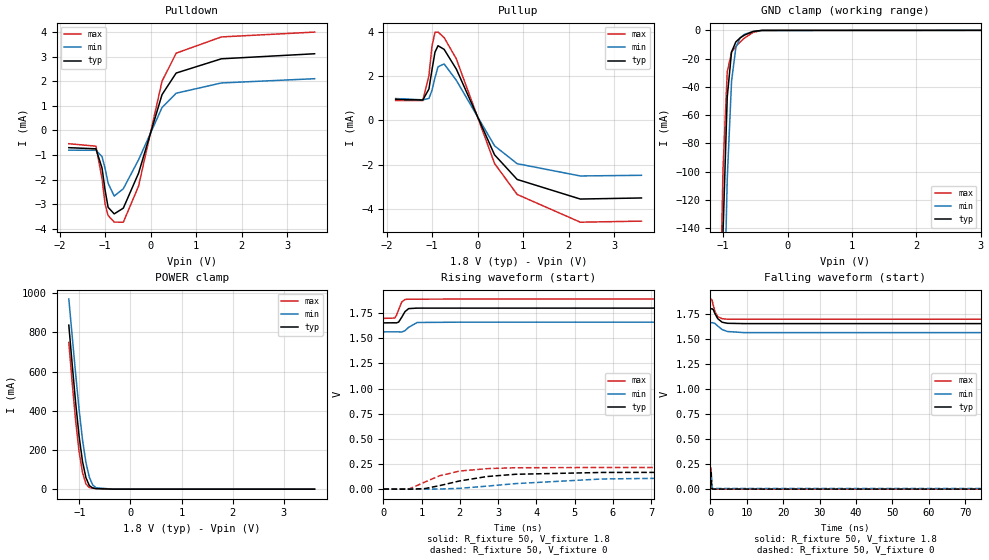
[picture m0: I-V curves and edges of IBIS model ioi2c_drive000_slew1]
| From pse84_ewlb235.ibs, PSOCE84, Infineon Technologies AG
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[Model] ioi2c_drive000_slew1
Model_type I/O
Enable   Active-High
Vinl  =  0.54
Vinh  =  1.26
Vmeas =  0.9
Cref  =  15e-12
| Capacitance   typ   min   max
C_comp   8.55364e-13 8.30808e-13 8.84570e-13
| Variables   typ   min   max
[GND Clamp Reference]   0   0   0
[POWER Clamp Reference]   1.8   1.66   1.89
[Pulldown Reference]   0   0   0
[Pullup Reference]   1.8   1.66   1.89
[Temperature Range]   25   125   -40
[Voltage Range]   1.8   1.66   1.89
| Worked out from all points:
|   slope of the pulldown table from 0 to 0.27 V, typ, clamps not added: 175 ohm
|   slope of the pullup table from 0 to 0.27 V, typ, clamps not added: 228 ohm
|   GND clamp passes 1 mA (typ) near -0.55 V on its own axis
|   POWER clamp passes 1 mA (typ) near -0.55 V on its own axis
|   falling waveform, R_fixture 50, V_fixture 1.8: 20-80 % time 1.44ns typ, 2.16ns min, 1.01ns max; typ from 1.8 V to 1.65 V
|   falling waveform, R_fixture 50, V_fixture 0: 20-80 % time 68.2ps typ, 75.6ps min, 64.3ps max; typ from 0.166 V to 0 V
|   rising waveform, R_fixture 50, V_fixture 1.8: 20-80 % time 135ps typ, 179ps min, 114ps max; typ from 1.65 V to 1.8 V
|   rising waveform, R_fixture 50, V_fixture 0: 20-80 % time 1.45ns typ, 2.62ns min, 924ps max; typ from 0 V to 0.166 V
[GND Clamp]
| Voltage   I(typ)   I(min)   I(max)
-1.204V   -750.5mA   -844.3mA   -692.2mA
-1.07V    -311.8mA   -416.8mA   -250.3mA
-1.003V   -144.6mA   -236.7mA   -99.35mA
-936.6mV  -47.15mA   -105.3mA   -29.57mA
-869.7mV  -15.32mA   -36.11mA   -15.4mA
-802.8mV  -8.178mA   -12.13mA   -11.32mA
-735.9mV  -5.345mA   -5.294mA   -8.218mA
-669mV    -3.361mA   -2.852mA   -5.471mA
-535.2mV  -838.5uA   -772.4uA   -1.486mA
-401.4mV  -47.36uA   -84.85uA   -76.78uA
3.6V      0A         0A         0A
[POWER Clamp]
| Voltage   I(typ)   I(min)   I(max)
-1.204V   837.3mA    970.7mA    749.2mA
-1.137V   634.9mA    778.2mA    540.5mA
-1.07V    440.1mA    587.4mA    346.5mA
-1.003V   270mA      407mA      190.9mA
-936.6mV  141.8mA    252.7mA    85.92mA
-869.7mV  58.74mA    136.5mA    26.66mA
-802.8mV  18.35mA    60.36mA    8.197mA
-735.9mV  5.885mA    21mA       4.755mA
-669mV    2.866mA    6.628mA    3.138mA
-334.5mV  12.31uA    45.7uA     5.857uA
3.6V      0A         0A         0A
[Pulldown]
| Voltage   I(typ)   I(min)   I(max)
-1.8V     -703.5uA   -804.7uA   -543.5uA
-1.204V   -750.4uA   -810.1uA   -642.3uA
-1.07V    -1.533mA   -1.068mA   -1.965mA
-1.003V   -2.436mA   -1.548mA   -2.997mA
-936.6mV  -3.129mA   -2.15mA    -3.46mA
-802.8mV  -3.395mA   -2.671mA   -3.729mA
-602.1mV  -3.161mA   -2.372mA   -3.733mA
-267.6mV  -1.741mA   -1.195mA   -2.266mA
248.3mV   1.454mA    928.2uA    1.997mA
558.6mV   2.33mA     1.51mA     3.138mA
1.552V    2.909mA    1.927mA    3.798mA
3.6V      3.114mA    2.1mA      3.995mA
[Pullup]
| Voltage   I(typ)   I(min)   I(max)
-1.8V     951.6uA    988.4uA    898.4uA
-1.204V   923.4uA    929.7uA    894.6uA
-1.07V    1.418mA    994.1uA    2.027mA
-1.003V   2.286mA    1.356mA    3.351mA
-936.6mV  3.088mA    1.934mA    3.984mA
-869.7mV  3.379mA    2.427mA    3.995mA
-735.9mV  3.214mA    2.555mA    3.747mA
-468.3mV  2.324mA    1.816mA    2.785mA
372.4mV   -1.557mA   -1.149mA   -1.949mA
869mV     -2.67mA    -1.957mA   -3.349mA
2.256V    -3.556mA   -2.512mA   -4.603mA
3.6V      -3.507mA   -2.482mA   -4.555mA
[Ramp]
dV/dt_r   99.4336m/1.45408n  70.1228m/2.6179n  0.128322/0.923527n
dV/dt_f   87.9625m/1.43945n  57.8563m/2.15508n  0.115304/1.01328n
R_load = 50
[Falling Waveform]
R_fixture = 50
V_fixture = 1.8
V_fixture_min = 1.66
V_fixture_max = 1.89
| Time   V(typ)   V(min)   V(max)
0s        1.8V       1.66V      1.89V
260.5ps   1.8V       1.66V      1.898V
490.5ps   1.801V     1.663V     1.887V
814.7ps   1.793V     1.66V      1.838V
1.274ns   1.754V     1.655V     1.774V
2.032ns   1.703V     1.629V     1.723V
3.232ns   1.667V     1.594V     1.702V
4.705ns   1.656V     1.574V     1.697V
9.277ns   1.653V     1.563V     1.697V
800ns     1.653V     1.564V     1.698V
[Falling Waveform]
R_fixture = 50
V_fixture = 0
V_fixture_min = 0
V_fixture_max = 0
| Time   V(typ)   V(min)   V(max)
0s        165.7mV    116.9mV    213.9mV
206.8ps   165.6mV    116.9mV    212.2mV
229ps     165.4mV    116.9mV    185.2mV
271.5ps   164.8mV    116.9mV    82.32mV
313.6ps   114.5mV    116.6mV    31mV
346.5ps   58.21mV    117.3mV    14.56mV
381.3ps   26.77mV    113.7mV    6.74mV
475.2ps   3.513mV    29.3mV     494.8uV
542.3ps   656.7uV    7.037mV    235uV
800ns     16.91nV    963.9nV    7.235nV
[Rising Waveform]
R_fixture = 50
V_fixture = 1.8
V_fixture_min = 1.66
V_fixture_max = 1.89
| Time   V(typ)   V(min)   V(max)
0s        1.653V     1.564V     1.698V
295.6ps   1.654V     1.564V     1.701V
341.2ps   1.653V     1.564V     1.728V
398.2ps   1.661V     1.564V     1.783V
481ps     1.71V      1.562V     1.862V
564.9ps   1.765V     1.576V     1.886V
660.3ps   1.795V     1.609V     1.889V
884.1ps   1.8V       1.657V     1.889V
1.947ns   1.8V       1.66V      1.89V
800ns     1.8V       1.66V      1.89V
[Rising Waveform]
R_fixture = 50
V_fixture = 0
V_fixture_min = 0
V_fixture_max = 0
| Time   V(typ)   V(min)   V(max)
0s        16.91nV    963.7nV    7.235nV
688.1ps   -868.5uV   -900.8uV   3.036mV
1.085ns   4.938mV    -221.7uV   69.95mV
1.469ns   34.26mV    435.7uV    132.4mV
1.994ns   80.83mV    7.366mV    179.3mV
2.711ns   124.9mV    29.17mV    203.3mV
3.455ns   147.2mV    54.25mV    212mV
5.728ns   165.4mV    100.7mV    214.9mV
9.629ns   166.7mV    116.7mV    214.3mV
50ns      165.7mV    116.9mV    213.9mV
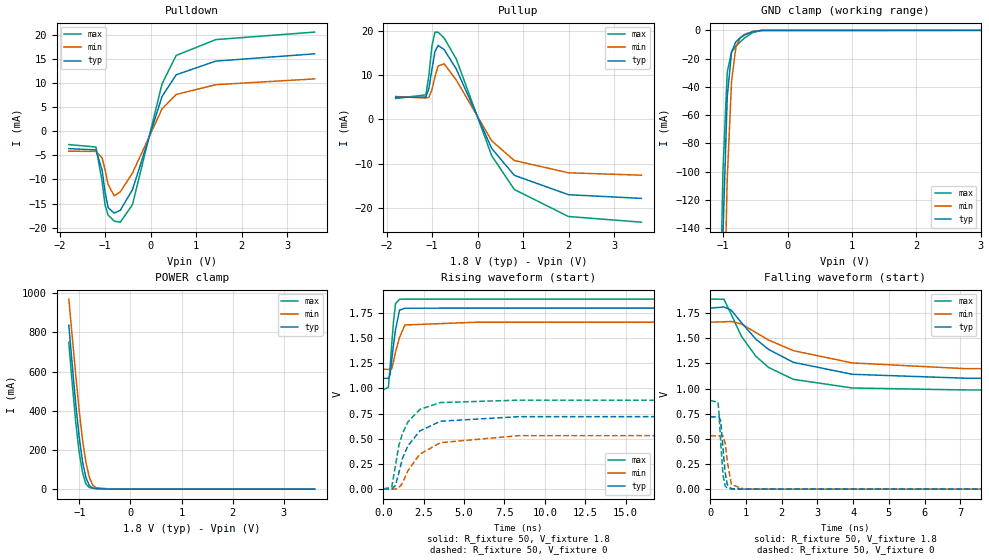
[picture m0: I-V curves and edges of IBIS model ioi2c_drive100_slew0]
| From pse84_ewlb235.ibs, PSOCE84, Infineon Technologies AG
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[Model] ioi2c_drive100_slew0
Model_type I/O
Enable   Active-High
Vinl  =  0.54
Vinh  =  1.26
Vmeas =  0.9
Cref  =  15e-12
| Capacitance   typ   min   max
C_comp   8.55364e-13 8.30808e-13 8.84570e-13
| Variables   typ   min   max
[GND Clamp Reference]   0   0   0
[POWER Clamp Reference]   1.8   1.66   1.89
[Pulldown Reference]   0   0   0
[Pullup Reference]   1.8   1.66   1.89
[Temperature Range]   25   125   -40
[Voltage Range]   1.8   1.66   1.89
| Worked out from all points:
|   slope of the pulldown table from 0 to 0.27 V, typ, clamps not added: 35.3 ohm
|   slope of the pullup table from 0 to 0.27 V, typ, clamps not added: 46.3 ohm
|   GND clamp passes 1 mA (typ) near -0.55 V on its own axis
|   POWER clamp passes 1 mA (typ) near -0.55 V on its own axis
|   falling waveform, R_fixture 50, V_fixture 1.8: 20-80 % time 1.64ns typ, 2.15ns min, 1.21ns max; typ from 1.8 V to 1.1 V
|   falling waveform, R_fixture 50, V_fixture 0: 20-80 % time 103ps typ, 119ps min, 94.2ps max; typ from 0.719 V to 0 V
|   rising waveform, R_fixture 50, V_fixture 1.8: 20-80 % time 331ps typ, 473ps min, 255ps max; typ from 1.1 V to 1.8 V
|   rising waveform, R_fixture 50, V_fixture 0: 20-80 % time 1.31ns typ, 1.65ns min, 975ps max; typ from 0 V to 0.719 V
[GND Clamp]
| Voltage   I(typ)   I(min)   I(max)
-1.204V   -750.5mA   -844.3mA   -692.2mA
-1.07V    -311.8mA   -416.8mA   -250.3mA
-1.003V   -144.6mA   -236.7mA   -99.35mA
-936.6mV  -47.15mA   -105.3mA   -29.57mA
-869.7mV  -15.32mA   -36.11mA   -15.4mA
-802.8mV  -8.178mA   -12.13mA   -11.32mA
-735.9mV  -5.345mA   -5.294mA   -8.218mA
-669mV    -3.361mA   -2.852mA   -5.471mA
-535.2mV  -838.5uA   -772.4uA   -1.486mA
-401.4mV  -47.36uA   -84.85uA   -76.78uA
3.6V      0A         0A         0A
[POWER Clamp]
| Voltage   I(typ)   I(min)   I(max)
-1.204V   837.3mA    970.7mA    749.2mA
-1.137V   634.9mA    778.2mA    540.5mA
-1.07V    440.1mA    587.4mA    346.5mA
-1.003V   270mA      407mA      190.9mA
-936.6mV  141.8mA    252.7mA    85.92mA
-869.7mV  58.74mA    136.5mA    26.66mA
-802.8mV  18.35mA    60.36mA    8.197mA
-735.9mV  5.885mA    21mA       4.755mA
-669mV    2.866mA    6.628mA    3.138mA
-334.5mV  12.31uA    45.7uA     5.857uA
3.6V      0A         0A         0A
[Pulldown]
| Voltage   I(typ)   I(min)   I(max)
-1.8V     -3.608mA   -4.143mA   -2.775mA
-1.204V   -3.867mA   -4.18mA    -3.269mA
-1.07V    -8mA       -5.505mA   -10.32mA
-1.003V   -12.65mA   -8.02mA    -15.35mA
-936.6mV  -15.86mA   -11.04mA   -17.4mA
-802.8mV  -16.98mA   -13.4mA    -18.65mA
-669mV    -16.4mA    -12.58mA   -18.87mA
-401.4mV  -12.13mA   -8.671mA   -15.23mA
248.3mV   7.209mA    4.643mA    9.816mA
558.6mV   11.71mA    7.622mA    15.72mA
1.428V    14.55mA    9.657mA    19.01mA
3.6V      16.06mA    10.86mA    20.57mA
[Pullup]
| Voltage   I(typ)   I(min)   I(max)
-1.8V     5.02mA     5.202mA    4.747mA
-1.137V   5.07mA     4.844mA    5.585mA
-1.07V    7.067mA    5.033mA    10.06mA
-1.003V   11.43mA    6.798mA    16.72mA
-936.6mV  15.41mA    9.704mA    19.82mA
-869.7mV  16.78mA    12.12mA    19.79mA
-735.9mV  15.86mA    12.64mA    18.49mA
-468.3mV  11.44mA    8.947mA    13.7mA
310.3mV   -6.586mA   -4.859mA   -8.233mA
806.9mV   -12.68mA   -9.32mA    -15.89mA
1.996V    -17.07mA   -12.1mA    -22.02mA
3.6V      -17.91mA   -12.65mA   -23.31mA
[Ramp]
dV/dt_r   0.431323/1.30748n  0.318025/1.65257n  0.529265/0.975074n
dV/dt_f   0.41961/1.63536n  0.281431/2.15218n  0.541745/1.20773n
R_load = 50
[Falling Waveform]
R_fixture = 50
V_fixture = 1.8
V_fixture_min = 1.66
V_fixture_max = 1.89
| Time   V(typ)   V(min)   V(max)
0s        1.8V       1.66V      1.89V
382.3ps   1.811V     1.664V     1.888V
583.8ps   1.781V     1.667V     1.74V
871.3ps   1.656V     1.642V     1.521V
1.276ns   1.492V     1.557V     1.321V
1.634ns   1.389V     1.483V     1.21V
2.326ns   1.261V     1.377V     1.092V
3.978ns   1.142V     1.255V     1.006V
7.152ns   1.103V     1.198V     986.2mV
800ns     1.101V     1.191V     987.1mV
[Falling Waveform]
R_fixture = 50
V_fixture = 0
V_fixture_min = 0
V_fixture_max = 0
| Time   V(typ)   V(min)   V(max)
0s        718.9mV    530mV      882.1mV
216.6ps   718.6mV    530mV      862.9mV
244.6ps   719.1mV    530mV      755.5mV
294.5ps   675.9mV    529.9mV    451.7mV
357.4ps   403.5mV    530.7mV    140.7mV
417.6ps   161.8mV    456mV      33.4mV
478ps     44.77mV    273.4mV    7.755mV
592.2ps   4.477mV    45.7mV     1.387mV
946.4ps   865uV      950.9uV    607.2uV
800ns     8.443nV    562.7nV    3.204nV
[Rising Waveform]
R_fixture = 50
V_fixture = 1.8
V_fixture_min = 1.66
V_fixture_max = 1.89
| Time   V(typ)   V(min)   V(max)
0s        1.101V     1.191V     987.1mV
307.7ps   1.101V     1.191V     1.012V
411.2ps   1.137V     1.191V     1.204V
511.2ps   1.273V     1.195V     1.429V
624.6ps   1.433V     1.267V     1.663V
752.6ps   1.586V     1.364V     1.845V
999.3ps   1.78V      1.508V     1.888V
1.33ns    1.799V     1.632V     1.889V
5.857ns   1.8V       1.66V      1.89V
800ns     1.8V       1.66V      1.89V
[Rising Waveform]
R_fixture = 50
V_fixture = 0
V_fixture_min = 0
V_fixture_max = 0
| Time   V(typ)   V(min)   V(max)
0s        8.444nV    562.4nV    3.204nV
516.6ps   -2.074mV   -663.5uV   18.93mV
746.4ps   34.48mV    -1.522mV   230.6mV
955.5ps   159.8mV    10.54mV    432.3mV
1.179ns   304.5mV    59.72mV    550.1mV
1.524ns   430.8mV    182.5mV    669mV
2.261ns   577.7mV    346.9mV    791.9mV
3.534ns   673.9mV    460.7mV    860mV
8.374ns   719.5mV    530.6mV    883.6mV
50ns      718.9mV    530mV      882.1mV
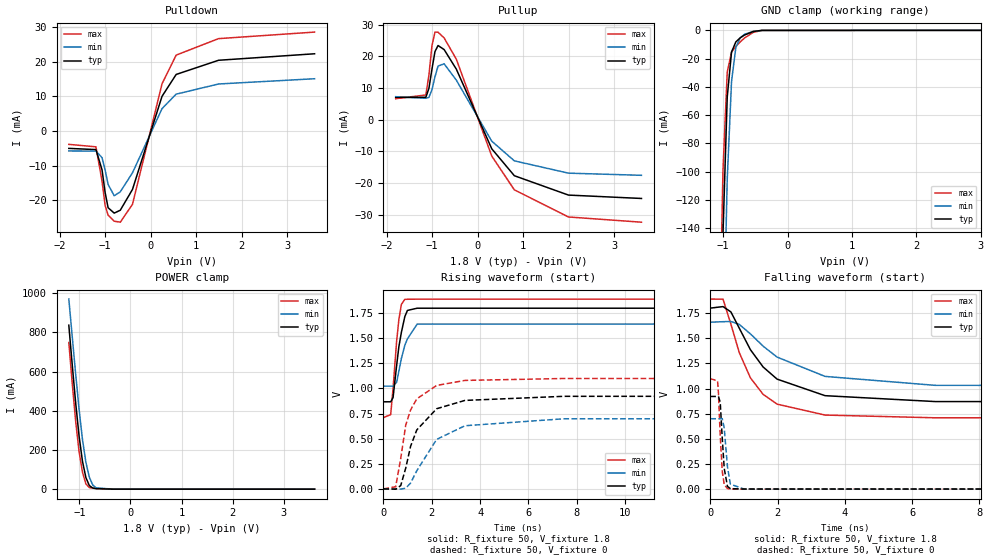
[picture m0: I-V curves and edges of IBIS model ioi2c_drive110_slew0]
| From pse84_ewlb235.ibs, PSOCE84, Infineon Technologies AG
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[Model] ioi2c_drive110_slew0
Model_type I/O
Enable   Active-High
Vinl  =  0.54
Vinh  =  1.26
Vmeas =  0.9
Cref  =  15e-12
| Capacitance   typ   min   max
C_comp   8.55364e-13 8.30808e-13 8.84570e-13
| Variables   typ   min   max
[GND Clamp Reference]   0   0   0
[POWER Clamp Reference]   1.8   1.66   1.89
[Pulldown Reference]   0   0   0
[Pullup Reference]   1.8   1.66   1.89
[Temperature Range]   25   125   -40
[Voltage Range]   1.8   1.66   1.89
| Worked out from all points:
|   slope of the pulldown table from 0 to 0.27 V, typ, clamps not added: 25.3 ohm
|   slope of the pullup table from 0 to 0.27 V, typ, clamps not added: 33.2 ohm
|   GND clamp passes 1 mA (typ) near -0.55 V on its own axis
|   POWER clamp passes 1 mA (typ) near -0.55 V on its own axis
|   falling waveform, R_fixture 50, V_fixture 1.8: 20-80 % time 1.35ns typ, 1.84ns min, 960ps max; typ from 1.8 V to 0.867 V
|   falling waveform, R_fixture 50, V_fixture 0: 20-80 % time 100ps typ, 115ps min, 93ps max; typ from 0.922 V to 0 V
|   rising waveform, R_fixture 50, V_fixture 1.8: 20-80 % time 314ps typ, 442ps min, 241ps max; typ from 0.867 V to 1.8 V
|   rising waveform, R_fixture 50, V_fixture 0: 20-80 % time 944ps typ, 1.3ns min, 660ps max; typ from 0 V to 0.922 V
[GND Clamp]
| Voltage   I(typ)   I(min)   I(max)
-1.204V   -750.5mA   -844.3mA   -692.2mA
-1.07V    -311.8mA   -416.8mA   -250.3mA
-1.003V   -144.6mA   -236.7mA   -99.35mA
-936.6mV  -47.15mA   -105.3mA   -29.57mA
-869.7mV  -15.32mA   -36.11mA   -15.4mA
-802.8mV  -8.178mA   -12.13mA   -11.32mA
-735.9mV  -5.345mA   -5.294mA   -8.218mA
-669mV    -3.361mA   -2.852mA   -5.471mA
-535.2mV  -838.5uA   -772.4uA   -1.486mA
-401.4mV  -47.36uA   -84.85uA   -76.78uA
3.6V      0A         0A         0A
[POWER Clamp]
| Voltage   I(typ)   I(min)   I(max)
-1.204V   837.3mA    970.7mA    749.2mA
-1.137V   634.9mA    778.2mA    540.5mA
-1.07V    440.1mA    587.4mA    346.5mA
-1.003V   270mA      407mA      190.9mA
-936.6mV  141.8mA    252.7mA    85.92mA
-869.7mV  58.74mA    136.5mA    26.66mA
-802.8mV  18.35mA    60.36mA    8.197mA
-735.9mV  5.885mA    21mA       4.755mA
-669mV    2.866mA    6.628mA    3.138mA
-334.5mV  12.31uA    45.7uA     5.857uA
3.6V      0A         0A         0A
[Pulldown]
| Voltage   I(typ)   I(min)   I(max)
-1.8V     -5.031mA   -5.777mA   -3.872mA
-1.204V   -5.388mA   -5.825mA   -4.584mA
-1.07V    -11.24mA   -7.714mA   -14.52mA
-1.003V   -17.74mA   -11.24mA   -21.49mA
-936.6mV  -22.2mA    -15.46mA   -24.36mA
-802.8mV  -23.75mA   -18.74mA   -26.09mA
-669mV    -22.92mA   -17.59mA   -26.38mA
-401.4mV  -16.91mA   -12.1mA    -21.21mA
248.3mV   10.03mA    6.478mA    13.65mA
558.6mV   16.35mA    10.65mA    21.94mA
1.49V     20.45mA    13.59mA    26.71mA
3.6V      22.33mA    15.11mA    28.6mA
[Pullup]
| Voltage   I(typ)   I(min)   I(max)
-1.8V     7.005mA    7.261mA    6.626mA
-1.137V   7.083mA    6.76mA     7.811mA
-1.07V    9.886mA    7.034mA    14.08mA
-1.003V   15.99mA    9.505mA    23.38mA
-936.6mV  21.53mA    13.57mA    27.68mA
-869.7mV  23.43mA    16.94mA    27.64mA
-735.9mV  22.16mA    17.65mA    25.83mA
-468.3mV  15.98mA    12.5mA     19.13mA
310.3mV   -9.196mA   -6.788mA   -11.49mA
806.9mV   -17.72mA   -13.02mA   -22.19mA
1.996V    -23.84mA   -16.91mA   -30.76mA
3.6V      -24.91mA   -17.59mA   -32.41mA
[Ramp]
dV/dt_r   0.553161/0.943874n  0.420209/1.30167n  0.659218/0.659828n
dV/dt_f   0.559864/1.34707n  0.382426/1.83895n  0.708163/0.960081n
R_load = 50
[Falling Waveform]
R_fixture = 50
V_fixture = 1.8
V_fixture_min = 1.66
V_fixture_max = 1.89
| Time   V(typ)   V(min)   V(max)
0s        1.8V       1.66V      1.89V
379.1ps   1.815V     1.665V     1.889V
613.8ps   1.762V     1.667V     1.64V
863.3ps   1.6V       1.638V     1.357V
1.193ns   1.387V     1.544V     1.107V
1.571ns   1.215V     1.422V     942.9mV
1.987ns   1.094V     1.313V     845.3mV
3.413ns   929.5mV    1.121V     736.7mV
6.699ns   870.8mV    1.032V     709.5mV
800ns     866.9mV    1.023V     709.7mV
[Falling Waveform]
R_fixture = 50
V_fixture = 0
V_fixture_min = 0
V_fixture_max = 0
| Time   V(typ)   V(min)   V(max)
0s        921.9mV    700.3mV    1.099V
217.2ps   921.7mV    700.3mV    1.076V
243.4ps   922.3mV    700.3mV    953.5mV
295.8ps   863.4mV    700.2mV    533.5mV
355.4ps   510.1mV    701.5mV    179.9mV
415.1ps   206.1mV    607mV      44.16mV
511.1ps   27.4mV     222.3mV    5.209mV
597.6ps   5.27mV     50.07mV    1.91mV
1.005ns   1.01mV     1.294mV    657.3uV
800ns     6.766nV    466.7nV    2.504nV
[Rising Waveform]
R_fixture = 50
V_fixture = 1.8
V_fixture_min = 1.66
V_fixture_max = 1.89
| Time   V(typ)   V(min)   V(max)
0s        866.9mV    1.023V     709.7mV
301.7ps   867.1mV    1.023V     739.3mV
399.2ps   908.4mV    1.023V     998.1mV
548ps     1.231V     1.063V     1.473V
640.1ps   1.416V     1.172V     1.686V
743.6ps   1.558V     1.299V     1.836V
885.5ps   1.715V     1.429V     1.887V
994.1ps   1.777V     1.494V     1.888V
1.398ns   1.799V     1.641V     1.889V
800ns     1.8V       1.66V      1.89V
[Rising Waveform]
R_fixture = 50
V_fixture = 0
V_fixture_min = 0
V_fixture_max = 0
| Time   V(typ)   V(min)   V(max)
0s        6.767nV    466.5nV    2.506nV
509.1ps   -2.87mV    -992.1uV   21.44mV
716.8ps   32.64mV    -2.311mV   303.4mV
925.9ps   209.1mV    7.165mV    637.7mV
1.125ns   424.3mV    57.92mV    785.9mV
1.382ns   587.4mV    181.5mV    896.5mV
2.203ns   798.1mV    492.8mV    1.03V
3.372ns   880.8mV    628.6mV    1.08V
7.456ns   921.6mV    697.9mV    1.099V
50ns      921.9mV    700.3mV    1.099V
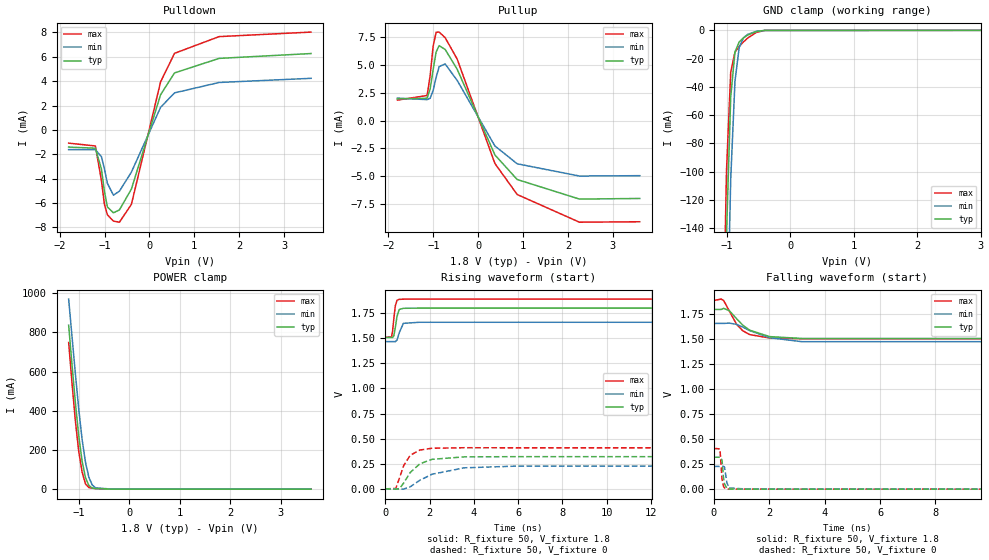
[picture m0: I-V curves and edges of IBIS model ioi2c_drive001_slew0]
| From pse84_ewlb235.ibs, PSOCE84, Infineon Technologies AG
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[Model] ioi2c_drive001_slew0
Model_type I/O
Enable   Active-High
Vinl  =  0.54
Vinh  =  1.26
Vmeas =  0.9
Cref  =  15e-12
| Capacitance   typ   min   max
C_comp   8.55364e-13 8.30808e-13 8.84570e-13
| Variables   typ   min   max
[GND Clamp Reference]   0   0   0
[POWER Clamp Reference]   1.8   1.66   1.89
[Pulldown Reference]   0   0   0
[Pullup Reference]   1.8   1.66   1.89
[Temperature Range]   25   125   -40
[Voltage Range]   1.8   1.66   1.89
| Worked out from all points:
|   slope of the pulldown table from 0 to 0.27 V, typ, clamps not added: 88 ohm
|   slope of the pullup table from 0 to 0.27 V, typ, clamps not added: 115 ohm
|   GND clamp passes 1 mA (typ) near -0.55 V on its own axis
|   POWER clamp passes 1 mA (typ) near -0.55 V on its own axis
|   falling waveform, R_fixture 50, V_fixture 1.8: 20-80 % time 765ps typ, 1.16ns min, 545ps max; typ from 1.8 V to 1.51 V
|   falling waveform, R_fixture 50, V_fixture 0: 20-80 % time 68.2ps typ, 75.4ps min, 64.3ps max; typ from 0.32 V to 0 V
|   rising waveform, R_fixture 50, V_fixture 1.8: 20-80 % time 129ps typ, 168ps min, 111ps max; typ from 1.51 V to 1.8 V
|   rising waveform, R_fixture 50, V_fixture 0: 20-80 % time 768ps typ, 1.4ns min, 488ps max; typ from 0 V to 0.32 V
[GND Clamp]
| Voltage   I(typ)   I(min)   I(max)
-1.204V   -750.5mA   -844.3mA   -692.2mA
-1.07V    -311.8mA   -416.8mA   -250.3mA
-1.003V   -144.6mA   -236.7mA   -99.35mA
-936.6mV  -47.15mA   -105.3mA   -29.57mA
-869.7mV  -15.32mA   -36.11mA   -15.4mA
-802.8mV  -8.178mA   -12.13mA   -11.32mA
-735.9mV  -5.345mA   -5.294mA   -8.218mA
-669mV    -3.361mA   -2.852mA   -5.471mA
-535.2mV  -838.5uA   -772.4uA   -1.486mA
-401.4mV  -47.36uA   -84.85uA   -76.78uA
3.6V      0A         0A         0A
[POWER Clamp]
| Voltage   I(typ)   I(min)   I(max)
-1.204V   837.3mA    970.7mA    749.2mA
-1.137V   634.9mA    778.2mA    540.5mA
-1.07V    440.1mA    587.4mA    346.5mA
-1.003V   270mA      407mA      190.9mA
-936.6mV  141.8mA    252.7mA    85.92mA
-869.7mV  58.74mA    136.5mA    26.66mA
-802.8mV  18.35mA    60.36mA    8.197mA
-735.9mV  5.885mA    21mA       4.755mA
-669mV    2.866mA    6.628mA    3.138mA
-334.5mV  12.31uA    45.7uA     5.857uA
3.6V      0A         0A         0A
[Pulldown]
| Voltage   I(typ)   I(min)   I(max)
-1.8V     -1.409mA   -1.614mA   -1.087mA
-1.204V   -1.504mA   -1.625mA   -1.317mA
-1.07V    -3.21mA    -2.196mA   -4.15mA
-1.003V   -5.04mA    -3.191mA   -6.111mA
-936.6mV  -6.327mA   -4.389mA   -6.969mA
-802.8mV  -6.804mA   -5.354mA   -7.487mA
-669mV    -6.567mA   -5.03mA    -7.575mA
-401.4mV  -4.854mA   -3.463mA   -6.107mA
248.3mV   2.887mA    1.855mA    3.943mA
558.6mV   4.677mA    3.039mA    6.285mA
1.552V    5.87mA     3.893mA    7.658mA
3.6V      6.268mA    4.234mA    8.029mA
[Pullup]
| Voltage   I(typ)   I(min)   I(max)
-1.8V     1.938mA    2.011mA    1.831mA
-1.137V   2mA        1.875mA    2.246mA
-1.07V    2.828mA    1.994mA    4.035mA
-1.003V   4.559mA    2.708mA    6.673mA
-936.6mV  6.148mA    3.862mA    7.917mA
-869.7mV  6.714mA    4.836mA    7.931mA
-735.9mV  6.376mA    5.074mA    7.432mA
-468.3mV  4.604mA    3.601mA    5.514mA
372.4mV   -3.082mA   -2.277mA   -3.851mA
869mV     -5.289mA   -3.879mA   -6.633mA
2.256V    -7.043mA   -4.976mA   -9.115mA
3.6V      -6.988mA   -4.944mA   -9.076mA
[Ramp]
dV/dt_r   0.191949/0.768196n  0.136595/1.40401n  0.245175/0.488465n
dV/dt_f   0.175408/0.764687n  0.115857/1.15646n  0.229172/0.5453n
R_load = 50
[Falling Waveform]
R_fixture = 50
V_fixture = 1.8
V_fixture_min = 1.66
V_fixture_max = 1.89
| Time   V(typ)   V(min)   V(max)
0s        1.8V       1.66V      1.89V
258.7ps   1.8V       1.66V      1.904V
348.1ps   1.811V     1.66V      1.89V
551.1ps   1.788V     1.663V     1.786V
810.9ps   1.709V     1.651V     1.653V
1.037ns   1.643V     1.624V     1.587V
1.291ns   1.592V     1.588V     1.548V
2.011ns   1.528V     1.517V     1.514V
3.179ns   1.509V     1.477V     1.507V
800ns     1.508V     1.467V     1.508V
[Falling Waveform]
R_fixture = 50
V_fixture = 0
V_fixture_min = 0
V_fixture_max = 0
| Time   V(typ)   V(min)   V(max)
0s        319.9mV    227.7mV    408.6mV
207.6ps   319.8mV    227.7mV    403.2mV
225.6ps   319.5mV    227.7mV    362mV
288.8ps   292.2mV    227.6mV    102.3mV
343ps     117.2mV    228.3mV    29.51mV
378.6ps   52.96mV    221.6mV    12.69mV
468ps     7.9mV      63.2mV     2.033mV
543.4ps   1.92mV     12.84mV    1.094mV
1.204ns   370.1uV    485.7uV    257.4uV
800ns     13.55nV    818.7nV    5.533nV
[Rising Waveform]
R_fixture = 50
V_fixture = 1.8
V_fixture_min = 1.66
V_fixture_max = 1.89
| Time   V(typ)   V(min)   V(max)
0s        1.508V     1.467V     1.508V
285.9ps   1.508V     1.467V     1.515V
330.1ps   1.507V     1.467V     1.571V
388.9ps   1.525V     1.467V     1.699V
455.2ps   1.609V     1.466V     1.824V
531.7ps   1.718V     1.482V     1.878V
629.3ps   1.786V     1.553V     1.887V
816.7ps   1.798V     1.648V     1.889V
1.538ns   1.8V       1.659V     1.89V
800ns     1.8V       1.66V      1.89V
[Rising Waveform]
R_fixture = 50
V_fixture = 0
V_fixture_min = 0
V_fixture_max = 0
| Time   V(typ)   V(min)   V(max)
0s        13.55nV    818.5nV    5.533nV
475.7ps   -2.757mV   -15.86uV   4.661mV
645.6ps   3.654mV    -1.886mV   110.4mV
828.7ps   57.71mV    -1.53mV    230.9mV
1.128ns   163.4mV    20.63mV    334.9mV
1.56ns    249.5mV    85.67mV    386.6mV
2.11ns    294.4mV    145.8mV    404.7mV
3.569ns   319mV      209.9mV    409.8mV
6.018ns   320.8mV    227.3mV    408.9mV
50ns      319.9mV    227.7mV    408.6mV
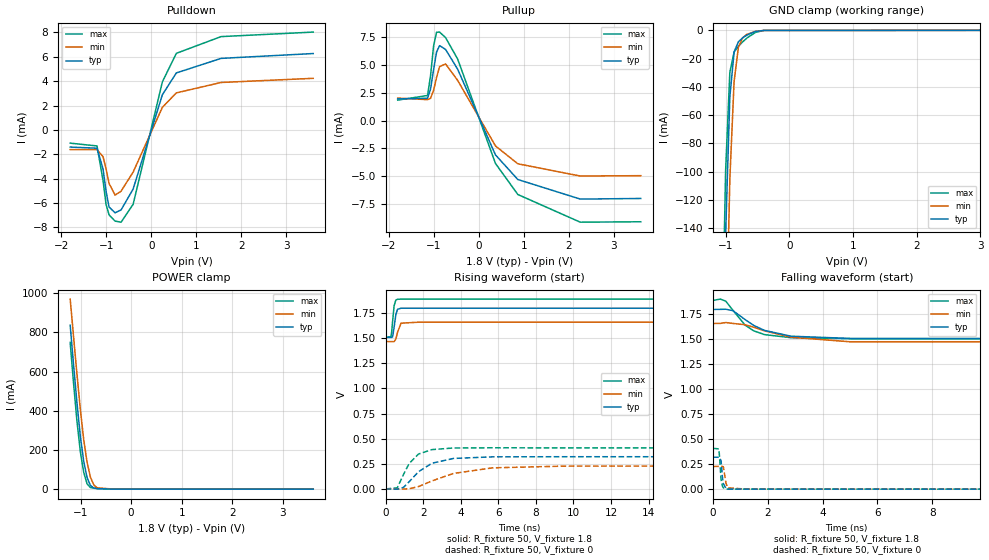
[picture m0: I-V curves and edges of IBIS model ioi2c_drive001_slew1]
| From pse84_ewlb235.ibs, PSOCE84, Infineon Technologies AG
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[Model] ioi2c_drive001_slew1
Model_type I/O
Enable   Active-High
Vinl  =  0.54
Vinh  =  1.26
Vmeas =  0.9
Cref  =  15e-12
| Capacitance   typ   min   max
C_comp   8.55364e-13 8.30808e-13 8.84570e-13
| Variables   typ   min   max
[GND Clamp Reference]   0   0   0
[POWER Clamp Reference]   1.8   1.66   1.89
[Pulldown Reference]   0   0   0
[Pullup Reference]   1.8   1.66   1.89
[Temperature Range]   25   125   -40
[Voltage Range]   1.8   1.66   1.89
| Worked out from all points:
|   slope of the pulldown table from 0 to 0.27 V, typ, clamps not added: 88 ohm
|   slope of the pullup table from 0 to 0.27 V, typ, clamps not added: 115 ohm
|   GND clamp passes 1 mA (typ) near -0.55 V on its own axis
|   POWER clamp passes 1 mA (typ) near -0.55 V on its own axis
|   falling waveform, R_fixture 50, V_fixture 1.8: 20-80 % time 1.18ns typ, 1.78ns min, 827ps max; typ from 1.8 V to 1.51 V
|   falling waveform, R_fixture 50, V_fixture 0: 20-80 % time 68ps typ, 75.3ps min, 64.1ps max; typ from 0.32 V to 0 V
|   rising waveform, R_fixture 50, V_fixture 1.8: 20-80 % time 129ps typ, 168ps min, 112ps max; typ from 1.51 V to 1.8 V
|   rising waveform, R_fixture 50, V_fixture 0: 20-80 % time 1.25ns typ, 2.29ns min, 783ps max; typ from 0 V to 0.32 V
[GND Clamp]
| Voltage   I(typ)   I(min)   I(max)
-1.204V   -750.5mA   -844.3mA   -692.2mA
-1.07V    -311.8mA   -416.8mA   -250.3mA
-1.003V   -144.6mA   -236.7mA   -99.35mA
-936.6mV  -47.15mA   -105.3mA   -29.57mA
-869.7mV  -15.32mA   -36.11mA   -15.4mA
-802.8mV  -8.178mA   -12.13mA   -11.32mA
-735.9mV  -5.345mA   -5.294mA   -8.218mA
-669mV    -3.361mA   -2.852mA   -5.471mA
-535.2mV  -838.5uA   -772.4uA   -1.486mA
-401.4mV  -47.36uA   -84.85uA   -76.78uA
3.6V      0A         0A         0A
[POWER Clamp]
| Voltage   I(typ)   I(min)   I(max)
-1.204V   837.3mA    970.7mA    749.2mA
-1.137V   634.9mA    778.2mA    540.5mA
-1.07V    440.1mA    587.4mA    346.5mA
-1.003V   270mA      407mA      190.9mA
-936.6mV  141.8mA    252.7mA    85.92mA
-869.7mV  58.74mA    136.5mA    26.66mA
-802.8mV  18.35mA    60.36mA    8.197mA
-735.9mV  5.885mA    21mA       4.755mA
-669mV    2.866mA    6.628mA    3.138mA
-334.5mV  12.31uA    45.7uA     5.857uA
3.6V      0A         0A         0A
[Pulldown]
| Voltage   I(typ)   I(min)   I(max)
-1.8V     -1.409mA   -1.614mA   -1.087mA
-1.204V   -1.504mA   -1.625mA   -1.317mA
-1.07V    -3.21mA    -2.196mA   -4.15mA
-1.003V   -5.04mA    -3.191mA   -6.111mA
-936.6mV  -6.327mA   -4.389mA   -6.969mA
-802.8mV  -6.804mA   -5.354mA   -7.487mA
-669mV    -6.567mA   -5.03mA    -7.575mA
-401.4mV  -4.854mA   -3.463mA   -6.107mA
248.3mV   2.887mA    1.855mA    3.943mA
558.6mV   4.677mA    3.039mA    6.285mA
1.552V    5.87mA     3.893mA    7.658mA
3.6V      6.268mA    4.234mA    8.029mA
[Pullup]
| Voltage   I(typ)   I(min)   I(max)
-1.8V     1.938mA    2.011mA    1.831mA
-1.137V   2mA        1.875mA    2.246mA
-1.07V    2.828mA    1.994mA    4.035mA
-1.003V   4.56mA     2.708mA    6.673mA
-936.6mV  6.149mA    3.862mA    7.917mA
-869.7mV  6.715mA    4.836mA    7.931mA
-735.9mV  6.376mA    5.073mA    7.432mA
-468.3mV  4.604mA    3.601mA    5.514mA
372.4mV   -3.082mA   -2.277mA   -3.851mA
869mV     -5.289mA   -3.879mA   -6.633mA
2.256V    -7.043mA   -4.976mA   -9.115mA
3.6V      -6.988mA   -4.944mA   -9.076mA
[Ramp]
dV/dt_r   0.191949/1.24577n  0.13659/2.28761n  0.245175/0.783008n
dV/dt_f   0.175408/1.17803n  0.115856/1.78131n  0.229172/0.827432n
R_load = 50
[Falling Waveform]
R_fixture = 50
V_fixture = 1.8
V_fixture_min = 1.66
V_fixture_max = 1.89
| Time   V(typ)   V(min)   V(max)
0s        1.8V       1.66V      1.89V
260.4ps   1.801V     1.66V      1.904V
464.8ps   1.802V     1.669V     1.883V
722.1ps   1.788V     1.66V      1.792V
1.167ns   1.699V     1.647V     1.644V
1.483ns   1.64V      1.622V     1.586V
1.878ns   1.59V      1.585V     1.548V
2.848ns   1.532V     1.522V     1.517V
5.059ns   1.509V     1.475V     1.507V
800ns     1.508V     1.467V     1.508V
[Falling Waveform]
R_fixture = 50
V_fixture = 0
V_fixture_min = 0
V_fixture_max = 0
| Time   V(typ)   V(min)   V(max)
0s        319.9mV    227.7mV    408.6mV
207.6ps   319.8mV    227.7mV    403.5mV
228ps     319.6mV    227.7mV    354.2mV
291.7ps   286mV      227.5mV    95.77mV
341.5ps   121.5mV    228.3mV    30.38mV
376.1ps   56.02mV    223.5mV    13.66mV
474.7ps   6.562mV    54.94mV    1.687mV
542.7ps   1.515mV    12.92mV    971.7uV
1.22ns    445.4uV    444.5uV    352.3uV
800ns     13.55nV    818.7nV    5.533nV
[Rising Waveform]
R_fixture = 50
V_fixture = 1.8
V_fixture_min = 1.66
V_fixture_max = 1.89
| Time   V(typ)   V(min)   V(max)
0s        1.508V     1.467V     1.508V
288.2ps   1.508V     1.467V     1.516V
325.6ps   1.508V     1.467V     1.563V
374.1ps   1.514V     1.467V     1.664V
454.3ps   1.607V     1.466V     1.822V
547.4ps   1.734V     1.491V     1.88V
637ps     1.788V     1.559V     1.888V
826ps     1.799V     1.65V      1.889V
1.779ns   1.799V     1.66V      1.89V
800ns     1.8V       1.66V      1.89V
[Rising Waveform]
R_fixture = 50
V_fixture = 0
V_fixture_min = 0
V_fixture_max = 0
| Time   V(typ)   V(min)   V(max)
0s        13.55nV    818.5nV    5.533nV
625.2ps   -2.195mV   -1.715mV   11.3mV
963.3ps   16.45mV    -761.5uV   146.7mV
1.257ns   71.44mV    1.689mV    253.7mV
1.753ns   171.3mV    23.29mV    347.1mV
2.471ns   256.2mV    80.04mV    391.7mV
3.614ns   303.6mV    154.3mV    407.6mV
5.696ns   319.6mV    210mV      409.6mV
9.573ns   320.8mV    227.5mV    409mV
50ns      319.9mV    227.7mV    408.6mV
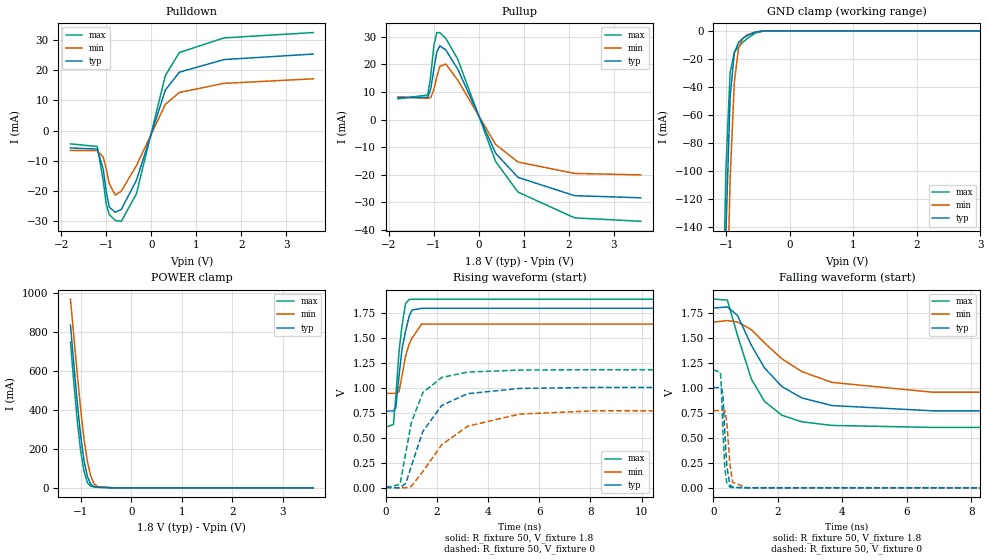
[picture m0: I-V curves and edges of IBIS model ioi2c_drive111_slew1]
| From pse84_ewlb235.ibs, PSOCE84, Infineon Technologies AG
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[Model] ioi2c_drive111_slew1
Model_type I/O
Enable   Active-High
Vinl  =  0.54
Vinh  =  1.26
Vmeas =  0.9
Cref  =  15e-12
| Capacitance   typ   min   max
C_comp   8.55364e-13 8.30808e-13 8.84570e-13
| Variables   typ   min   max
[GND Clamp Reference]   0   0   0
[POWER Clamp Reference]   1.8   1.66   1.89
[Pulldown Reference]   0   0   0
[Pullup Reference]   1.8   1.66   1.89
[Temperature Range]   25   125   -40
[Voltage Range]   1.8   1.66   1.89
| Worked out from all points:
|   slope of the pulldown table from 0 to 0.27 V, typ, clamps not added: 22.3 ohm
|   slope of the pullup table from 0 to 0.27 V, typ, clamps not added: 29.1 ohm
|   GND clamp passes 1 mA (typ) near -0.55 V on its own axis
|   POWER clamp passes 1 mA (typ) near -0.55 V on its own axis
|   falling waveform, R_fixture 50, V_fixture 1.8: 20-80 % time 1.36ns typ, 1.94ns min, 931ps max; typ from 1.8 V to 0.767 V
|   falling waveform, R_fixture 50, V_fixture 0: 20-80 % time 101ps typ, 115ps min, 93.9ps max; typ from 1 V to 0 V
|   rising waveform, R_fixture 50, V_fixture 1.8: 20-80 % time 327ps typ, 445ps min, 259ps max; typ from 0.767 V to 1.8 V
|   rising waveform, R_fixture 50, V_fixture 0: 20-80 % time 1.11ns typ, 1.8ns min, 708ps max; typ from 0 V to 1 V
[GND Clamp]
| Voltage   I(typ)   I(min)   I(max)
-1.204V   -750.5mA   -844.3mA   -692.2mA
-1.07V    -311.8mA   -416.8mA   -250.3mA
-1.003V   -144.6mA   -236.7mA   -99.35mA
-936.6mV  -47.15mA   -105.3mA   -29.57mA
-869.7mV  -15.32mA   -36.11mA   -15.4mA
-802.8mV  -8.178mA   -12.13mA   -11.32mA
-735.9mV  -5.345mA   -5.294mA   -8.218mA
-669mV    -3.361mA   -2.852mA   -5.471mA
-535.2mV  -838.5uA   -772.4uA   -1.486mA
-401.4mV  -47.36uA   -84.85uA   -76.78uA
3.6V      0A         0A         0A
[POWER Clamp]
| Voltage   I(typ)   I(min)   I(max)
-1.204V   837.3mA    970.7mA    749.2mA
-1.137V   634.9mA    778.2mA    540.5mA
-1.07V    440.1mA    587.4mA    346.5mA
-1.003V   270mA      407mA      190.9mA
-936.6mV  141.8mA    252.7mA    85.92mA
-869.7mV  58.74mA    136.5mA    26.66mA
-802.8mV  18.35mA    60.36mA    8.197mA
-735.9mV  5.885mA    21mA       4.755mA
-669mV    2.866mA    6.628mA    3.138mA
-334.5mV  12.31uA    45.7uA     5.857uA
3.6V      0A         0A         0A
[Pulldown]
| Voltage   I(typ)   I(min)   I(max)
-1.8V     -5.733mA   -6.58mA    -4.413mA
-1.204V   -6.136mA   -6.633mA   -5.256mA
-1.07V    -12.91mA   -8.837mA   -16.72mA
-1.003V   -20.35mA   -12.88mA   -24.6mA
-936.6mV  -25.37mA   -17.69mA   -27.84mA
-802.8mV  -27.11mA   -21.39mA   -29.8mA
-669mV    -26.13mA   -20.06mA   -30.09mA
-334.5mV  -16.53mA   -11.66mA   -21.01mA
310.3mV   13.46mA    8.709mA    18.26mA
620.7mV   19.37mA    12.66mA    25.9mA
1.614V    23.57mA    15.67mA    30.76mA
3.6V      25.4mA     17.19mA    32.53mA
[Pullup]
| Voltage   I(typ)   I(min)   I(max)
-1.8V     7.983mA    8.276mA    7.55mA
-1.137V   8.081mA    7.705mA    8.92mA
-1.07V    11.29mA    8.026mA    16.09mA
-1.003V   18.26mA    10.85mA    26.69mA
-936.6mV  24.58mA    15.49mA    31.57mA
-869.7mV  26.74mA    19.33mA    31.53mA
-735.9mV  25.28mA    20.15mA    29.47mA
-468.3mV  18.22mA    14.26mA    21.82mA
372.4mV   -12.19mA   -9.009mA   -15.2mA
869mV     -20.94mA   -15.36mA   -26.26mA
2.126V    -27.56mA   -19.51mA   -35.61mA
3.6V      -28.34mA   -20.03mA   -36.86mA
[Ramp]
dV/dt_r   0.6024/1.11321n  0.464598/1.79993n  0.708544/0.707904n
dV/dt_f   0.619731/1.36384n  0.429003/1.94005n  0.77075/0.931107n
R_load = 50
[Falling Waveform]
R_fixture = 50
V_fixture = 1.8
V_fixture_min = 1.66
V_fixture_max = 1.89
| Time   V(typ)   V(min)   V(max)
0s        1.8V       1.66V      1.89V
433.9ps   1.812V     1.675V     1.88V
749.6ps   1.726V     1.661V     1.525V
1.182ns   1.425V     1.584V     1.087V
1.588ns   1.2V       1.451V     865.3mV
2.126ns   1.014V     1.292V     726.9mV
2.744ns   900.4mV    1.164V     661.5mV
3.678ns   824mV      1.056V     625.2mV
6.808ns   771.3mV    957.5mV    605.3mV
800ns     767.1mV    945mV      605.4mV
[Falling Waveform]
R_fixture = 50
V_fixture = 0
V_fixture_min = 0
V_fixture_max = 0
| Time   V(typ)   V(min)   V(max)
0s        1.004V     774.3mV    1.181V
218.3ps   1.004V     774.3mV    1.157V
242.6ps   1.004V     774.3mV    1.031V
294.9ps   945.1mV    774.2mV    575.2mV
355.3ps   548.4mV    776mV      197.3mV
416.5ps   218.4mV    662.8mV    49.87mV
510.7ps   30.34mV    241.1mV    7.778mV
596.5ps   5.962mV    56.41mV    2.626mV
1.035ns   1.202mV    1.371mV    756uV
800ns     6.177nV    431nV      2.268nV
[Rising Waveform]
R_fixture = 50
V_fixture = 1.8
V_fixture_min = 1.66
V_fixture_max = 1.89
| Time   V(typ)   V(min)   V(max)
0s        767.1mV    945mV      605.4mV
297.9ps   767.3mV    945mV      633mV
388.8ps   800.7mV    945.1mV    906.7mV
515.5ps   1.118V     961.5mV    1.363V
629.7ps   1.385V     1.117V     1.619V
771.5ps   1.569V     1.318V     1.846V
914.2ps   1.719V     1.44V      1.887V
1.024ns   1.78V      1.5V       1.888V
1.402ns   1.798V     1.639V     1.889V
800ns     1.8V       1.66V      1.89V
[Rising Waveform]
R_fixture = 50
V_fixture = 0
V_fixture_min = 0
V_fixture_max = 0
| Time   V(typ)   V(min)   V(max)
0s        6.178nV    430.8nV    2.27nV
555.4ps   -3.541mV   -1.879mV   31.56mV
784.9ps   44.32mV    -2.662mV   354.8mV
994.1ps   211.4mV    11.25mV    649.3mV
1.447ns   563.1mV    159.3mV    951.5mV
2.188ns   823.7mV    429.9mV    1.104V
3.199ns   941.5mV    615.2mV    1.158V
5.223ns   994mV      736.4mV    1.178V
8.199ns   1.004V     769.8mV    1.182V
50ns      1.004V     774.3mV    1.181V
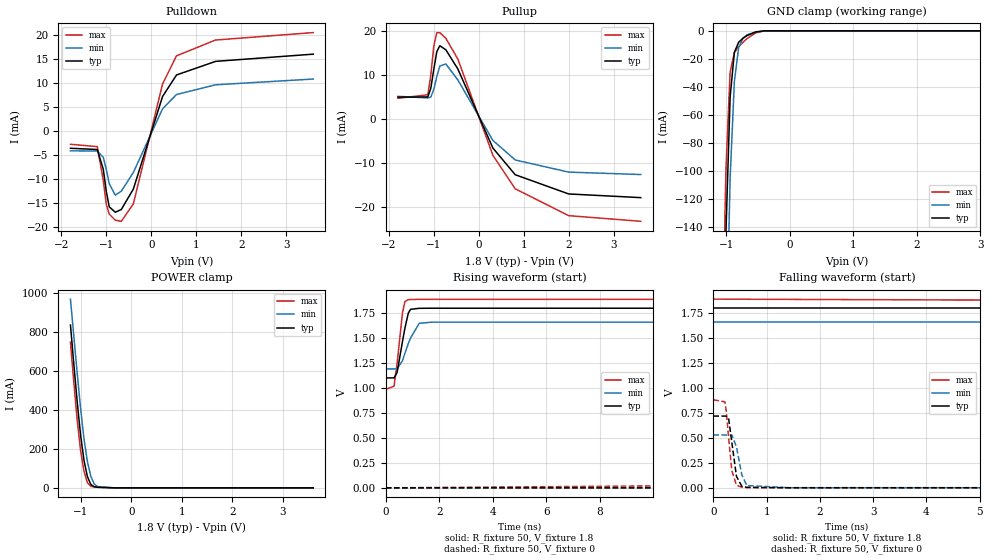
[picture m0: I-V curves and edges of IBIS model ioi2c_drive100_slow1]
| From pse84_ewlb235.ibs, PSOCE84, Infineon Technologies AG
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[Model] ioi2c_drive100_slow1
Model_type I/O
Enable   Active-High
Vinl  =  0.54
Vinh  =  1.26
Vmeas =  0.9
Cref  =  15e-12
| Capacitance   typ   min   max
C_comp   8.55364e-13 8.30808e-13 8.84570e-13
| Variables   typ   min   max
[GND Clamp Reference]   0   0   0
[POWER Clamp Reference]   1.8   1.66   1.89
[Pulldown Reference]   0   0   0
[Pullup Reference]   1.8   1.66   1.89
[Temperature Range]   25   125   -40
[Voltage Range]   1.8   1.66   1.89
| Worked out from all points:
|   slope of the pulldown table from 0 to 0.27 V, typ, clamps not added: 35.3 ohm
|   slope of the pullup table from 0 to 0.27 V, typ, clamps not added: 46.3 ohm
|   GND clamp passes 1 mA (typ) near -0.55 V on its own axis
|   POWER clamp passes 1 mA (typ) near -0.55 V on its own axis
|   falling waveform, R_fixture 50, V_fixture 1.8: 20-80 % time 82.9ns typ, 123ns min, 48.7ns max; typ from 1.8 V to 1.1 V
|   falling waveform, R_fixture 50, V_fixture 0: 20-80 % time 101ps typ, 118ps min, 92.1ps max; typ from 0.719 V to 0 V
|   rising waveform, R_fixture 50, V_fixture 1.8: 20-80 % time 277ps typ, 399ps min, 214ps max; typ from 1.1 V to 1.8 V
|   rising waveform, R_fixture 50, V_fixture 0: 20-80 % time 90.7ns typ, 135ns min, 54.9ns max; typ from 0 V to 0.719 V
[GND Clamp]
| Voltage   I(typ)   I(min)   I(max)
-1.204V   -750.5mA   -844.3mA   -692.2mA
-1.07V    -311.8mA   -416.8mA   -250.3mA
-1.003V   -144.6mA   -236.7mA   -99.35mA
-936.6mV  -47.15mA   -105.3mA   -29.57mA
-869.7mV  -15.32mA   -36.11mA   -15.4mA
-802.8mV  -8.178mA   -12.13mA   -11.32mA
-735.9mV  -5.345mA   -5.294mA   -8.218mA
-669mV    -3.361mA   -2.852mA   -5.471mA
-535.2mV  -838.5uA   -772.4uA   -1.486mA
-401.4mV  -47.36uA   -84.85uA   -76.78uA
3.6V      0A         0A         0A
[POWER Clamp]
| Voltage   I(typ)   I(min)   I(max)
-1.204V   837.3mA    970.7mA    749.2mA
-1.137V   634.9mA    778.2mA    540.5mA
-1.07V    440.1mA    587.4mA    346.5mA
-1.003V   270mA      407mA      190.9mA
-936.6mV  141.8mA    252.7mA    85.92mA
-869.7mV  58.74mA    136.5mA    26.66mA
-802.8mV  18.35mA    60.36mA    8.197mA
-735.9mV  5.885mA    21mA       4.755mA
-669mV    2.866mA    6.628mA    3.138mA
-334.5mV  12.31uA    45.7uA     5.857uA
3.6V      0A         0A         0A
[Pulldown]
| Voltage   I(typ)   I(min)   I(max)
-1.8V     -3.608mA   -4.144mA   -2.775mA
-1.204V   -3.866mA   -4.182mA   -3.264mA
-1.07V    -7.998mA   -5.506mA   -10.31mA
-1.003V   -12.65mA   -8.022mA   -15.33mA
-936.6mV  -15.86mA   -11.04mA   -17.39mA
-802.8mV  -16.98mA   -13.4mA    -18.64mA
-669mV    -16.4mA    -12.58mA   -18.87mA
-401.4mV  -12.13mA   -8.67mA    -15.23mA
248.3mV   7.209mA    4.642mA    9.816mA
558.6mV   11.71mA    7.621mA    15.72mA
1.428V    14.55mA    9.656mA    19.01mA
3.6V      16.06mA    10.86mA    20.57mA
[Pullup]
| Voltage   I(typ)   I(min)   I(max)
-1.8V     5.018mA    5.2mA      4.745mA
-1.137V   5.062mA    4.84mA     5.562mA
-1.07V    7.05mA     5.025mA    10.03mA
-1.003V   11.41mA    6.788mA    16.67mA
-936.6mV  15.38mA    9.689mA    19.75mA
-869.7mV  16.74mA    12.1mA     19.72mA
-735.9mV  15.83mA    12.59mA    18.45mA
-468.3mV  11.44mA    8.94mA     13.7mA
310.3mV   -6.586mA   -4.856mA   -8.236mA
806.9mV   -12.68mA   -9.314mA   -15.89mA
1.996V    -17.07mA   -12.09mA   -22.02mA
3.6V      -17.91mA   -12.64mA   -23.31mA
[Ramp]
dV/dt_r   0.431313/90.7462n  0.317692/0.134724u  0.529263/54.9031n
dV/dt_f   0.419605/82.8798n  0.281353/0.123423u  0.541741/48.696n
R_load = 50
[Falling Waveform]
R_fixture = 50
V_fixture = 1.8
V_fixture_min = 1.66
V_fixture_max = 1.89
| Time   V(typ)   V(min)   V(max)
0s        1.8V       1.66V      1.89V
8.642ns   1.8V       1.66V      1.874V
17.8ns    1.776V     1.659V     1.718V
34.21ns   1.649V     1.628V     1.455V
58.15ns   1.475V     1.546V     1.221V
83.22ns   1.345V     1.463V     1.099V
116.7ns   1.238V     1.377V     1.03V
181.1ns   1.147V     1.279V     994.2mV
295.6ns   1.107V     1.215V     987.4mV
800ns     1.101V     1.191V     987.1mV
[Falling Waveform]
R_fixture = 50
V_fixture = 0
V_fixture_min = 0
V_fixture_max = 0
| Time   V(typ)   V(min)   V(max)
0s        718.9mV    529.7mV    882.1mV
216.3ps   718.7mV    529.7mV    861.6mV
243.1ps   718.9mV    529.7mV    764.3mV
286.8ps   692.6mV    529.6mV    496.7mV
346.9ps   455mV      529.9mV    171.6mV
433.7ps   115.1mV    410.2mV    27.2mV
535.1ps   15.48mV    129.7mV    6.439mV
626.9ps   4.819mV    23.69mV    3.559mV
1.41ns    1.233mV    1.093mV    1.426mV
800ns     8.513nV    563.5nV    3.252nV
[Rising Waveform]
R_fixture = 50
V_fixture = 1.8
V_fixture_min = 1.66
V_fixture_max = 1.89
| Time   V(typ)   V(min)   V(max)
0s        1.101V     1.191V     987.1mV
306.9ps   1.101V     1.191V     1.018V
420.7ps   1.156V     1.191V     1.247V
623.2ps   1.468V     1.275V     1.757V
713.5ps   1.601V     1.349V     1.866V
838.5ps   1.749V     1.445V     1.885V
921.9ps   1.788V     1.5V       1.886V
1.247ns   1.798V     1.648V     1.888V
1.725ns   1.799V     1.659V     1.888V
800ns     1.8V       1.66V      1.89V
[Rising Waveform]
R_fixture = 50
V_fixture = 0
V_fixture_min = 0
V_fixture_max = 0
| Time   V(typ)   V(min)   V(max)
0s        8.5nV      562.5nV    3.248nV
11.19ns   62.31uV    -173.7uV   21.5mV
21.95ns   37.83mV    4.888mV    180.1mV
42.82ns   193.6mV    61.12mV    459.5mV
67.9ns    356.6mV    154.1mV    661.3mV
92.97ns   473.8mV    236.7mV    765.9mV
134.8ns   591.6mV    340mV      840.6mV
200.5ns   672.6mV    435.2mV    873.4mV
315.3ns   710.6mV    501.4mV    881.5mV
800ns     718.9mV    529.5mV    882.1mV
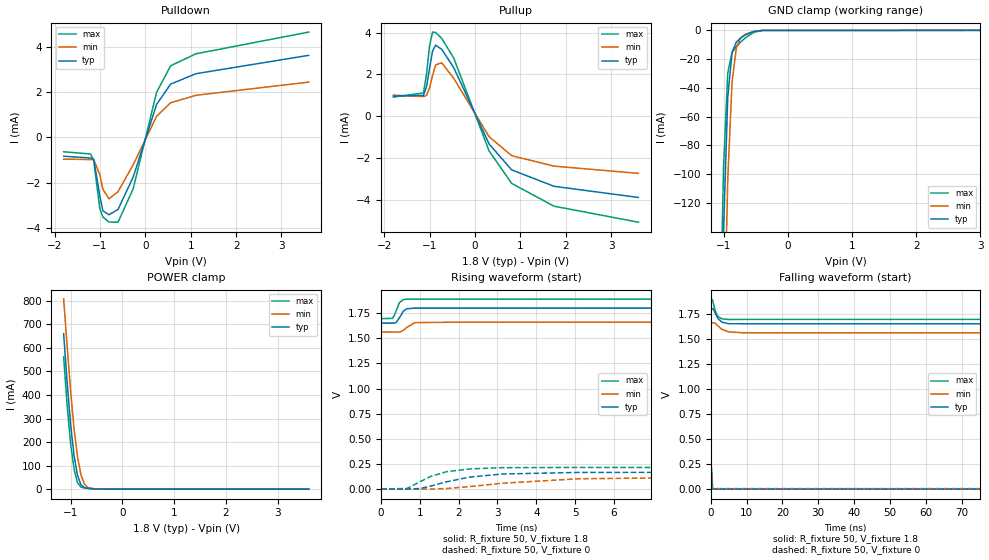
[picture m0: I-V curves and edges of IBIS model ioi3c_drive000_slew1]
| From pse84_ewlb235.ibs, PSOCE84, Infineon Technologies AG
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[Model] ioi3c_drive000_slew1
Model_type I/O
Enable   Active-High
Vinl  =  0.54
Vinh  =  1.26
Vmeas =  0.9
Cref  =  15e-12
| Capacitance   typ   min   max
C_comp   9.12545e-13 8.87504e-13 9.42456e-13
| Variables   typ   min   max
[GND Clamp Reference]   0   0   0
[POWER Clamp Reference]   1.8   1.66   1.89
[Pulldown Reference]   0   0   0
[Pullup Reference]   1.8   1.66   1.89
[Temperature Range]   25   125   -40
[Voltage Range]   1.8   1.66   1.89
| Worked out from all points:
|   slope of the pulldown table from 0 to 0.27 V, typ, clamps not added: 174 ohm
|   slope of the pullup table from 0 to 0.27 V, typ, clamps not added: 228 ohm
|   GND clamp passes 1 mA (typ) near -0.55 V on its own axis
|   POWER clamp passes 1 mA (typ) near -0.54 V on its own axis
|   falling waveform, R_fixture 50, V_fixture 1.8: 20-80 % time 1.45ns typ, 2.17ns min, 1.01ns max; typ from 1.8 V to 1.65 V
|   falling waveform, R_fixture 50, V_fixture 0: 20-80 % time 72.9ps typ, 80.3ps min, 68.8ps max; typ from 0.165 V to 0 V
|   rising waveform, R_fixture 50, V_fixture 1.8: 20-80 % time 140ps typ, 184ps min, 118ps max; typ from 1.65 V to 1.8 V
|   rising waveform, R_fixture 50, V_fixture 0: 20-80 % time 1.25ns typ, 2.23ns min, 797ps max; typ from 0 V to 0.165 V
[GND Clamp]
| Voltage   I(typ)   I(min)   I(max)
-1.204V   -737.9mA   -831.5mA   -678.7mA
-1.07V    -303.2mA   -410.8mA   -239.8mA
-1.003V   -139.9mA   -232.2mA   -95.74mA
-936.6mV  -46.51mA   -103.5mA   -29.5mA
-869.7mV  -15.31mA   -35.88mA   -15.36mA
-802.8mV  -8.166mA   -12.13mA   -11.29mA
-735.9mV  -5.335mA   -5.292mA   -8.195mA
-669mV    -3.356mA   -2.85mA    -5.457mA
-535.2mV  -837.9uA   -772uA     -1.483mA
-401.4mV  -47.36uA   -84.85uA   -76.77uA
3.6V      0A         0A         0A
[POWER Clamp]
| Voltage   I(typ)   I(min)   I(max)
-1.137V   660mA      807.5mA    561.8mA
-1.07V    454.5mA    608.2mA    356.2mA
-1.003V   275.7mA    418.4mA    193.6mA
-936.6mV  143.5mA    257.2mA    86.91mA
-869.7mV  59.43mA    137.9mA    27.31mA
-802.8mV  18.8mA     60.93mA    8.704mA
-735.9mV  6.231mA    21.35mA    5.155mA
-669mV    3.127mA    6.887mA    3.44mA
-535.2mV  940.9uA    1.232mA    1.058mA
-334.5mV  16.1uA     59.03uA    7.686uA
3.6V      0A         0A         0A
[Pulldown]
| Voltage   I(typ)   I(min)   I(max)
-1.8V     -827.2uA   -955.9uA   -630.1uA
-1.204V   -905.7uA   -974.4uA   -731.3uA
-1.137V   -966.5uA   -974.4uA   -1.034mA
-1.003V   -2.575mA   -1.645mA   -3.146mA
-936.6mV  -3.233mA   -2.275mA   -3.507mA
-802.8mV  -3.412mA   -2.706mA   -3.732mA
-602.1mV  -3.177mA   -2.391mA   -3.74mA
-267.6mV  -1.747mA   -1.204mA   -2.264mA
248.3mV   1.461mA    937.9uA    1.999mA
558.6mV   2.359mA    1.534mA    3.169mA
1.117V    2.817mA    1.863mA    3.696mA
3.6V      3.626mA    2.444mA    4.653mA
[Pullup]
| Voltage   I(typ)   I(min)   I(max)
-1.8V     968.9uA    1.007mA    914.8uA
-1.137V   998.9uA    941.3uA    1.117mA
-1.07V    1.412mA    996.9uA    2.02mA
-1.003V   2.299mA    1.357mA    3.386mA
-936.6mV  3.123mA    1.948mA    4.03mA
-869.7mV  3.405mA    2.453mA    4.01mA
-735.9mV  3.208mA    2.56mA     3.737mA
-468.3mV  2.317mA    1.812mA    2.775mA
310.3mV   -1.337mA   -986.1uA   -1.671mA
806.9mV   -2.573mA   -1.892mA   -3.221mA
1.738V    -3.359mA   -2.393mA   -4.312mA
3.6V      -3.894mA   -2.739mA   -5.079mA
[Ramp]
dV/dt_r   99.2904m/1.24502n  70.0389m/2.22622n  0.128112/0.796836n
dV/dt_f   89.3259m/1.44611n  58.925m/2.1673n  0.116841/1.01209n
R_load = 50
[Falling Waveform]
R_fixture = 50
V_fixture = 1.8
V_fixture_min = 1.66
V_fixture_max = 1.89
| Time   V(typ)   V(min)   V(max)
0s        1.8V       1.66V      1.89V
258.2ps   1.8V       1.66V      1.898V
500.9ps   1.801V     1.663V     1.886V
769.2ps   1.795V     1.66V      1.845V
1.234ns   1.757V     1.655V     1.777V
1.937ns   1.706V     1.631V     1.725V
3.034ns   1.668V     1.597V     1.701V
5.002ns   1.652V     1.57V      1.694V
9.411ns   1.651V     1.561V     1.695V
800ns     1.651V     1.562V     1.695V
[Falling Waveform]
R_fixture = 50
V_fixture = 0
V_fixture_min = 0
V_fixture_max = 0
| Time   V(typ)   V(min)   V(max)
0s        165.5mV    116.7mV    213.5mV
202.9ps   165.4mV    116.7mV    211.7mV
225.5ps   165.1mV    116.7mV    184.7mV
266.4ps   164.4mV    116.7mV    88.63mV
310.6ps   113mV      116.5mV    34.75mV
342.6ps   60.78mV    117mV      17.97mV
381.6ps   27.43mV    111.3mV    7.856mV
470.1ps   4.885mV    31.92mV    1.025mV
556.2ps   912.2uV    6.164mV    419.3uV
800ns     22.46nV    1.283uV    9.56nV
[Rising Waveform]
R_fixture = 50
V_fixture = 1.8
V_fixture_min = 1.66
V_fixture_max = 1.89
| Time   V(typ)   V(min)   V(max)
0s        1.651V     1.562V     1.695V
291ps     1.651V     1.562V     1.698V
330.6ps   1.651V     1.562V     1.72V
381.8ps   1.655V     1.562V     1.767V
469ps     1.702V     1.561V     1.854V
572.7ps   1.769V     1.578V     1.885V
655.3ps   1.793V     1.606V     1.889V
868.9ps   1.8V       1.656V     1.889V
1.949ns   1.8V       1.66V      1.89V
800ns     1.8V       1.66V      1.89V
[Rising Waveform]
R_fixture = 50
V_fixture = 0
V_fixture_min = 0
V_fixture_max = 0
| Time   V(typ)   V(min)   V(max)
0s        22.46nV    1.283uV    9.56nV
671ps     -1.176mV   -1.026mV   5.899mV
1.019ns   6.373mV    -428.1uV   75.96mV
1.279ns   29.22mV    103.1uV    125.6mV
1.69ns    72.47mV    5.088mV    173mV
2.3ns     119.8mV    25.12mV    200.6mV
3.136ns   149.7mV    58.06mV    212.8mV
5.094ns   165.3mV    102.2mV    214.9mV
8.805ns   166.4mV    117.1mV    214mV
50ns      165.5mV    116.7mV    213.5mV
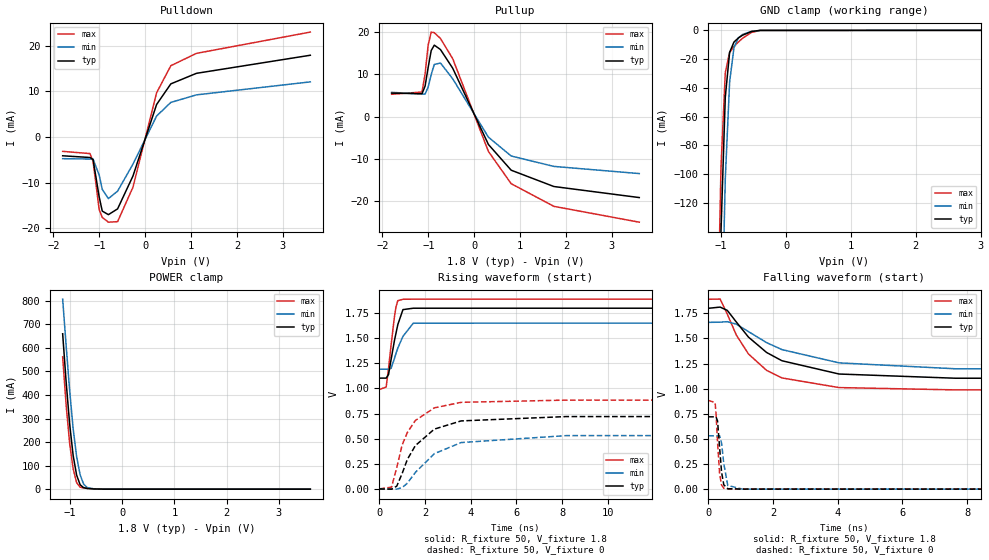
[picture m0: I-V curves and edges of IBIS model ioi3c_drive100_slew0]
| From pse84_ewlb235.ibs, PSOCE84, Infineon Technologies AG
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[Model] ioi3c_drive100_slew0
Model_type I/O
Enable   Active-High
Vinl  =  0.54
Vinh  =  1.26
Vmeas =  0.9
Cref  =  15e-12
| Capacitance   typ   min   max
C_comp   9.12545e-13 8.87504e-13 9.42456e-13
| Variables   typ   min   max
[GND Clamp Reference]   0   0   0
[POWER Clamp Reference]   1.8   1.66   1.89
[Pulldown Reference]   0   0   0
[Pullup Reference]   1.8   1.66   1.89
[Temperature Range]   25   125   -40
[Voltage Range]   1.8   1.66   1.89
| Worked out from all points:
|   slope of the pulldown table from 0 to 0.27 V, typ, clamps not added: 35.5 ohm
|   slope of the pullup table from 0 to 0.27 V, typ, clamps not added: 46.2 ohm
|   GND clamp passes 1 mA (typ) near -0.55 V on its own axis
|   POWER clamp passes 1 mA (typ) near -0.54 V on its own axis
|   falling waveform, R_fixture 50, V_fixture 1.8: 20-80 % time 1.69ns typ, 2.21ns min, 1.24ns max; typ from 1.8 V to 1.1 V
|   falling waveform, R_fixture 50, V_fixture 0: 20-80 % time 105ps typ, 120ps min, 95.9ps max; typ from 0.72 V to 0 V
|   rising waveform, R_fixture 50, V_fixture 1.8: 20-80 % time 350ps typ, 498ps min, 270ps max; typ from 1.1 V to 1.8 V
|   rising waveform, R_fixture 50, V_fixture 0: 20-80 % time 1.27ns typ, 1.65ns min, 955ps max; typ from 0 V to 0.72 V
[GND Clamp]
| Voltage   I(typ)   I(min)   I(max)
-1.204V   -737.9mA   -831.5mA   -678.7mA
-1.07V    -303.2mA   -410.8mA   -239.8mA
-1.003V   -139.9mA   -232.2mA   -95.74mA
-936.6mV  -46.51mA   -103.5mA   -29.5mA
-869.7mV  -15.31mA   -35.88mA   -15.36mA
-802.8mV  -8.166mA   -12.13mA   -11.29mA
-735.9mV  -5.335mA   -5.292mA   -8.195mA
-669mV    -3.356mA   -2.85mA    -5.457mA
-535.2mV  -837.9uA   -772uA     -1.483mA
-401.4mV  -47.36uA   -84.85uA   -76.77uA
3.6V      0A         0A         0A
[POWER Clamp]
| Voltage   I(typ)   I(min)   I(max)
-1.137V   660mA      807.5mA    561.8mA
-1.07V    454.5mA    608.2mA    356.2mA
-1.003V   275.7mA    418.4mA    193.6mA
-936.6mV  143.5mA    257.2mA    86.91mA
-869.7mV  59.43mA    137.9mA    27.31mA
-802.8mV  18.8mA     60.93mA    8.704mA
-735.9mV  6.231mA    21.35mA    5.155mA
-669mV    3.127mA    6.887mA    3.44mA
-535.2mV  940.9uA    1.232mA    1.058mA
-334.5mV  16.1uA     59.03uA    7.686uA
3.6V      0A         0A         0A
[Pulldown]
| Voltage   I(typ)   I(min)   I(max)
-1.8V     -4.088mA   -4.718mA   -3.119mA
-1.204V   -4.464mA   -4.802mA   -3.607mA
-1.137V   -4.913mA   -4.802mA   -5.314mA
-1.003V   -13.12mA   -8.335mA   -15.9mA
-936.6mV  -16.2mA    -11.45mA   -17.57mA
-802.8mV  -16.98mA   -13.46mA   -18.63mA
-602.1mV  -15.71mA   -11.83mA   -18.51mA
-267.6mV  -8.526mA   -5.918mA   -10.98mA
248.3mV   7.148mA    4.621mA    9.711mA
558.6mV   11.66mA    7.599mA    15.64mA
1.117V    13.97mA    9.251mA    18.34mA
3.6V      17.93mA    12.1mA     23mA
[Pullup]
| Voltage   I(typ)   I(min)   I(max)
-1.8V     5.569mA    5.76mA     5.303mA
-1.137V   5.436mA    5.344mA    5.841mA
-1.07V    7.254mA    5.357mA    10.16mA
-1.003V   11.68mA    7.018mA    16.97mA
-936.6mV  15.68mA    9.975mA    20.05mA
-869.7mV  16.95mA    12.37mA    19.91mA
-735.9mV  15.92mA    12.72mA    18.54mA
-468.3mV  11.48mA    8.979mA    13.75mA
310.3mV   -6.605mA   -4.875mA   -8.255mA
806.9mV   -12.71mA   -9.344mA   -15.91mA
1.738V    -16.58mA   -11.81mA   -21.28mA
3.6V      -19.2mA    -13.51mA   -25.04mA
[Ramp]
dV/dt_r   0.432004/1.27375n  0.318682/1.65287n  0.529895/0.954541n
dV/dt_f   0.418265/1.68549n  0.280753/2.21458n  0.540023/1.24071n
R_load = 50
[Falling Waveform]
R_fixture = 50
V_fixture = 1.8
V_fixture_min = 1.66
V_fixture_max = 1.89
| Time   V(typ)   V(min)   V(max)
0s        1.8V       1.66V      1.89V
368.7ps   1.812V     1.662V     1.892V
591.5ps   1.779V     1.667V     1.741V
870.7ps   1.663V     1.642V     1.533V
1.245ns   1.513V     1.568V     1.345V
1.806ns   1.36V      1.458V     1.182V
2.279ns   1.278V     1.389V     1.107V
4.043ns   1.146V     1.257V     1.011V
7.647ns   1.104V     1.198V     988mV
800ns     1.103V     1.192V     990mV
[Falling Waveform]
R_fixture = 50
V_fixture = 0
V_fixture_min = 0
V_fixture_max = 0
| Time   V(typ)   V(min)   V(max)
0s        720mV      531.1mV    883.2mV
213.6ps   719.8mV    531.1mV    863mV
240.4ps   720.2mV    531.1mV    760.6mV
290ps     678.3mV    531mV      462.8mV
351.9ps   414.4mV    531.8mV    156mV
413.1ps   169.4mV    458.3mV    41.59mV
482.4ps   43.28mV    252.5mV    8.966mV
604.5ps   4.68mV     36.78mV    1.432mV
1.052ns   751.2uV    888.6uV    526.1uV
800ns     11.32nV    752.5nV    4.294nV
[Rising Waveform]
R_fixture = 50
V_fixture = 1.8
V_fixture_min = 1.66
V_fixture_max = 1.89
| Time   V(typ)   V(min)   V(max)
0s        1.103V     1.192V     990mV
302.7ps   1.103V     1.192V     1.014V
405.8ps   1.138V     1.192V     1.198V
519.1ps   1.289V     1.201V     1.434V
662.9ps   1.474V     1.297V     1.71V
735.4ps   1.553V     1.351V     1.815V
812.5ps   1.636V     1.402V     1.874V
1.037ns   1.785V     1.519V     1.888V
1.489ns   1.799V     1.65V      1.889V
800ns     1.8V       1.66V      1.89V
[Rising Waveform]
R_fixture = 50
V_fixture = 0
V_fixture_min = 0
V_fixture_max = 0
| Time   V(typ)   V(min)   V(max)
0s        11.32nV    752.3nV    4.294nV
539.3ps   -2.171mV   -966.8uV   18.38mV
765.8ps   27.85mV    -1.447mV   213.6mV
1.001ns   153.2mV    13.33mV    436.9mV
1.231ns   294.7mV    57.46mV    562.4mV
1.579ns   431.3mV    164.5mV    681.2mV
2.41ns    595.7mV    351.3mV    807.3mV
3.581ns   677.2mV    461.7mV    862.2mV
8.179ns   720.4mV    530.9mV    884.3mV
50ns      720mV      531.1mV    883.2mV
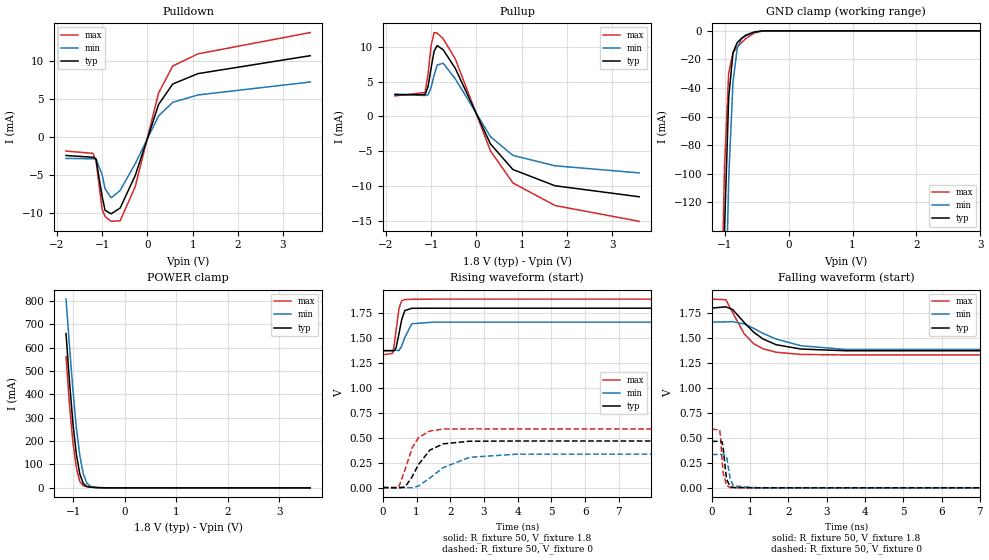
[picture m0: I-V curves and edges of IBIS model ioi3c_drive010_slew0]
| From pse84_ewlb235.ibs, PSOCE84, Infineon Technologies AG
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[Model] ioi3c_drive010_slew0
Model_type I/O
Enable   Active-High
Vinl  =  0.54
Vinh  =  1.26
Vmeas =  0.9
Cref  =  15e-12
| Capacitance   typ   min   max
C_comp   9.12545e-13 8.87504e-13 9.42456e-13
| Variables   typ   min   max
[GND Clamp Reference]   0   0   0
[POWER Clamp Reference]   1.8   1.66   1.89
[Pulldown Reference]   0   0   0
[Pullup Reference]   1.8   1.66   1.89
[Temperature Range]   25   125   -40
[Voltage Range]   1.8   1.66   1.89
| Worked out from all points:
|   slope of the pulldown table from 0 to 0.27 V, typ, clamps not added: 59.8 ohm
|   slope of the pullup table from 0 to 0.27 V, typ, clamps not added: 76.6 ohm
|   GND clamp passes 1 mA (typ) near -0.55 V on its own axis
|   POWER clamp passes 1 mA (typ) near -0.54 V on its own axis
|   falling waveform, R_fixture 50, V_fixture 1.8: 20-80 % time 790ps typ, 1.14ns min, 579ps max; typ from 1.8 V to 1.37 V
|   falling waveform, R_fixture 50, V_fixture 0: 20-80 % time 77ps typ, 85.8ps min, 72.3ps max; typ from 0.466 V to 0 V
|   rising waveform, R_fixture 50, V_fixture 1.8: 20-80 % time 151ps typ, 197ps min, 127ps max; typ from 1.37 V to 1.8 V
|   rising waveform, R_fixture 50, V_fixture 0: 20-80 % time 540ps typ, 890ps min, 377ps max; typ from 0 V to 0.466 V
[GND Clamp]
| Voltage   I(typ)   I(min)   I(max)
-1.204V   -737.9mA   -831.5mA   -678.7mA
-1.07V    -303.2mA   -410.8mA   -239.8mA
-1.003V   -139.9mA   -232.2mA   -95.74mA
-936.6mV  -46.51mA   -103.5mA   -29.5mA
-869.7mV  -15.31mA   -35.88mA   -15.36mA
-802.8mV  -8.166mA   -12.13mA   -11.29mA
-735.9mV  -5.335mA   -5.292mA   -8.195mA
-669mV    -3.356mA   -2.85mA    -5.457mA
-535.2mV  -837.9uA   -772uA     -1.483mA
-401.4mV  -47.36uA   -84.85uA   -76.77uA
3.6V      0A         0A         0A
[POWER Clamp]
| Voltage   I(typ)   I(min)   I(max)
-1.137V   660mA      807.5mA    561.8mA
-1.07V    454.5mA    608.2mA    356.2mA
-1.003V   275.7mA    418.4mA    193.6mA
-936.6mV  143.5mA    257.2mA    86.91mA
-869.7mV  59.43mA    137.9mA    27.31mA
-802.8mV  18.8mA     60.93mA    8.704mA
-735.9mV  6.231mA    21.35mA    5.155mA
-669mV    3.127mA    6.887mA    3.44mA
-535.2mV  940.9uA    1.232mA    1.058mA
-334.5mV  16.1uA     59.03uA    7.686uA
3.6V      0A         0A         0A
[Pulldown]
| Voltage   I(typ)   I(min)   I(max)
-1.8V     -2.473mA   -2.853mA   -1.888mA
-1.204V   -2.703mA   -2.903mA   -2.188mA
-1.137V   -2.924mA   -2.903mA   -3.154mA
-1.003V   -7.821mA   -4.973mA   -9.504mA
-936.6mV  -9.679mA   -6.838mA   -10.5mA
-802.8mV  -10.14mA   -8.037mA   -11.12mA
-602.1mV  -9.37mA    -7.061mA   -11.04mA
-267.6mV  -5.074mA   -3.525mA   -6.53mA
248.3mV   4.247mA    2.747mA    5.767mA
558.6mV   6.922mA    4.513mA    9.29mA
1.117V    8.293mA    5.488mA    10.89mA
3.6V      10.65mA    7.188mA    13.69mA
[Pullup]
| Voltage   I(typ)   I(min)   I(max)
-1.8V     3.098mA    3.211mA    2.938mA
-1.137V   3.112mA    2.991mA    3.417mA
-1.07V    4.282mA    3.087mA    6.068mA
-1.003V   6.934mA    4.127mA    10.16mA
-936.6mV  9.371mA    5.897mA    12.05mA
-869.7mV  10.18mA    7.374mA    11.98mA
-735.9mV  9.575mA    7.644mA    11.16mA
-468.3mV  6.907mA    5.402mA    8.274mA
310.3mV   -3.979mA   -2.936mA   -4.975mA
806.9mV   -7.66mA    -5.63mA    -9.59mA
1.738V    -9.995mA   -7.12mA    -12.84mA
3.6V      -11.58mA   -8.146mA   -15.11mA
[Ramp]
dV/dt_r   0.279481/0.539518n  0.200954/0.889779n  0.352677/0.377002n
dV/dt_f   0.256719/0.79016n  0.170442/1.14432n  0.334744/0.578863n
R_load = 50
[Falling Waveform]
R_fixture = 50
V_fixture = 1.8
V_fixture_min = 1.66
V_fixture_max = 1.89
| Time   V(typ)   V(min)   V(max)
0s        1.8V       1.66V      1.89V
365.6ps   1.813V     1.662V     1.884V
544.5ps   1.785V     1.665V     1.754V
847.9ps   1.655V     1.641V     1.541V
1.088ns   1.56V      1.598V     1.445V
1.335ns   1.491V     1.547V     1.393V
1.684ns   1.433V     1.489V     1.358V
2.331ns   1.39V      1.423V     1.336V
3.507ns   1.373V     1.386V     1.331V
800ns     1.372V     1.376V     1.332V
[Falling Waveform]
R_fixture = 50
V_fixture = 0
V_fixture_min = 0
V_fixture_max = 0
| Time   V(typ)   V(min)   V(max)
0s        465.8mV    334.9mV    587.8mV
204ps     465.7mV    334.9mV    579.9mV
228.4ps   465.5mV    334.9mV    503.5mV
267ps     460.9mV    334.9mV    274mV
296.8ps   392.4mV    334.7mV    145.9mV
382.2ps   87.05mV    317.7mV    23.49mV
477.6ps   13.15mV    91.72mV    3.275mV
558.7ps   3.105mV    19.64mV    1.468mV
1.195ns   492.8uV    681.7uV    336.2uV
800ns     15.17nV    953nV      6nV
[Rising Waveform]
R_fixture = 50
V_fixture = 1.8
V_fixture_min = 1.66
V_fixture_max = 1.89
| Time   V(typ)   V(min)   V(max)
0s        1.372V     1.376V     1.332V
285.3ps   1.372V     1.376V     1.345V
332.2ps   1.371V     1.376V     1.421V
391.5ps   1.402V     1.376V     1.573V
479.4ps   1.544V     1.375V     1.798V
558.3ps   1.683V     1.418V     1.873V
651.4ps   1.775V     1.505V     1.886V
859.2ps   1.798V     1.643V     1.888V
1.505ns   1.799V     1.659V     1.89V
800ns     1.8V       1.66V      1.89V
[Rising Waveform]
R_fixture = 50
V_fixture = 0
V_fixture_min = 0
V_fixture_max = 0
| Time   V(typ)   V(min)   V(max)
0s        15.17nV    952.7nV    6nV
465.6ps   -2.985mV   49.26uV    -130.5uV
662.8ps   6.344mV    -2.233mV   183.1mV
869ps     109.2mV    -1.456mV   398.1mV
1.062ns   233mV      16.6mV     503.4mV
1.393ns   375.7mV    95.21mV    566.7mV
1.791ns   438.6mV    200mV      587.1mV
2.567ns   464.7mV    303.2mV    588.9mV
3.984ns   466.9mV    335mV      587.7mV
50ns      465.8mV    334.9mV    587.8mV
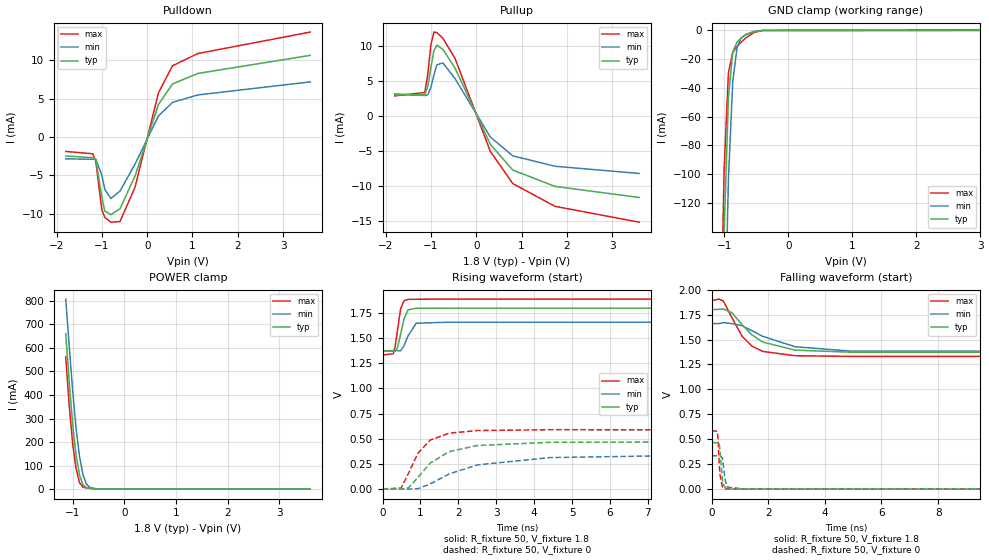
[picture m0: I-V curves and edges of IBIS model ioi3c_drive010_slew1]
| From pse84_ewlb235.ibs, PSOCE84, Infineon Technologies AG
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[Model] ioi3c_drive010_slew1
Model_type I/O
Enable   Active-High
Vinl  =  0.54
Vinh  =  1.26
Vmeas =  0.9
Cref  =  15e-12
| Capacitance   typ   min   max
C_comp   9.12545e-13 8.87504e-13 9.42456e-13
| Variables   typ   min   max
[GND Clamp Reference]   0   0   0
[POWER Clamp Reference]   1.8   1.66   1.89
[Pulldown Reference]   0   0   0
[Pullup Reference]   1.8   1.66   1.89
[Temperature Range]   25   125   -40
[Voltage Range]   1.8   1.66   1.89
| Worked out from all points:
|   slope of the pulldown table from 0 to 0.27 V, typ, clamps not added: 59.8 ohm
|   slope of the pullup table from 0 to 0.27 V, typ, clamps not added: 76.6 ohm
|   GND clamp passes 1 mA (typ) near -0.55 V on its own axis
|   POWER clamp passes 1 mA (typ) near -0.54 V on its own axis
|   falling waveform, R_fixture 50, V_fixture 1.8: 20-80 % time 1.04ns typ, 1.54ns min, 755ps max; typ from 1.8 V to 1.37 V
|   falling waveform, R_fixture 50, V_fixture 0: 20-80 % time 76.8ps typ, 85.7ps min, 72.1ps max; typ from 0.466 V to 0 V
|   rising waveform, R_fixture 50, V_fixture 1.8: 20-80 % time 151ps typ, 197ps min, 127ps max; typ from 1.37 V to 1.8 V
|   rising waveform, R_fixture 50, V_fixture 0: 20-80 % time 885ps typ, 1.63ns min, 561ps max; typ from 0 V to 0.466 V
[GND Clamp]
| Voltage   I(typ)   I(min)   I(max)
-1.204V   -737.9mA   -831.5mA   -678.7mA
-1.07V    -303.2mA   -410.8mA   -239.8mA
-1.003V   -139.9mA   -232.2mA   -95.74mA
-936.6mV  -46.51mA   -103.5mA   -29.5mA
-869.7mV  -15.31mA   -35.88mA   -15.36mA
-802.8mV  -8.166mA   -12.13mA   -11.29mA
-735.9mV  -5.335mA   -5.292mA   -8.195mA
-669mV    -3.356mA   -2.85mA    -5.457mA
-535.2mV  -837.9uA   -772uA     -1.483mA
-401.4mV  -47.36uA   -84.85uA   -76.77uA
3.6V      0A         0A         0A
[POWER Clamp]
| Voltage   I(typ)   I(min)   I(max)
-1.137V   660mA      807.5mA    561.8mA
-1.07V    454.5mA    608.2mA    356.2mA
-1.003V   275.7mA    418.4mA    193.6mA
-936.6mV  143.5mA    257.2mA    86.91mA
-869.7mV  59.43mA    137.9mA    27.31mA
-802.8mV  18.8mA     60.93mA    8.704mA
-735.9mV  6.231mA    21.35mA    5.155mA
-669mV    3.127mA    6.887mA    3.44mA
-535.2mV  940.9uA    1.232mA    1.058mA
-334.5mV  16.1uA     59.03uA    7.686uA
3.6V      0A         0A         0A
[Pulldown]
| Voltage   I(typ)   I(min)   I(max)
-1.8V     -2.473mA   -2.853mA   -1.888mA
-1.204V   -2.703mA   -2.903mA   -2.188mA
-1.137V   -2.924mA   -2.903mA   -3.154mA
-1.003V   -7.821mA   -4.973mA   -9.504mA
-936.6mV  -9.679mA   -6.838mA   -10.5mA
-802.8mV  -10.14mA   -8.037mA   -11.12mA
-602.1mV  -9.37mA    -7.061mA   -11.04mA
-267.6mV  -5.074mA   -3.525mA   -6.53mA
248.3mV   4.247mA    2.747mA    5.767mA
558.6mV   6.922mA    4.513mA    9.29mA
1.117V    8.293mA    5.488mA    10.89mA
3.6V      10.65mA    7.188mA    13.69mA
[Pullup]
| Voltage   I(typ)   I(min)   I(max)
-1.8V     3.098mA    3.211mA    2.938mA
-1.137V   3.112mA    2.991mA    3.417mA
-1.07V    4.282mA    3.087mA    6.068mA
-1.003V   6.934mA    4.127mA    10.16mA
-936.6mV  9.371mA    5.897mA    12.05mA
-869.7mV  10.18mA    7.374mA    11.98mA
-735.9mV  9.575mA    7.644mA    11.16mA
-468.3mV  6.907mA    5.402mA    8.274mA
310.3mV   -3.979mA   -2.936mA   -4.975mA
806.9mV   -7.66mA    -5.63mA    -9.59mA
1.738V    -9.995mA   -7.12mA    -12.84mA
3.6V      -11.58mA   -8.146mA   -15.11mA
[Ramp]
dV/dt_r   0.279481/0.885482n  0.200951/1.62762n  0.352677/0.561391n
dV/dt_f   0.256719/1.04222n  0.170441/1.54264n  0.334744/0.755145n
R_load = 50
[Falling Waveform]
R_fixture = 50
V_fixture = 1.8
V_fixture_min = 1.66
V_fixture_max = 1.89
| Time   V(typ)   V(min)   V(max)
0s        1.8V       1.66V      1.89V
264ps     1.803V     1.66V      1.906V
419ps     1.806V     1.67V      1.885V
718.2ps   1.77V      1.66V      1.72V
1.076ns   1.649V     1.639V     1.534V
1.42ns    1.548V     1.59V      1.435V
1.807ns   1.475V     1.532V     1.381V
2.95ns    1.394V     1.428V     1.338V
4.934ns   1.373V     1.384V     1.331V
800ns     1.372V     1.376V     1.332V
[Falling Waveform]
R_fixture = 50
V_fixture = 0
V_fixture_min = 0
V_fixture_max = 0
| Time   V(typ)   V(min)   V(max)
0s        465.8mV    334.9mV    587.8mV
204.5ps   465.7mV    334.9mV    579.3mV
228.7ps   465.5mV    334.9mV    502.1mV
264.6ps   462.7mV    334.9mV    287mV
296.4ps   393.7mV    334.7mV    146.6mV
387.3ps   78.2mV     310.6mV    21.14mV
475.3ps   13.8mV     95.8mV     3.527mV
553.6ps   2.213mV    21.36mV    1.525mV
1.187ns   596.7uV    671.5uV    454.3uV
800ns     15.17nV    953nV      6nV
[Rising Waveform]
R_fixture = 50
V_fixture = 1.8
V_fixture_min = 1.66
V_fixture_max = 1.89
| Time   V(typ)   V(min)   V(max)
0s        1.372V     1.376V     1.332V
287.7ps   1.372V     1.376V     1.347V
334.4ps   1.371V     1.376V     1.424V
390.4ps   1.401V     1.376V     1.568V
476.8ps   1.539V     1.375V     1.793V
565.1ps   1.693V     1.424V     1.874V
672.3ps   1.783V     1.524V     1.887V
886.5ps   1.798V     1.649V     1.888V
1.664ns   1.799V     1.659V     1.89V
800ns     1.8V       1.66V      1.89V
[Rising Waveform]
R_fixture = 50
V_fixture = 0
V_fixture_min = 0
V_fixture_max = 0
| Time   V(typ)   V(min)   V(max)
0s        15.17nV    952.7nV    6nV
489.7ps   -3.099mV   -576.4uV   7.201mV
678.8ps   9.681mV    -2.224mV   149.9mV
931.2ps   113.6mV    1.677mV    354.3mV
1.26ns    257.8mV    48.89mV    486mV
1.751ns   369.8mV    147.5mV    553.7mV
2.496ns   431.5mV    238.5mV    580.8mV
4.414ns   463.3mV    311.3mV    588.8mV
8.409ns   466.5mV    335.2mV    588mV
50ns      465.8mV    334.9mV    587.8mV
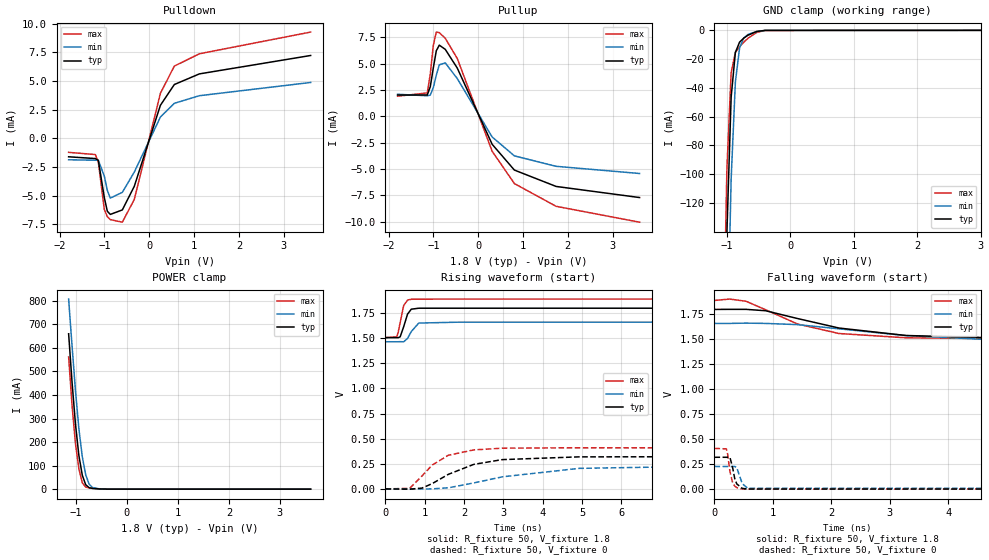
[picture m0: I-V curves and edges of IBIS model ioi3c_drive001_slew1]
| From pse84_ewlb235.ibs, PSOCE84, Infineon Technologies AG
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[Model] ioi3c_drive001_slew1
Model_type I/O
Enable   Active-High
Vinl  =  0.54
Vinh  =  1.26
Vmeas =  0.9
Cref  =  15e-12
| Capacitance   typ   min   max
C_comp   9.12545e-13 8.87504e-13 9.42456e-13
| Variables   typ   min   max
[GND Clamp Reference]   0   0   0
[POWER Clamp Reference]   1.8   1.66   1.89
[Pulldown Reference]   0   0   0
[Pullup Reference]   1.8   1.66   1.89
[Temperature Range]   25   125   -40
[Voltage Range]   1.8   1.66   1.89
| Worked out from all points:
|   slope of the pulldown table from 0 to 0.27 V, typ, clamps not added: 87.9 ohm
|   slope of the pullup table from 0 to 0.27 V, typ, clamps not added: 115 ohm
|   GND clamp passes 1 mA (typ) near -0.55 V on its own axis
|   POWER clamp passes 1 mA (typ) near -0.54 V on its own axis
|   falling waveform, R_fixture 50, V_fixture 1.8: 20-80 % time 1.51ns typ, 2.27ns min, 1.06ns max; typ from 1.8 V to 1.51 V
|   falling waveform, R_fixture 50, V_fixture 0: 20-80 % time 72.8ps typ, 80.2ps min, 68.7ps max; typ from 0.319 V to 0 V
|   rising waveform, R_fixture 50, V_fixture 1.8: 20-80 % time 136ps typ, 178ps min, 116ps max; typ from 1.51 V to 1.8 V
|   rising waveform, R_fixture 50, V_fixture 0: 20-80 % time 1.13ns typ, 2.01ns min, 723ps max; typ from 0 V to 0.319 V
[GND Clamp]
| Voltage   I(typ)   I(min)   I(max)
-1.204V   -737.9mA   -831.5mA   -678.7mA
-1.07V    -303.2mA   -410.8mA   -239.8mA
-1.003V   -139.9mA   -232.2mA   -95.74mA
-936.6mV  -46.51mA   -103.5mA   -29.5mA
-869.7mV  -15.31mA   -35.88mA   -15.36mA
-802.8mV  -8.166mA   -12.13mA   -11.29mA
-735.9mV  -5.335mA   -5.292mA   -8.195mA
-669mV    -3.356mA   -2.85mA    -5.457mA
-535.2mV  -837.9uA   -772uA     -1.483mA
-401.4mV  -47.36uA   -84.85uA   -76.77uA
3.6V      0A         0A         0A
[POWER Clamp]
| Voltage   I(typ)   I(min)   I(max)
-1.137V   660mA      807.5mA    561.8mA
-1.07V    454.5mA    608.2mA    356.2mA
-1.003V   275.7mA    418.4mA    193.6mA
-936.6mV  143.5mA    257.2mA    86.91mA
-869.7mV  59.43mA    137.9mA    27.31mA
-802.8mV  18.8mA     60.93mA    8.704mA
-735.9mV  6.231mA    21.35mA    5.155mA
-669mV    3.127mA    6.887mA    3.44mA
-535.2mV  940.9uA    1.232mA    1.058mA
-334.5mV  16.1uA     59.03uA    7.686uA
3.6V      0A         0A         0A
[Pulldown]
| Voltage   I(typ)   I(min)   I(max)
-1.8V     -1.61mA    -1.871mA   -1.222mA
-1.204V   -1.765mA   -1.911mA   -1.417mA
-1.137V   -1.93mA    -1.912mA   -2.077mA
-1.003V   -5.181mA   -3.312mA   -6.214mA
-936.6mV  -6.363mA   -4.544mA   -6.839mA
-869.7mV  -6.641mA   -5.216mA   -7.096mA
-602.1mV  -6.249mA   -4.717mA   -7.32mA
-334.5mV  -4.187mA   -2.945mA   -5.335mA
248.3mV   2.889mA    1.862mA    3.936mA
558.6mV   4.697mA    3.058mA    6.305mA
1.117V    5.626mA    3.722mA    7.382mA
3.6V      7.233mA    4.878mA    9.276mA
[Pullup]
| Voltage   I(typ)   I(min)   I(max)
-1.8V     2.028mA    2.104mA    1.92mA
-1.137V   2.037mA    1.961mA    2.234mA
-1.07V    2.828mA    2.023mA    4.027mA
-1.003V   4.601mA    2.729mA    6.745mA
-936.6mV  6.228mA    3.912mA    8.012mA
-869.7mV  6.772mA    4.901mA    7.966mA
-735.9mV  6.371mA    5.088mA    7.421mA
-468.3mV  4.596mA    3.596mA    5.503mA
310.3mV   -2.648mA   -1.955mA   -3.309mA
806.9mV   -5.099mA   -3.749mA   -6.382mA
1.738V    -6.654mA   -4.742mA   -8.542mA
3.6V      -7.709mA   -5.424mA   -10.05mA
[Ramp]
dV/dt_r   0.19169/1.13142n  0.136432/2.00984n  0.244811/0.722693n
dV/dt_f   0.176398/1.51389n  0.116707/2.26874n  0.230254/1.06143n
R_load = 50
[Falling Waveform]
R_fixture = 50
V_fixture = 1.8
V_fixture_min = 1.66
V_fixture_max = 1.89
| Time   V(typ)   V(min)   V(max)
0s        1.8V       1.66V      1.89V
259.8ps   1.801V     1.66V      1.904V
540.5ps   1.801V     1.663V     1.882V
876.3ps   1.787V     1.66V      1.797V
1.422ns   1.709V     1.648V     1.654V
2.131ns   1.614V     1.606V     1.559V
3.28ns    1.539V     1.538V     1.516V
5.236ns   1.509V     1.483V     1.505V
10.79ns   1.505V     1.464V     1.506V
800ns     1.506V     1.465V     1.506V
[Falling Waveform]
R_fixture = 50
V_fixture = 0
V_fixture_min = 0
V_fixture_max = 0
| Time   V(typ)   V(min)   V(max)
0s        319.5mV    227.4mV    408mV
203.5ps   319.4mV    227.4mV    403.7mV
225.8ps   319.1mV    227.4mV    352.7mV
265.8ps   317.5mV    227.4mV    172.8mV
311.2ps   216.5mV    227.1mV    65.7mV
346.2ps   109.2mV    228.2mV    31.89mV
381.3ps   53.2mV     216.7mV    15.32mV
476.5ps   7.995mV    54.68mV    1.409mV
569.6ps   1.223mV    9.239mV    669.6uV
800ns     18.03nV    1.09uV     7.328nV
[Rising Waveform]
R_fixture = 50
V_fixture = 1.8
V_fixture_min = 1.66
V_fixture_max = 1.89
| Time   V(typ)   V(min)   V(max)
0s        1.506V     1.465V     1.506V
285.6ps   1.506V     1.465V     1.514V
322.6ps   1.506V     1.465V     1.558V
373ps     1.514V     1.466V     1.655V
461.2ps   1.613V     1.464V     1.824V
560.9ps   1.74V      1.498V     1.88V
655.3ps   1.789V     1.566V     1.888V
846.2ps   1.799V     1.651V     1.889V
1.86ns    1.799V     1.66V      1.89V
800ns     1.8V       1.66V      1.89V
[Rising Waveform]
R_fixture = 50
V_fixture = 0
V_fixture_min = 0
V_fixture_max = 0
| Time   V(typ)   V(min)   V(max)
0s        18.03nV    1.09uV     7.328nV
615.8ps   -2.672mV   -1.745mV   5.526mV
925.3ps   7.847mV    -1.194mV   127.8mV
1.19ns    53.1mV     148.2uV    237.9mV
1.599ns   145mV      10.92mV    334.9mV
2.245ns   244.2mV    59.17mV    388.2mV
2.97ns    291.5mV    120mV      405.5mV
4.917ns   318.9mV    204.3mV    409.5mV
8.611ns   320.5mV    228.2mV    408.3mV
50ns      319.5mV    227.4mV    408mV
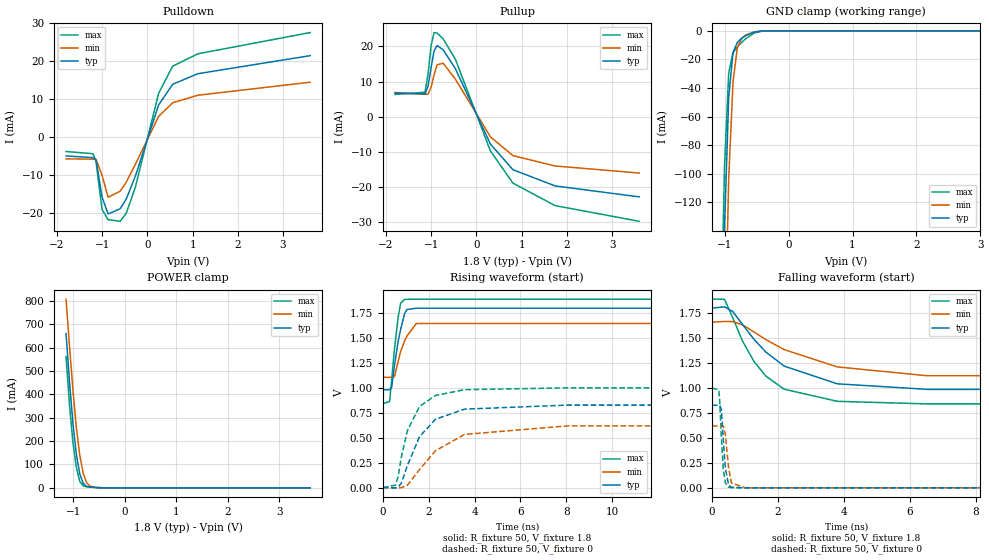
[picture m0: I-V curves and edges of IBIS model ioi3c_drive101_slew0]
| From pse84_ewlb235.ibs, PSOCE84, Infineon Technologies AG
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[Model] ioi3c_drive101_slew0
Model_type I/O
Enable   Active-High
Vinl  =  0.54
Vinh  =  1.26
Vmeas =  0.9
Cref  =  15e-12
| Capacitance   typ   min   max
C_comp   9.12545e-13 8.87504e-13 9.42456e-13
| Variables   typ   min   max
[GND Clamp Reference]   0   0   0
[POWER Clamp Reference]   1.8   1.66   1.89
[Pulldown Reference]   0   0   0
[Pullup Reference]   1.8   1.66   1.89
[Temperature Range]   25   125   -40
[Voltage Range]   1.8   1.66   1.89
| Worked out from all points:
|   slope of the pulldown table from 0 to 0.27 V, typ, clamps not added: 29.6 ohm
|   slope of the pullup table from 0 to 0.27 V, typ, clamps not added: 38.6 ohm
|   GND clamp passes 1 mA (typ) near -0.55 V on its own axis
|   POWER clamp passes 1 mA (typ) near -0.54 V on its own axis
|   falling waveform, R_fixture 50, V_fixture 1.8: 20-80 % time 1.71ns typ, 2.39ns min, 1.23ns max; typ from 1.8 V to 0.981 V
|   falling waveform, R_fixture 50, V_fixture 0: 20-80 % time 104ps typ, 118ps min, 96ps max; typ from 0.827 V to 0 V
|   rising waveform, R_fixture 50, V_fixture 1.8: 20-80 % time 354ps typ, 493ps min, 277ps max; typ from 0.981 V to 1.8 V
|   rising waveform, R_fixture 50, V_fixture 0: 20-80 % time 1.16ns typ, 1.68ns min, 815ps max; typ from 0 V to 0.827 V
[GND Clamp]
| Voltage   I(typ)   I(min)   I(max)
-1.204V   -737.9mA   -831.5mA   -678.7mA
-1.07V    -303.2mA   -410.8mA   -239.8mA
-1.003V   -139.9mA   -232.2mA   -95.74mA
-936.6mV  -46.51mA   -103.5mA   -29.5mA
-869.7mV  -15.31mA   -35.88mA   -15.36mA
-802.8mV  -8.166mA   -12.13mA   -11.29mA
-735.9mV  -5.335mA   -5.292mA   -8.195mA
-669mV    -3.356mA   -2.85mA    -5.457mA
-535.2mV  -837.9uA   -772uA     -1.483mA
-401.4mV  -47.36uA   -84.85uA   -76.77uA
3.6V      0A         0A         0A
[POWER Clamp]
| Voltage   I(typ)   I(min)   I(max)
-1.137V   660mA      807.5mA    561.8mA
-1.07V    454.5mA    608.2mA    356.2mA
-1.003V   275.7mA    418.4mA    193.6mA
-936.6mV  143.5mA    257.2mA    86.91mA
-869.7mV  59.43mA    137.9mA    27.31mA
-802.8mV  18.8mA     60.93mA    8.704mA
-735.9mV  6.231mA    21.35mA    5.155mA
-669mV    3.127mA    6.887mA    3.44mA
-535.2mV  940.9uA    1.232mA    1.058mA
-334.5mV  16.1uA     59.03uA    7.686uA
3.6V      0A         0A         0A
[Pulldown]
| Voltage   I(typ)   I(min)   I(max)
-1.8V     -4.871mA   -5.633mA   -3.71mA
-1.204V   -5.323mA   -5.738mA   -4.292mA
-1.137V   -5.876mA   -5.739mA   -6.357mA
-1.003V   -15.72mA   -10mA      -18.97mA
-869.7mV  -20.17mA   -15.75mA   -21.66mA
-602.1mV  -18.78mA   -14.16mA   -22.09mA
-468.3mV  -16.23mA   -11.81mA   -19.97mA
-267.6mV  -10.22mA   -7.094mA   -13.16mA
248.3mV   8.571mA    5.543mA    11.64mA
558.6mV   13.99mA    9.121mA    18.76mA
1.117V    16.78mA    11.11mA    22.02mA
3.6V      21.53mA    14.53mA    27.61mA
[Pullup]
| Voltage   I(typ)   I(min)   I(max)
-1.8V     6.618mA    6.849mA    6.297mA
-1.137V   6.463mA    6.354mA    6.946mA
-1.07V    8.656mA    6.373mA    12.14mA
-1.003V   13.95mA    8.378mA    20.29mA
-936.6mV  18.75mA    11.92mA    23.98mA
-869.7mV  20.28mA    14.79mA    23.82mA
-735.9mV  19.04mA    15.22mA    22.18mA
-468.3mV  13.73mA    10.74mA    16.43mA
310.3mV   -7.896mA   -5.832mA   -9.863mA
806.9mV   -15.2mA    -11.18mA   -19.03mA
1.738V    -19.83mA   -14.13mA   -25.45mA
3.6V      -22.96mA   -16.16mA   -29.94mA
[Ramp]
dV/dt_r   0.496158/1.15963n  0.371423/1.68443n  0.59959/0.815453n
dV/dt_f   0.491626/1.71265n  0.332564/2.38907n  0.629541/1.22532n
R_load = 50
[Falling Waveform]
R_fixture = 50
V_fixture = 1.8
V_fixture_min = 1.66
V_fixture_max = 1.89
| Time   V(typ)   V(min)   V(max)
0s        1.8V       1.66V      1.89V
382.2ps   1.813V     1.666V     1.888V
632.3ps   1.766V     1.665V     1.705V
925.2ps   1.638V     1.634V     1.473V
1.277ns   1.487V     1.561V     1.266V
1.638ns   1.36V      1.484V     1.119V
2.189ns   1.22V      1.385V     988.3mV
3.803ns   1.042V     1.211V     866.6mV
6.531ns   986.4mV    1.123V     840.9mV
800ns     980.6mV    1.106V     840.8mV
[Falling Waveform]
R_fixture = 50
V_fixture = 0
V_fixture_min = 0
V_fixture_max = 0
| Time   V(typ)   V(min)   V(max)
0s        826.9mV    619mV      999.3mV
211.7ps   826.7mV    619mV      981.7mV
236.8ps   827mV      619mV      874.4mV
287.5ps   785mV      618.9mV    515.8mV
346.7ps   479.7mV    620.1mV    188.2mV
409.7ps   193.9mV    537.4mV    49.04mV
508.1ps   28.49mV    198.3mV    6.264mV
593.4ps   6.018mV    48.27mV    1.831mV
1.018ns   961.3uV    1.067mV    674.3uV
800ns     10.07nV    682.1nV    3.767nV
[Rising Waveform]
R_fixture = 50
V_fixture = 1.8
V_fixture_min = 1.66
V_fixture_max = 1.89
| Time   V(typ)   V(min)   V(max)
0s        980.6mV    1.106V     840.8mV
293.7ps   980.8mV    1.106V     863.3mV
384.6ps   1.005V     1.106V     1.075V
510ps     1.229V     1.115V     1.397V
669.5ps   1.469V     1.267V     1.71V
774.6ps   1.585V     1.365V     1.848V
948.7ps   1.744V     1.47V      1.888V
1.051ns   1.786V     1.52V      1.888V
1.465ns   1.799V     1.646V     1.889V
800ns     1.8V       1.66V      1.89V
[Rising Waveform]
R_fixture = 50
V_fixture = 0
V_fixture_min = 0
V_fixture_max = 0
| Time   V(typ)   V(min)   V(max)
0s        10.07nV    681.9nV    3.769nV
552.3ps   -2.874mV   -1.51mV    24.41mV
667.1ps   4.483mV    -2.142mV   108.3mV
807.9ps   44.09mV    -1.33mV    306.9mV
1.071ns   221.6mV    24.02mV    571.3mV
1.602ns   510.9mV    181.6mV    813.9mV
2.298ns   685.2mV    369.7mV    923.9mV
3.567ns   786.8mV    533.3mV    981.7mV
8.056ns   827mV      618.5mV    1V
50ns      826.9mV    619mV      999.3mV
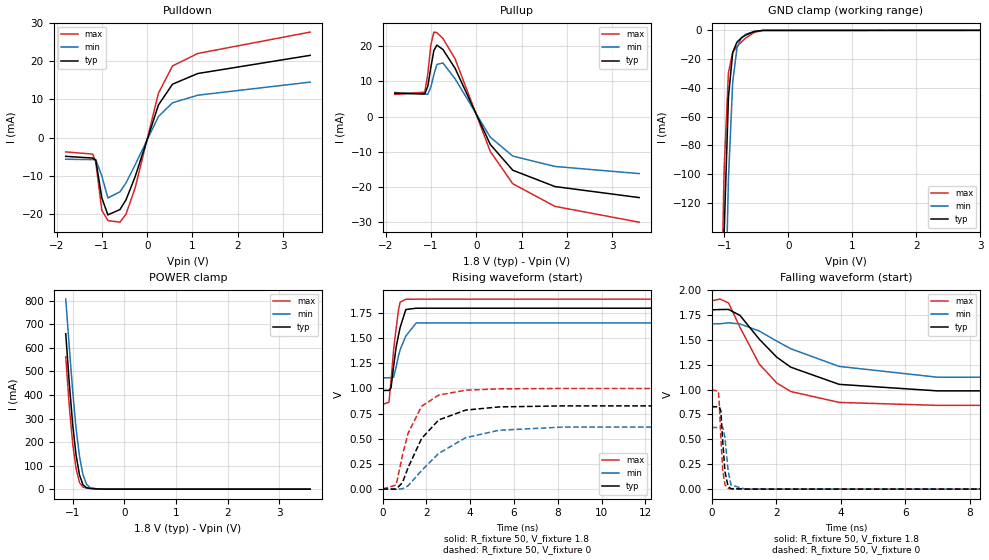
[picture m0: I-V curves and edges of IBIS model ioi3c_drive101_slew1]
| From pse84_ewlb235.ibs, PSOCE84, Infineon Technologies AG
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[Model] ioi3c_drive101_slew1
Model_type I/O
Enable   Active-High
Vinl  =  0.54
Vinh  =  1.26
Vmeas =  0.9
Cref  =  15e-12
| Capacitance   typ   min   max
C_comp   9.12545e-13 8.87504e-13 9.42456e-13
| Variables   typ   min   max
[GND Clamp Reference]   0   0   0
[POWER Clamp Reference]   1.8   1.66   1.89
[Pulldown Reference]   0   0   0
[Pullup Reference]   1.8   1.66   1.89
[Temperature Range]   25   125   -40
[Voltage Range]   1.8   1.66   1.89
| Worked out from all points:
|   slope of the pulldown table from 0 to 0.27 V, typ, clamps not added: 29.6 ohm
|   slope of the pullup table from 0 to 0.27 V, typ, clamps not added: 38.6 ohm
|   GND clamp passes 1 mA (typ) near -0.55 V on its own axis
|   POWER clamp passes 1 mA (typ) near -0.54 V on its own axis
|   falling waveform, R_fixture 50, V_fixture 1.8: 20-80 % time 1.77ns typ, 2.48ns min, 1.28ns max; typ from 1.8 V to 0.981 V
|   falling waveform, R_fixture 50, V_fixture 0: 20-80 % time 104ps typ, 118ps min, 95.9ps max; typ from 0.827 V to 0 V
|   rising waveform, R_fixture 50, V_fixture 1.8: 20-80 % time 362ps typ, 500ps min, 289ps max; typ from 0.981 V to 1.8 V
|   rising waveform, R_fixture 50, V_fixture 0: 20-80 % time 1.33ns typ, 2.06ns min, 908ps max; typ from 0 V to 0.827 V
[GND Clamp]
| Voltage   I(typ)   I(min)   I(max)
-1.204V   -737.9mA   -831.5mA   -678.7mA
-1.07V    -303.2mA   -410.8mA   -239.8mA
-1.003V   -139.9mA   -232.2mA   -95.74mA
-936.6mV  -46.51mA   -103.5mA   -29.5mA
-869.7mV  -15.31mA   -35.88mA   -15.36mA
-802.8mV  -8.166mA   -12.13mA   -11.29mA
-735.9mV  -5.335mA   -5.292mA   -8.195mA
-669mV    -3.356mA   -2.85mA    -5.457mA
-535.2mV  -837.9uA   -772uA     -1.483mA
-401.4mV  -47.36uA   -84.85uA   -76.77uA
3.6V      0A         0A         0A
[POWER Clamp]
| Voltage   I(typ)   I(min)   I(max)
-1.137V   660mA      807.5mA    561.8mA
-1.07V    454.5mA    608.2mA    356.2mA
-1.003V   275.7mA    418.4mA    193.6mA
-936.6mV  143.5mA    257.2mA    86.91mA
-869.7mV  59.43mA    137.9mA    27.31mA
-802.8mV  18.8mA     60.93mA    8.704mA
-735.9mV  6.231mA    21.35mA    5.155mA
-669mV    3.127mA    6.887mA    3.44mA
-535.2mV  940.9uA    1.232mA    1.058mA
-334.5mV  16.1uA     59.03uA    7.686uA
3.6V      0A         0A         0A
[Pulldown]
| Voltage   I(typ)   I(min)   I(max)
-1.8V     -4.871mA   -5.633mA   -3.71mA
-1.204V   -5.323mA   -5.738mA   -4.292mA
-1.137V   -5.876mA   -5.739mA   -6.357mA
-1.003V   -15.72mA   -10mA      -18.97mA
-869.7mV  -20.17mA   -15.75mA   -21.66mA
-602.1mV  -18.78mA   -14.16mA   -22.09mA
-468.3mV  -16.23mA   -11.81mA   -19.97mA
-267.6mV  -10.22mA   -7.094mA   -13.16mA
248.3mV   8.571mA    5.543mA    11.64mA
558.6mV   13.99mA    9.121mA    18.76mA
1.117V    16.78mA    11.11mA    22.02mA
3.6V      21.53mA    14.53mA    27.61mA
[Pullup]
| Voltage   I(typ)   I(min)   I(max)
-1.8V     6.618mA    6.849mA    6.297mA
-1.137V   6.463mA    6.354mA    6.946mA
-1.07V    8.656mA    6.373mA    12.14mA
-1.003V   13.95mA    8.378mA    20.29mA
-936.6mV  18.75mA    11.92mA    23.98mA
-869.7mV  20.28mA    14.79mA    23.82mA
-735.9mV  19.04mA    15.22mA    22.18mA
-468.3mV  13.73mA    10.74mA    16.43mA
310.3mV   -7.896mA   -5.832mA   -9.863mA
806.9mV   -15.2mA    -11.18mA   -19.03mA
1.738V    -19.83mA   -14.13mA   -25.45mA
3.6V      -22.96mA   -16.16mA   -29.94mA
[Ramp]
dV/dt_r   0.496158/1.32814n  0.371421/2.05761n  0.59959/0.907764n
dV/dt_f   0.491626/1.77151n  0.332563/2.48026n  0.629541/1.27902n
R_load = 50
[Falling Waveform]
R_fixture = 50
V_fixture = 1.8
V_fixture_min = 1.66
V_fixture_max = 1.89
| Time   V(typ)   V(min)   V(max)
0s        1.8V       1.66V      1.89V
262.4ps   1.803V     1.66V      1.908V
526.5ps   1.804V     1.67V      1.869V
881.5ps   1.744V     1.658V     1.625V
1.48ns    1.505V     1.587V     1.255V
2.02ns    1.325V     1.486V     1.066V
2.457ns   1.224V     1.409V     980mV
3.955ns   1.052V     1.232V     870.7mV
6.996ns   986.6mV    1.124V     841.1mV
800ns     980.6mV    1.106V     840.8mV
[Falling Waveform]
R_fixture = 50
V_fixture = 0
V_fixture_min = 0
V_fixture_max = 0
| Time   V(typ)   V(min)   V(max)
0s        826.9mV    619mV      999.3mV
212ps     826.7mV    619mV      981.2mV
237.1ps   827mV      619mV      872.8mV
287.6ps   784.7mV    618.9mV    515.5mV
348.7ps   468.7mV    620.1mV    180.2mV
415.8ps   173.5mV    517.1mV    44.89mV
514.4ps   25.08mV    182.1mV    7.14mV
601.2ps   5.478mV    41.65mV    2.274mV
1.042ns   1.095mV    883.2uV    773.2uV
800ns     10.07nV    682.1nV    3.767nV
[Rising Waveform]
R_fixture = 50
V_fixture = 1.8
V_fixture_min = 1.66
V_fixture_max = 1.89
| Time   V(typ)   V(min)   V(max)
0s        980.6mV    1.106V     840.8mV
294.1ps   980.8mV    1.106V     863.5mV
386.5ps   1.006V     1.106V     1.079V
509.8ps   1.228V     1.114V     1.395V
614.3ps   1.404V     1.208V     1.586V
727.3ps   1.529V     1.324V     1.781V
801.9ps   1.607V     1.385V     1.86V
1.062ns   1.786V     1.522V     1.888V
1.534ns   1.799V     1.652V     1.889V
800ns     1.8V       1.66V      1.89V
[Rising Waveform]
R_fixture = 50
V_fixture = 0
V_fixture_min = 0
V_fixture_max = 0
| Time   V(typ)   V(min)   V(max)
0s        10.07nV    681.9nV    3.769nV
621.5ps   -1.659mV   -1.853mV   39.55mV
908.9ps   63.31mV    1.554mV    334.8mV
1.164ns   211.8mV    31.42mV    553mV
1.782ns   502.2mV    184mV      823.3mV
2.56ns    686.7mV    353.3mV    933.9mV
3.788ns   784.7mV    509.8mV    982.9mV
5.315ns   816.7mV    584.4mV    996.7mV
8.238ns   826.9mV    616.2mV    1V
50ns      826.9mV    619mV      999.3mV
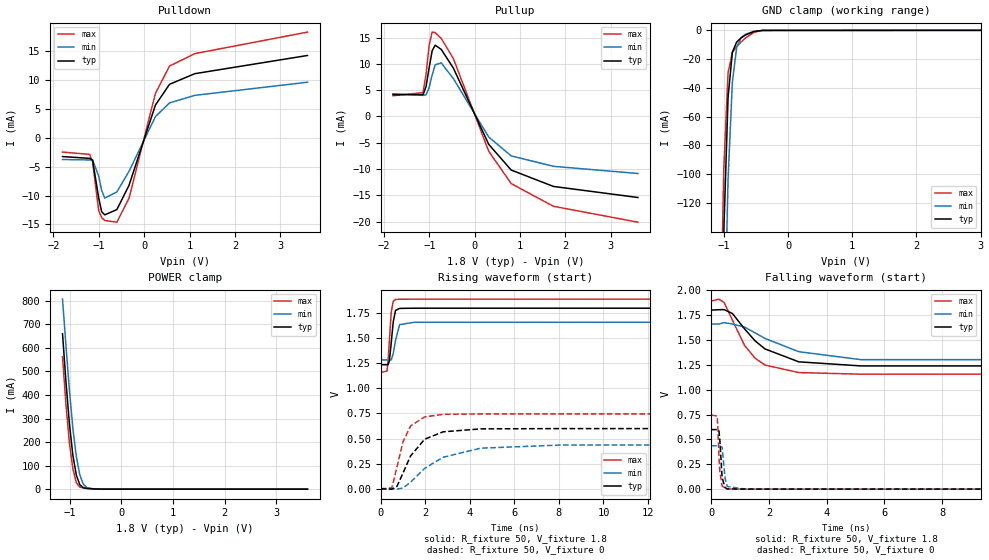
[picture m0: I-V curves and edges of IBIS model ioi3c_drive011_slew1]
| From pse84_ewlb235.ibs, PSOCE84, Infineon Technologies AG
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[Model] ioi3c_drive011_slew1
Model_type I/O
Enable   Active-High
Vinl  =  0.54
Vinh  =  1.26
Vmeas =  0.9
Cref  =  15e-12
| Capacitance   typ   min   max
C_comp   9.12545e-13 8.87504e-13 9.42456e-13
| Variables   typ   min   max
[GND Clamp Reference]   0   0   0
[POWER Clamp Reference]   1.8   1.66   1.89
[Pulldown Reference]   0   0   0
[Pullup Reference]   1.8   1.66   1.89
[Temperature Range]   25   125   -40
[Voltage Range]   1.8   1.66   1.89
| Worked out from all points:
|   slope of the pulldown table from 0 to 0.27 V, typ, clamps not added: 44.8 ohm
|   slope of the pullup table from 0 to 0.27 V, typ, clamps not added: 57.7 ohm
|   GND clamp passes 1 mA (typ) near -0.55 V on its own axis
|   POWER clamp passes 1 mA (typ) near -0.54 V on its own axis
|   falling waveform, R_fixture 50, V_fixture 1.8: 20-80 % time 1.28ns typ, 1.94ns min, 900ps max; typ from 1.8 V to 1.24 V
|   falling waveform, R_fixture 50, V_fixture 0: 20-80 % time 76.2ps typ, 84.8ps min, 71.7ps max; typ from 0.599 V to 0 V
|   rising waveform, R_fixture 50, V_fixture 1.8: 20-80 % time 148ps typ, 193ps min, 126ps max; typ from 1.24 V to 1.8 V
|   rising waveform, R_fixture 50, V_fixture 0: 20-80 % time 950ps typ, 1.8ns min, 582ps max; typ from 0 V to 0.599 V
[GND Clamp]
| Voltage   I(typ)   I(min)   I(max)
-1.204V   -737.9mA   -831.5mA   -678.7mA
-1.07V    -303.2mA   -410.8mA   -239.8mA
-1.003V   -139.9mA   -232.2mA   -95.74mA
-936.6mV  -46.51mA   -103.5mA   -29.5mA
-869.7mV  -15.31mA   -35.88mA   -15.36mA
-802.8mV  -8.166mA   -12.13mA   -11.29mA
-735.9mV  -5.335mA   -5.292mA   -8.195mA
-669mV    -3.356mA   -2.85mA    -5.457mA
-535.2mV  -837.9uA   -772uA     -1.483mA
-401.4mV  -47.36uA   -84.85uA   -76.77uA
3.6V      0A         0A         0A
[POWER Clamp]
| Voltage   I(typ)   I(min)   I(max)
-1.137V   660mA      807.5mA    561.8mA
-1.07V    454.5mA    608.2mA    356.2mA
-1.003V   275.7mA    418.4mA    193.6mA
-936.6mV  143.5mA    257.2mA    86.91mA
-869.7mV  59.43mA    137.9mA    27.31mA
-802.8mV  18.8mA     60.93mA    8.704mA
-735.9mV  6.231mA    21.35mA    5.155mA
-669mV    3.127mA    6.887mA    3.44mA
-535.2mV  940.9uA    1.232mA    1.058mA
-334.5mV  16.1uA     59.03uA    7.686uA
3.6V      0A         0A         0A
[Pulldown]
| Voltage   I(typ)   I(min)   I(max)
-1.8V     -3.256mA   -3.767mA   -2.48mA
-1.204V   -3.562mA   -3.839mA   -2.873mA
-1.137V   -3.887mA   -3.84mA    -4.196mA
-1.003V   -10.42mA   -6.637mA   -12.57mA
-936.6mV  -12.81mA   -9.105mA   -13.83mA
-869.7mV  -13.35mA   -10.45mA   -14.33mA
-602.1mV  -12.44mA   -9.384mA   -14.62mA
-334.5mV  -8.239mA   -5.816mA   -10.47mA
248.3mV   5.671mA    3.669mA    7.698mA
558.6mV   9.256mA    6.034mA    12.42mA
1.117V    11.1mA     7.344mA    14.57mA
3.6V      14.25mA    9.618mA    18.3mA
[Pullup]
| Voltage   I(typ)   I(min)   I(max)
-1.8V     4.157mA    4.308mA    3.943mA
-1.137V   4.15mA     4.01mA     4.534mA
-1.07V    5.698mA    4.112mA    8.074mA
-1.003V   9.236mA    5.498mA    13.51mA
-936.6mV  12.47mA    7.86mA     16.03mA
-869.7mV  13.54mA    9.82mA     15.93mA
-735.9mV  12.74mA    10.17mA    14.84mA
-468.3mV  9.185mA    7.186mA    11mA
310.3mV   -5.289mA   -3.904mA   -6.611mA
806.9mV   -10.18mA   -7.487mA   -12.75mA
1.738V    -13.29mA   -9.467mA   -17.06mA
3.6V      -15.39mA   -10.83mA   -20.08mA
[Ramp]
dV/dt_r   0.359394/0.949873n  0.261566/1.80047n  0.447321/0.582224n
dV/dt_f   0.338346/1.2829n  0.225656/1.93816n  0.439449/0.900277n
R_load = 50
[Falling Waveform]
R_fixture = 50
V_fixture = 1.8
V_fixture_min = 1.66
V_fixture_max = 1.89
| Time   V(typ)   V(min)   V(max)
0s        1.8V       1.66V      1.89V
264.3ps   1.804V     1.66V      1.911V
449.1ps   1.805V     1.674V     1.876V
735.1ps   1.766V     1.66V      1.7V
1.156ns   1.611V     1.629V     1.445V
1.523ns   1.49V      1.571V     1.316V
1.862ns   1.41V      1.515V     1.248V
3.032ns   1.28V      1.382V     1.172V
5.18ns    1.239V     1.302V     1.156V
800ns     1.236V     1.284V     1.158V
[Falling Waveform]
R_fixture = 50
V_fixture = 0
V_fixture_min = 0
V_fixture_max = 0
| Time   V(typ)   V(min)   V(max)
0s        599mV      435.9mV    745.5mV
205.4ps   598.9mV    435.9mV    735mV
229.1ps   598.7mV    435.9mV    639.3mV
266.3ps   594.4mV    435.9mV    353.4mV
296.5ps   508.5mV    435.8mV    186.6mV
379.1ps   118.3mV    419.4mV    32.25mV
480.3ps   15.18mV    111.9mV    3.712mV
554.8ps   2.984mV    26.71mV    1.757mV
1.166ns   782.9uV    825.8uV    582.5uV
800ns     13.01nV    842.7nV    5.03nV
[Rising Waveform]
R_fixture = 50
V_fixture = 1.8
V_fixture_min = 1.66
V_fixture_max = 1.89
| Time   V(typ)   V(min)   V(max)
0s        1.236V     1.284V     1.158V
283.3ps   1.236V     1.284V     1.173V
326.3ps   1.235V     1.284V     1.263V
387.6ps   1.272V     1.284V     1.474V
472.1ps   1.455V     1.283V     1.76V
561.6ps   1.663V     1.347V     1.869V
666.1ps   1.777V     1.48V      1.886V
847.1ps   1.797V     1.635V     1.888V
1.512ns   1.799V     1.659V     1.889V
800ns     1.8V       1.66V      1.89V
[Rising Waveform]
R_fixture = 50
V_fixture = 0
V_fixture_min = 0
V_fixture_max = 0
| Time   V(typ)   V(min)   V(max)
0s        13.01nV    842.5nV    5.03nV
498.4ps   -4.024mV   -1.167mV   8.855mV
727.3ps   23.02mV    -3.106mV   213.4mV
999.5ps   156.1mV    6.953mV    467.8mV
1.338ns   326.5mV    65.1mV     625mV
1.971ns   493.7mV    203.1mV    716.1mV
2.802ns   567.4mV    314mV      741.6mV
4.492ns   596.7mV    404.5mV    745.9mV
8.101ns   599.5mV    435.8mV    745.6mV
50ns      599mV      435.9mV    745.5mV
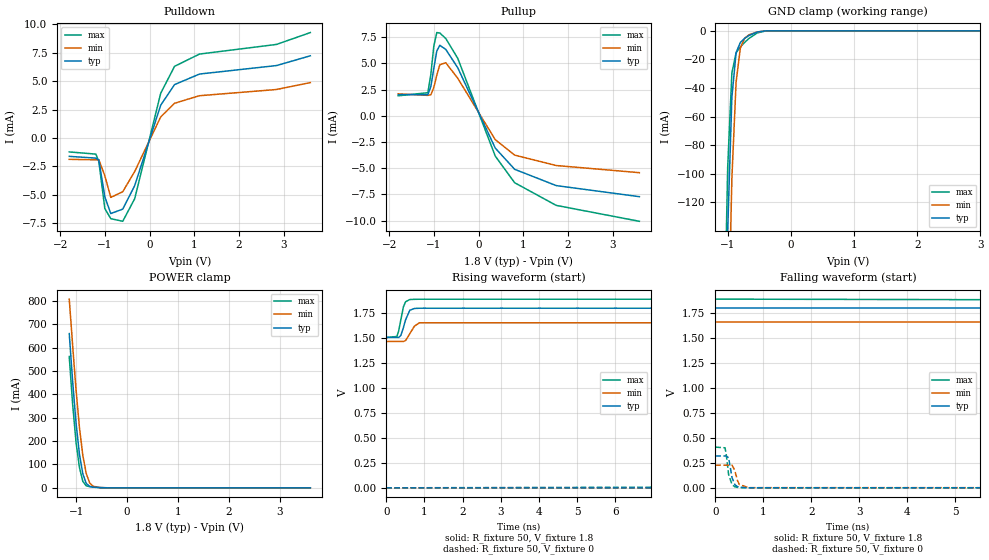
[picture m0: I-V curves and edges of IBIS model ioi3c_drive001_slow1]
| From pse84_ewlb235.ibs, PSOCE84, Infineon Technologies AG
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[Model] ioi3c_drive001_slow1
Model_type I/O
Enable   Active-High
Vinl  =  0.54
Vinh  =  1.26
Vmeas =  0.9
Cref  =  15e-12
| Capacitance   typ   min   max
C_comp   9.12545e-13 8.87504e-13 9.42456e-13
| Variables   typ   min   max
[GND Clamp Reference]   0   0   0
[POWER Clamp Reference]   1.8   1.66   1.89
[Pulldown Reference]   0   0   0
[Pullup Reference]   1.8   1.66   1.89
[Temperature Range]   25   125   -40
[Voltage Range]   1.8   1.66   1.89
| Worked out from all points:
|   slope of the pulldown table from 0 to 0.27 V, typ, clamps not added: 87.9 ohm
|   slope of the pullup table from 0 to 0.27 V, typ, clamps not added: 115 ohm
|   GND clamp passes 1 mA (typ) near -0.55 V on its own axis
|   POWER clamp passes 1 mA (typ) near -0.54 V on its own axis
|   falling waveform, R_fixture 50, V_fixture 1.8: 20-80 % time 64.9ns typ, 99.2ns min, 37.6ns max; typ from 1.8 V to 1.51 V
|   falling waveform, R_fixture 50, V_fixture 0: 20-80 % time 74.8ps typ, 82.7ps min, 70.6ps max; typ from 0.319 V to 0 V
|   rising waveform, R_fixture 50, V_fixture 1.8: 20-80 % time 139ps typ, 182ps min, 118ps max; typ from 1.51 V to 1.8 V
|   rising waveform, R_fixture 50, V_fixture 0: 20-80 % time 70.6ns typ, 105ns min, 43.3ns max; typ from 0 V to 0.319 V
[GND Clamp]
| Voltage   I(typ)   I(min)   I(max)
-1.204V   -737.9mA   -831.5mA   -678.7mA
-1.07V    -303.2mA   -410.8mA   -239.8mA
-1.003V   -139.9mA   -232.2mA   -95.74mA
-936.6mV  -46.51mA   -103.5mA   -29.5mA
-869.7mV  -15.31mA   -35.88mA   -15.36mA
-802.8mV  -8.166mA   -12.13mA   -11.29mA
-735.9mV  -5.335mA   -5.292mA   -8.195mA
-669mV    -3.356mA   -2.85mA    -5.457mA
-535.2mV  -837.9uA   -772uA     -1.483mA
-401.4mV  -47.36uA   -84.85uA   -76.77uA
3.6V      0A         0A         0A
[POWER Clamp]
| Voltage   I(typ)   I(min)   I(max)
-1.137V   660mA      807.5mA    561.8mA
-1.07V    454.5mA    608.2mA    356.2mA
-1.003V   275.7mA    418.4mA    193.6mA
-936.6mV  143.5mA    257.2mA    86.91mA
-869.7mV  59.43mA    137.9mA    27.31mA
-802.8mV  18.8mA     60.93mA    8.704mA
-735.9mV  6.231mA    21.35mA    5.155mA
-669mV    3.127mA    6.887mA    3.44mA
-535.2mV  940.9uA    1.232mA    1.058mA
-334.5mV  16.1uA     59.03uA    7.686uA
3.6V      0A         0A         0A
[Pulldown]
| Voltage   I(typ)   I(min)   I(max)
-1.8V     -1.61mA    -1.872mA   -1.221mA
-1.204V   -1.764mA   -1.912mA   -1.412mA
-1.137V   -1.929mA   -1.913mA   -2.069mA
-1.003V   -5.177mA   -3.313mA   -6.201mA
-869.7mV  -6.636mA   -5.217mA   -7.086mA
-602.1mV  -6.248mA   -4.717mA   -7.318mA
-334.5mV  -4.187mA   -2.945mA   -5.335mA
248.3mV   2.889mA    1.862mA    3.936mA
558.6mV   4.697mA    3.058mA    6.305mA
1.117V    5.626mA    3.721mA    7.382mA
2.843V    6.372mA    4.268mA    8.23mA
3.6V      7.231mA    4.876mA    9.272mA
[Pullup]
| Voltage   I(typ)   I(min)   I(max)
-1.8V     2.025mA    2.102mA    1.915mA
-1.137V   2.025mA    1.955mA    2.21mA
-1.07V    2.811mA    2.015mA    3.989mA
-1.003V   4.576mA    2.719mA    6.691mA
-936.6mV  6.194mA    3.897mA    7.948mA
-869.7mV  6.732mA    4.882mA    7.907mA
-735.9mV  6.34mA     5.065mA    7.379mA
-468.3mV  4.591mA    3.59mA     5.496mA
372.4mV   -3.077mA   -2.272mA   -3.838mA
806.9mV   -5.099mA   -3.747mA   -6.382mA
1.738V    -6.654mA   -4.738mA   -8.542mA
3.6V      -7.71mA    -5.421mA   -10.06mA
[Ramp]
dV/dt_r   0.191686/70.5594n  0.136324/0.104993u  0.244809/43.3038n
dV/dt_f   0.176397/64.9066n  0.116691/99.1914n  0.230253/37.5776n
R_load = 50
[Falling Waveform]
R_fixture = 50
V_fixture = 1.8
V_fixture_min = 1.66
V_fixture_max = 1.89
| Time   V(typ)   V(min)   V(max)
0s        1.8V       1.66V      1.89V
8.158ns   1.8V       1.66V      1.882V
16.81ns   1.789V     1.66V      1.801V
31.43ns   1.73V      1.647V     1.68V
49.66ns   1.66V      1.617V     1.593V
70.86ns   1.603V     1.58V      1.546V
104.3ns   1.553V     1.537V     1.518V
167.3ns   1.518V     1.494V     1.507V
259.2ns   1.508V     1.473V     1.506V
800ns     1.506V     1.466V     1.506V
[Falling Waveform]
R_fixture = 50
V_fixture = 0
V_fixture_min = 0
V_fixture_max = 0
| Time   V(typ)   V(min)   V(max)
0s        319.5mV    227.2mV    408mV
203.2ps   319.4mV    227.2mV    401.1mV
225.8ps   319.2mV    227.2mV    349.1mV
278.8ps   301.3mV    227.2mV    132.6mV
350.9ps   100.9mV    227mV      31.04mV
408.7ps   32.29mV    174.6mV    11.09mV
459.7ps   12.93mV    77.35mV    4.823mV
502.5ps   6.343mV    34.23mV    2.754mV
691.4ps   1.071mV    1.973mV    825.3uV
800ns     18.14nV    1.091uV    7.409nV
[Rising Waveform]
R_fixture = 50
V_fixture = 1.8
V_fixture_min = 1.66
V_fixture_max = 1.89
| Time   V(typ)   V(min)   V(max)
0s        1.506V     1.466V     1.506V
280.7ps   1.506V     1.466V     1.516V
324.4ps   1.506V     1.466V     1.569V
380.4ps   1.525V     1.466V     1.678V
451.3ps   1.606V     1.466V     1.814V
507.5ps   1.683V     1.475V     1.864V
618.7ps   1.779V     1.544V     1.886V
739.1ps   1.796V     1.619V     1.888V
868.6ps   1.799V     1.653V     1.889V
800ns     1.8V       1.66V      1.89V
[Rising Waveform]
R_fixture = 50
V_fixture = 0
V_fixture_min = 0
V_fixture_max = 0
| Time   V(typ)   V(min)   V(max)
0s        18.12nV    1.09uV     7.403nV
9.318ns   -142uV     -261.3uV   8.053mV
18.18ns   13.88mV    1.254mV    82.78mV
31.7ns    68.86mV    16.71mV    193.8mV
54.78ns   156.6mV    61.37mV    307.4mV
78.23ns   217.8mV    103.7mV    361.3mV
111.7ns   267.8mV    148.3mV    392.1mV
177.5ns   305.7mV    195.4mV    406.1mV
277.8ns   317.6mV    219.3mV    407.9mV
800ns     319.5mV    227.2mV    408mV
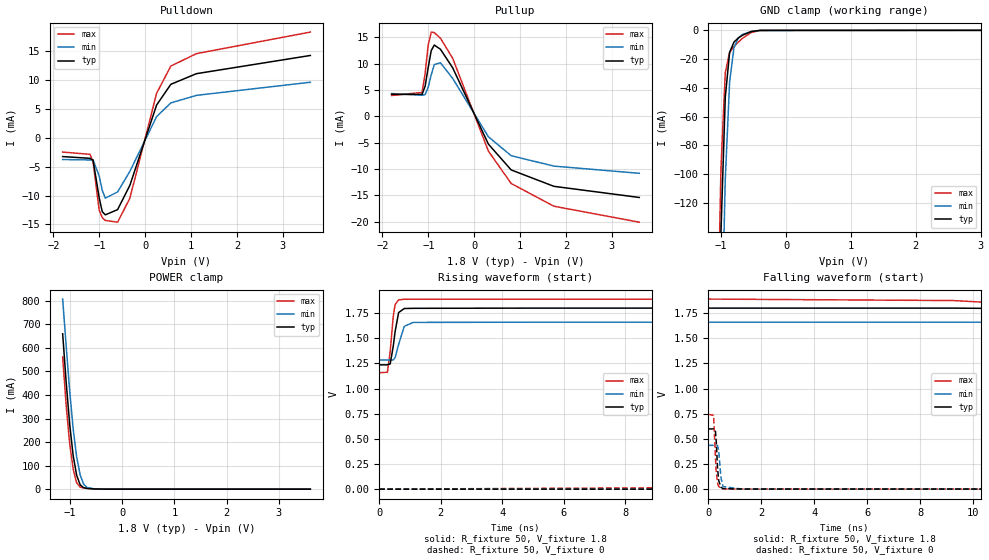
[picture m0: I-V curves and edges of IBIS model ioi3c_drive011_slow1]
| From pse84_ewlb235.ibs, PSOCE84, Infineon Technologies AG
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[Model] ioi3c_drive011_slow1
Model_type I/O
Enable   Active-High
Vinl  =  0.54
Vinh  =  1.26
Vmeas =  0.9
Cref  =  15e-12
| Capacitance   typ   min   max
C_comp   9.12545e-13 8.87504e-13 9.42456e-13
| Variables   typ   min   max
[GND Clamp Reference]   0   0   0
[POWER Clamp Reference]   1.8   1.66   1.89
[Pulldown Reference]   0   0   0
[Pullup Reference]   1.8   1.66   1.89
[Temperature Range]   25   125   -40
[Voltage Range]   1.8   1.66   1.89
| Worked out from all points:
|   slope of the pulldown table from 0 to 0.27 V, typ, clamps not added: 44.8 ohm
|   slope of the pullup table from 0 to 0.27 V, typ, clamps not added: 57.7 ohm
|   GND clamp passes 1 mA (typ) near -0.55 V on its own axis
|   POWER clamp passes 1 mA (typ) near -0.54 V on its own axis
|   falling waveform, R_fixture 50, V_fixture 1.8: 20-80 % time 80.6ns typ, 120ns min, 47.9ns max; typ from 1.8 V to 1.24 V
|   falling waveform, R_fixture 50, V_fixture 0: 20-80 % time 78ps typ, 87ps min, 73.2ps max; typ from 0.599 V to 0 V
|   rising waveform, R_fixture 50, V_fixture 1.8: 20-80 % time 151ps typ, 197ps min, 128ps max; typ from 1.24 V to 1.8 V
|   rising waveform, R_fixture 50, V_fixture 0: 20-80 % time 87.3ns typ, 129ns min, 53.6ns max; typ from 0 V to 0.599 V
[GND Clamp]
| Voltage   I(typ)   I(min)   I(max)
-1.204V   -737.9mA   -831.5mA   -678.7mA
-1.07V    -303.2mA   -410.8mA   -239.8mA
-1.003V   -139.9mA   -232.2mA   -95.74mA
-936.6mV  -46.51mA   -103.5mA   -29.5mA
-869.7mV  -15.31mA   -35.88mA   -15.36mA
-802.8mV  -8.166mA   -12.13mA   -11.29mA
-735.9mV  -5.335mA   -5.292mA   -8.195mA
-669mV    -3.356mA   -2.85mA    -5.457mA
-535.2mV  -837.9uA   -772uA     -1.483mA
-401.4mV  -47.36uA   -84.85uA   -76.77uA
3.6V      0A         0A         0A
[POWER Clamp]
| Voltage   I(typ)   I(min)   I(max)
-1.137V   660mA      807.5mA    561.8mA
-1.07V    454.5mA    608.2mA    356.2mA
-1.003V   275.7mA    418.4mA    193.6mA
-936.6mV  143.5mA    257.2mA    86.91mA
-869.7mV  59.43mA    137.9mA    27.31mA
-802.8mV  18.8mA     60.93mA    8.704mA
-735.9mV  6.231mA    21.35mA    5.155mA
-669mV    3.127mA    6.887mA    3.44mA
-535.2mV  940.9uA    1.232mA    1.058mA
-334.5mV  16.1uA     59.03uA    7.686uA
3.6V      0A         0A         0A
[Pulldown]
| Voltage   I(typ)   I(min)   I(max)
-1.8V     -3.256mA   -3.768mA   -2.479mA
-1.204V   -3.561mA   -3.841mA   -2.868mA
-1.137V   -3.885mA   -3.841mA   -4.188mA
-1.003V   -10.42mA   -6.639mA   -12.56mA
-936.6mV  -12.8mA    -9.106mA   -13.82mA
-869.7mV  -13.35mA   -10.45mA   -14.32mA
-602.1mV  -12.44mA   -9.384mA   -14.62mA
-334.5mV  -8.238mA   -5.816mA   -10.47mA
248.3mV   5.671mA    3.669mA    7.698mA
558.6mV   9.256mA    6.034mA    12.42mA
1.117V    11.1mA     7.344mA    14.57mA
3.6V      14.25mA    9.615mA    18.3mA
[Pullup]
| Voltage   I(typ)   I(min)   I(max)
-1.8V     4.154mA    4.305mA    3.938mA
-1.137V   4.137mA    4.003mA    4.509mA
-1.07V    5.68mA     4.103mA    8.035mA
-1.003V   9.21mA     5.486mA    13.46mA
-936.6mV  12.44mA    7.843mA    15.96mA
-869.7mV  13.5mA     9.799mA    15.87mA
-735.9mV  12.71mA    10.14mA    14.8mA
-468.3mV  9.181mA    7.178mA    10.99mA
310.3mV   -5.289mA   -3.901mA   -6.611mA
806.9mV   -10.18mA   -7.48mA    -12.75mA
1.738V    -13.29mA   -9.457mA   -17.06mA
3.6V      -15.4mA    -10.82mA   -20.09mA
[Ramp]
dV/dt_r   0.359384/87.3236n  0.261244/0.128801u  0.447318/53.622n
dV/dt_f   0.338342/80.6004n  0.225608/0.119761u  0.439446/47.9083n
R_load = 50
[Falling Waveform]
R_fixture = 50
V_fixture = 1.8
V_fixture_min = 1.66
V_fixture_max = 1.89
| Time   V(typ)   V(min)   V(max)
0s        1.8V       1.66V      1.89V
9.251ns   1.8V       1.66V      1.875V
18.3ns    1.781V     1.659V     1.746V
35.48ns   1.671V     1.633V     1.522V
55.25ns   1.551V     1.578V     1.36V
80.32ns   1.439V     1.508V     1.254V
122.1ns   1.333V     1.422V     1.186V
185.5ns   1.268V     1.348V     1.162V
294.1ns   1.241V     1.302V     1.158V
800ns     1.236V     1.284V     1.158V
[Falling Waveform]
R_fixture = 50
V_fixture = 0
V_fixture_min = 0
V_fixture_max = 0
| Time   V(typ)   V(min)   V(max)
0s        599mV      435.5mV    745.5mV
204.5ps   598.9mV    435.5mV    733.4mV
268.3ps   589.5mV    435.5mV    345.2mV
302.1ps   480.1mV    435.3mV    170.6mV
354ps     203.2mV    434.8mV    60.26mV
398.7ps   83.18mV    375.8mV    25.45mV
480.8ps   18.82mV    114.4mV    6.838mV
561.6ps   5.482mV    25.64mV    2.926mV
1.284ns   1.084mV    1.021mV    1.139mV
800ns     13.1nV     843.8nV    5.091nV
[Rising Waveform]
R_fixture = 50
V_fixture = 1.8
V_fixture_min = 1.66
V_fixture_max = 1.89
| Time   V(typ)   V(min)   V(max)
0s        1.236V     1.284V     1.158V
265.5ps   1.236V     1.284V     1.162V
356.2ps   1.245V     1.284V     1.368V
454.6ps   1.419V     1.284V     1.715V
516ps     1.567V     1.308V     1.835V
630.3ps   1.756V     1.439V     1.882V
813.9ps   1.796V     1.619V     1.888V
1.107ns   1.798V     1.658V     1.888V
5.031ns   1.8V       1.66V      1.889V
800ns     1.8V       1.66V      1.89V
[Rising Waveform]
R_fixture = 50
V_fixture = 0
V_fixture_min = 0
V_fixture_max = 0
| Time   V(typ)   V(min)   V(max)
0s        13.07nV    842.6nV    5.082nV
10.93ns   -64.15uV   -184.5uV   16.34mV
20.38ns   24.61mV    2.685mV    135mV
37.2ns    130.5mV    36mV       341.8mV
65.1ns    292.3mV    123.2mV    552.4mV
90.18ns   394.7mV    194.4mV    645.5mV
132ns     495.5mV    282.7mV    711mV
204.3ns   566.6mV    367.2mV    739.7mV
310.5ns   592.9mV    414.4mV    745.1mV
800ns     599mV      435.4mV    745.5mV
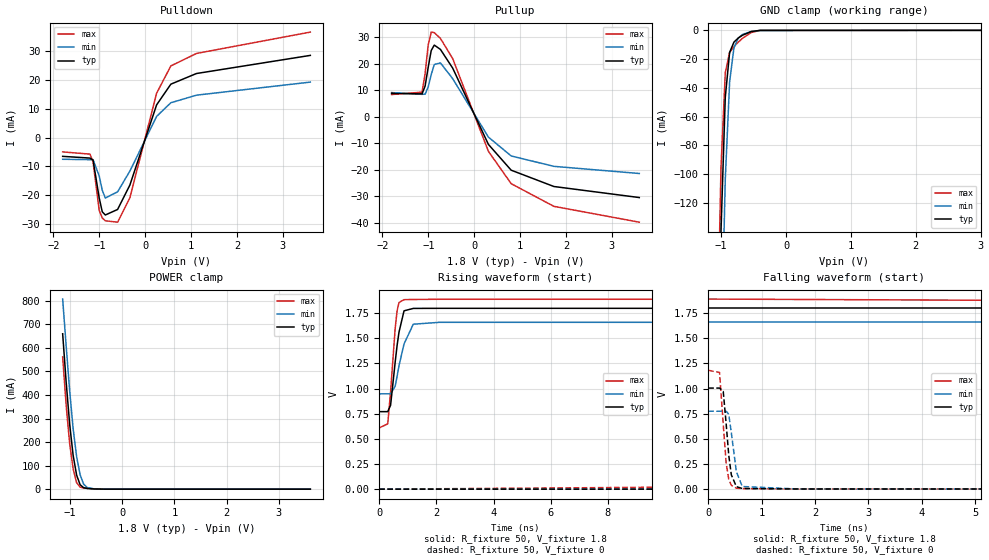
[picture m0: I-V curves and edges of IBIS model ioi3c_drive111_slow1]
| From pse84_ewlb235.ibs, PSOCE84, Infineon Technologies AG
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[Model] ioi3c_drive111_slow1
Model_type I/O
Enable   Active-High
Vinl  =  0.54
Vinh  =  1.26
Vmeas =  0.9
Cref  =  15e-12
| Capacitance   typ   min   max
C_comp   9.12545e-13 8.87504e-13 9.42456e-13
| Variables   typ   min   max
[GND Clamp Reference]   0   0   0
[POWER Clamp Reference]   1.8   1.66   1.89
[Pulldown Reference]   0   0   0
[Pullup Reference]   1.8   1.66   1.89
[Temperature Range]   25   125   -40
[Voltage Range]   1.8   1.66   1.89
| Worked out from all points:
|   slope of the pulldown table from 0 to 0.27 V, typ, clamps not added: 22.4 ohm
|   slope of the pullup table from 0 to 0.27 V, typ, clamps not added: 29 ohm
|   GND clamp passes 1 mA (typ) near -0.55 V on its own axis
|   POWER clamp passes 1 mA (typ) near -0.54 V on its own axis
|   falling waveform, R_fixture 50, V_fixture 1.8: 20-80 % time 100ns typ, 151ns min, 56.9ns max; typ from 1.8 V to 0.771 V
|   falling waveform, R_fixture 50, V_fixture 0: 20-80 % time 100ps typ, 114ps min, 92ps max; typ from 1 V to 0 V
|   rising waveform, R_fixture 50, V_fixture 1.8: 20-80 % time 253ps typ, 354ps min, 198ps max; typ from 0.771 V to 1.8 V
|   rising waveform, R_fixture 50, V_fixture 0: 20-80 % time 104ns typ, 159ns min, 61.3ns max; typ from 0 V to 1 V
[GND Clamp]
| Voltage   I(typ)   I(min)   I(max)
-1.204V   -737.9mA   -831.5mA   -678.7mA
-1.07V    -303.2mA   -410.8mA   -239.8mA
-1.003V   -139.9mA   -232.2mA   -95.74mA
-936.6mV  -46.51mA   -103.5mA   -29.5mA
-869.7mV  -15.31mA   -35.88mA   -15.36mA
-802.8mV  -8.166mA   -12.13mA   -11.29mA
-735.9mV  -5.335mA   -5.292mA   -8.195mA
-669mV    -3.356mA   -2.85mA    -5.457mA
-535.2mV  -837.9uA   -772uA     -1.483mA
-401.4mV  -47.36uA   -84.85uA   -76.77uA
3.6V      0A         0A         0A
[POWER Clamp]
| Voltage   I(typ)   I(min)   I(max)
-1.137V   660mA      807.5mA    561.8mA
-1.07V    454.5mA    608.2mA    356.2mA
-1.003V   275.7mA    418.4mA    193.6mA
-936.6mV  143.5mA    257.2mA    86.91mA
-869.7mV  59.43mA    137.9mA    27.31mA
-802.8mV  18.8mA     60.93mA    8.704mA
-735.9mV  6.231mA    21.35mA    5.155mA
-669mV    3.127mA    6.887mA    3.44mA
-535.2mV  940.9uA    1.232mA    1.058mA
-334.5mV  16.1uA     59.03uA    7.686uA
3.6V      0A         0A         0A
[Pulldown]
| Voltage   I(typ)   I(min)   I(max)
-1.8V     -6.515mA   -7.529mA   -4.967mA
-1.204V   -7.118mA   -7.666mA   -5.742mA
-1.137V   -7.829mA   -7.667mA   -8.467mA
-1.003V   -20.96mA   -13.32mA   -25.3mA
-936.6mV  -25.76mA   -18.28mA   -27.87mA
-869.7mV  -26.87mA   -20.98mA   -28.88mA
-602.1mV  -24.95mA   -18.82mA   -29.37mA
-334.5mV  -16.48mA   -11.64mA   -20.92mA
248.3mV   11.35mA    7.346mA    15.39mA
558.6mV   18.54mA    12.09mA    24.87mA
1.117V    22.24mA    14.72mA    29.2mA
3.6V      28.53mA    19.26mA    36.62mA
[Pullup]
| Voltage   I(typ)   I(min)   I(max)
-1.8V     8.734mA    9.037mA    8.303mA
-1.137V   8.551mA    8.383mA    9.206mA
-1.07V    11.49mA    8.441mA    16.12mA
-1.003V   18.53mA    11.12mA    26.96mA
-936.6mV  24.92mA    15.83mA    31.88mA
-869.7mV  26.97mA    19.66mA    31.67mA
-735.9mV  25.34mA    20.24mA    29.5mA
-468.3mV  18.27mA    14.3mA     21.87mA
310.3mV   -10.52mA   -7.762mA   -13.13mA
806.9mV   -20.25mA   -14.88mA   -25.34mA
1.738V    -26.41mA   -18.8mA    -33.9mA
3.6V      -30.58mA   -21.5mA    -39.88mA
[Ramp]
dV/dt_r   0.603084/0.103649u  0.464289/0.158569u  0.709184/61.277n
dV/dt_f   0.617509/0.100197u  0.426948/0.151051u  0.768574/56.9416n
R_load = 50
[Falling Waveform]
R_fixture = 50
V_fixture = 1.8
V_fixture_min = 1.66
V_fixture_max = 1.89
| Time   V(typ)   V(min)   V(max)
0s        1.8V       1.66V      1.89V
10.43ns   1.8V       1.66V      1.866V
21.4ns    1.76V      1.658V     1.648V
38.38ns   1.6V       1.615V     1.322V
71.81ns   1.308V     1.471V     918mV
103ns     1.117V     1.346V     744mV
136.4ns   985mV      1.24V      665.6mV
209.5ns   845.1mV    1.095V     618.5mV
330.2ns   784.3mV    994.9mV    609.6mV
800ns     770.8mV    948.4mV    609mV
[Falling Waveform]
R_fixture = 50
V_fixture = 0
V_fixture_min = 0
V_fixture_max = 0
| Time   V(typ)   V(min)   V(max)
0s        1.005V     774.9mV    1.182V
212.6ps   1.005V     774.9mV    1.16V
281.5ps   973.2mV    774.8mV    648.9mV
336ps     653.4mV    775.3mV    261mV
384.8ps   338.4mV    744.6mV    98.47mV
433.3ps   142.6mV    560.9mV    38.46mV
527.7ps   25.25mV    174.4mV    9.742mV
637.8ps   6.6mV      26.3mV     5.87mV
1.682ns   1.822mV    1.558mV    1.665mV
800ns     8.386nV    579.6nV    3.079nV
[Rising Waveform]
R_fixture = 50
V_fixture = 1.8
V_fixture_min = 1.66
V_fixture_max = 1.89
| Time   V(typ)   V(min)   V(max)
0s        770.8mV    947.8mV    609mV
297.4ps   770.9mV    947.8mV    649.9mV
397.6ps   835.1mV    947.9mV    970.6mV
558ps     1.264V     1.024V     1.601V
624.1ps   1.428V     1.122V     1.773V
692.1ps   1.562V     1.228V     1.856V
867.3ps   1.773V     1.444V     1.884V
1.191ns   1.797V     1.64V      1.886V
2.108ns   1.798V     1.659V     1.888V
800ns     1.8V       1.66V      1.89V
[Rising Waveform]
R_fixture = 50
V_fixture = 0
V_fixture_min = 0
V_fixture_max = 0
| Time   V(typ)   V(min)   V(max)
0s        8.316nV    576.2nV    3.071nV
13.03ns   223.2uV    -44.1uV    25.61mV
24.15ns   42.86mV    5.755mV    208mV
46.6ns    238.1mV    76.69mV    571.5mV
77.46ns   484.6mV    216.2mV    885.7mV
102.5ns   635mV      320.1mV    1.018V
144.3ns   798.8mV    459.2mV    1.117V
222.7ns   934.4mV    619.5mV    1.168V
338.7ns   989.1mV    719.8mV    1.18V
800ns     1.005V     773.8mV    1.182V
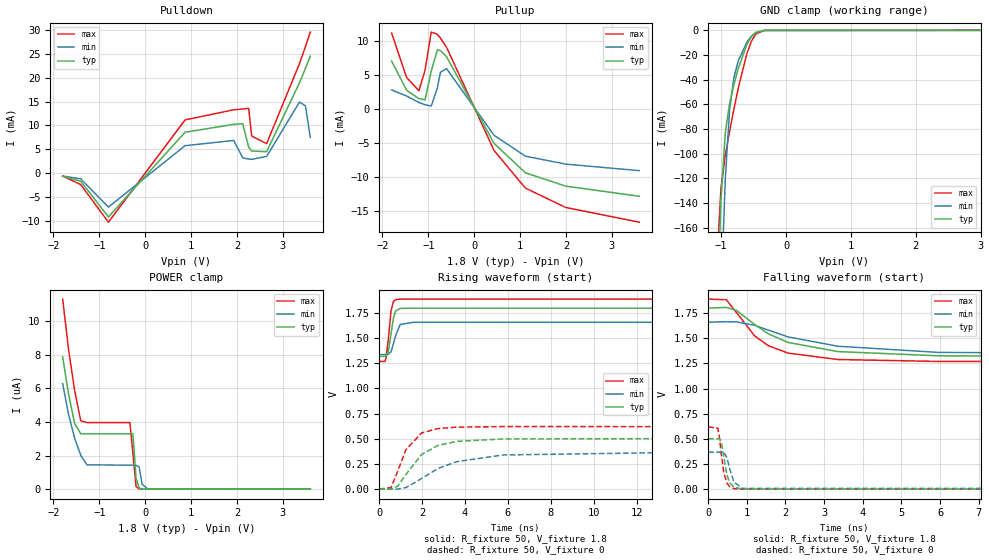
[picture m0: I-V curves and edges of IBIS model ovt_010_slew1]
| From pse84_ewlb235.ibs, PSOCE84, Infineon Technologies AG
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[Model] ovt_010_slew1
Model_type I/O
Enable   Active-High
Vinl  =  0.54
Vinh  =  1.26
Vmeas =  0.9
Cref  =  15e-12
| Capacitance   typ   min   max
C_comp   1.39974e-12   1.35992e-12   1.44753e-12
| Variables   typ   min   max
[GND Clamp Reference]   0   0   0
[POWER Clamp Reference]   1.8   1.66   1.89
[Pulldown Reference]   0   0   0
[Pullup Reference]   1.8   1.66   1.89
[Temperature Range]   25   125   -40
[Voltage Range]   1.8   1.66   1.89
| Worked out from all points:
|   slope of the pulldown table from 0 to 0.27 V, typ, clamps not added: 70.3 ohm
|   slope of the pullup table from 0 to 0.27 V, typ, clamps not added: 80.5 ohm
|   GND clamp passes 1 mA (typ) near -0.43 V on its own axis
|   falling waveform, R_fixture 50, V_fixture 1.8: 20-80 % time 1.52ns typ, 2.39ns min, 1.03ns max; typ from 1.8 V to 1.32 V
|   falling waveform, R_fixture 50, V_fixture 0: 20-80 % time 142ps typ, 164ps min, 131ps max; typ from 0.501 V to 0 V
|   rising waveform, R_fixture 50, V_fixture 1.8: 20-80 % time 202ps typ, 265ps min, 169ps max; typ from 1.32 V to 1.8 V
|   rising waveform, R_fixture 50, V_fixture 0: 20-80 % time 1.28ns typ, 2.31ns min, 812ps max; typ from 0 V to 0.501 V
[GND Clamp]
| Voltage   I(typ)   I(min)   I(max)
-1.271V   -717.5mA   -832.8mA   -643.6mA
-1.07V    -241.9mA   -348.3mA   -192.2mA
-1.003V   -137.2mA   -218.1mA   -128.1mA
-936.6mV  -83.06mA   -120.7mA   -101.3mA
-869.7mV  -59.26mA   -64.32mA   -81.77mA
-802.8mV  -43.7mA    -38.08mA   -63.69mA
-735.9mV  -30.76mA   -24.63mA   -46.83mA
-602.1mV  -11.27mA   -9.362mA   -18.72mA
-535.2mV  -5.241mA   -4.803mA   -9.042mA
-468.3mV  -1.746mA   -1.965mA   -3.086mA
-334.5mV  -35.9uA    -120.8uA   -33.39uA
3.6V      0A         0A         0A
[POWER Clamp]
| Voltage   I(typ)   I(min)   I(max)
-1.8V     7.872uA    6.273uA    11.31uA
-1.672V   5.671uA    4.461uA    8.32uA
-1.539V   3.91uA     3.037uA    5.87uA
-1.405V   3.295uA    2.008uA    4.063uA
-1.271V   3.295uA    1.447uA    3.964uA
-334.5mV  3.295uA    1.429uA    3.964uA
-267.6mV  3.295uA    1.429uA    2.099uA
-200.7mV  664.1nA    1.429uA    166.6nA
-133.8mV  69.92nA    1.319uA    14.86nA
-66.9mV   7.33nA     291.5nA    4.066nA
62.07mV   0A         0A         0A
3.6V      0A         0A         0A
[Pulldown]
| Voltage   I(typ)   I(min)   I(max)
-1.8V     -616.6uA   -578.4uA   -564.6uA
-1.405V   -1.672mA   -1.165mA   -2.377mA
-802.8mV  -9.141mA   -7.072mA   -10.23mA
869mV     8.589mA    5.772mA    11.16mA
1.93V     10.23mA    6.865mA    13.28mA
2.126V    10.39mA    3.227mA    13.45mA
2.256V    5.458mA    2.987mA    13.6mA
2.321V    4.646mA    2.909mA    7.795mA
2.647V    4.519mA    3.522mA    6.185mA
3.364V    18.92mA    14.9mA     22.94mA
3.494V    21.97mA    14.1mA     26.53mA
3.6V      24.46mA    7.474mA    29.53mA
[Pullup]
| Voltage   I(typ)   I(min)   I(max)
-1.8V     7.024mA    2.773mA    11.12mA
-1.472V   2.714mA    1.872mA    4.595mA
-1.204V   1.482mA    921.3uA    2.643mA
-1.07V    1.316mA    590.6uA    5.718mA
-936.6mV  5.531mA    392.1uA    11.29mA
-802.8mV  8.669mA    3.054mA    10.96mA
-735.9mV  8.561mA    5.377mA    10.41mA
-602.1mV  7.662mA    5.909mA    9.047mA
434.5mV   -5.11mA    -3.918mA   -6.166mA
1.117V    -9.434mA   -6.982mA   -11.69mA
1.996V    -11.4mA    -8.156mA   -14.54mA
3.6V      -12.89mA   -9.118mA   -16.71mA
[Ramp]
dV/dt_r   0.300724/1.27523n  0.22014/2.309n  0.37204/0.811874n
dV/dt_f   0.288397/1.5152n  0.193195/2.3911n  0.37244/1.02799n
R_load = 50
[Falling Waveform]
R_fixture = 50
V_fixture = 1.8
V_fixture_min = 1.66
V_fixture_max = 1.89
| Time   V(typ)   V(min)   V(max)
0s        1.8V       1.66V      1.89V
468.8ps   1.807V     1.665V     1.883V
730.2ps   1.778V     1.663V     1.757V
1.206ns   1.636V     1.629V     1.522V
1.563ns   1.543V     1.58V      1.425V
2.066ns   1.459V     1.514V     1.353V
3.354ns   1.368V     1.421V     1.289V
5.945ns   1.326V     1.36V      1.27V
15.36ns   1.319V     1.337V     1.269V
800ns     1.319V     1.338V     1.269V
[Falling Waveform]
R_fixture = 50
V_fixture = 0
V_fixture_min = 0
V_fixture_max = 0
| Time   V(typ)   V(min)   V(max)
0s        501.2mV    366.9mV    620.1mV
247.7ps   501mV      366.9mV    606.1mV
283.7ps   501.7mV    366.9mV    534.2mV
338ps     469.1mV    366.8mV    350.1mV
405.5ps   318.5mV    366.8mV    160.1mV
483.3ps   144.3mV    314.3mV    63.15mV
555ps     64.38mV    204.3mV    24.96mV
664.4ps   20.01mV    71.65mV    5.361mV
881.4ps   1.367mV    8.375mV    371uV
800ns     29.26nV    1.443uV    13.92nV
[Rising Waveform]
R_fixture = 50
V_fixture = 1.8
V_fixture_min = 1.66
V_fixture_max = 1.89
| Time   V(typ)   V(min)   V(max)
0s        1.319V     1.338V     1.269V
258ps     1.32V      1.338V     1.269V
306.2ps   1.319V     1.338V     1.292V
410.6ps   1.354V     1.338V     1.462V
551.9ps   1.546V     1.366V     1.776V
662.8ps   1.701V     1.446V     1.866V
762.3ps   1.77V      1.525V     1.884V
975ps     1.797V     1.637V     1.889V
1.588ns   1.799V     1.659V     1.889V
800ns     1.8V       1.66V      1.89V
[Rising Waveform]
R_fixture = 50
V_fixture = 0
V_fixture_min = 0
V_fixture_max = 0
| Time   V(typ)   V(min)   V(max)
0s        29.27nV    1.443uV    13.92nV
547.4ps   -1.841mV   -1.033mV   12.63mV
858.1ps   27.51mV    -1.227mV   175.5mV
1.253ns   147.3mV    13.98mV    393.6mV
1.977ns   343.2mV    104.4mV    557.9mV
2.728ns   432.1mV    202.9mV    601.1mV
3.614ns   473.6mV    272mV      615.3mV
5.77ns    498mV      338.4mV    621.1mV
15.25ns   501.6mV    367.9mV    620.1mV
800ns     501.2mV    366.9mV    620.1mV
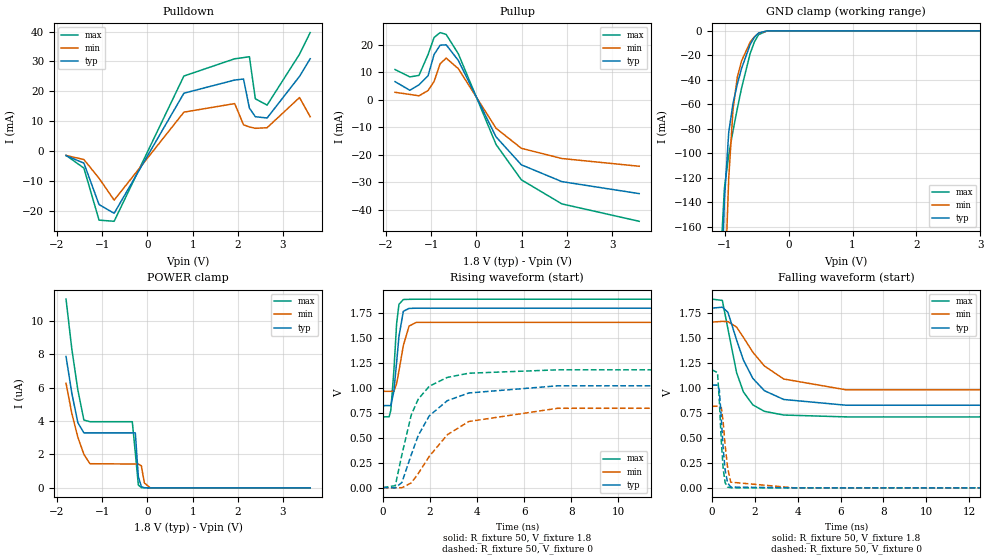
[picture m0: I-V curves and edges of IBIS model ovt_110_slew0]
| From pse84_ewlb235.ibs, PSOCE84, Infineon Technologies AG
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[Model] ovt_110_slew0
Model_type I/O
Enable   Active-High
Vinl  =  0.54
Vinh  =  1.26
Vmeas =  0.9
Cref  =  15e-12
| Capacitance   typ   min   max
C_comp   1.39974e-12   1.35992e-12   1.44753e-12
| Variables   typ   min   max
[GND Clamp Reference]   0   0   0
[POWER Clamp Reference]   1.8   1.66   1.89
[Pulldown Reference]   0   0   0
[Pullup Reference]   1.8   1.66   1.89
[Temperature Range]   25   125   -40
[Voltage Range]   1.8   1.66   1.89
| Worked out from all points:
|   slope of the pulldown table from 0 to 0.27 V, typ, clamps not added: 30.3 ohm
|   slope of the pullup table from 0 to 0.27 V, typ, clamps not added: 30.5 ohm
|   GND clamp passes 1 mA (typ) near -0.43 V on its own axis
|   falling waveform, R_fixture 50, V_fixture 1.8: 20-80 % time 1.22ns typ, 1.79ns min, 808ps max; typ from 1.8 V to 0.822 V
|   falling waveform, R_fixture 50, V_fixture 0: 20-80 % time 200ps typ, 233ps min, 180ps max; typ from 1.03 V to 0 V
|   rising waveform, R_fixture 50, V_fixture 1.8: 20-80 % time 233ps typ, 323ps min, 181ps max; typ from 0.822 V to 1.8 V
|   rising waveform, R_fixture 50, V_fixture 0: 20-80 % time 1.37ns typ, 2ns min, 942ps max; typ from 0 V to 1.03 V
[GND Clamp]
| Voltage   I(typ)   I(min)   I(max)
-1.271V   -717.5mA   -832.8mA   -643.6mA
-1.07V    -241.9mA   -348.3mA   -192.2mA
-1.003V   -137.2mA   -218.1mA   -128.1mA
-936.6mV  -83.06mA   -120.7mA   -101.3mA
-869.7mV  -59.26mA   -64.32mA   -81.77mA
-802.8mV  -43.7mA    -38.08mA   -63.69mA
-735.9mV  -30.76mA   -24.63mA   -46.83mA
-602.1mV  -11.27mA   -9.362mA   -18.72mA
-535.2mV  -5.241mA   -4.803mA   -9.042mA
-468.3mV  -1.746mA   -1.965mA   -3.086mA
-334.5mV  -35.9uA    -120.8uA   -33.39uA
3.6V      0A         0A         0A
[POWER Clamp]
| Voltage   I(typ)   I(min)   I(max)
-1.8V     7.872uA    6.273uA    11.31uA
-1.672V   5.671uA    4.461uA    8.32uA
-1.539V   3.91uA     3.037uA    5.87uA
-1.405V   3.295uA    2.008uA    4.063uA
-1.271V   3.295uA    1.447uA    3.964uA
-334.5mV  3.295uA    1.429uA    3.964uA
-267.6mV  3.295uA    1.429uA    2.099uA
-200.7mV  664.1nA    1.429uA    166.6nA
-133.8mV  69.92nA    1.319uA    14.86nA
-66.9mV   7.33nA     291.5nA    4.066nA
62.07mV   0A         0A         0A
3.6V      0A         0A         0A
[Pulldown]
| Voltage   I(typ)   I(min)   I(max)
-1.8V     -1.439mA   -1.35mA    -1.318mA
-1.405V   -3.905mA   -2.719mA   -5.569mA
-1.07V    -17.75mA   -8.962mA   -22.94mA
-735.9mV  -20.66mA   -16.27mA   -23.33mA
806.9mV   19.41mA    13.09mA    25.15mA
1.93V     23.81mA    15.95mA    30.9mA
2.126V    24.14mA    8.867mA    31.3mA
2.256V    14.43mA    8.154mA    31.58mA
2.387V    11.57mA    7.703mA    17.55mA
2.647V    11.14mA    7.899mA    15.44mA
3.364V    25.03mA    17.97mA    32.42mA
3.6V      30.91mA    11.57mA    39.65mA
[Pullup]
| Voltage   I(typ)   I(min)   I(max)
-1.8V     6.592mA    2.712mA    10.99mA
-1.472V   3.441mA    1.94mA     8.313mA
-1.271V   5.441mA    1.432mA    8.858mA
-1.07V    8.731mA    3.358mA    16.44mA
-936.6mV  16.48mA    6.665mA    22.64mA
-802.8mV  19.84mA    13.11mA    24.44mA
-669mV    19.99mA    15.14mA    23.75mA
-401.4mV  14.32mA    11.33mA    16.74mA
434.5mV   -13.51mA   -10.38mA   -16.28mA
993.1mV   -23.65mA   -17.65mA   -29.11mA
1.89V     -29.77mA   -21.37mA   -37.87mA
3.6V      -34.13mA   -24.18mA   -44.2mA
[Ramp]
dV/dt_r   0.617231/1.37175n  0.490171/1.99882n  0.709901/0.942408n
dV/dt_f   0.586718/1.2239n  0.416736/1.78825n  0.708163/0.808075n
R_load = 50
[Falling Waveform]
R_fixture = 50
V_fixture = 1.8
V_fixture_min = 1.66
V_fixture_max = 1.89
| Time   V(typ)   V(min)   V(max)
0s        1.8V       1.66V      1.89V
489.3ps   1.809V     1.667V     1.877V
748.9ps   1.758V     1.665V     1.592V
1.153ns   1.481V     1.61V      1.154V
1.472ns   1.279V     1.507V     960.4mV
1.909ns   1.097V     1.359V     831.4mV
2.447ns   973.3mV    1.221V     766.5mV
3.351ns   885mV      1.09V      729.3mV
6.262ns   827.5mV    981.8mV    710.6mV
800ns     822.1mV    965.4mV    709.7mV
[Falling Waveform]
R_fixture = 50
V_fixture = 0
V_fixture_min = 0
V_fixture_max = 0
| Time   V(typ)   V(min)   V(max)
0s        1.029V     817mV      1.183V
264.3ps   1.029V     817mV      1.154V
349.5ps   979.1mV    816.8mV    863.5mV
443.8ps   682mV      801.5mV    453.2mV
528.3ps   393.4mV    656mV      190.5mV
620.6ps   176.2mV    422.8mV    51.21mV
732.3ps   50.61mV    205.3mV    7.339mV
879.4ps   8.055mV    56.96mV    655.5uV
3.83ns    95.08uV    134uV      68.27uV
800ns     18.65nV    979.8nV    8.521nV
[Rising Waveform]
R_fixture = 50
V_fixture = 1.8
V_fixture_min = 1.66
V_fixture_max = 1.89
| Time   V(typ)   V(min)   V(max)
0s        822.1mV    965.4mV    709.7mV
266.8ps   822.4mV    965.4mV    709.7mV
338.7ps   821mV      965.6mV    775.8mV
466.7ps   963.6mV    964.3mV    1.167V
584.7ps   1.256V     1.042V     1.644V
684ps     1.517V     1.17V      1.838V
870.4ps   1.768V     1.426V     1.886V
1.114ns   1.797V     1.62V      1.888V
1.425ns   1.799V     1.657V     1.889V
800ns     1.8V       1.66V      1.89V
[Rising Waveform]
R_fixture = 50
V_fixture = 0
V_fixture_min = 0
V_fixture_max = 0
| Time   V(typ)   V(min)   V(max)
0s        18.66nV    979.6nV    8.526nV
528.8ps   -2.607mV   -1.621mV   19.75mV
809.3ps   51.46mV    -1.456mV   330.4mV
1.206ns   329.6mV    47.2mV     729.3mV
1.502ns   522.6mV    140.7mV    887mV
1.972ns   720.4mV    313.5mV    1.017V
2.735ns   871.5mV    529.8mV    1.105V
3.646ns   949mV      662.9mV    1.147V
7.424ns   1.021V     795.6mV    1.181V
800ns     1.029V     817mV      1.183V
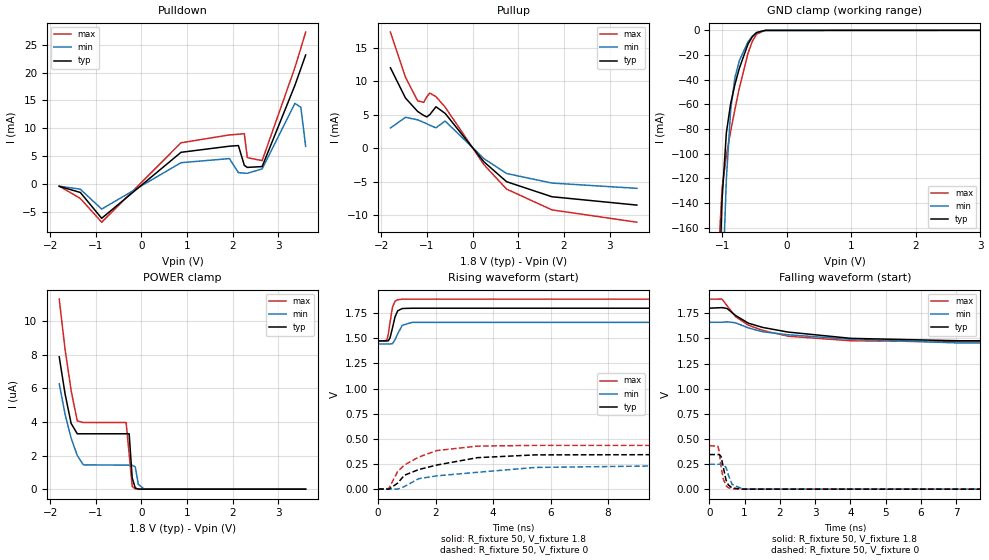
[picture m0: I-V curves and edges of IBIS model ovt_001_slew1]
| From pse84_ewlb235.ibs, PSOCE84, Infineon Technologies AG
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[Model] ovt_001_slew1
Model_type I/O
Enable   Active-High
Vinl  =  0.54
Vinh  =  1.26
Vmeas =  0.9
Cref  =  15e-12
| Capacitance   typ   min   max
C_comp   1.39974e-12   1.35992e-12   1.44753e-12
| Variables   typ   min   max
[GND Clamp Reference]   0   0   0
[POWER Clamp Reference]   1.8   1.66   1.89
[Pulldown Reference]   0   0   0
[Pullup Reference]   1.8   1.66   1.89
[Temperature Range]   25   125   -40
[Voltage Range]   1.8   1.66   1.89
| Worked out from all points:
|   slope of the pulldown table from 0 to 0.27 V, typ, clamps not added: 107 ohm
|   slope of the pullup table from 0 to 0.27 V, typ, clamps not added: 122 ohm
|   GND clamp passes 1 mA (typ) near -0.43 V on its own axis
|   falling waveform, R_fixture 50, V_fixture 1.8: 20-80 % time 1.98ns typ, 3.25ns min, 1.27ns max; typ from 1.8 V to 1.47 V
|   falling waveform, R_fixture 50, V_fixture 0: 20-80 % time 131ps typ, 150ps min, 118ps max; typ from 0.344 V to 0 V
|   rising waveform, R_fixture 50, V_fixture 1.8: 20-80 % time 163ps typ, 217ps min, 136ps max; typ from 1.47 V to 1.8 V
|   rising waveform, R_fixture 50, V_fixture 0: 20-80 % time 1.9ns typ, 3.59ns min, 1.12ns max; typ from 0 V to 0.344 V
[GND Clamp]
| Voltage   I(typ)   I(min)   I(max)
-1.271V   -717.5mA   -832.8mA   -643.6mA
-1.07V    -241.9mA   -348.3mA   -192.2mA
-1.003V   -137.2mA   -218.1mA   -128.1mA
-936.6mV  -83.06mA   -120.7mA   -101.3mA
-869.7mV  -59.26mA   -64.32mA   -81.77mA
-802.8mV  -43.7mA    -38.08mA   -63.69mA
-735.9mV  -30.76mA   -24.63mA   -46.83mA
-602.1mV  -11.27mA   -9.362mA   -18.72mA
-535.2mV  -5.241mA   -4.803mA   -9.042mA
-468.3mV  -1.746mA   -1.965mA   -3.086mA
-334.5mV  -35.9uA    -120.8uA   -33.39uA
3.6V      0A         0A         0A
[POWER Clamp]
| Voltage   I(typ)   I(min)   I(max)
-1.8V     7.872uA    6.273uA    11.31uA
-1.672V   5.671uA    4.461uA    8.32uA
-1.539V   3.91uA     3.037uA    5.87uA
-1.405V   3.295uA    2.008uA    4.063uA
-1.271V   3.295uA    1.447uA    3.964uA
-334.5mV  3.295uA    1.429uA    3.964uA
-267.6mV  3.295uA    1.429uA    2.099uA
-200.7mV  664.1nA    1.429uA    166.6nA
-133.8mV  69.92nA    1.319uA    14.86nA
-66.9mV   7.33nA     291.5nA    4.066nA
62.07mV   0A         0A         0A
3.6V      0A         0A         0A
[Pulldown]
| Voltage   I(typ)   I(min)   I(max)
-1.8V     -410.9uA   -384.6uA   -377uA
-1.338V   -1.517mA   -927.1uA   -2.585mA
-869.7mV  -6.156mA   -4.504mA   -6.855mA
869mV     5.693mA    3.828mA    7.398mA
1.93V     6.791mA    4.567mA    8.819mA
2.126V    6.905mA    2.044mA    8.932mA
2.256V    3.355mA    1.95mA     9.046mA
2.321V    2.981mA    1.926mA    4.745mA
2.647V    3.132mA    2.707mA    4.197mA
3.364V    17.71mA    14.49mA    20.89mA
3.494V    20.71mA    13.78mA    24.37mA
3.6V      23.17mA    6.768mA    27.28mA
[Pullup]
| Voltage   I(typ)   I(min)   I(max)
-1.8V     12mA       3.009mA    17.34mA
-1.472V   7.498mA    4.605mA    10.61mA
-1.204V   5.475mA    4.224mA    7.061mA
-1.07V    4.879mA    3.842mA    6.834mA
-1.003V   4.667mA    3.634mA    7.675mA
-936.6mV  5.016mA    3.415mA    8.226mA
-802.8mV  6.177mA    3.039mA    7.688mA
-602.1mV  5.195mA    4.053mA    6.138mA
248.3mV   -2.049mA   -1.578mA   -2.472mA
744.8mV   -5.02mA    -3.793mA   -6.123mA
1.738V    -7.266mA   -5.224mA   -9.231mA
3.6V      -8.515mA   -6.01mA    -11.07mA
[Ramp]
dV/dt_r   0.206668/1.89849n  0.148886/3.59225n  0.260239/1.12159n
dV/dt_f   0.195417/1.97959n  0.130017/3.25202n  0.253909/1.27488n
R_load = 50
[Falling Waveform]
R_fixture = 50
V_fixture = 1.8
V_fixture_min = 1.66
V_fixture_max = 1.89
| Time   V(typ)   V(min)   V(max)
0s        1.8V       1.66V      1.89V
358.7ps   1.806V     1.66V      1.891V
503.6ps   1.797V     1.665V     1.824V
737.3ps   1.729V     1.655V     1.718V
1.108ns   1.651V     1.604V     1.631V
1.51ns    1.609V     1.566V     1.58V
2.226ns   1.563V     1.536V     1.522V
4.023ns   1.5V       1.491V     1.476V
7.098ns   1.476V     1.454V     1.466V
800ns     1.474V     1.443V     1.467V
[Falling Waveform]
R_fixture = 50
V_fixture = 0
V_fixture_min = 0
V_fixture_max = 0
| Time   V(typ)   V(min)   V(max)
0s        344.4mV    248.1mV    433.7mV
243.9ps   344.3mV    248.1mV    425.6mV
277.3ps   344.8mV    248.1mV    374.9mV
332.3ps   324.8mV    248mV      227.3mV
392.8ps   222.5mV    248.6mV    104.1mV
475.2ps   88.88mV    214.3mV    33.39mV
538.2ps   42.11mV    141.6mV    14.06mV
650ps     10.76mV    44.98mV    2.849mV
961.5ps   368.7uV    1.364mV    363.9uV
800ns     34.28nV    1.642uV    16.63nV
[Rising Waveform]
R_fixture = 50
V_fixture = 1.8
V_fixture_min = 1.66
V_fixture_max = 1.89
| Time   V(typ)   V(min)   V(max)
0s        1.474V     1.443V     1.467V
299.8ps   1.474V     1.443V     1.479V
352.3ps   1.474V     1.444V     1.538V
412.4ps   1.503V     1.443V     1.654V
499.1ps   1.602V     1.446V     1.809V
587.1ps   1.712V     1.484V     1.868V
680.5ps   1.773V     1.545V     1.883V
840.9ps   1.796V     1.629V     1.889V
1.179ns   1.799V     1.658V     1.889V
800ns     1.8V       1.66V      1.89V
[Rising Waveform]
R_fixture = 50
V_fixture = 0
V_fixture_min = 0
V_fixture_max = 0
| Time   V(typ)   V(min)   V(max)
0s        34.28nV    1.642uV    16.63nV
374.4ps   -1.24mV    174.8uV    5.201mV
679.1ps   58.87mV    -145.1uV   174.6mV
912.5ps   136.8mV    24.65mV    238.4mV
1.409ns   193.7mV    103mV      317.8mV
2.042ns   239mV      131.3mV    383mV
3.459ns   312.3mV    166.8mV    427mV
5.452ns   339.7mV    214.6mV    434.5mV
14.98ns   345mV      249.3mV    433.7mV
800ns     344.4mV    248.1mV    433.7mV
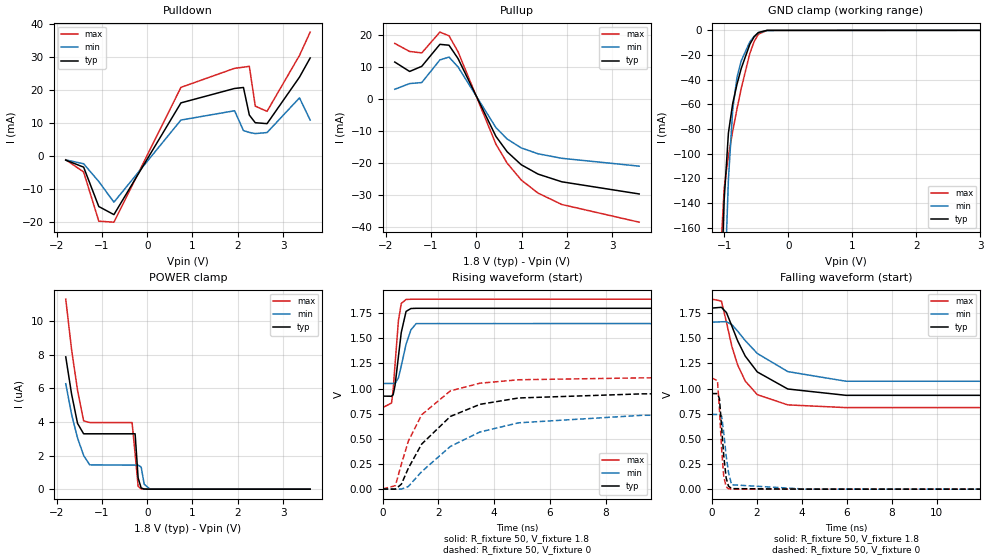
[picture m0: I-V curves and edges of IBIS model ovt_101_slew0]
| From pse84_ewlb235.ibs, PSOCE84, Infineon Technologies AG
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[Model] ovt_101_slew0
Model_type I/O
Enable   Active-High
Vinl  =  0.54
Vinh  =  1.26
Vmeas =  0.9
Cref  =  15e-12
| Capacitance   typ   min   max
C_comp   1.39974e-12   1.35992e-12   1.44753e-12
| Variables   typ   min   max
[GND Clamp Reference]   0   0   0
[POWER Clamp Reference]   1.8   1.66   1.89
[Pulldown Reference]   0   0   0
[Pullup Reference]   1.8   1.66   1.89
[Temperature Range]   25   125   -40
[Voltage Range]   1.8   1.66   1.89
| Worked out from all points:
|   slope of the pulldown table from 0 to 0.27 V, typ, clamps not added: 35.4 ohm
|   slope of the pullup table from 0 to 0.27 V, typ, clamps not added: 34.9 ohm
|   GND clamp passes 1 mA (typ) near -0.43 V on its own axis
|   falling waveform, R_fixture 50, V_fixture 1.8: 20-80 % time 1.47ns typ, 2.07ns min, 999ps max; typ from 1.8 V to 0.924 V
|   falling waveform, R_fixture 50, V_fixture 0: 20-80 % time 200ps typ, 239ps min, 173ps max; typ from 0.95 V to 0 V
|   rising waveform, R_fixture 50, V_fixture 1.8: 20-80 % time 227ps typ, 320ps min, 177ps max; typ from 0.924 V to 1.8 V
|   rising waveform, R_fixture 50, V_fixture 0: 20-80 % time 1.79ns typ, 2.48ns min, 1.24ns max; typ from 0 V to 0.95 V
[GND Clamp]
| Voltage   I(typ)   I(min)   I(max)
-1.271V   -717.5mA   -832.8mA   -643.6mA
-1.07V    -241.9mA   -348.3mA   -192.2mA
-1.003V   -137.2mA   -218.1mA   -128.1mA
-936.6mV  -83.06mA   -120.7mA   -101.3mA
-869.7mV  -59.26mA   -64.32mA   -81.77mA
-802.8mV  -43.7mA    -38.08mA   -63.69mA
-735.9mV  -30.76mA   -24.63mA   -46.83mA
-602.1mV  -11.27mA   -9.362mA   -18.72mA
-535.2mV  -5.241mA   -4.803mA   -9.042mA
-468.3mV  -1.746mA   -1.965mA   -3.086mA
-334.5mV  -35.9uA    -120.8uA   -33.39uA
3.6V      0A         0A         0A
[POWER Clamp]
| Voltage   I(typ)   I(min)   I(max)
-1.8V     7.872uA    6.273uA    11.31uA
-1.672V   5.671uA    4.461uA    8.32uA
-1.539V   3.91uA     3.037uA    5.87uA
-1.405V   3.295uA    2.008uA    4.063uA
-1.271V   3.295uA    1.447uA    3.964uA
-334.5mV  3.295uA    1.429uA    3.964uA
-267.6mV  3.295uA    1.429uA    2.099uA
-200.7mV  664.1nA    1.429uA    166.6nA
-133.8mV  69.92nA    1.319uA    14.86nA
-66.9mV   7.33nA     291.5nA    4.066nA
62.07mV   0A         0A         0A
3.6V      0A         0A         0A
[Pulldown]
| Voltage   I(typ)   I(min)   I(max)
-1.8V     -1.235mA   -1.158mA   -1.132mA
-1.405V   -3.361mA   -2.335mA   -4.813mA
-1.07V    -15.27mA   -7.711mA   -19.69mA
-735.9mV  -17.71mA   -13.95mA   -20mA
744.8mV   16.07mA    10.88mA    20.76mA
1.93V     20.43mA    13.69mA    26.52mA
2.126V    20.72mA    7.705mA    26.86mA
2.256V    12.38mA    7.136mA    27.11mA
2.387V    10.07mA    6.786mA    15.08mA
2.647V    9.79mA     7.098mA    13.51mA
3.364V    23.85mA    17.59mA    30.42mA
3.6V      29.65mA    10.87mA    37.47mA
[Pullup]
| Voltage   I(typ)   I(min)   I(max)
-1.8V     11.43mA    2.93mA     17.25mA
-1.472V   8.49mA     4.704mA    14.74mA
-1.204V   10.09mA    5.026mA    14.29mA
-802.8mV  16.96mA    12.1mA     20.79mA
-602.1mV  16.69mA    12.98mA    19.64mA
-401.4mV  12.5mA     9.892mA    14.62mA
434.5mV   -11.79mA   -9.048mA   -14.21mA
682.8mV   -16.6mA    -12.61mA   -20.15mA
993.1mV   -20.64mA   -15.39mA   -25.41mA
1.366V    -23.58mA   -17.23mA   -29.52mA
1.89V     -25.98mA   -18.64mA   -33.07mA
3.6V      -29.78mA   -21.09mA   -38.6mA
[Ramp]
dV/dt_r   0.57014/1.78798n  0.445676/2.47924n  0.663532/1.23963n
dV/dt_f   0.525431/1.47479n  0.365852/2.07304n  0.648314/0.99885n
R_load = 50
[Falling Waveform]
R_fixture = 50
V_fixture = 1.8
V_fixture_min = 1.66
V_fixture_max = 1.89
| Time   V(typ)   V(min)   V(max)
0s        1.8V       1.66V      1.89V
436.3ps   1.808V     1.664V     1.87V
659.6ps   1.756V     1.665V     1.661V
899ps     1.622V     1.636V     1.42V
1.157ns   1.475V     1.571V     1.235V
1.494ns   1.323V     1.477V     1.075V
2.031ns   1.165V     1.349V     939.3mV
3.381ns   995.9mV    1.169V     837.9mV
5.965ns   933mV      1.073V     810.9mV
800ns     924.3mV    1.05V      809.5mV
[Falling Waveform]
R_fixture = 50
V_fixture = 0
V_fixture_min = 0
V_fixture_max = 0
| Time   V(typ)   V(min)   V(max)
0s        950.2mV    742.8mV    1.106V
262.6ps   950.2mV    742.8mV    1.079V
349.9ps   900.3mV    742.7mV    792.3mV
445.2ps   617.1mV    727.2mV    404.8mV
541.7ps   328.8mV    560.1mV    124mV
647.1ps   111.9mV    331.3mV    23.48mV
751.1ps   30.21mV    165.9mV    4.076mV
890.4ps   5.211mV    43.64mV    598.4uV
4.201ns   81.73uV    109.2uV    58.27uV
800ns     20.52nV    1.066uV    9.444nV
[Rising Waveform]
R_fixture = 50
V_fixture = 1.8
V_fixture_min = 1.66
V_fixture_max = 1.89
| Time   V(typ)   V(min)   V(max)
0s        924.3mV    1.05V      809.5mV
322.2ps   923.1mV    1.05V      855.1mV
380.6ps   938.7mV    1.051V     990mV
447.5ps   1.029V     1.049V     1.236V
570ps     1.32V      1.106V     1.676V
671.1ps   1.558V     1.225V     1.846V
843.2ps   1.767V     1.441V     1.886V
1.017ns   1.796V     1.583V     1.888V
1.205ns   1.798V     1.646V     1.889V
800ns     1.8V       1.66V      1.89V
[Rising Waveform]
R_fixture = 50
V_fixture = 0
V_fixture_min = 0
V_fixture_max = 0
| Time   V(typ)   V(min)   V(max)
0s        20.53nV    1.065uV    9.448nV
461.3ps   -1.599mV   -706.2uV   33.59mV
676.2ps   48.85mV    -1.031mV   248.7mV
926.2ps   207.8mV    25.19mV    476.7mV
1.402ns   447.1mV    172.7mV    738.3mV
2.432ns   722.1mV    423.9mV    976.6mV
3.497ns   842.7mV    567.9mV    1.053V
4.88ns    905.8mV    658.7mV    1.087V
9.338ns   947mV      733.8mV    1.106V
800ns     950.2mV    742.8mV    1.106V
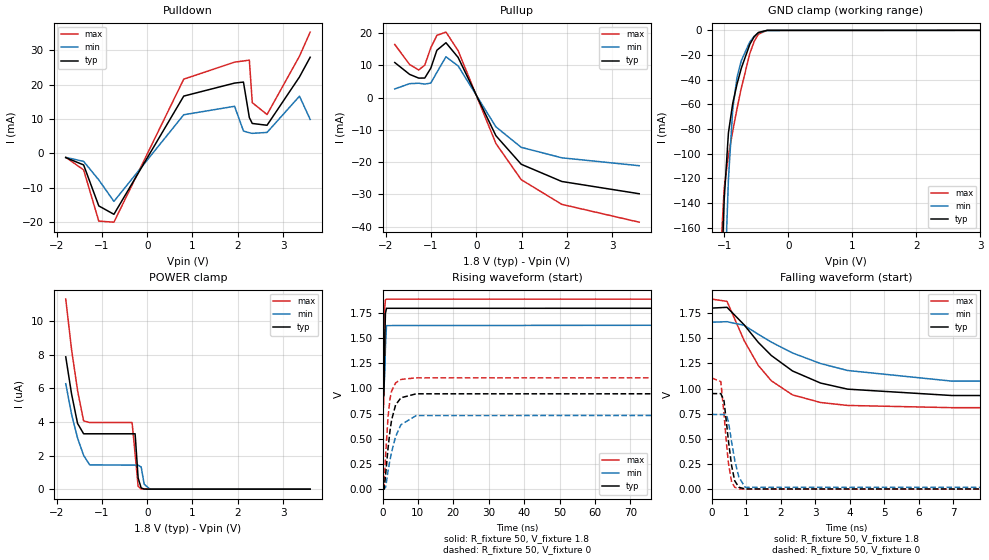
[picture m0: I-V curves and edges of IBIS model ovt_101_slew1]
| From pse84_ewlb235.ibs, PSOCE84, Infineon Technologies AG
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[Model] ovt_101_slew1
Model_type I/O
Enable   Active-High
Vinl  =  0.54
Vinh  =  1.26
Vmeas =  0.9
Cref  =  15e-12
| Capacitance   typ   min   max
C_comp   1.39974e-12   1.35992e-12   1.44753e-12
| Variables   typ   min   max
[GND Clamp Reference]   0   0   0
[POWER Clamp Reference]   1.8   1.66   1.89
[Pulldown Reference]   0   0   0
[Pullup Reference]   1.8   1.66   1.89
[Temperature Range]   25   125   -40
[Voltage Range]   1.8   1.66   1.89
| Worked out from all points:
|   slope of the pulldown table from 0 to 0.27 V, typ, clamps not added: 35.4 ohm
|   slope of the pullup table from 0 to 0.27 V, typ, clamps not added: 34.9 ohm
|   GND clamp passes 1 mA (typ) near -0.43 V on its own axis
|   falling waveform, R_fixture 50, V_fixture 1.8: 20-80 % time 1.83ns typ, 2.7ns min, 1.22ns max; typ from 1.8 V to 0.924 V
|   falling waveform, R_fixture 50, V_fixture 0: 20-80 % time 200ps typ, 239ps min, 174ps max; typ from 0.95 V to 0 V
|   rising waveform, R_fixture 50, V_fixture 1.8: 20-80 % time 228ps typ, 321ps min, 181ps max; typ from 0.924 V to 1.8 V
|   rising waveform, R_fixture 50, V_fixture 0: 20-80 % time 2.01ns typ, 3.07ns min, 1.35ns max; typ from 0 V to 0.95 V
[GND Clamp]
| Voltage   I(typ)   I(min)   I(max)
-1.271V   -717.5mA   -832.8mA   -643.6mA
-1.07V    -241.9mA   -348.3mA   -192.2mA
-1.003V   -137.2mA   -218.1mA   -128.1mA
-936.6mV  -83.06mA   -120.7mA   -101.3mA
-869.7mV  -59.26mA   -64.32mA   -81.77mA
-802.8mV  -43.7mA    -38.08mA   -63.69mA
-735.9mV  -30.76mA   -24.63mA   -46.83mA
-602.1mV  -11.27mA   -9.362mA   -18.72mA
-535.2mV  -5.241mA   -4.803mA   -9.042mA
-468.3mV  -1.746mA   -1.965mA   -3.086mA
-334.5mV  -35.9uA    -120.8uA   -33.39uA
3.6V      0A         0A         0A
[POWER Clamp]
| Voltage   I(typ)   I(min)   I(max)
-1.8V     7.872uA    6.273uA    11.31uA
-1.672V   5.671uA    4.461uA    8.32uA
-1.539V   3.91uA     3.037uA    5.87uA
-1.405V   3.295uA    2.008uA    4.063uA
-1.271V   3.295uA    1.447uA    3.964uA
-334.5mV  3.295uA    1.429uA    3.964uA
-267.6mV  3.295uA    1.429uA    2.099uA
-200.7mV  664.1nA    1.429uA    166.6nA
-133.8mV  69.92nA    1.319uA    14.86nA
-66.9mV   7.33nA     291.5nA    4.066nA
62.07mV   0A         0A         0A
3.6V      0A         0A         0A
[Pulldown]
| Voltage   I(typ)   I(min)   I(max)
-1.8V     -1.235mA   -1.158mA   -1.132mA
-1.405V   -3.361mA   -2.335mA   -4.813mA
-1.07V    -15.27mA   -7.711mA   -19.69mA
-735.9mV  -17.71mA   -13.95mA   -20mA
806.9mV   16.65mA    11.23mA    21.57mA
1.93V     20.43mA    13.69mA    26.52mA
2.126V    20.72mA    6.496mA    26.86mA
2.256V    10.4mA     5.989mA    27.11mA
2.321V    8.694mA    5.82mA     14.74mA
2.647V    8.17mA     6.088mA    11.29mA
3.364V    22.22mA    16.62mA    28.25mA
3.6V      27.94mA    9.853mA    35.25mA
[Pullup]
| Voltage   I(typ)   I(min)   I(max)
-1.8V     10.89mA    2.706mA    16.49mA
-1.472V   7.223mA    4.346mA    10.28mA
-1.271V   6.065mA    4.477mA    8.576mA
-1.137V   6.088mA    4.215mA    10.1mA
-1.003V   9.178mA    4.539mA    15.52mA
-869.7mV  14.7mA     7.847mA    19.31mA
-669mV    17.03mA    12.68mA    20.33mA
-401.4mV  12.49mA    9.866mA    14.6mA
434.5mV   -11.79mA   -9.048mA   -14.21mA
993.1mV   -20.64mA   -15.39mA   -25.41mA
1.89V     -25.98mA   -18.64mA   -33.07mA
3.6V      -29.78mA   -21.09mA   -38.6mA
[Ramp]
dV/dt_r   0.57014/2.00917n  0.445674/3.07049n  0.663532/1.35196n
dV/dt_f   0.52543/1.83345n  0.365851/2.69917n  0.648313/1.21525n
R_load = 50
[Falling Waveform]
R_fixture = 50
V_fixture = 1.8
V_fixture_min = 1.66
V_fixture_max = 1.89
| Time   V(typ)   V(min)   V(max)
0s        1.8V       1.66V      1.89V
448.1ps   1.808V     1.665V     1.867V
943.7ps   1.634V     1.629V     1.478V
1.353ns   1.46V      1.54V      1.231V
1.732ns   1.329V     1.462V     1.078V
2.347ns   1.175V     1.354V     937.5mV
3.16ns    1.055V     1.249V     861.7mV
3.944ns   994.4mV    1.18V      832.4mV
6.972ns   931mV      1.074V     810.2mV
800ns     924.3mV    1.05V      809.5mV
[Falling Waveform]
R_fixture = 50
V_fixture = 0
V_fixture_min = 0
V_fixture_max = 0
| Time   V(typ)   V(min)   V(max)
0s        950.2mV    742.8mV    1.106V
267.8ps   950.3mV    742.8mV    1.07V
360.4ps   878.5mV    742.7mV    747.9mV
436.4ps   647.4mV    733.6mV    439.7mV
489.1ps   478.3mV    670.1mV    257.2mV
581.9ps   232.2mV    467.6mV    71.46mV
671ps     83.45mV    288.2mV    19.63mV
790.3ps   19.13mV    119.9mV    2.888mV
974.4ps   1.834mV    18.18mV    510.8uV
800ns     20.52nV    1.066uV    9.444nV
[Rising Waveform]
R_fixture = 50
V_fixture = 1.8
V_fixture_min = 1.66
V_fixture_max = 1.89
| Time   V(typ)   V(min)   V(max)
0s        924.3mV    1.05V      809.5mV
264.8ps   924.6mV    1.05V      808.9mV
324.6ps   923.1mV    1.05V      858.9mV
379.3ps   937.9mV    1.051V     985.5mV
447.8ps   1.03V      1.049V     1.235V
560.7ps   1.295V     1.097V     1.641V
649.9ps   1.513V     1.198V     1.818V
817.2ps   1.748V     1.411V     1.883V
1.12ns    1.798V     1.626V     1.889V
800ns     1.8V       1.66V      1.89V
[Rising Waveform]
R_fixture = 50
V_fixture = 0
V_fixture_min = 0
V_fixture_max = 0
| Time   V(typ)   V(min)   V(max)
0s        20.53nV    1.065uV    9.448nV
445.3ps   -2.041mV   -355.9uV   23.55mV
898.5ps   154.5mV    18.22mV    352.9mV
1.548ns   403.6mV    178.7mV    718.6mV
2.124ns   584mV      290.8mV    900.1mV
2.569ns   688.3mV    367.8mV    974.9mV
3.693ns   836.9mV    522.1mV    1.056V
5.202ns   907.7mV    639.6mV    1.09V
9.495ns   946.9mV    730.3mV    1.106V
800ns     950.2mV    742.8mV    1.106V
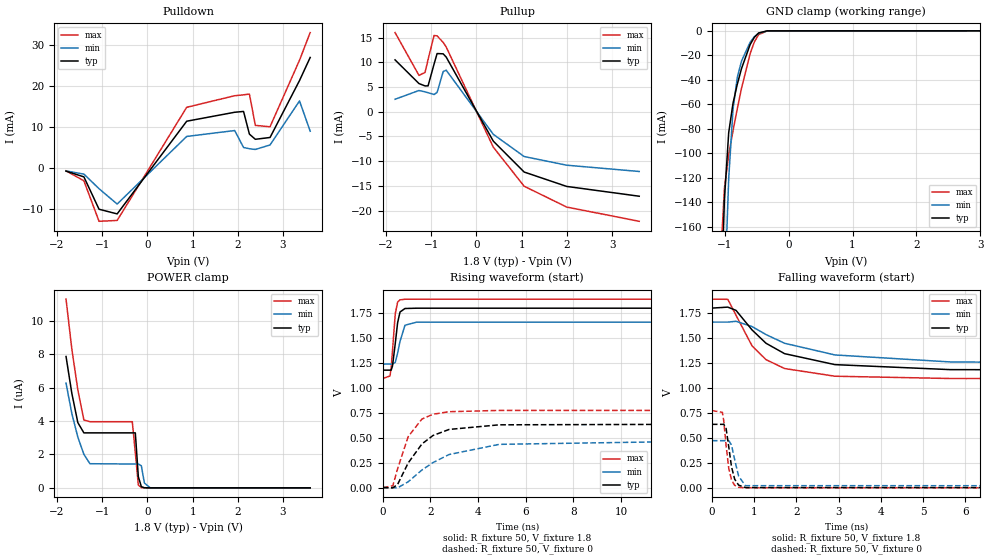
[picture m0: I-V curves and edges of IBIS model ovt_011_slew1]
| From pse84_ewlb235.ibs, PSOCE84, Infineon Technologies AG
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[Model] ovt_011_slew1
Model_type I/O
Enable   Active-High
Vinl  =  0.54
Vinh  =  1.26
Vmeas =  0.9
Cref  =  15e-12
| Capacitance   typ   min   max
C_comp   1.39974e-12   1.35992e-12   1.44753e-12
| Variables   typ   min   max
[GND Clamp Reference]   0   0   0
[POWER Clamp Reference]   1.8   1.66   1.89
[Pulldown Reference]   0   0   0
[Pullup Reference]   1.8   1.66   1.89
[Temperature Range]   25   125   -40
[Voltage Range]   1.8   1.66   1.89
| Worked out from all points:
|   slope of the pulldown table from 0 to 0.27 V, typ, clamps not added: 53.3 ohm
|   slope of the pullup table from 0 to 0.27 V, typ, clamps not added: 60.8 ohm
|   GND clamp passes 1 mA (typ) near -0.43 V on its own axis
|   falling waveform, R_fixture 50, V_fixture 1.8: 20-80 % time 1.24ns typ, 1.95ns min, 830ps max; typ from 1.8 V to 1.18 V
|   falling waveform, R_fixture 50, V_fixture 0: 20-80 % time 138ps typ, 160ps min, 123ps max; typ from 0.636 V to 0 V
|   rising waveform, R_fixture 50, V_fixture 1.8: 20-80 % time 178ps typ, 236ps min, 148ps max; typ from 1.18 V to 1.8 V
|   rising waveform, R_fixture 50, V_fixture 0: 20-80 % time 1.21ns typ, 2.18ns min, 754ps max; typ from 0 V to 0.636 V
[GND Clamp]
| Voltage   I(typ)   I(min)   I(max)
-1.271V   -717.5mA   -832.8mA   -643.6mA
-1.07V    -241.9mA   -348.3mA   -192.2mA
-1.003V   -137.2mA   -218.1mA   -128.1mA
-936.6mV  -83.06mA   -120.7mA   -101.3mA
-869.7mV  -59.26mA   -64.32mA   -81.77mA
-802.8mV  -43.7mA    -38.08mA   -63.69mA
-735.9mV  -30.76mA   -24.63mA   -46.83mA
-602.1mV  -11.27mA   -9.362mA   -18.72mA
-535.2mV  -5.241mA   -4.803mA   -9.042mA
-468.3mV  -1.746mA   -1.965mA   -3.086mA
-334.5mV  -35.9uA    -120.8uA   -33.39uA
3.6V      0A         0A         0A
[POWER Clamp]
| Voltage   I(typ)   I(min)   I(max)
-1.8V     7.872uA    6.273uA    11.31uA
-1.672V   5.671uA    4.461uA    8.32uA
-1.539V   3.91uA     3.037uA    5.87uA
-1.405V   3.295uA    2.008uA    4.063uA
-1.271V   3.295uA    1.447uA    3.964uA
-334.5mV  3.295uA    1.429uA    3.964uA
-267.6mV  3.295uA    1.429uA    2.099uA
-200.7mV  664.1nA    1.429uA    166.6nA
-133.8mV  69.92nA    1.319uA    14.86nA
-66.9mV   7.33nA     291.5nA    4.066nA
62.07mV   0A         0A         0A
3.6V      0A         0A         0A
[Pulldown]
| Voltage   I(typ)   I(min)   I(max)
-1.8V     -821.3uA   -770uA     -752.7uA
-1.405V   -2.23mA    -1.552mA   -3.186mA
-1.07V    -10.15mA   -5.122mA   -13.1mA
-669mV    -11.29mA   -8.877mA   -12.89mA
869mV     11.39mA    7.663mA    14.79mA
1.93V     13.58mA    9.107mA    17.63mA
2.126V    13.78mA    4.964mA    17.85mA
2.256V    8.226mA    4.658mA    18.03mA
2.387V    6.966mA    4.478mA    10.37mA
2.712V    7.408mA    5.577mA    10.03mA
3.364V    21.34mA    16.35mA    26.32mA
3.6V      26.99mA    8.945mA    33.08mA
[Pullup]
| Voltage   I(typ)   I(min)   I(max)
-1.8V     10.48mA    2.52mA     16mA
-1.271V   5.692mA    4.29mA     7.339mA
-1.137V   5.216mA    4.019mA    7.937mA
-1.07V    5.224mA    3.847mA    10.52mA
-936.6mV  9.646mA    3.477mA    15.42mA
-869.7mV  11.76mA    3.903mA    15.33mA
-735.9mV  11.7mA     8.107mA    14.01mA
-669mV    11.05mA    8.398mA    13.08mA
372.4mV   -5.939mA   -4.563mA   -7.158mA
1.055V    -12.19mA   -9.054mA   -15.06mA
1.996V    -15.1mA    -10.81mA   -19.27mA
3.6V      -17.08mA   -12.08mA   -22.15mA
[Ramp]
dV/dt_r   0.381715/1.20603n  0.283779/2.17967n  0.464622/0.754479n
dV/dt_f   0.373486/1.23801n  0.252676/1.9505n  0.47771/0.830319n
R_load = 50
[Falling Waveform]
R_fixture = 50
V_fixture = 1.8
V_fixture_min = 1.66
V_fixture_max = 1.89
| Time   V(typ)   V(min)   V(max)
0s        1.8V       1.66V      1.89V
377.3ps   1.81V      1.66V      1.888V
572.4ps   1.777V     1.668V     1.728V
952.3ps   1.581V     1.615V     1.421V
1.282ns   1.448V     1.535V     1.284V
1.721ns   1.344V     1.448V     1.195V
2.914ns   1.234V     1.331V     1.118V
5.643ns   1.184V     1.261V     1.095V
15ns      1.177V     1.238V     1.094V
800ns     1.178V     1.239V     1.094V
[Falling Waveform]
R_fixture = 50
V_fixture = 0
V_fixture_min = 0
V_fixture_max = 0
| Time   V(typ)   V(min)   V(max)
0s        636.2mV    473mV      774.4mV
248.2ps   636mV      473mV      756.2mV
281.7ps   637mV      473mV      669.3mV
337.1ps   594.6mV    472.8mV    424.4mV
398ps     416mV      473.5mV    201.1mV
464.8ps   211.5mV    429mV      79.11mV
539.9ps   86.89mV    281.6mV    25.27mV
633.8ps   27.25mV    117.1mV    5.343mV
794.7ps   2.925mV    21.72mV    595.6uV
800ns     25.74nV    1.294uV    12.09nV
[Rising Waveform]
R_fixture = 50
V_fixture = 1.8
V_fixture_min = 1.66
V_fixture_max = 1.89
| Time   V(typ)   V(min)   V(max)
0s        1.178V     1.239V     1.094V
302.7ps   1.178V     1.239V     1.12V
349.4ps   1.178V     1.239V     1.205V
403.8ps   1.218V     1.239V     1.368V
521.9ps   1.446V     1.256V     1.745V
619.6ps   1.653V     1.348V     1.86V
721.1ps   1.761V     1.467V     1.883V
929.8ps   1.796V     1.628V     1.889V
1.409ns   1.799V     1.659V     1.889V
800ns     1.8V       1.66V      1.89V
[Rising Waveform]
R_fixture = 50
V_fixture = 0
V_fixture_min = 0
V_fixture_max = 0
| Time   V(typ)   V(min)   V(max)
0s        25.74nV    1.294uV    12.09nV
419.7ps   -2.277mV   -22.07uV   18.8mV
620.5ps   32.76mV    -1.699mV   189.9mV
1.063ns   247.2mV    58.7mV     511.2mV
1.641ns   438mV      176.9mV    687.7mV
2.104ns   522.7mV    251.2mV    735.9mV
2.781ns   583.5mV    332.1mV    761.3mV
4.886ns   629.8mV    433.9mV    774.3mV
15.57ns   636.4mV    473.8mV    774.4mV
800ns     636.2mV    473mV      774.4mV
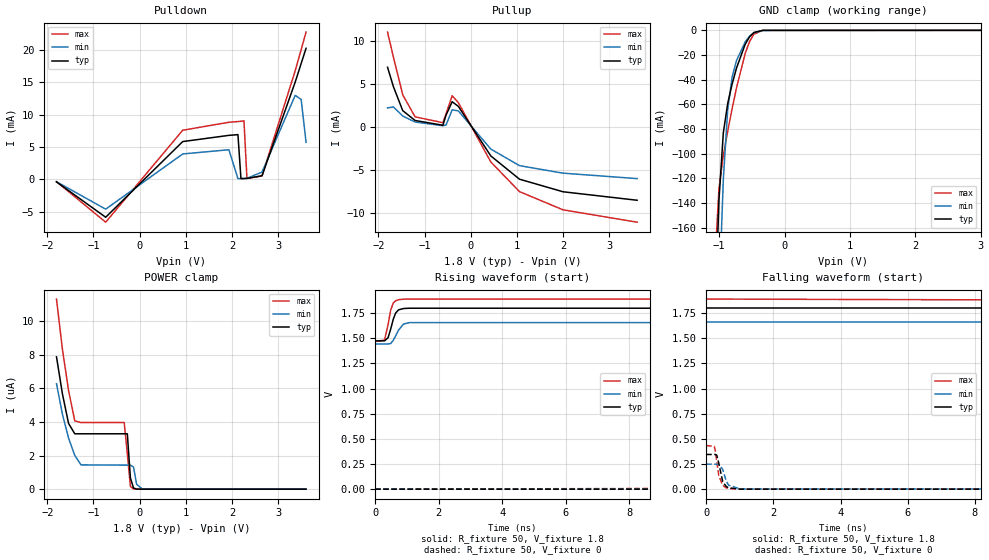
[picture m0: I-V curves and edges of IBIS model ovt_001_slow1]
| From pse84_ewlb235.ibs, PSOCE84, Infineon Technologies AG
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[Model] ovt_001_slow1
Model_type I/O
Enable   Active-High
Vinl  =  0.54
Vinh  =  1.26
Vmeas =  0.9
Cref  =  15e-12
| Capacitance   typ   min   max
C_comp   1.39974e-12   1.35992e-12   1.44753e-12
| Variables   typ   min   max
[GND Clamp Reference]   0   0   0
[POWER Clamp Reference]   1.8   1.66   1.89
[Pulldown Reference]   0   0   0
[Pullup Reference]   1.8   1.66   1.89
[Temperature Range]   25   125   -40
[Voltage Range]   1.8   1.66   1.89
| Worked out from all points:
|   slope of the pulldown table from 0 to 0.27 V, typ, clamps not added: 107 ohm
|   slope of the pullup table from 0 to 0.27 V, typ, clamps not added: 122 ohm
|   GND clamp passes 1 mA (typ) near -0.43 V on its own axis
|   falling waveform, R_fixture 50, V_fixture 1.8: 20-80 % time 67ns typ, 102ns min, 38.8ns max; typ from 1.8 V to 1.47 V
|   falling waveform, R_fixture 50, V_fixture 0: 20-80 % time 136ps typ, 154ps min, 127ps max; typ from 0.344 V to 0 V
|   rising waveform, R_fixture 50, V_fixture 1.8: 20-80 % time 176ps typ, 227ps min, 152ps max; typ from 1.47 V to 1.8 V
|   rising waveform, R_fixture 50, V_fixture 0: 20-80 % time 80.2ns typ, 119ns min, 50ns max; typ from 0 V to 0.344 V
[GND Clamp]
| Voltage   I(typ)   I(min)   I(max)
-1.271V   -717.5mA   -832.8mA   -643.6mA
-1.07V    -241.9mA   -348.3mA   -192.2mA
-1.003V   -137.2mA   -218.1mA   -128.1mA
-936.6mV  -83.06mA   -120.7mA   -101.3mA
-869.7mV  -59.26mA   -64.32mA   -81.77mA
-802.8mV  -43.7mA    -38.08mA   -63.69mA
-735.9mV  -30.76mA   -24.63mA   -46.83mA
-602.1mV  -11.27mA   -9.362mA   -18.72mA
-535.2mV  -5.241mA   -4.803mA   -9.042mA
-468.3mV  -1.746mA   -1.965mA   -3.086mA
-334.5mV  -35.9uA    -120.8uA   -33.39uA
3.6V      0A         0A         0A
[POWER Clamp]
| Voltage   I(typ)   I(min)   I(max)
-1.8V     7.872uA    6.273uA    11.31uA
-1.672V   5.671uA    4.461uA    8.32uA
-1.539V   3.91uA     3.037uA    5.87uA
-1.405V   3.295uA    2.008uA    4.063uA
-1.271V   3.295uA    1.447uA    3.964uA
-334.5mV  3.295uA    1.429uA    3.964uA
-267.6mV  3.295uA    1.429uA    2.099uA
-200.7mV  664.1nA    1.429uA    166.6nA
-133.8mV  69.92nA    1.319uA    14.86nA
-66.9mV   7.33nA     291.5nA    4.066nA
62.07mV   0A         0A         0A
3.6V      0A         0A         0A
[Pulldown]
| Voltage   I(typ)   I(min)   I(max)
-1.8V     -410.4uA   -384.8uA   -375.8uA
-735.9mV  -5.884mA   -4.631mA   -6.649mA
931mV     5.832mA    3.913mA    7.589mA
1.93V     6.791mA    4.567mA    8.819mA
2.126V    6.905mA    87.8uA     8.932mA
2.191V    90.18uA    111.8uA    8.968mA
2.256V    101.7uA    127.7uA    9.046mA
2.321V    127.9uA    151.8uA    138.4uA
2.647V    542.8uA    1.103mA    503.4uA
3.364V    15.02mA    12.98mA    16.77mA
3.494V    17.92mA    12.35mA    20.07mA
3.6V      20.27mA    5.714mA    22.78mA
[Pullup]
| Voltage   I(typ)   I(min)   I(max)
-1.8V     6.915mA    2.21mA     11mA
-1.672V   4.657mA    2.305mA    8.067mA
-1.472V   1.891mA    1.266mA    3.727mA
-1.204V   740.5uA    564.1uA    1.164mA
-602.1mV  188.2uA    135.6uA    484.5uA
-535.2mV  1.35mA     214.2uA    1.515mA
-401.4mV  2.919mA    1.981mA    3.611mA
-267.6mV  2.376mA    1.851mA    2.813mA
434.5mV   -3.371mA   -2.579mA   -4.072mA
1.055V    -6.07mA    -4.497mA   -7.512mA
1.996V    -7.528mA   -5.37mA    -9.625mA
3.6V      -8.515mA   -6.003mA   -11.06mA
[Ramp]
dV/dt_r   0.206662/80.2231n  0.148706/0.118681u  0.260237/50.0371n
dV/dt_f   0.195415/66.9633n  0.129995/0.10228u  0.253907/38.7814n
R_load = 50
[Falling Waveform]
R_fixture = 50
V_fixture = 1.8
V_fixture_min = 1.66
V_fixture_max = 1.89
| Time   V(typ)   V(min)   V(max)
0s        1.8V       1.66V      1.89V
8.638ns   1.8V       1.66V      1.882V
18.09ns   1.786V     1.66V      1.788V
29.83ns   1.736V     1.65V      1.681V
49.11ns   1.654V     1.616V     1.573V
71.98ns   1.585V     1.574V     1.513V
105.4ns   1.529V     1.526V     1.481V
168.6ns   1.489V     1.477V     1.469V
268.9ns   1.476V     1.452V     1.467V
800ns     1.474V     1.443V     1.467V
[Falling Waveform]
R_fixture = 50
V_fixture = 0
V_fixture_min = 0
V_fixture_max = 0
| Time   V(typ)   V(min)   V(max)
0s        344.4mV    247.9mV    433.7mV
244.2ps   344.3mV    247.9mV    424.4mV
275.7ps   344.5mV    247.9mV    379.1mV
318.4ps   335.9mV    247.8mV    270.4mV
377.1ps   256.3mV    247.9mV    136.1mV
492.9ps   76.65mV    196.5mV    36.78mV
596.5ps   26.42mV    82.74mV    12.64mV
668.9ps   12.83mV    38.91mV    4.752mV
1.021ns   -327.6uV   1.474mV    -636.1uV
800ns     34.17nV    1.629uV    16.72nV
[Rising Waveform]
R_fixture = 50
V_fixture = 1.8
V_fixture_min = 1.66
V_fixture_max = 1.89
| Time   V(typ)   V(min)   V(max)
0s        1.474V     1.443V     1.467V
298.2ps   1.475V     1.443V     1.482V
408.5ps   1.505V     1.444V     1.635V
490ps     1.59V      1.447V     1.779V
572.4ps   1.689V     1.479V     1.85V
646.7ps   1.751V     1.524V     1.873V
739.5ps   1.783V     1.582V     1.884V
897ps     1.796V     1.641V     1.889V
1.08ns    1.799V     1.656V     1.89V
800ns     1.8V       1.66V      1.89V
[Rising Waveform]
R_fixture = 50
V_fixture = 0
V_fixture_min = 0
V_fixture_max = 0
| Time   V(typ)   V(min)   V(max)
0s        34.16nV    1.628uV    16.72nV
11.63ns   -114.7uV   -212.8uV   8.425mV
21.9ns    14.84mV    1.472mV    85.79mV
37.66ns   74.42mV    18.71mV    204.3mV
59.39ns   154.6mV    58.73mV    310.2mV
84.47ns   222.4mV    103.7mV    373.1mV
126.3ns   286.5mV    160mV      414.6mV
200.6ns   328.7mV    212.4mV    431.1mV
300.9ns   341.6mV    237.4mV    433.5mV
800ns     344.4mV    247.8mV    433.7mV
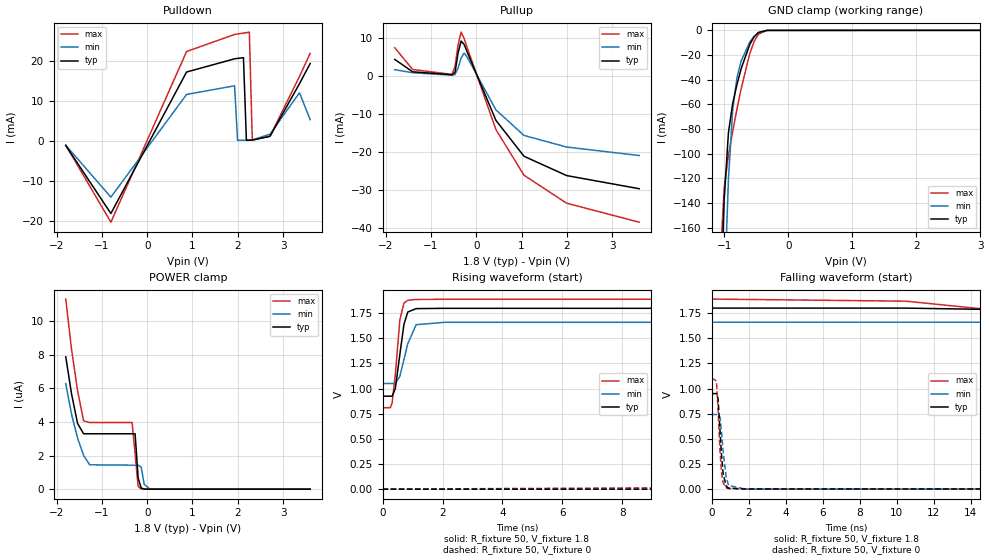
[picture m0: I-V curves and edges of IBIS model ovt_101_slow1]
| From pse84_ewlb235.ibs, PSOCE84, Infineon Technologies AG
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[Model] ovt_101_slow1
Model_type I/O
Enable   Active-High
Vinl  =  0.54
Vinh  =  1.26
Vmeas =  0.9
Cref  =  15e-12
| Capacitance   typ   min   max
C_comp   1.39974e-12   1.35992e-12   1.44753e-12
| Variables   typ   min   max
[GND Clamp Reference]   0   0   0
[POWER Clamp Reference]   1.8   1.66   1.89
[Pulldown Reference]   0   0   0
[Pullup Reference]   1.8   1.66   1.89
[Temperature Range]   25   125   -40
[Voltage Range]   1.8   1.66   1.89
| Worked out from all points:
|   slope of the pulldown table from 0 to 0.27 V, typ, clamps not added: 35.4 ohm
|   slope of the pullup table from 0 to 0.27 V, typ, clamps not added: 34.9 ohm
|   GND clamp passes 1 mA (typ) near -0.43 V on its own axis
|   falling waveform, R_fixture 50, V_fixture 1.8: 20-80 % time 90.5ns typ, 140ns min, 50.5ns max; typ from 1.8 V to 0.924 V
|   falling waveform, R_fixture 50, V_fixture 0: 20-80 % time 203ps typ, 239ps min, 183ps max; typ from 0.95 V to 0 V
|   rising waveform, R_fixture 50, V_fixture 1.8: 20-80 % time 228ps typ, 316ps min, 182ps max; typ from 0.924 V to 1.8 V
|   rising waveform, R_fixture 50, V_fixture 0: 20-80 % time 108ns typ, 166ns min, 64.1ns max; typ from 0 V to 0.95 V
[GND Clamp]
| Voltage   I(typ)   I(min)   I(max)
-1.271V   -717.5mA   -832.8mA   -643.6mA
-1.07V    -241.9mA   -348.3mA   -192.2mA
-1.003V   -137.2mA   -218.1mA   -128.1mA
-936.6mV  -83.06mA   -120.7mA   -101.3mA
-869.7mV  -59.26mA   -64.32mA   -81.77mA
-802.8mV  -43.7mA    -38.08mA   -63.69mA
-735.9mV  -30.76mA   -24.63mA   -46.83mA
-602.1mV  -11.27mA   -9.362mA   -18.72mA
-535.2mV  -5.241mA   -4.803mA   -9.042mA
-468.3mV  -1.746mA   -1.965mA   -3.086mA
-334.5mV  -35.9uA    -120.8uA   -33.39uA
3.6V      0A         0A         0A
[POWER Clamp]
| Voltage   I(typ)   I(min)   I(max)
-1.8V     7.872uA    6.273uA    11.31uA
-1.672V   5.671uA    4.461uA    8.32uA
-1.539V   3.91uA     3.037uA    5.87uA
-1.405V   3.295uA    2.008uA    4.063uA
-1.271V   3.295uA    1.447uA    3.964uA
-334.5mV  3.295uA    1.429uA    3.964uA
-267.6mV  3.295uA    1.429uA    2.099uA
-200.7mV  664.1nA    1.429uA    166.6nA
-133.8mV  69.92nA    1.319uA    14.86nA
-66.9mV   7.33nA     291.5nA    4.066nA
62.07mV   0A         0A         0A
3.6V      0A         0A         0A
[Pulldown]
| Voltage   I(typ)   I(min)   I(max)
-1.8V     -1.234mA   -1.158mA   -1.131mA
-802.8mV  -18.22mA   -14.13mA   -20.39mA
869mV     17.13mA    11.53mA    22.25mA
1.93V     20.43mA    13.69mA    26.52mA
1.996V    20.53mA    60.74uA    26.64mA
2.126V    20.72mA    87.79uA    26.86mA
2.191V    90.18uA    111.8uA    26.96mA
2.256V    101.7uA    127.6uA    27.11mA
2.321V    127.9uA    151.7uA    138.4uA
2.712V    1.068mA    1.607mA    1.088mA
3.364V    14.22mA    11.94mA    16.02mA
3.6V      19.26mA    5.244mA    21.8mA
[Pullup]
| Voltage   I(typ)   I(min)   I(max)
-1.8V     4.243mA    1.55mA     7.312mA
-1.405V   983.7uA    736.5uA    1.593mA
-535.2mV  202.6uA    119.8uA    309.9uA
-468.3mV  890.9uA    260.9uA    2.361mA
-401.4mV  5.937mA    1.989mA    8.109mA
-334.5mV  9.075mA    4.625mA    11.44mA
-267.6mV  8.194mA    5.937mA    9.765mA
-200.7mV  6.226mA    4.852mA    7.377mA
434.5mV   -11.79mA   -9.038mA   -14.21mA
1.055V    -21.24mA   -15.76mA   -26.23mA
1.996V    -26.32mA   -18.81mA   -33.59mA
3.6V      -29.78mA   -21.04mA   -38.59mA
[Ramp]
dV/dt_r   0.570065/0.108027u  0.444216/0.166195u  0.663527/64.0722n
dV/dt_f   0.525422/90.5218n  0.365635/0.139876u  0.64831/50.4886n
R_load = 50
[Falling Waveform]
R_fixture = 50
V_fixture = 1.8
V_fixture_min = 1.66
V_fixture_max = 1.89
| Time   V(typ)   V(min)   V(max)
0s        1.8V       1.66V      1.89V
10.49ns   1.8V       1.66V      1.869V
20.61ns   1.77V      1.659V     1.682V
41.8ns    1.586V     1.608V     1.318V
66.88ns   1.386V     1.509V     1.056V
91.96ns   1.237V     1.413V     924.9mV
125.4ns   1.107V     1.311V     852.9mV
196.8ns   982.7mV    1.176V     816mV
310.4ns   934.5mV    1.09V      809.8mV
800ns     924.3mV    1.051V     809.5mV
[Falling Waveform]
R_fixture = 50
V_fixture = 0
V_fixture_min = 0
V_fixture_max = 0
| Time   V(typ)   V(min)   V(max)
0s        950.2mV    741.9mV    1.106V
263.6ps   950.2mV    741.9mV    1.076V
350.6ps   898.6mV    741.8mV    788.2mV
454.8ps   584.3mV    716.4mV    382.3mV
536.3ps   342.9mV    570.8mV    164.5mV
624.2ps   157.5mV    373.4mV    63.55mV
787.5ps   30.62mV    122.4mV    13.95mV
914.2ps   10.18mV    37.64mV    6.173mV
1.815ns   1.798mV    1.526mV    1.693mV
800ns     20.53nV    1.06uV     9.509nV
[Rising Waveform]
R_fixture = 50
V_fixture = 1.8
V_fixture_min = 1.66
V_fixture_max = 1.89
| Time   V(typ)   V(min)   V(max)
0s        924.3mV    1.05V      809.5mV
260.8ps   924.5mV    1.05V      810.5mV
319.2ps   924.3mV    1.05V      856.5mV
426.3ps   1.001V     1.05V      1.141V
578ps     1.341V     1.121V     1.685V
713.5ps   1.638V     1.29V      1.85V
840.8ps   1.761V     1.445V     1.878V
1.121ns   1.795V     1.635V     1.886V
2.073ns   1.798V     1.659V     1.888V
800ns     1.8V       1.66V      1.89V
[Rising Waveform]
R_fixture = 50
V_fixture = 0
V_fixture_min = 0
V_fixture_max = 0
| Time   V(typ)   V(min)   V(max)
0s        20.45nV    1.056uV    9.496nV
15.8ns    274uV      -4.915uV   23.34mV
28.2ns    38.37mV    5.012mV    196.9mV
54.97ns   241.5mV    78.11mV    571.3mV
83.77ns   447.5mV    193.8mV    827.7mV
108.8ns   587.7mV    289mV      948.8mV
150.6ns   744.5mV    420.9mV    1.04V
227.8ns   875.6mV    577.4mV    1.09V
346.5ns   932.4mV    682.5mV    1.104V
800ns     950.1mV    740.4mV    1.106V
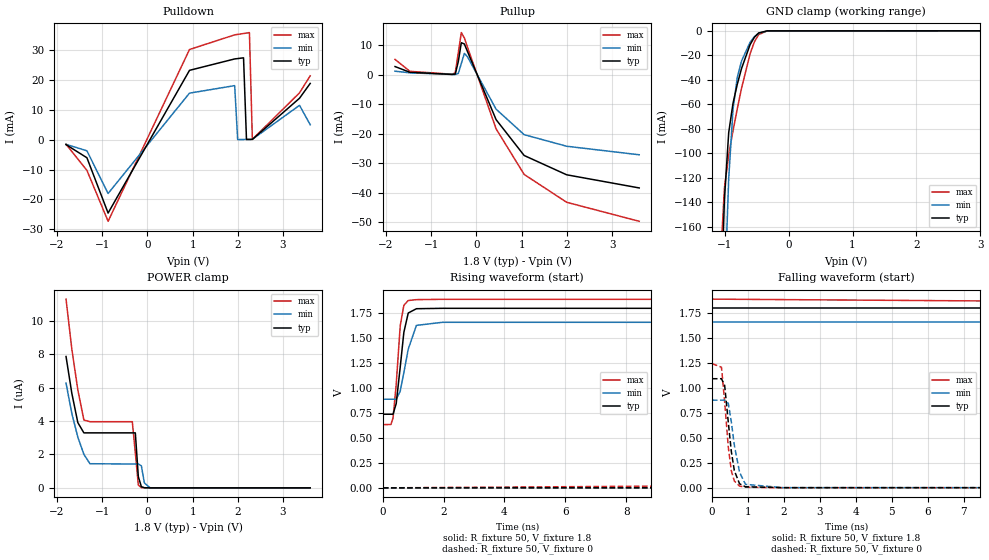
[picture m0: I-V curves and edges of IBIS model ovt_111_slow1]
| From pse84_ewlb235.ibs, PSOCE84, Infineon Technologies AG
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[Model] ovt_111_slow1
Model_type I/O
Enable   Active-High
Vinl  =  0.54
Vinh  =  1.26
Vmeas =  0.9
Cref  =  15e-12
| Capacitance   typ   min   max
C_comp   1.39974e-12   1.35992e-12   1.44753e-12
| Variables   typ   min   max
[GND Clamp Reference]   0   0   0
[POWER Clamp Reference]   1.8   1.66   1.89
[Pulldown Reference]   0   0   0
[Pullup Reference]   1.8   1.66   1.89
[Temperature Range]   25   125   -40
[Voltage Range]   1.8   1.66   1.89
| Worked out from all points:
|   slope of the pulldown table from 0 to 0.27 V, typ, clamps not added: 26.7 ohm
|   slope of the pullup table from 0 to 0.27 V, typ, clamps not added: 27.1 ohm
|   GND clamp passes 1 mA (typ) near -0.43 V on its own axis
|   falling waveform, R_fixture 50, V_fixture 1.8: 20-80 % time 93.7ns typ, 153ns min, 49.3ns max; typ from 1.8 V to 0.737 V
|   falling waveform, R_fixture 50, V_fixture 0: 20-80 % time 197ps typ, 230ps min, 179ps max; typ from 1.09 V to 0 V
|   rising waveform, R_fixture 50, V_fixture 1.8: 20-80 % time 219ps typ, 304ps min, 174ps max; typ from 0.737 V to 1.8 V
|   rising waveform, R_fixture 50, V_fixture 0: 20-80 % time 111ns typ, 175ns min, 65.3ns max; typ from 0 V to 1.09 V
[GND Clamp]
| Voltage   I(typ)   I(min)   I(max)
-1.271V   -717.5mA   -832.8mA   -643.6mA
-1.07V    -241.9mA   -348.3mA   -192.2mA
-1.003V   -137.2mA   -218.1mA   -128.1mA
-936.6mV  -83.06mA   -120.7mA   -101.3mA
-869.7mV  -59.26mA   -64.32mA   -81.77mA
-802.8mV  -43.7mA    -38.08mA   -63.69mA
-735.9mV  -30.76mA   -24.63mA   -46.83mA
-602.1mV  -11.27mA   -9.362mA   -18.72mA
-535.2mV  -5.241mA   -4.803mA   -9.042mA
-468.3mV  -1.746mA   -1.965mA   -3.086mA
-334.5mV  -35.9uA    -120.8uA   -33.39uA
3.6V      0A         0A         0A
[POWER Clamp]
| Voltage   I(typ)   I(min)   I(max)
-1.8V     7.872uA    6.273uA    11.31uA
-1.672V   5.671uA    4.461uA    8.32uA
-1.539V   3.91uA     3.037uA    5.87uA
-1.405V   3.295uA    2.008uA    4.063uA
-1.271V   3.295uA    1.447uA    3.964uA
-334.5mV  3.295uA    1.429uA    3.964uA
-267.6mV  3.295uA    1.429uA    2.099uA
-200.7mV  664.1nA    1.429uA    166.6nA
-133.8mV  69.92nA    1.319uA    14.86nA
-66.9mV   7.33nA     291.5nA    4.066nA
62.07mV   0A         0A         0A
3.6V      0A         0A         0A
[Pulldown]
| Voltage   I(typ)   I(min)   I(max)
-1.8V     -1.642mA   -1.541mA   -1.505mA
-1.338V   -6.046mA   -3.71mA    -10.27mA
-869.7mV  -24.63mA   -18.05mA   -27.4mA
931mV     23.33mA    15.67mA    30.33mA
1.93V     27.16mA    18.19mA    35.25mA
1.996V    27.28mA    60.69uA    35.41mA
2.126V    27.53mA    87.76uA    35.7mA
2.191V    90.18uA    111.8uA    35.84mA
2.256V    101.7uA    127.6uA    36.02mA
2.321V    127.9uA    151.6uA    138.4uA
3.364V    13.95mA    11.57mA    15.77mA
3.6V      18.92mA    5.062mA    21.48mA
[Pullup]
| Voltage   I(typ)   I(min)   I(max)
-1.8V     2.805mA    1.23mA     5.227mA
-1.472V   868uA      690.1uA    1.192mA
-535.2mV  146.1uA    119.7uA    198.4uA
-468.3mV  264.7uA    106.1uA    724.2uA
-401.4mV  4.482mA    470.6uA    7.523mA
-334.5mV  10.88mA    3.83mA     14.32mA
-267.6mV  10.46mA    7.257mA    12.52mA
-200.7mV  7.999mA    6.176mA    9.48mA
434.5mV   -15.16mA   -11.63mA   -18.27mA
1.055V    -27.31mA   -20.26mA   -33.72mA
1.996V    -33.85mA   -24.18mA   -43.16mA
3.6V      -38.3mA    -27.07mA   -49.6mA
[Ramp]
dV/dt_r   0.655479/0.111359u  0.525297/0.174869u  0.747048/65.3441n
dV/dt_f   0.637729/93.7209n  0.462829/0.152833u  0.754099/49.3204n
R_load = 50
[Falling Waveform]
R_fixture = 50
V_fixture = 1.8
V_fixture_min = 1.66
V_fixture_max = 1.89
| Time   V(typ)   V(min)   V(max)
0s        1.8V       1.66V      1.89V
11.58ns   1.8V       1.66V      1.862V
21.2ns    1.77V      1.659V     1.67V
38.12ns   1.612V     1.621V     1.323V
63.19ns   1.368V     1.512V     967mV
88.27ns   1.175V     1.398V     777.6mV
121.7ns   996.9mV    1.268V     682.8mV
196.3ns   814.7mV    1.077V     640mV
316.1ns   749.8mV    949mV      633.6mV
800ns     737.1mV    888.6mV    633.2mV
[Falling Waveform]
R_fixture = 50
V_fixture = 0
V_fixture_min = 0
V_fixture_max = 0
| Time   V(typ)   V(min)   V(max)
0s        1.093V     878.3mV    1.245V
267.2ps   1.093V     878.3mV    1.208V
355.3ps   1.026V     878.3mV    861.3mV
456.7ps   655.8mV    846.2mV    407.1mV
540.5ps   364.9mV    660.7mV    170.6mV
624.2ps   172.9mV    428.1mV    69.42mV
769ps     40.8mV     157.1mV    17.56mV
932.8ps   10.9mV     35.25mV    6.225mV
1.975ns   2.044mV    1.864mV    1.673mV
800ns     17.29nV    907.6nV    7.854nV
[Rising Waveform]
R_fixture = 50
V_fixture = 1.8
V_fixture_min = 1.66
V_fixture_max = 1.89
| Time   V(typ)   V(min)   V(max)
0s        737.1mV    887.9mV    633.2mV
264.3ps   737.3mV    887.9mV    634.5mV
335.5ps   737.5mV    888mV      699.4mV
439.4ps   843.9mV    887.9mV    1.036V
571.5ps   1.21V      968.1mV    1.623V
690.7ps   1.557V     1.154V     1.828V
835ps     1.751V     1.389V     1.876V
1.104ns   1.794V     1.627V     1.885V
1.959ns   1.798V     1.658V     1.888V
800ns     1.8V       1.66V      1.89V
[Rising Waveform]
R_fixture = 50
V_fixture = 0
V_fixture_min = 0
V_fixture_max = 0
| Time   V(typ)   V(min)   V(max)
0s        17.09nV    900.8nV    7.838nV
18.34ns   900.6uV    74.05uV    35.02mV
31.41ns   47.74mV    6.865mV    231mV
55.64ns   243.8mV    76.28mV    600.6mV
80.82ns   447.8mV    184.4mV    875.2mV
105.9ns   617.9mV    292.8mV    1.038V
147.7ns   819.9mV    450.7mV    1.159V
220.4ns   987.8mV    643.2mV    1.221V
345.4ns   1.068V     794.6mV    1.242V
800ns     1.092V     875.5mV    1.245V
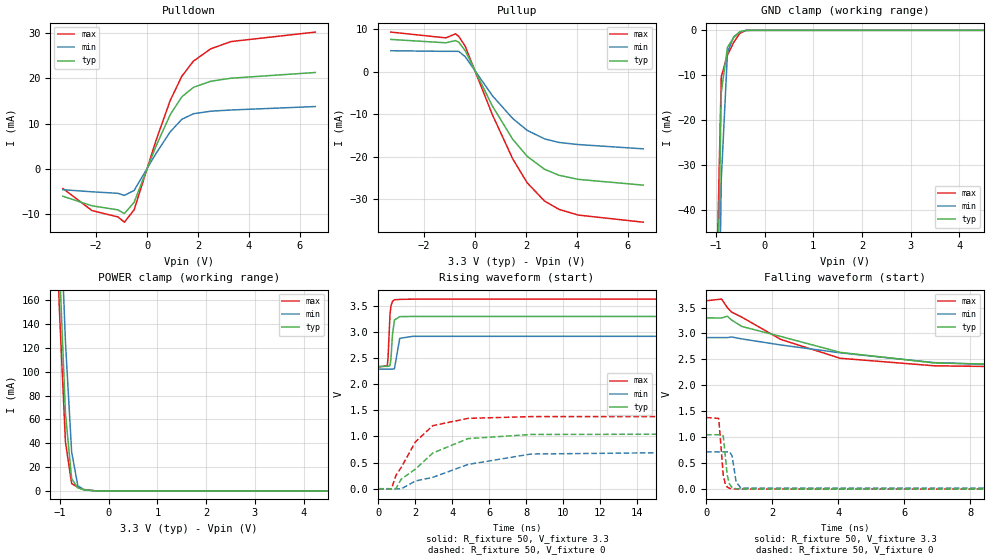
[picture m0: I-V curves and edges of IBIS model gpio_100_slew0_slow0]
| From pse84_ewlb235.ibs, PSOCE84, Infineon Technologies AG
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[Model] gpio_100_slew0_slow0
Model_type I/O
Enable   Active-High
Vinl  =  0.99
Vinh  =  2.31
Vmeas =  1.65
Cref  =  15e-12
| Capacitance   typ   min   max
C_comp   1.09946e-12   1.086232e-12   1.114407e-12
| Variables   typ   min   max
[GND Clamp Reference]   0   0   0
[POWER Clamp Reference]   3.3   2.92   3.63
[Pulldown Reference]   0   0   0
[Pullup Reference]   3.3   2.92   3.63
[Temperature Range]   25   125   -40
[Voltage Range]   3.3   2.92   3.63
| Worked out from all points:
|   slope of the pulldown table from 0 to 0.495 V, typ, clamps not added: 71.6 ohm
|   slope of the pullup table from 0 to 0.495 V, typ, clamps not added: 83.3 ohm
|   GND clamp passes 1 mA (typ) near -0.57 V on its own axis
|   POWER clamp passes 1 mA (typ) near -0.52 V on its own axis
|   falling waveform, R_fixture 50, V_fixture 3.3: 20-80 % time 3.84ns typ, 5.62ns min, 2.67ns max; typ from 3.3 V to 2.34 V
|   falling waveform, R_fixture 50, V_fixture 0: 20-80 % time 97.2ps typ, 105ps min, 92.9ps max; typ from 1.05 V to 0 V
|   rising waveform, R_fixture 50, V_fixture 3.3: 20-80 % time 111ps typ, 131ps min, 101ps max; typ from 2.34 V to 3.3 V
|   rising waveform, R_fixture 50, V_fixture 0: 20-80 % time 2.32ns typ, 4.09ns min, 1.51ns max; typ from 0 V to 1.05 V
[GND Clamp]
| Voltage   I(typ)   I(min)   I(max)
-1.65V    -892.5mA   -911.9mA   -883.9mA
-1.015V   -92.32mA   -129.7mA   -71.28mA
-888.3mV  -13.83mA   -33.21mA   -10.31mA
-761.4mV  -3.792mA   -4.944mA   -5.509mA
-634.5mV  -1.622mA   -1.436mA   -2.707mA
-507.6mV  -326.2uA   -352.3uA   -651.6uA
-380.7mV  -13.48uA   -32.14uA   -19.55uA
-253.8mV  -189.4nA   -1.276uA   -466.7nA
6.6V      0A         0A         0A
[POWER Clamp]
| Voltage   I(typ)   I(min)   I(max)
-1.523V   838.1mA    872.9mA    823.9mA
-1.142V   346.5mA    405.1mA    310.5mA
-1.015V   193mA      257.4mA    153.9mA
-888.3mV  64.97mA    124.9mA    40.96mA
-761.4mV  10.28mA    32.7mA     6.184mA
-634.5mV  2.553mA    4.346mA    3.067mA
-507.6mV  805.9uA    960.7uA    1.159mA
-253.8mV  1.454uA    10.02uA    1.678uA
6.6V      0A         0A         0A
[Pulldown]
| Voltage   I(typ)   I(min)   I(max)
-3.3V     -6.15mA    -4.7mA     -4.423mA
-2.157V   -8.274mA   -5.164mA   -9.338mA
-1.142V   -9.173mA   -5.496mA   -10.74mA
-888.3mV  -9.988mA   -5.955mA   -11.91mA
-507.6mV  -7.51mA    -4.874mA   -9.177mA
341.4mV   4.84mA     3.25mA     6.058mA
910.3mV   11.98mA    8.162mA    15.13mA
1.366V    15.94mA    10.94mA    20.51mA
1.821V    18.03mA    12.17mA    23.86mA
2.503V    19.39mA    12.74mA    26.6mA
3.3V      20.06mA    13mA       28.2mA
6.6V      21.33mA    13.77mA    30.3mA
[Pullup]
| Voltage   I(typ)   I(min)   I(max)
-3.3V     7.527mA    4.876mA    9.247mA
-1.142V   6.736mA    4.731mA    7.893mA
-761.4mV  7.259mA    4.734mA    8.836mA
-634.5mV  6.868mA    4.727mA    8.248mA
-380.7mV  4.868mA    3.474mA    5.906mA
682.8mV   -8.07mA    -5.651mA   -10.11mA
1.479V    -15.86mA   -11mA      -20.44mA
2.048V    -19.88mA   -13.79mA   -26.08mA
2.731V    -22.92mA   -15.79mA   -30.37mA
3.3V      -24.32mA   -16.63mA   -32.32mA
4.051V    -25.28mA   -17.12mA   -33.65mA
6.6V      -26.63mA   -18.12mA   -35.32mA
[Ramp]
dV/dt_r   0.629211/2.32303n  0.431118/4.09054n  0.828496/1.51258n
dV/dt_f   0.575118/3.8394n  0.378853/5.61748n  0.781718/2.66684n
R_load = 50
[Falling Waveform]
R_fixture = 50
V_fixture = 3.3
V_fixture_min = 2.92
V_fixture_max = 3.63
| Time   V(typ)   V(min)   V(max)
0s        3.3V       2.92V      3.63V
469.4ps   3.299V     2.92V      3.663V
640.8ps   3.333V     2.92V      3.501V
768.1ps   3.261V     2.933V     3.414V
1.087ns   3.134V     2.895V     3.313V
2.267ns   2.942V     2.778V     2.884V
4.067ns   2.636V     2.627V     2.522V
6.921ns   2.432V     2.438V     2.377V
12.77ns   2.352V     2.315V     2.33V
800ns     2.341V     2.289V     2.327V
[Falling Waveform]
R_fixture = 50
V_fixture = 0
V_fixture_min = 0
V_fixture_max = 0
| Time   V(typ)   V(min)   V(max)
0s        1.049V     718.5mV    1.381V
382.9ps   1.049V     718.4mV    1.363V
520.9ps   1.024V     718.5mV    260mV
587ps     605.3mV    718.6mV    90.66mV
638.6ps   272.5mV    718.6mV    41.44mV
706.5ps   99.75mV    720.9mV    16.64mV
785.4ps   33.49mV    645.2mV    6.935mV
909.9ps   7.42mV     141.7mV    2.863mV
1.052ns   2.323mV    21.09mV    2.291mV
800ns     17.18nV    537.9nV    9.913nV
[Rising Waveform]
R_fixture = 50
V_fixture = 3.3
V_fixture_min = 2.92
V_fixture_max = 3.63
| Time   V(typ)   V(min)   V(max)
0s        2.341V     2.289V     2.327V
491.5ps   2.341V     2.289V     2.355V
534.1ps   2.342V     2.289V     2.522V
638.6ps   2.357V     2.289V     3.344V
695ps     2.511V     2.289V     3.508V
766.9ps   2.933V     2.289V     3.584V
878.3ps   3.229V     2.298V     3.616V
1.163ns   3.294V     2.878V     3.624V
1.874ns   3.297V     2.917V     3.628V
800ns     3.3V       2.92V      3.63V
[Rising Waveform]
R_fixture = 50
V_fixture = 0
V_fixture_min = 0
V_fixture_max = 0
| Time   V(typ)   V(min)   V(max)
0s        17.41nV    537.4nV    10.27nV
709.9ps   -8.243mV   37.7uV     -9.009mV
964.6ps   4.04mV     -4.754mV   259.5mV
1.238ns   180.7mV    -4.836mV   403.4mV
2.01ns    374.6mV    147.6mV    897.4mV
2.951ns   683.5mV    217.6mV    1.207V
4.848ns   958.3mV    463.7mV    1.346V
8.247ns   1.038V     663.4mV    1.38V
24.06ns   1.049V     719.8mV    1.381V
800ns     1.049V     718.5mV    1.381V
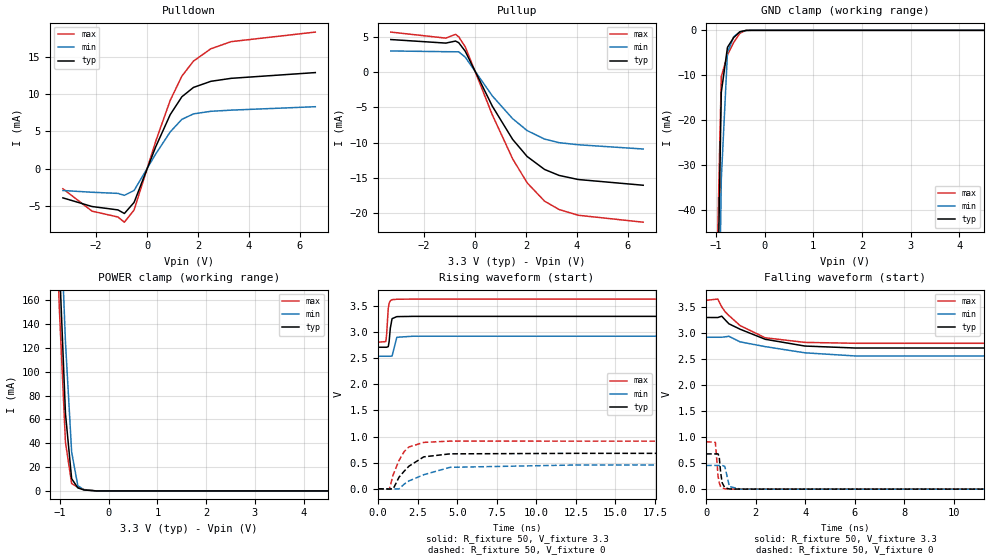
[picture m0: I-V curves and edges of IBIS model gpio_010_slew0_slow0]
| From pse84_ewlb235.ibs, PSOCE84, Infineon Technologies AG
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[Model] gpio_010_slew0_slow0
Model_type I/O
Enable   Active-High
Vinl  =  0.99
Vinh  =  2.31
Vmeas =  1.65
Cref  =  15e-12
| Capacitance   typ   min   max
C_comp   1.09946e-12   1.086232e-12   1.114407e-12
| Variables   typ   min   max
[GND Clamp Reference]   0   0   0
[POWER Clamp Reference]   3.3   2.92   3.63
[Pulldown Reference]   0   0   0
[Pullup Reference]   3.3   2.92   3.63
[Temperature Range]   25   125   -40
[Voltage Range]   3.3   2.92   3.63
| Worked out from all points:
|   slope of the pulldown table from 0 to 0.495 V, typ, clamps not added: 118 ohm
|   slope of the pullup table from 0 to 0.495 V, typ, clamps not added: 139 ohm
|   GND clamp passes 1 mA (typ) near -0.57 V on its own axis
|   POWER clamp passes 1 mA (typ) near -0.52 V on its own axis
|   falling waveform, R_fixture 50, V_fixture 3.3: 20-80 % time 1.91ns typ, 2.86ns min, 1.34ns max; typ from 3.3 V to 2.71 V
|   falling waveform, R_fixture 50, V_fixture 0: 20-80 % time 95.6ps typ, 104ps min, 91.1ps max; typ from 0.678 V to 0 V
|   rising waveform, R_fixture 50, V_fixture 3.3: 20-80 % time 114ps typ, 136ps min, 104ps max; typ from 2.71 V to 3.3 V
|   rising waveform, R_fixture 50, V_fixture 0: 20-80 % time 1.24ns typ, 2.13ns min, 822ps max; typ from 0 V to 0.678 V
[GND Clamp]
| Voltage   I(typ)   I(min)   I(max)
-1.65V    -892.5mA   -911.9mA   -883.9mA
-1.015V   -92.32mA   -129.7mA   -71.28mA
-888.3mV  -13.83mA   -33.21mA   -10.31mA
-761.4mV  -3.792mA   -4.944mA   -5.509mA
-634.5mV  -1.622mA   -1.436mA   -2.707mA
-507.6mV  -326.2uA   -352.3uA   -651.6uA
-380.7mV  -13.48uA   -32.14uA   -19.55uA
-253.8mV  -189.4nA   -1.276uA   -466.7nA
6.6V      0A         0A         0A
[POWER Clamp]
| Voltage   I(typ)   I(min)   I(max)
-1.523V   838.1mA    872.9mA    823.9mA
-1.142V   346.5mA    405.1mA    310.5mA
-1.015V   193mA      257.4mA    153.9mA
-888.3mV  64.97mA    124.9mA    40.96mA
-761.4mV  10.28mA    32.7mA     6.184mA
-634.5mV  2.553mA    4.346mA    3.067mA
-507.6mV  805.9uA    960.7uA    1.159mA
-253.8mV  1.454uA    10.02uA    1.678uA
6.6V      0A         0A         0A
[Pulldown]
| Voltage   I(typ)   I(min)   I(max)
-3.3V     -3.927mA   -2.937mA   -2.706mA
-2.157V   -5.088mA   -3.175mA   -5.708mA
-1.142V   -5.539mA   -3.327mA   -6.49mA
-888.3mV  -6.021mA   -3.588mA   -7.188mA
-507.6mV  -4.537mA   -2.937mA   -5.552mA
341.4mV   2.926mA    1.96mA     3.67mA
910.3mV   7.24mA     4.922mA    9.156mA
1.366V    9.625mA    6.597mA    12.39mA
1.821V    10.88mA    7.332mA    14.41mA
2.503V    11.7mA     7.679mA    16.06mA
3.3V      12.1mA     7.835mA    17.02mA
6.6V      12.87mA    8.295mA    18.3mA
[Pullup]
| Voltage   I(typ)   I(min)   I(max)
-3.3V     4.576mA    2.964mA    5.629mA
-1.142V   4.073mA    2.859mA    4.776mA
-761.4mV  4.362mA    2.848mA    5.31mA
-634.5mV  4.125mA    2.839mA    4.956mA
-380.7mV  2.925mA    2.086mA    3.549mA
682.8mV   -4.848mA   -3.394mA   -6.074mA
1.479V    -9.533mA   -6.609mA   -12.28mA
2.048V    -11.95mA   -8.287mA   -15.67mA
2.731V    -13.78mA   -9.491mA   -18.26mA
3.3V      -14.62mA   -9.995mA   -19.44mA
4.051V    -15.2mA    -10.29mA   -20.25mA
6.6V      -16.01mA   -10.89mA   -21.23mA
[Ramp]
dV/dt_r   0.406703/1.24081n  0.273608/2.12545n  0.546889/0.82169n
dV/dt_f   0.355012/1.91414n  0.230671/2.85675n  0.495125/1.33764n
R_load = 50
[Falling Waveform]
R_fixture = 50
V_fixture = 3.3
V_fixture_min = 2.92
V_fixture_max = 3.63
| Time   V(typ)   V(min)   V(max)
0s        3.3V       2.92V      3.63V
471.6ps   3.299V     2.92V      3.654V
631.7ps   3.325V     2.92V      3.503V
760ps     3.259V     2.928V     3.415V
919.5ps   3.179V     2.938V     3.338V
1.374ns   3.074V     2.831V     3.144V
2.387ns   2.881V     2.74V      2.91V
3.989ns   2.751V     2.621V     2.821V
6.037ns   2.713V     2.56V      2.804V
800ns     2.708V     2.536V     2.805V
[Falling Waveform]
R_fixture = 50
V_fixture = 0
V_fixture_min = 0
V_fixture_max = 0
| Time   V(typ)   V(min)   V(max)
0s        677.8mV    456mV      911.5mV
374.8ps   677.8mV    455.9mV    900.6mV
482.6ps   678.6mV    455.9mV    253.2mV
529.2ps   619.9mV    456mV      121.6mV
586ps     325.4mV    456.1mV    51mV
649.8ps   121.6mV    456.1mV    20.84mV
754.8ps   28.3mV     439.7mV    6.227mV
941ps     3.805mV    48.71mV    2.019mV
1.402ns   1.208mV    814uV      1.083mV
800ns     20.73nV    618.4nV    12.32nV
[Rising Waveform]
R_fixture = 50
V_fixture = 3.3
V_fixture_min = 2.92
V_fixture_max = 3.63
| Time   V(typ)   V(min)   V(max)
0s        2.708V     2.536V     2.805V
480.4ps   2.708V     2.536V     2.816V
529.5ps   2.708V     2.536V     2.936V
636.3ps   2.72V      2.536V     3.453V
691.6ps   2.816V     2.536V     3.55V
765.4ps   3.071V     2.536V     3.598V
877.2ps   3.255V     2.541V     3.618V
1.179ns   3.294V     2.899V     3.627V
2.194ns   3.299V     2.919V     3.629V
800ns     3.3V       2.92V      3.63V
[Rising Waveform]
R_fixture = 50
V_fixture = 0
V_fixture_min = 0
V_fixture_max = 0
| Time   V(typ)   V(min)   V(max)
0s        20.92nV    617.8nV    12.65nV
707ps     -4.872mV   34.64uV    -7.334mV
951.3ps   -41.24uV   -2.459mV   271.9mV
1.316ns   221.2mV    -2.061mV   542.3mV
1.647ns   338.1mV    90.21mV    713.9mV
1.943ns   432.2mV    150.5mV    800.5mV
2.878ns   610.8mV    268.9mV    887.2mV
4.539ns   668.3mV    410.6mV    912.2mV
12.65ns   678.2mV    456mV      911.4mV
800ns     677.8mV    456mV      911.5mV
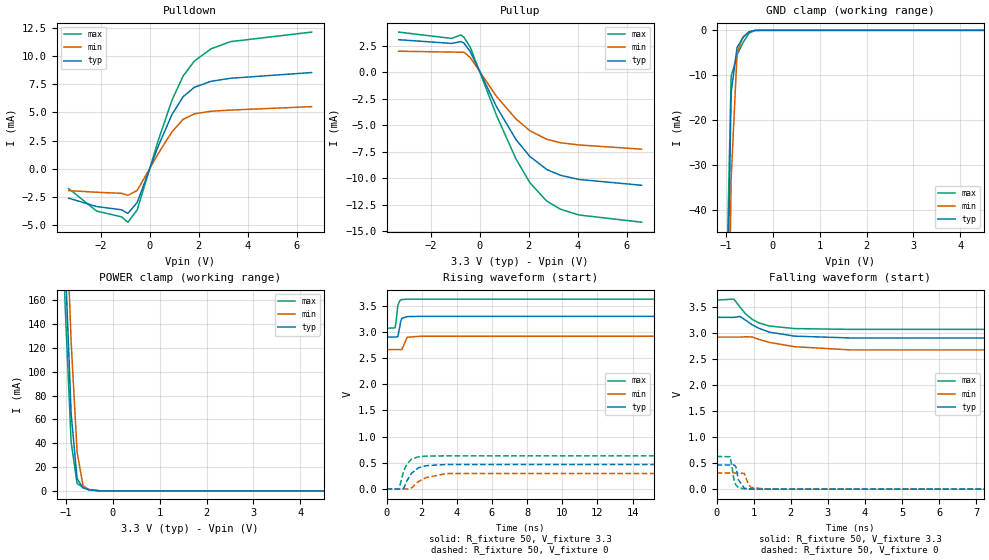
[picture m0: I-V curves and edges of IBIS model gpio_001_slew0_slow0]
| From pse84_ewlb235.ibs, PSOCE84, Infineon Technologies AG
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[Model] gpio_001_slew0_slow0
Model_type I/O
Enable   Active-High
Vinl  =  0.99
Vinh  =  2.31
Vmeas =  1.65
Cref  =  15e-12
| Capacitance   typ   min   max
C_comp   1.09946e-12   1.086232e-12   1.114407e-12
| Variables   typ   min   max
[GND Clamp Reference]   0   0   0
[POWER Clamp Reference]   3.3   2.92   3.63
[Pulldown Reference]   0   0   0
[Pullup Reference]   3.3   2.92   3.63
[Temperature Range]   25   125   -40
[Voltage Range]   3.3   2.92   3.63
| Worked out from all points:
|   slope of the pulldown table from 0 to 0.495 V, typ, clamps not added: 178 ohm
|   slope of the pullup table from 0 to 0.495 V, typ, clamps not added: 208 ohm
|   GND clamp passes 1 mA (typ) near -0.57 V on its own axis
|   POWER clamp passes 1 mA (typ) near -0.52 V on its own axis
|   falling waveform, R_fixture 50, V_fixture 3.3: 20-80 % time 810ps typ, 1.22ns min, 574ps max; typ from 3.3 V to 2.9 V
|   falling waveform, R_fixture 50, V_fixture 0: 20-80 % time 92.7ps typ, 99.9ps min, 88.6ps max; typ from 0.465 V to 0 V
|   rising waveform, R_fixture 50, V_fixture 3.3: 20-80 % time 118ps typ, 141ps min, 107ps max; typ from 2.9 V to 3.3 V
|   rising waveform, R_fixture 50, V_fixture 0: 20-80 % time 582ps typ, 1.02ns min, 399ps max; typ from 0 V to 0.465 V
[GND Clamp]
| Voltage   I(typ)   I(min)   I(max)
-1.65V    -892.5mA   -911.9mA   -883.9mA
-1.015V   -92.32mA   -129.7mA   -71.28mA
-888.3mV  -13.83mA   -33.21mA   -10.31mA
-761.4mV  -3.792mA   -4.944mA   -5.509mA
-634.5mV  -1.622mA   -1.436mA   -2.707mA
-507.6mV  -326.2uA   -352.3uA   -651.6uA
-380.7mV  -13.48uA   -32.14uA   -19.55uA
-253.8mV  -189.4nA   -1.276uA   -466.7nA
6.6V      0A         0A         0A
[POWER Clamp]
| Voltage   I(typ)   I(min)   I(max)
-1.523V   838.1mA    872.9mA    823.9mA
-1.142V   346.5mA    405.1mA    310.5mA
-1.015V   193mA      257.4mA    153.9mA
-888.3mV  64.97mA    124.9mA    40.96mA
-761.4mV  10.28mA    32.7mA     6.184mA
-634.5mV  2.553mA    4.346mA    3.067mA
-507.6mV  805.9uA    960.7uA    1.159mA
-253.8mV  1.454uA    10.02uA    1.678uA
6.6V      0A         0A         0A
[Pulldown]
| Voltage   I(typ)   I(min)   I(max)
-3.3V     -2.643mA   -1.966mA   -1.791mA
-2.157V   -3.39mA    -2.115mA   -3.795mA
-1.142V   -3.679mA   -2.212mA   -4.311mA
-888.3mV  -4.009mA   -2.389mA   -4.785mA
-507.6mV  -3.025mA   -1.958mA   -3.699mA
341.4mV   1.951mA    1.307mA    2.447mA
910.3mV   4.825mA    3.28mA     6.103mA
1.366V    6.41mA     4.394mA    8.255mA
1.821V    7.242mA    4.88mA     9.591mA
2.503V    7.783mA    5.111mA    10.68mA
3.3V      8.051mA    5.214mA    11.32mA
6.6V      8.562mA    5.52mA     12.17mA
[Pullup]
| Voltage   I(typ)   I(min)   I(max)
-3.3V     3.087mA    1.997mA    3.806mA
-1.142V   2.734mA    1.918mA    3.207mA
-761.4mV  2.909mA    1.902mA    3.539mA
-634.5mV  2.75mA     1.893mA    3.303mA
-380.7mV  1.949mA    1.391mA    2.365mA
682.8mV   -3.231mA   -2.262mA   -4.048mA
1.479V    -6.353mA   -4.405mA   -8.186mA
2.048V    -7.961mA   -5.522mA   -10.44mA
2.731V    -9.182mA   -6.325mA   -12.17mA
3.3V      -9.741mA   -6.66mA    -12.95mA
4.051V    -10.13mA   -6.866mA   -13.49mA
6.6V      -10.68mA   -7.265mA   -14.17mA
[Ramp]
dV/dt_r   0.279256/0.582011n  0.186638/1.0197n  0.377848/0.399053n
dV/dt_f   0.238266/0.809562n  0.154161/1.22353n  0.33546/0.573621n
R_load = 50
[Falling Waveform]
R_fixture = 50
V_fixture = 3.3
V_fixture_min = 2.92
V_fixture_max = 3.63
| Time   V(typ)   V(min)   V(max)
0s        3.3V       2.92V      3.63V
467ps     3.299V     2.92V      3.651V
637.4ps   3.317V     2.92V      3.492V
768ps     3.252V     2.927V     3.378V
959.5ps   3.158V     2.923V     3.261V
1.138ns   3.091V     2.877V     3.194V
1.423ns   3.016V     2.819V     3.134V
2.102ns   2.939V     2.736V     3.084V
3.6ns     2.904V     2.675V     3.069V
800ns     2.903V     2.663V     3.071V
[Falling Waveform]
R_fixture = 50
V_fixture = 0
V_fixture_min = 0
V_fixture_max = 0
| Time   V(typ)   V(min)   V(max)
0s        465.4mV    311.1mV    629.7mV
370.2ps   465.3mV    310.9mV    623.2mV
470.2ps   465.7mV    310.9mV    179.6mV
521.6ps   429.4mV    311.1mV    81.49mV
589.1ps   179.8mV    311.1mV    30.23mV
750.1ps   19.19mV    300.1mV    4.229mV
858.3ps   5.822mV    91.45mV    1.691mV
930.7ps   3.076mV    33.19mV    1.273mV
1.321ns   763.8uV    1.018mV    658.1uV
800ns     23.16nV    669.1nV    14.09nV
[Rising Waveform]
R_fixture = 50
V_fixture = 3.3
V_fixture_min = 2.92
V_fixture_max = 3.63
| Time   V(typ)   V(min)   V(max)
0s        2.903V     2.663V     3.071V
482ps     2.903V     2.663V     3.079V
539.6ps   2.903V     2.663V     3.176V
642.9ps   2.912V     2.663V     3.508V
762ps     3.113V     2.663V     3.602V
810.4ps   3.209V     2.662V     3.613V
873.9ps   3.262V     2.665V     3.62V
1.175ns   3.295V     2.901V     3.628V
1.901ns   3.299V     2.918V     3.629V
800ns     3.3V       2.92V      3.63V
[Rising Waveform]
R_fixture = 50
V_fixture = 0
V_fixture_min = 0
V_fixture_max = 0
| Time   V(typ)   V(min)   V(max)
0s        23.31nV    668.5nV    14.36nV
708.8ps   -2.887mV   35.19uV    -5.627mV
920.8ps   -6.313mV   -923.4uV   270.7mV
1.013ns   33.73mV    -2.161mV   369.7mV
1.172ns   161.6mV    -4.254mV   482.3mV
1.434ns   300.8mV    20.75mV    572.2mV
1.822ns   402.6mV    141.9mV    612.4mV
2.254ns   443.3mV    214.7mV    625.9mV
3.408ns   465.4mV    293.5mV    630.6mV
800ns     465.4mV    311.1mV    629.7mV
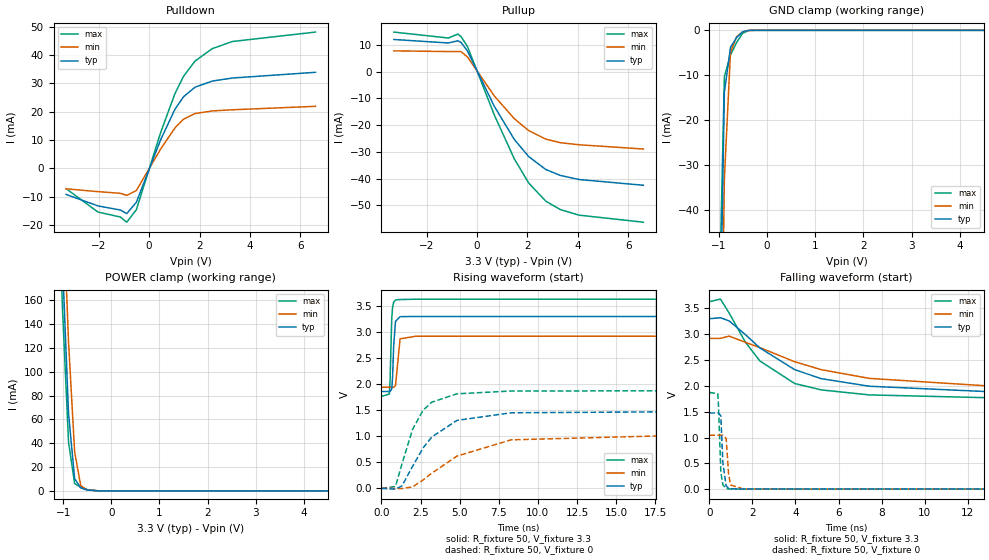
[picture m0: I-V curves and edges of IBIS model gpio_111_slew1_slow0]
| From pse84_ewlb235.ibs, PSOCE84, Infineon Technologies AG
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[Model] gpio_111_slew1_slow0
Model_type I/O
Enable   Active-High
Vinl  =  0.99
Vinh  =  2.31
Vmeas =  1.65
Cref  =  15e-12
| Capacitance   typ   min   max
C_comp   1.09946e-12   1.086232e-12   1.114407e-12
| Variables   typ   min   max
[GND Clamp Reference]   0   0   0
[POWER Clamp Reference]   3.3   2.92   3.63
[Pulldown Reference]   0   0   0
[Pullup Reference]   3.3   2.92   3.63
[Temperature Range]   25   125   -40
[Voltage Range]   3.3   2.92   3.63
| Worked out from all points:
|   slope of the pulldown table from 0 to 0.495 V, typ, clamps not added: 45.2 ohm
|   slope of the pullup table from 0 to 0.495 V, typ, clamps not added: 52.1 ohm
|   GND clamp passes 1 mA (typ) near -0.57 V on its own axis
|   POWER clamp passes 1 mA (typ) near -0.52 V on its own axis
|   falling waveform, R_fixture 50, V_fixture 3.3: 20-80 % time 3.51ns typ, 5.18ns min, 2.35ns max; typ from 3.3 V to 1.86 V
|   falling waveform, R_fixture 50, V_fixture 0: 20-80 % time 96.2ps typ, 105ps min, 91.5ps max; typ from 1.48 V to 0 V
|   rising waveform, R_fixture 50, V_fixture 3.3: 20-80 % time 113ps typ, 133ps min, 100ps max; typ from 1.86 V to 3.3 V
|   rising waveform, R_fixture 50, V_fixture 0: 20-80 % time 2.2ns typ, 3.79ns min, 1.42ns max; typ from 0 V to 1.48 V
[GND Clamp]
| Voltage   I(typ)   I(min)   I(max)
-1.65V    -892.5mA   -911.9mA   -883.9mA
-1.015V   -92.32mA   -129.7mA   -71.28mA
-888.3mV  -13.83mA   -33.21mA   -10.31mA
-761.4mV  -3.792mA   -4.944mA   -5.509mA
-634.5mV  -1.622mA   -1.436mA   -2.707mA
-507.6mV  -326.2uA   -352.3uA   -651.6uA
-380.7mV  -13.48uA   -32.14uA   -19.55uA
-253.8mV  -189.4nA   -1.276uA   -466.7nA
6.6V      0A         0A         0A
[POWER Clamp]
| Voltage   I(typ)   I(min)   I(max)
-1.523V   838.1mA    872.9mA    823.9mA
-1.142V   346.5mA    405.1mA    310.5mA
-1.015V   193mA      257.4mA    153.9mA
-888.3mV  64.97mA    124.9mA    40.96mA
-761.4mV  10.28mA    32.7mA     6.184mA
-634.5mV  2.553mA    4.346mA    3.067mA
-507.6mV  805.9uA    960.7uA    1.159mA
-253.8mV  1.454uA    10.02uA    1.678uA
6.6V      0A         0A         0A
[Pulldown]
| Voltage   I(typ)   I(min)   I(max)
-3.3V     -9.135mA   -7.165mA   -7.087mA
-2.03V    -13.19mA   -8.156mA   -15.36mA
-1.142V   -14.64mA   -8.741mA   -17.11mA
-888.3mV  -15.9mA    -9.492mA   -18.93mA
-507.6mV  -11.91mA   -7.752mA   -14.53mA
455.2mV   10.12mA    6.826mA    12.65mA
1.024V    20.87mA    14.31mA    26.39mA
1.366V    25.31mA    17.41mA    32.51mA
1.821V    28.66mA    19.37mA    37.87mA
2.503V    30.82mA    20.29mA    42.24mA
3.3V      31.89mA    20.7mA     44.77mA
6.6V      33.91mA    21.92mA    48.09mA
[Pullup]
| Voltage   I(typ)   I(min)   I(max)
-3.3V     12.1mA     7.839mA    14.87mA
-1.142V   10.79mA    7.584mA    12.65mA
-761.4mV  11.61mA    7.576mA    14.12mA
-634.5mV  10.98mA    7.558mA    13.18mA
-380.7mV  7.78mA     5.554mA    9.437mA
682.8mV   -12.9mA    -9.034mA   -16.15mA
1.479V    -25.35mA   -17.59mA   -32.65mA
2.048V    -31.76mA   -22.04mA   -41.65mA
2.731V    -36.61mA   -25.23mA   -48.5mA
3.3V      -38.82mA   -26.56mA   -51.59mA
4.051V    -40.36mA   -27.34mA   -53.71mA
6.6V      -42.5mA    -28.93mA   -56.34mA
[Ramp]
dV/dt_r   0.885184/2.20375n  0.626209/3.78727n  1.12293/1.42492n
dV/dt_f   0.865169/3.51065n  0.588646/5.18048n  1.12009/2.34643n
R_load = 50
[Falling Waveform]
R_fixture = 50
V_fixture = 3.3
V_fixture_min = 2.92
V_fixture_max = 3.63
| Time   V(typ)   V(min)   V(max)
0s        3.3V       2.92V      3.63V
516.2ps   3.32V      2.92V      3.681V
920.7ps   3.257V     2.963V     3.409V
1.671ns   2.994V     2.844V     2.848V
2.345ns   2.735V     2.741V     2.483V
3.962ns   2.314V     2.468V     2.046V
5.195ns   2.14V      2.314V     1.922V
7.433ns   1.993V     2.145V     1.825V
13.21ns   1.883V     1.992V     1.768V
800ns     1.858V     1.939V     1.763V
[Falling Waveform]
R_fixture = 50
V_fixture = 0
V_fixture_min = 0
V_fixture_max = 0
| Time   V(typ)   V(min)   V(max)
0s        1.475V     1.044V     1.872V
388.5ps   1.475V     1.044V     1.85V
419.1ps   1.475V     1.044V     1.664V
533.4ps   1.417V     1.044V     324.7mV
626.8ps   517.3mV    1.044V     85.27mV
779.3ps   59.81mV    986.3mV    11.67mV
894ps     15.32mV    291.1mV    5.5mV
983.2ps   5.559mV    81.52mV    4.486mV
1.593ns   2.713mV    1.519mV    2.658mV
800ns     13.72nV    450.7nV    7.717nV
[Rising Waveform]
R_fixture = 50
V_fixture = 3.3
V_fixture_min = 2.92
V_fixture_max = 3.63
| Time   V(typ)   V(min)   V(max)
0s        1.858V     1.939V     1.763V
500.8ps   1.858V     1.939V     1.808V
550.5ps   1.858V     1.939V     2.061V
657.7ps   1.907V     1.939V     3.253V
712.1ps   2.133V     1.939V     3.467V
781.1ps   2.732V     1.939V     3.569V
898ps     3.201V     1.969V     3.612V
1.191ns   3.293V     2.867V     3.621V
2.192ns   3.296V     2.917V     3.627V
800ns     3.3V       2.92V      3.63V
[Rising Waveform]
R_fixture = 50
V_fixture = 0
V_fixture_min = 0
V_fixture_max = 0
| Time   V(typ)   V(min)   V(max)
0s        13.96nV    450.4nV    8.038nV
898.2ps   -15.51mV   -2.925mV   35.64mV
1.306ns   45.3mV     -4.131mV   462.4mV
1.987ns   420.7mV    28.77mV    1.13V
2.657ns   773.2mV    158.1mV    1.497V
3.213ns   983.7mV    291.5mV    1.652V
4.83ns    1.304V     619.1mV    1.813V
8.283ns   1.449V     930.2mV    1.867V
22.71ns   1.476V     1.045V     1.872V
800ns     1.475V     1.044V     1.872V
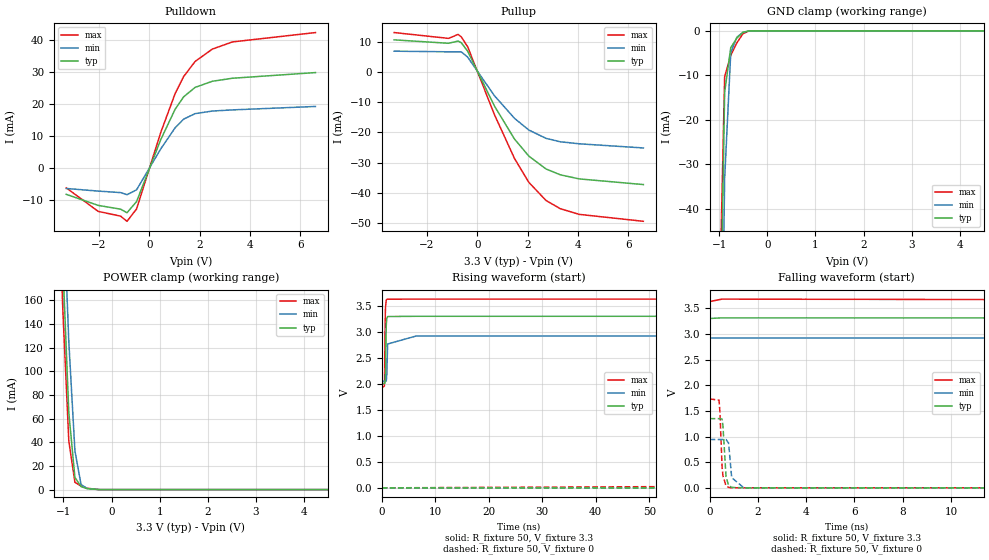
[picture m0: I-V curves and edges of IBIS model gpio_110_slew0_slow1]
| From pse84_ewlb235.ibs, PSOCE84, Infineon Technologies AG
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[Model] gpio_110_slew0_slow1
Model_type I/O
Enable   Active-High
Vinl  =  0.99
Vinh  =  2.31
Vmeas =  1.65
Cref  =  15e-12
| Capacitance   typ   min   max
C_comp   1.09946e-12   1.08623e-12   1.11440e-12
| Variables   typ   min   max
[GND Clamp Reference]   0   0   0
[POWER Clamp Reference]   3.3   2.92   3.63
[Pulldown Reference]   0   0   0
[Pullup Reference]   3.3   2.92   3.63
[Temperature Range]   25   125   -40
[Voltage Range]   3.3   2.92   3.63
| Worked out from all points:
|   slope of the pulldown table from 0 to 0.495 V, typ, clamps not added: 51.4 ohm
|   slope of the pullup table from 0 to 0.495 V, typ, clamps not added: 59.6 ohm
|   GND clamp passes 1 mA (typ) near -0.57 V on its own axis
|   POWER clamp passes 1 mA (typ) near -0.52 V on its own axis
|   falling waveform, R_fixture 50, V_fixture 3.3: 20-80 % time 654ns typ, 981ns min, 355ns max; typ from 3.3 V to 2.01 V
|   falling waveform, R_fixture 50, V_fixture 0: 20-80 % time 97ps typ, 106ps min, 92.2ps max; typ from 1.35 V to 0 V
|   rising waveform, R_fixture 50, V_fixture 3.3: 20-80 % time 114ps typ, 134ps min, 102ps max; typ from 2.01 V to 3.3 V
|   rising waveform, R_fixture 50, V_fixture 0: 20-80 % time 659ns typ, 959ns min, 407ns max; typ from 0 V to 1.34 V
[GND Clamp]
| Voltage   I(typ)   I(min)   I(max)
-1.65V    -892.5mA   -911.9mA   -883.9mA
-1.015V   -92.32mA   -129.7mA   -71.28mA
-888.3mV  -13.83mA   -33.21mA   -10.31mA
-761.4mV  -3.792mA   -4.944mA   -5.509mA
-634.5mV  -1.622mA   -1.436mA   -2.707mA
-507.6mV  -326.2uA   -352.3uA   -651.6uA
-380.7mV  -13.48uA   -32.14uA   -19.55uA
-253.8mV  -189.4nA   -1.276uA   -466.7nA
6.6V      0A         0A         0A
[POWER Clamp]
| Voltage   I(typ)   I(min)   I(max)
-1.523V   838.1mA    872.9mA    823.9mA
-1.142V   346.5mA    405.1mA    310.5mA
-1.015V   193mA      257.4mA    153.9mA
-888.3mV  64.97mA    124.9mA    40.96mA
-761.4mV  10.28mA    32.7mA     6.184mA
-634.5mV  2.553mA    4.346mA    3.067mA
-507.6mV  805.9uA    960.7uA    1.159mA
-253.8mV  1.454uA    10.02uA    1.678uA
6.6V      0A         0A         0A
[Pulldown]
| Voltage   I(typ)   I(min)   I(max)
-3.3V     -8.212mA   -6.385mA   -6.208mA
-2.03V    -11.66mA   -7.198mA   -13.53mA
-1.142V   -12.83mA   -7.669mA   -15.01mA
-888.3mV  -13.95mA   -8.319mA   -16.62mA
-507.6mV  -10.46mA   -6.799mA   -12.77mA
455.2mV   8.891mA    5.988mA    11.13mA
1.024V    18.33mA    12.54mA    23.2mA
1.366V    22.23mA    15.26mA    28.56mA
1.821V    25.16mA    16.97mA    33.26mA
2.503V    27.06mA    17.77mA    37.09mA
3.3V      28mA       18.13mA    39.33mA
6.6V      29.77mA    19.2mA     42.25mA
[Pullup]
| Voltage   I(typ)   I(min)   I(max)
-3.3V     10.56mA    6.824mA    12.97mA
-1.142V   9.434mA    6.617mA    11.05mA
-761.4mV  10.16mA    6.619mA    12.36mA
-634.5mV  9.61mA     6.607mA    11.54mA
-380.7mV  6.811mA    4.857mA    8.263mA
682.8mV   -11.29mA   -7.892mA   -14.14mA
1.479V    -22.19mA   -15.35mA   -28.59mA
2.048V    -27.81mA   -19.21mA   -36.47mA
2.731V    -32.06mA   -21.96mA   -42.48mA
3.3V      -34mA      -23.09mA   -45.19mA
4.051V    -35.35mA   -23.76mA   -47.06mA
6.6V      -37.22mA   -25.13mA   -49.35mA
[Ramp]
dV/dt_r   0.806896/0.659215u  0.556925/0.958752u  1.03904/0.407092u
dV/dt_f   0.774754/0.653611u  0.51486/0.981205u  1.02149/0.354686u
R_load = 50
[Falling Waveform]
R_fixture = 50
V_fixture = 3.3
V_fixture_min = 2.92
V_fixture_max = 3.63
| Time   V(typ)   V(min)   V(max)
0s        3.3V       2.92V      3.63V
507.9ps   3.312V     2.92V      3.677V
123.6ns   3.3V       2.92V      3.587V
288.7ns   3.183V     2.917V     2.872V
451.6ns   2.867V     2.85V      2.416V
614.5ns   2.609V     2.716V     2.199V
818.1ns   2.395V     2.556V     2.073V
1.223us   2.183V     2.337V     1.975V
1.836us   2.069V     2.179V     1.937V
4us       2.009V     2.062V     1.928V
[Falling Waveform]
R_fixture = 50
V_fixture = 0
V_fixture_min = 0
V_fixture_max = 0
| Time   V(typ)   V(min)   V(max)
0s        1.349V     941.3mV    1.732V
388.4ps   1.349V     941.1mV    1.709V
425ps     1.349V     941.1mV    1.481V
514.8ps   1.339V     941.3mV    410mV
552ps     1.201V     941.3mV    232.2mV
678.6ps   215.9mV    941.9mV    39.71mV
784.6ps   50.15mV    873mV      8.886mV
913.5ps   9.121mV    198.6mV    476.7uV
1.42ns    666.8uV    -156.4uV   1.41mV
4us       17.3nV     488.5nV    8.401nV
[Rising Waveform]
R_fixture = 50
V_fixture = 3.3
V_fixture_min = 2.92
V_fixture_max = 3.63
| Time   V(typ)   V(min)   V(max)
0s        2.007V     2.052V     1.927V
487.2ps   2.007V     2.052V     1.955V
534.8ps   2.007V     2.052V     2.138V
625.7ps   2.018V     2.052V     3.104V
695.2ps   2.202V     2.052V     3.456V
845.4ps   3.124V     2.054V     3.612V
940.6ps   3.258V     2.171V     3.626V
1.102ns   3.295V     2.767V     3.629V
6.403ns   3.3V       2.92V      3.63V
4us       3.3V       2.92V      3.63V
[Rising Waveform]
R_fixture = 50
V_fixture = 0
V_fixture_min = 0
V_fixture_max = 0
| Time   V(typ)   V(min)   V(max)
0s        14.93nV    475.9nV    8.654nV
132.2ns   588.3uV    71.15uV    59.55mV
240ns     55.32mV    2.727mV    429.3mV
357.9ns   235.2mV    33.74mV    848.7mV
520.8ns   522.6mV    138mV      1.241V
683.7ns   765.1mV    269.4mV    1.443V
887.3ns   976.5mV    426.8mV    1.567V
1.277us   1.174V     650.2mV    1.667V
1.871us   1.28V      813.9mV    1.713V
4us       1.345V     928.2mV    1.732V
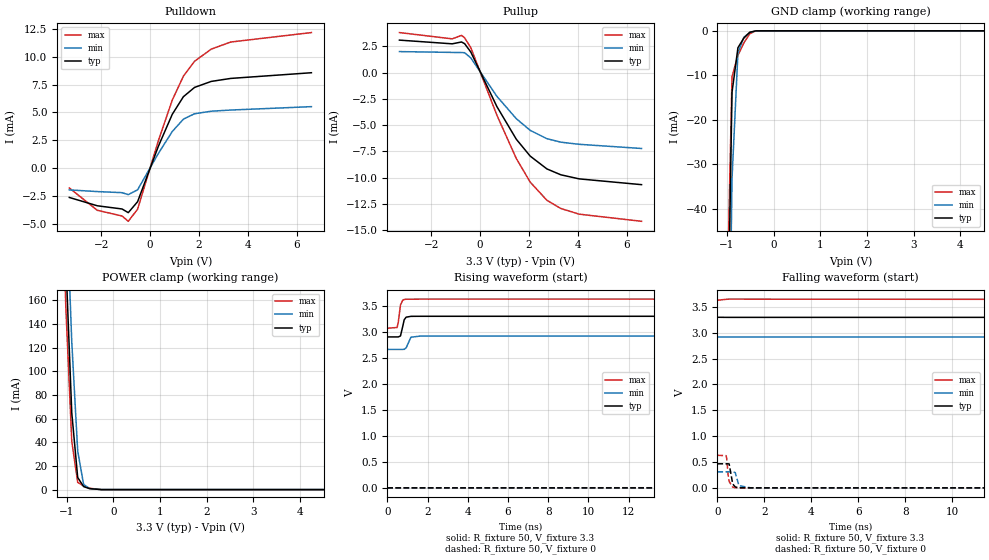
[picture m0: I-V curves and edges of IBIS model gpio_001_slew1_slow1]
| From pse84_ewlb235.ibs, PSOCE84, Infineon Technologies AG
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[Model] gpio_001_slew1_slow1
Model_type I/O
Enable   Active-High
Vinl  =  0.99
Vinh  =  2.31
Vmeas =  1.65
Cref  =  15e-12
| Capacitance   typ   min   max
C_comp   1.09946e-12   1.08623e-12   1.11440e-12
| Variables   typ   min   max
[GND Clamp Reference]   0   0   0
[POWER Clamp Reference]   3.3   2.92   3.63
[Pulldown Reference]   0   0   0
[Pullup Reference]   3.3   2.92   3.63
[Temperature Range]   25   125   -40
[Voltage Range]   3.3   2.92   3.63
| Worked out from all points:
|   slope of the pulldown table from 0 to 0.495 V, typ, clamps not added: 178 ohm
|   slope of the pullup table from 0 to 0.495 V, typ, clamps not added: 208 ohm
|   GND clamp passes 1 mA (typ) near -0.57 V on its own axis
|   POWER clamp passes 1 mA (typ) near -0.52 V on its own axis
|   falling waveform, R_fixture 50, V_fixture 3.3: 20-80 % time 552ns typ, 850ns min, 308ns max; typ from 3.3 V to 2.9 V
|   falling waveform, R_fixture 50, V_fixture 0: 20-80 % time 93.1ps typ, 101ps min, 89.3ps max; typ from 0.465 V to 0 V
|   rising waveform, R_fixture 50, V_fixture 3.3: 20-80 % time 124ps typ, 150ps min, 111ps max; typ from 2.9 V to 3.3 V
|   rising waveform, R_fixture 50, V_fixture 0: 20-80 % time 551ns typ, 839ns min, 329ns max; typ from 0 V to 0.465 V
[GND Clamp]
| Voltage   I(typ)   I(min)   I(max)
-1.65V    -892.5mA   -911.9mA   -883.9mA
-1.015V   -92.32mA   -129.7mA   -71.28mA
-888.3mV  -13.83mA   -33.21mA   -10.31mA
-761.4mV  -3.792mA   -4.944mA   -5.509mA
-634.5mV  -1.622mA   -1.436mA   -2.707mA
-507.6mV  -326.2uA   -352.3uA   -651.6uA
-380.7mV  -13.48uA   -32.14uA   -19.55uA
-253.8mV  -189.4nA   -1.276uA   -466.7nA
6.6V      0A         0A         0A
[POWER Clamp]
| Voltage   I(typ)   I(min)   I(max)
-1.523V   838.1mA    872.9mA    823.9mA
-1.142V   346.5mA    405.1mA    310.5mA
-1.015V   193mA      257.4mA    153.9mA
-888.3mV  64.97mA    124.9mA    40.96mA
-761.4mV  10.28mA    32.7mA     6.184mA
-634.5mV  2.553mA    4.346mA    3.067mA
-507.6mV  805.9uA    960.7uA    1.159mA
-253.8mV  1.454uA    10.02uA    1.678uA
6.6V      0A         0A         0A
[Pulldown]
| Voltage   I(typ)   I(min)   I(max)
-3.3V     -2.643mA   -1.964mA   -1.791mA
-2.157V   -3.39mA    -2.114mA   -3.795mA
-1.142V   -3.679mA   -2.212mA   -4.31mA
-888.3mV  -4.009mA   -2.389mA   -4.785mA
-507.6mV  -3.025mA   -1.958mA   -3.699mA
341.4mV   1.951mA    1.306mA    2.447mA
910.3mV   4.825mA    3.279mA    6.103mA
1.366V    6.409mA    4.391mA    8.255mA
1.821V    7.242mA    4.876mA    9.591mA
2.503V    7.782mA    5.106mA    10.68mA
3.3V      8.05mA     5.209mA    11.32mA
6.6V      8.562mA    5.515mA    12.17mA
[Pullup]
| Voltage   I(typ)   I(min)   I(max)
-3.3V     3.087mA    1.995mA    3.806mA
-1.142V   2.733mA    1.916mA    3.207mA
-761.4mV  2.909mA    1.901mA    3.539mA
-634.5mV  2.75mA     1.891mA    3.303mA
-380.7mV  1.949mA    1.39mA     2.365mA
682.8mV   -3.231mA   -2.26mA    -4.048mA
1.479V    -6.353mA   -4.397mA   -8.186mA
2.048V    -7.961mA   -5.509mA   -10.44mA
2.731V    -9.181mA   -6.303mA   -12.17mA
3.3V      -9.741mA   -6.634mA   -12.95mA
4.051V    -10.13mA   -6.837mA   -13.49mA
6.6V      -10.68mA   -7.234mA   -14.17mA
[Ramp]
dV/dt_r   0.279195/0.551053u  0.185497/0.838933u  0.377845/0.328949u
dV/dt_f   0.238231/0.551599u  0.153561/0.850339u  0.33545/0.308461u
R_load = 50
[Falling Waveform]
R_fixture = 50
V_fixture = 3.3
V_fixture_min = 2.92
V_fixture_max = 3.63
| Time   V(typ)   V(min)   V(max)
0s        3.3V       2.92V      3.63V
468.7ps   3.298V     2.92V      3.651V
112.2ns   3.3V       2.92V      3.613V
274ns     3.251V     2.919V     3.348V
396.2ns   3.165V     2.902V     3.23V
559.1ns   3.076V     2.856V     3.149V
762.7ns   3.006V     2.803V     3.104V
1.172us   2.94V      2.735V     3.077V
1.788us   2.911V     2.689V     3.071V
4us       2.903V     2.664V     3.071V
[Falling Waveform]
R_fixture = 50
V_fixture = 0
V_fixture_min = 0
V_fixture_max = 0
| Time   V(typ)   V(min)   V(max)
0s        465.4mV    310.1mV    629.7mV
372.2ps   465.3mV    310mV      622.6mV
397.4ps   465.4mV    309.9mV    555.3mV
457ps     465.4mV    309.9mV    237.4mV
498.4ps   462.7mV    310mV      123.2mV
650.3ps   75.4mV     310.2mV    15.42mV
757.5ps   18.03mV    294.9mV    2.89mV
914.9ps   2.175mV    43.27mV    143.7uV
1.417ns   216.6uV    2.841uV    490.6uV
4us       23.33nV    671.1nV    14.09nV
[Rising Waveform]
R_fixture = 50
V_fixture = 3.3
V_fixture_min = 2.92
V_fixture_max = 3.63
| Time   V(typ)   V(min)   V(max)
0s        2.903V     2.663V     3.071V
486.4ps   2.903V     2.663V     3.084V
543.7ps   2.903V     2.663V     3.182V
654.6ps   2.922V     2.663V     3.517V
762.5ps   3.098V     2.663V     3.607V
839.1ps   3.233V     2.664V     3.622V
936.5ps   3.283V     2.693V     3.628V
1.174ns   3.299V     2.898V     3.629V
1.656ns   3.3V       2.92V      3.63V
4us       3.3V       2.92V      3.63V
[Rising Waveform]
R_fixture = 50
V_fixture = 0
V_fixture_min = 0
V_fixture_max = 0
| Time   V(typ)   V(min)   V(max)
0s        23.31nV    668.5nV    14.36nV
112.1ns   105.3uV    59.39uV    22.41mV
202.8ns   18.19mV    587.4uV    169.1mV
310.7ns   89.56mV    11.5mV     334.9mV
432.1ns   178.7mV    41.93mV    456.2mV
595ns     275.7mV    93.12mV    542.4mV
798.6ns   354.3mV    152.2mV    589.8mV
1.172us   422.1mV    226.7mV    619.1mV
1.792us   455.1mV    281.1mV    628.5mV
4us       465.3mV    309.2mV    629.7mV
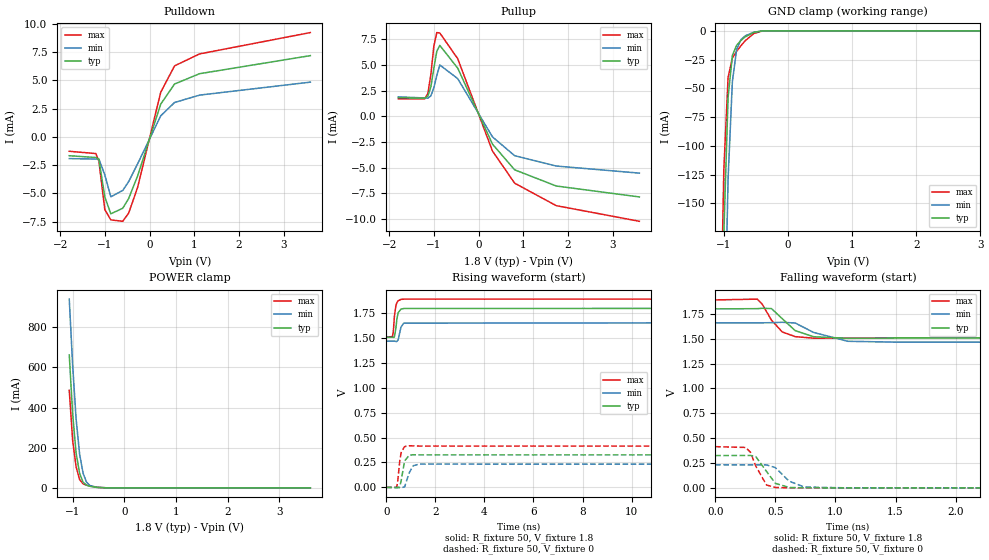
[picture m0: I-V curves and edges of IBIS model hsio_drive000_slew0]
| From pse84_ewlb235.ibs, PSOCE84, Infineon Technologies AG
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[Model] hsio_drive000_slew0
Model_type I/O
Enable   Active-High
Vinl  =  0.54
Vinh  =  1.26
Vmeas =  0.9
Cref  =  15pF
| Capacitance   typ   min   max
C_comp   1.183861e-12   1.145095e-12   1.230403e-12
| Variables   typ   min   max
[GND Clamp Reference]   0   0   0
[POWER Clamp Reference]   1.8   1.66   1.89
[Pulldown Reference]   0   0   0
[Pullup Reference]   1.8   1.66   1.89
[Temperature Range]   25   125   -40
[Voltage Range]   1.8   1.66   1.89
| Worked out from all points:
|   slope of the pulldown table from 0 to 0.27 V, typ, clamps not added: 88.2 ohm
|   slope of the pullup table from 0 to 0.27 V, typ, clamps not added: 113 ohm
|   GND clamp passes 1 mA (typ) near -0.51 V on its own axis
|   POWER clamp passes 1 mA (typ) near -0.47 V on its own axis
|   falling waveform, R_fixture 50, V_fixture 1.8: 20-80 % time 159ps typ, 203ps min, 132ps max; typ from 1.8 V to 1.51 V
|   falling waveform, R_fixture 50, V_fixture 0: 20-80 % time 96.1ps typ, 117ps min, 81.7ps max; typ from 0.325 V to 0 V
|   rising waveform, R_fixture 50, V_fixture 1.8: 20-80 % time 92.7ps typ, 104ps min, 86.8ps max; typ from 1.51 V to 1.8 V
|   rising waveform, R_fixture 50, V_fixture 0: 20-80 % time 134ps typ, 173ps min, 114ps max; typ from 0 V to 0.325 V
[GND Clamp]
| Voltage   I(typ)   I(min)   I(max)
-1.137V   -688mA     -831.1mA   -596.4mA
-1.07V    -398.5mA   -545.5mA   -312.5mA
-1.003V   -176.8mA   -300mA     -120.9mA
-936.6mV  -57.93mA   -128.6mA   -40.51mA
-869.7mV  -21.44mA   -44.12mA   -23.78mA
-802.8mV  -12.54mA   -16.03mA   -17.79mA
-735.9mV  -8.37mA    -7.69mA    -12.93mA
-669mV    -5.28mA    -4.356mA   -8.606mA
-535.2mV  -1.316mA   -1.208mA   -2.332mA
-401.4mV  -73.56uA   -132.2uA   -119.3uA
3.6V      0A         0A         0A
[POWER Clamp]
| Voltage   I(typ)   I(min)   I(max)
-1.07V    662.2mA    940mA      485.7mA
-1.003V   363.7mA    605.6mA    233mA
-936.6mV  172.7mA    341mA      103.9mA
-869.7mV  72.74mA    168.6mA    41.65mA
-802.8mV  28.31mA    73.56mA    19.99mA
-735.9mV  13.11mA    28.55mA    13.36mA
-669mV    7.76mA     11.5mA     8.963mA
-535.2mV  2.357mA    2.863mA    2.668mA
-334.5mV  34.33uA    127.4uA    15.59uA
3.6V      0A         0A         0A
[Pulldown]
| Voltage   I(typ)   I(min)   I(max)
-1.8V     -1.67mA    -1.924mA   -1.276mA
-1.204V   -1.828mA   -1.961mA   -1.481mA
-1.137V   -1.98mA    -1.96mA    -2.141mA
-1.003V   -5.309mA   -3.368mA   -6.428mA
-869.7mV  -6.803mA   -5.296mA   -7.336mA
-602.1mV  -6.311mA   -4.741mA   -7.463mA
-468.3mV  -5.446mA   -3.95mA    -6.73mA
-267.6mV  -3.441mA   -2.376mA   -4.455mA
248.3mV   2.883mA    1.853mA    3.936mA
558.6mV   4.664mA    3.032mA    6.268mA
1.117V    5.575mA    3.683mA    7.322mA
3.6V      7.173mA    4.831mA    9.21mA
[Pullup]
| Voltage   I(typ)   I(min)   I(max)
-1.8V     1.818mA    1.898mA    1.707mA
-1.204V   1.767mA    1.795mA    1.718mA
-1.137V   1.967mA    1.78mA     2.253mA
-1.07V    2.876mA    2.003mA    4.076mA
-1.003V   4.681mA    2.786mA    6.843mA
-936.6mV  6.347mA    3.994mA    8.16mA
-869.7mV  6.91mA     5.005mA    8.12mA
-468.3mV  4.694mA    3.675mA    5.616mA
310.3mV   -2.703mA   -1.996mA   -3.375mA
806.9mV   -5.199mA   -3.825mA   -6.5mA
1.738V    -6.774mA   -4.831mA   -8.686mA
3.6V      -7.839mA   -5.522mA   -10.21mA
[Ramp]
dV/dt_r   0.194997/0.133563n  0.138952/0.17308n  0.24866/0.113965n
dV/dt_f   0.17476/0.159207n  0.115472/0.203025n  0.228357/0.132179n
R_load = 50
[Falling Waveform]
R_fixture = 50
V_fixture = 1.8
V_fixture_min = 1.66
V_fixture_max = 1.89
| Time   V(typ)   V(min)   V(max)
0s        1.8V       1.66V      1.89V
349.9ps   1.802V     1.66V      1.898V
390.1ps   1.806V     1.66V      1.849V
467.5ps   1.803V     1.661V     1.687V
557.5ps   1.701V     1.665V     1.568V
665.1ps   1.581V     1.658V     1.521V
818.1ps   1.52V      1.563V     1.505V
1.103ns   1.504V     1.474V     1.507V
1.521ns   1.507V     1.465V     1.509V
50ns      1.509V     1.468V     1.509V
[Falling Waveform]
R_fixture = 50
V_fixture = 0
V_fixture_min = 0
V_fixture_max = 0
| Time   V(typ)   V(min)   V(max)
0s        325mV      231.6mV    414.4mV
252.7ps   325.6mV    231.6mV    406.5mV
293.4ps   325.9mV    231.5mV    357.4mV
336.9ps   314.4mV    232mV      219.7mV
426.9ps   164.9mV    230.8mV    27.86mV
500.3ps   45.09mV    203.7mV    4.21mV
614.6ps   4.108mV    67.15mV    87.96uV
741.1ps   298.7uV    8.547mV    -5.464uV
1.096ns   25.15uV    67.64uV    106.7uV
50ns      37.83nV    2.292uV    15.22nV
[Rising Waveform]
R_fixture = 50
V_fixture = 1.8
V_fixture_min = 1.66
V_fixture_max = 1.89
| Time   V(typ)   V(min)   V(max)
0s        1.509V     1.468V     1.509V
256.6ps   1.508V     1.468V     1.514V
290.3ps   1.506V     1.468V     1.566V
332.9ps   1.51V      1.468V     1.715V
394.8ps   1.599V     1.465V     1.826V
436.6ps   1.695V     1.465V     1.856V
488.9ps   1.754V     1.482V     1.874V
600.7ps   1.789V     1.609V     1.887V
713.3ps   1.796V     1.649V     1.89V
50ns      1.8V       1.66V      1.89V
[Rising Waveform]
R_fixture = 50
V_fixture = 0
V_fixture_min = 0
V_fixture_max = 0
| Time   V(typ)   V(min)   V(max)
0s        37.87nV    2.272uV    15.19nV
422.8ps   -4.964mV   62.76uV    653.1uV
463.9ps   -3.169mV   -605.1uV   48mV
551.6ps   5.039mV    -3.515mV   265.1mV
611.7ps   70.13mV    -2.786mV   352.5mV
747.6ps   265mV      3.6mV      409.6mV
939.4ps   323.1mV    147.8mV    417.8mV
1.1ns     327.4mV    217.1mV    416.2mV
1.351ns   326.4mV    233.8mV    414.8mV
50ns      325mV      231.6mV    414.4mV
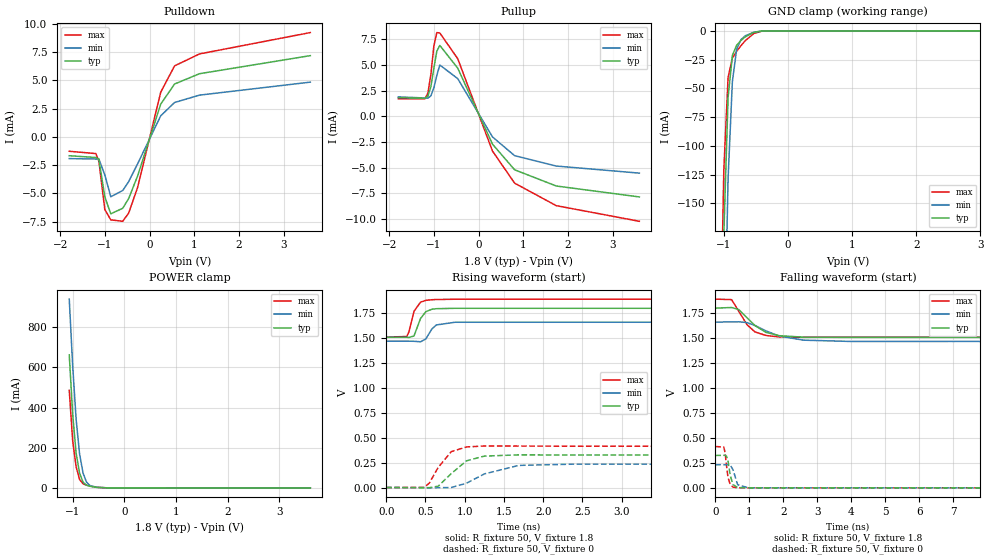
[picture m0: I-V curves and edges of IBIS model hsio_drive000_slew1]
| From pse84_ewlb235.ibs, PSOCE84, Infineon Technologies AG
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[Model] hsio_drive000_slew1
Model_type I/O
Enable   Active-High
Vinl  =  0.54
Vinh  =  1.26
Vmeas =  0.9
Cref  =  15pF
| Capacitance   typ   min   max
C_comp   1.183861e-12   1.145095e-12   1.230403e-12
| Variables   typ   min   max
[GND Clamp Reference]   0   0   0
[POWER Clamp Reference]   1.8   1.66   1.89
[Pulldown Reference]   0   0   0
[Pullup Reference]   1.8   1.66   1.89
[Temperature Range]   25   125   -40
[Voltage Range]   1.8   1.66   1.89
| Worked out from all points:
|   slope of the pulldown table from 0 to 0.27 V, typ, clamps not added: 88.2 ohm
|   slope of the pullup table from 0 to 0.27 V, typ, clamps not added: 113 ohm
|   GND clamp passes 1 mA (typ) near -0.51 V on its own axis
|   POWER clamp passes 1 mA (typ) near -0.47 V on its own axis
|   falling waveform, R_fixture 50, V_fixture 1.8: 20-80 % time 594ps typ, 837ps min, 449ps max; typ from 1.8 V to 1.51 V
|   falling waveform, R_fixture 50, V_fixture 0: 20-80 % time 97.9ps typ, 115ps min, 89.7ps max; typ from 0.325 V to 0 V
|   rising waveform, R_fixture 50, V_fixture 1.8: 20-80 % time 91.5ps typ, 102ps min, 85.8ps max; typ from 1.51 V to 1.8 V
|   rising waveform, R_fixture 50, V_fixture 0: 20-80 % time 262ps typ, 384ps min, 204ps max; typ from 0 V to 0.325 V
[GND Clamp]
| Voltage   I(typ)   I(min)   I(max)
-1.137V   -688mA     -831.1mA   -596.4mA
-1.07V    -398.5mA   -545.5mA   -312.5mA
-1.003V   -176.8mA   -300mA     -120.9mA
-936.6mV  -57.93mA   -128.6mA   -40.51mA
-869.7mV  -21.44mA   -44.12mA   -23.78mA
-802.8mV  -12.54mA   -16.03mA   -17.79mA
-735.9mV  -8.37mA    -7.69mA    -12.93mA
-669mV    -5.28mA    -4.356mA   -8.606mA
-535.2mV  -1.316mA   -1.208mA   -2.332mA
-401.4mV  -73.56uA   -132.2uA   -119.3uA
3.6V      0A         0A         0A
[POWER Clamp]
| Voltage   I(typ)   I(min)   I(max)
-1.07V    662.2mA    940mA      485.7mA
-1.003V   363.7mA    605.6mA    233mA
-936.6mV  172.7mA    341mA      103.9mA
-869.7mV  72.74mA    168.6mA    41.65mA
-802.8mV  28.31mA    73.56mA    19.99mA
-735.9mV  13.11mA    28.55mA    13.36mA
-669mV    7.76mA     11.5mA     8.963mA
-535.2mV  2.357mA    2.863mA    2.668mA
-334.5mV  34.33uA    127.4uA    15.59uA
3.6V      0A         0A         0A
[Pulldown]
| Voltage   I(typ)   I(min)   I(max)
-1.8V     -1.67mA    -1.924mA   -1.276mA
-1.204V   -1.828mA   -1.961mA   -1.481mA
-1.137V   -1.98mA    -1.96mA    -2.141mA
-1.003V   -5.309mA   -3.368mA   -6.428mA
-869.7mV  -6.803mA   -5.296mA   -7.336mA
-602.1mV  -6.311mA   -4.741mA   -7.463mA
-468.3mV  -5.446mA   -3.95mA    -6.73mA
-267.6mV  -3.441mA   -2.376mA   -4.455mA
248.3mV   2.883mA    1.853mA    3.936mA
558.6mV   4.664mA    3.032mA    6.268mA
1.117V    5.575mA    3.683mA    7.322mA
3.6V      7.173mA    4.831mA    9.21mA
[Pullup]
| Voltage   I(typ)   I(min)   I(max)
-1.8V     1.818mA    1.898mA    1.707mA
-1.204V   1.767mA    1.795mA    1.718mA
-1.137V   1.967mA    1.78mA     2.253mA
-1.07V    2.876mA    2.003mA    4.076mA
-1.003V   4.681mA    2.786mA    6.843mA
-936.6mV  6.347mA    3.994mA    8.16mA
-869.7mV  6.91mA     5.005mA    8.12mA
-468.3mV  4.694mA    3.675mA    5.616mA
310.3mV   -2.703mA   -1.996mA   -3.375mA
806.9mV   -5.199mA   -3.825mA   -6.5mA
1.738V    -6.774mA   -4.831mA   -8.686mA
3.6V      -7.839mA   -5.522mA   -10.21mA
[Ramp]
dV/dt_r   0.194996/0.262395n  0.13895/0.383656n  0.24866/0.204187n
dV/dt_f   0.174759/0.594007n  0.115472/0.837466n  0.228357/0.448895n
R_load = 50
[Falling Waveform]
R_fixture = 50
V_fixture = 1.8
V_fixture_min = 1.66
V_fixture_max = 1.89
| Time   V(typ)   V(min)   V(max)
0s        1.8V       1.66V      1.89V
481.6ps   1.806V     1.662V     1.885V
694.4ps   1.785V     1.663V     1.767V
934.9ps   1.704V     1.655V     1.634V
1.167ns   1.626V     1.626V     1.562V
1.493ns   1.557V     1.572V     1.526V
1.881ns   1.524V     1.52V      1.511V
2.598ns   1.509V     1.479V     1.508V
4.009ns   1.507V     1.466V     1.509V
50ns      1.509V     1.468V     1.509V
[Falling Waveform]
R_fixture = 50
V_fixture = 0
V_fixture_min = 0
V_fixture_max = 0
| Time   V(typ)   V(min)   V(max)
0s        325mV      231.6mV    414.4mV
249.3ps   325.8mV    231.6mV    408.7mV
289.6ps   327.3mV    231.5mV    356.4mV
328.2ps   319.3mV    232mV      232.6mV
374.7ps   273.4mV    233.5mV    105.7mV
440.2ps   125.1mV    230mV      33.99mV
523.3ps   31.95mV    181.1mV    7.433mV
659.9ps   3.457mV    31.25mV    1.081mV
975.7ps   581.7uV    537.2uV    392.5uV
50ns      37.82nV    2.276uV    15.26nV
[Rising Waveform]
R_fixture = 50
V_fixture = 1.8
V_fixture_min = 1.66
V_fixture_max = 1.89
| Time   V(typ)   V(min)   V(max)
0s        1.509V     1.468V     1.509V
261.7ps   1.508V     1.468V     1.515V
288.2ps   1.505V     1.468V     1.559V
354.1ps   1.521V     1.467V     1.769V
436.8ps   1.695V     1.462V     1.859V
504.8ps   1.764V     1.491V     1.878V
583ps     1.789V     1.592V     1.884V
639.3ps   1.794V     1.631V     1.886V
876.4ps   1.798V     1.658V     1.889V
50ns      1.8V       1.66V      1.89V
[Rising Waveform]
R_fixture = 50
V_fixture = 0
V_fixture_min = 0
V_fixture_max = 0
| Time   V(typ)   V(min)   V(max)
0s        37.87nV    2.272uV    15.19nV
485ps     -2.13mV    -1.146mV   1.035mV
548.7ps   -1.435mV   -3.384mV   44.66mV
660.8ps   12.66mV    -1.414mV   200.1mV
828.2ps   139.6mV    53.32uV    360.1mV
1.022ns   267.8mV    43.34mV    406.9mV
1.249ns   315.1mV    136mV      416.8mV
1.689ns   328mV      222mV      415.9mV
2.377ns   326.1mV    234.2mV    414.5mV
50ns      325mV      231.6mV    414.4mV
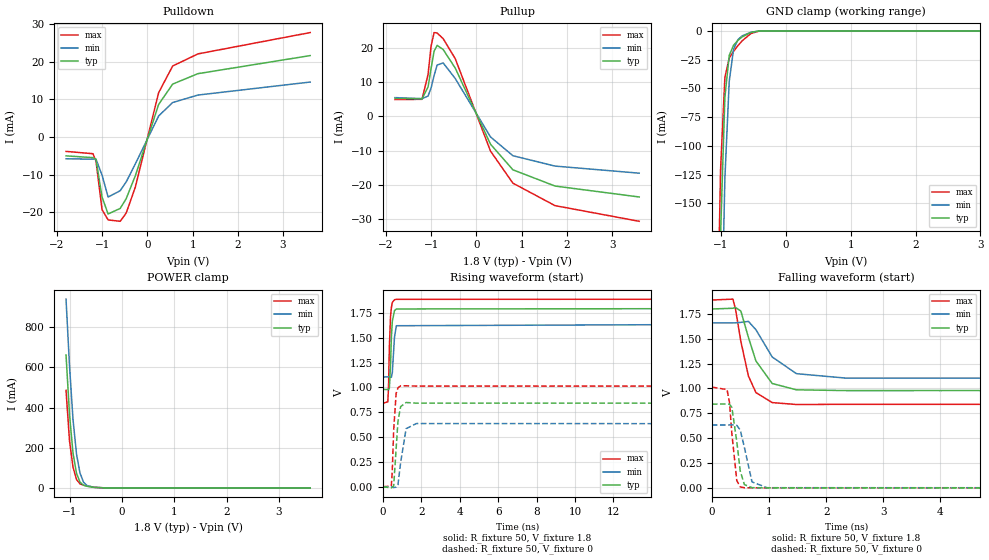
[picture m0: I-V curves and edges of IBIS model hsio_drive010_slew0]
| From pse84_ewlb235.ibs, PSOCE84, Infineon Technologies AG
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[Model] hsio_drive010_slew0
Model_type I/O
Enable   Active-High
Vinl  =  0.54
Vinh  =  1.26
Vmeas =  0.9
Cref  =  15pF
| Capacitance   typ   min   max
C_comp   1.183861e-12   1.145095e-12   1.230403e-12
| Variables   typ   min   max
[GND Clamp Reference]   0   0   0
[POWER Clamp Reference]   1.8   1.66   1.89
[Pulldown Reference]   0   0   0
[Pullup Reference]   1.8   1.66   1.89
[Temperature Range]   25   125   -40
[Voltage Range]   1.8   1.66   1.89
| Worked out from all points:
|   slope of the pulldown table from 0 to 0.27 V, typ, clamps not added: 29.4 ohm
|   slope of the pullup table from 0 to 0.27 V, typ, clamps not added: 37.6 ohm
|   GND clamp passes 1 mA (typ) near -0.51 V on its own axis
|   POWER clamp passes 1 mA (typ) near -0.47 V on its own axis
|   falling waveform, R_fixture 50, V_fixture 1.8: 20-80 % time 306ps typ, 422ps min, 239ps max; typ from 1.8 V to 0.98 V
|   falling waveform, R_fixture 50, V_fixture 0: 20-80 % time 98.2ps typ, 122ps min, 82.7ps max; typ from 0.842 V to 0 V
|   rising waveform, R_fixture 50, V_fixture 1.8: 20-80 % time 93.5ps typ, 106ps min, 86.7ps max; typ from 0.98 V to 1.8 V
|   rising waveform, R_fixture 50, V_fixture 0: 20-80 % time 160ps typ, 227ps min, 125ps max; typ from 0 V to 0.842 V
[GND Clamp]
| Voltage   I(typ)   I(min)   I(max)
-1.137V   -688mA     -831.1mA   -596.4mA
-1.07V    -398.5mA   -545.5mA   -312.5mA
-1.003V   -176.8mA   -300mA     -120.9mA
-936.6mV  -57.93mA   -128.6mA   -40.51mA
-869.7mV  -21.44mA   -44.12mA   -23.78mA
-802.8mV  -12.54mA   -16.03mA   -17.79mA
-735.9mV  -8.37mA    -7.69mA    -12.93mA
-669mV    -5.28mA    -4.356mA   -8.606mA
-535.2mV  -1.316mA   -1.208mA   -2.332mA
-401.4mV  -73.56uA   -132.2uA   -119.3uA
3.6V      0A         0A         0A
[POWER Clamp]
| Voltage   I(typ)   I(min)   I(max)
-1.07V    662.2mA    940mA      485.7mA
-1.003V   363.7mA    605.6mA    233mA
-936.6mV  172.7mA    341mA      103.9mA
-869.7mV  72.74mA    168.6mA    41.65mA
-802.8mV  28.31mA    73.56mA    19.99mA
-735.9mV  13.11mA    28.55mA    13.36mA
-669mV    7.76mA     11.5mA     8.963mA
-535.2mV  2.357mA    2.863mA    2.668mA
-334.5mV  34.33uA    127.4uA    15.59uA
3.6V      0A         0A         0A
[Pulldown]
| Voltage   I(typ)   I(min)   I(max)
-1.8V     -5.002mA   -5.771mA   -3.816mA
-1.204V   -5.473mA   -5.879mA   -4.429mA
-1.137V   -5.945mA   -5.879mA   -6.426mA
-1.003V   -15.93mA   -10.12mA   -19.26mA
-869.7mV  -20.4mA    -15.91mA   -21.97mA
-602.1mV  -18.93mA   -14.24mA   -22.34mA
-468.3mV  -16.32mA   -11.87mA   -20.13mA
-267.6mV  -10.29mA   -7.131mA   -13.28mA
248.3mV   8.628mA    5.568mA    11.74mA
558.6mV   14.02mA    9.135mA    18.81mA
1.117V    16.78mA    11.11mA    22.02mA
3.6V      21.57mA    14.56mA    27.67mA
[Pullup]
| Voltage   I(typ)   I(min)   I(max)
-1.8V     5.223mA    5.46mA     4.891mA
-1.204V   5.078mA    5.172mA    4.961mA
-1.07V    8.58mA     5.916mA    12.21mA
-1.003V   13.97mA    8.283mA    20.49mA
-936.6mV  18.98mA    11.89mA    24.43mA
-869.7mV  20.69mA    14.95mA    24.31mA
-735.9mV  19.48mA    15.58mA    22.65mA
-468.3mV  14.06mA    11.02mA    16.81mA
310.3mV   -8.101mA   -5.989mA   -10.11mA
806.9mV   -15.59mA   -11.48mA   -19.48mA
1.738V    -20.32mA   -14.5mA    -26.03mA
3.6V      -23.51mA   -16.57mA   -30.6mA
[Ramp]
dV/dt_r   0.505345/0.160213n  0.379547/0.2269n  0.608663/0.124887n
dV/dt_f   0.49178/0.30575n  0.332579/0.421662n  0.62979/0.238632n
R_load = 50
[Falling Waveform]
R_fixture = 50
V_fixture = 1.8
V_fixture_min = 1.66
V_fixture_max = 1.89
| Time   V(typ)   V(min)   V(max)
0s        1.8V       1.66V      1.89V
368.7ps   1.807V     1.66V      1.899V
414.9ps   1.815V     1.661V     1.796V
507.4ps   1.779V     1.665V     1.473V
639.8ps   1.514V     1.675V     1.125V
770.9ps   1.277V     1.591V     958.8mV
1.056ns   1.05V      1.317V     857.9mV
1.48ns    986.5mV    1.149V     838.7mV
2.35ns    978.8mV    1.104V     840.5mV
50ns      980.4mV    1.106V     840.4mV
[Falling Waveform]
R_fixture = 50
V_fixture = 0
V_fixture_min = 0
V_fixture_max = 0
| Time   V(typ)   V(min)   V(max)
0s        842.2mV    632.6mV    1.014V
266ps     844.3mV    632.5mV    988.7mV
309.8ps   841mV      632.8mV    853.6mV
349.9ps   809.2mV    634.2mV    546.3mV
436.3ps   465mV      628.9mV    72.69mV
496.3ps   170.4mV    582.6mV    9.342mV
569.2ps   32.45mV    407.5mV    1.138mV
702.4ps   1.866mV    60mV       724.2uV
965.5ps   492.6uV    1.484mV    271.9uV
50ns      21.09nV    1.503uV    7.848nV
[Rising Waveform]
R_fixture = 50
V_fixture = 1.8
V_fixture_min = 1.66
V_fixture_max = 1.89
| Time   V(typ)   V(min)   V(max)
0s        980.4mV    1.106V     840.4mV
259.1ps   979.5mV    1.106V     856.1mV
294.9ps   975.6mV    1.106V     997.3mV
337.6ps   990.9mV    1.106V     1.399V
398.8ps   1.22V      1.101V     1.713V
444.1ps   1.508V     1.103V     1.803V
493ps     1.666V     1.149V     1.856V
605.2ps   1.773V     1.504V     1.884V
701.1ps   1.791V     1.622V     1.888V
50ns      1.8V       1.66V      1.89V
[Rising Waveform]
R_fixture = 50
V_fixture = 0
V_fixture_min = 0
V_fixture_max = 0
| Time   V(typ)   V(min)   V(max)
0s        21.14nV    1.417uV    7.861nV
441.3ps   -11.09mV   -507.7uV   7.607mV
487.6ps   -7.061mV   -2.426mV   146.8mV
563.2ps   7.815mV    -8.024mV   569.8mV
690.9ps   379.7mV    -4.399mV   939.5mV
785.4ps   656.8mV    18.56mV    996.4mV
926.2ps   807.7mV    244.1mV    1.017V
1.211ns   848.8mV    585.3mV    1.017V
1.747ns   842.3mV    636.9mV    1.014V
50ns      842.2mV    632.6mV    1.014V
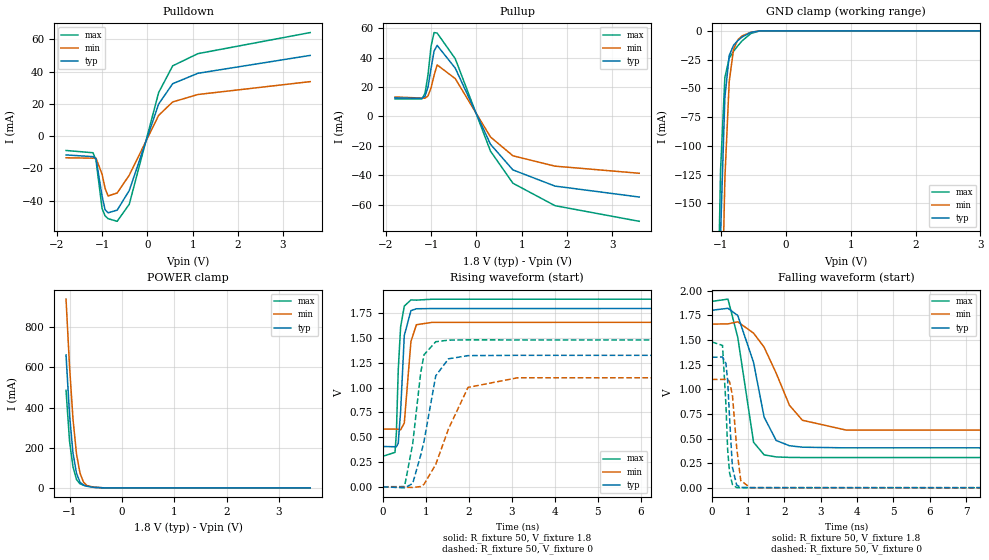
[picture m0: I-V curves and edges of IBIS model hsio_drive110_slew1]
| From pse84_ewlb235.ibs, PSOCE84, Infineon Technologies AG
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[Model] hsio_drive110_slew1
Model_type I/O
Enable   Active-High
Vinl  =  0.54
Vinh  =  1.26
Vmeas =  0.9
Cref  =  15pF
| Capacitance   typ   min   max
C_comp   1.183861e-12   1.145095e-12   1.230403e-12
| Variables   typ   min   max
[GND Clamp Reference]   0   0   0
[POWER Clamp Reference]   1.8   1.66   1.89
[Pulldown Reference]   0   0   0
[Pullup Reference]   1.8   1.66   1.89
[Temperature Range]   25   125   -40
[Voltage Range]   1.8   1.66   1.89
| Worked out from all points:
|   slope of the pulldown table from 0 to 0.27 V, typ, clamps not added: 12.7 ohm
|   slope of the pullup table from 0 to 0.27 V, typ, clamps not added: 16.1 ohm
|   GND clamp passes 1 mA (typ) near -0.51 V on its own axis
|   POWER clamp passes 1 mA (typ) near -0.47 V on its own axis
|   falling waveform, R_fixture 50, V_fixture 1.8: 20-80 % time 524ps typ, 809ps min, 372ps max; typ from 1.8 V to 0.406 V
|   falling waveform, R_fixture 50, V_fixture 0: 20-80 % time 113ps typ, 142ps min, 98.1ps max; typ from 1.32 V to 0 V
|   rising waveform, R_fixture 50, V_fixture 1.8: 20-80 % time 92.5ps typ, 108ps min, 84.8ps max; typ from 0.406 V to 1.8 V
|   rising waveform, R_fixture 50, V_fixture 0: 20-80 % time 344ps typ, 547ps min, 246ps max; typ from 0 V to 1.32 V
[GND Clamp]
| Voltage   I(typ)   I(min)   I(max)
-1.137V   -688mA     -831.1mA   -596.4mA
-1.07V    -398.5mA   -545.5mA   -312.5mA
-1.003V   -176.8mA   -300mA     -120.9mA
-936.6mV  -57.93mA   -128.6mA   -40.51mA
-869.7mV  -21.44mA   -44.12mA   -23.78mA
-802.8mV  -12.54mA   -16.03mA   -17.79mA
-735.9mV  -8.37mA    -7.69mA    -12.93mA
-669mV    -5.28mA    -4.356mA   -8.606mA
-535.2mV  -1.316mA   -1.208mA   -2.332mA
-401.4mV  -73.56uA   -132.2uA   -119.3uA
3.6V      0A         0A         0A
[POWER Clamp]
| Voltage   I(typ)   I(min)   I(max)
-1.07V    662.2mA    940mA      485.7mA
-1.003V   363.7mA    605.6mA    233mA
-936.6mV  172.7mA    341mA      103.9mA
-869.7mV  72.74mA    168.6mA    41.65mA
-802.8mV  28.31mA    73.56mA    19.99mA
-735.9mV  13.11mA    28.55mA    13.36mA
-669mV    7.76mA     11.5mA     8.963mA
-535.2mV  2.357mA    2.863mA    2.668mA
-334.5mV  34.33uA    127.4uA    15.59uA
3.6V      0A         0A         0A
[Pulldown]
| Voltage   I(typ)   I(min)   I(max)
-1.8V     -11.6mA    -13.38mA   -8.849mA
-1.204V   -12.68mA   -13.62mA   -10.25mA
-1.137V   -13.85mA   -13.62mA   -14.98mA
-1.003V   -37.1mA    -23.55mA   -44.87mA
-936.6mV  -45.58mA   -32.3mA    -49.38mA
-869.7mV  -47.49mA   -37.04mA   -51.14mA
-669mV    -45.85mA   -35.23mA   -52.77mA
-401.4mV  -33.69mA   -24.18mA   -42.18mA
248.3mV   19.95mA    12.92mA    27.05mA
558.6mV   32.56mA    21.25mA    43.64mA
1.117V    39.02mA    25.86mA    51.2mA
3.6V      50.11mA    33.85mA    64.27mA
[Pullup]
| Voltage   I(typ)   I(min)   I(max)
-1.8V     12.65mA    13.22mA    11.87mA
-1.204V   12.3mA     12.5mA     11.96mA
-1.137V   13.75mA    12.4mA     15.81mA
-1.07V    20.18mA    14.02mA    28.63mA
-1.003V   32.85mA    19.53mA    48.01mA
-936.6mV  44.48mA    28mA       57.11mA
-869.7mV  48.39mA    35.08mA    56.81mA
-468.3mV  32.87mA    25.75mA    39.28mA
310.3mV   -18.94mA   -14mA      -23.62mA
806.9mV   -36.43mA   -26.82mA   -45.5mA
1.738V    -47.45mA   -33.87mA   -60.79mA
3.6V      -54.89mA   -38.71mA   -71.43mA
[Ramp]
dV/dt_r   0.794511/0.344219n  0.659215/0.547416n  0.887583/0.245704n
dV/dt_f   0.836507/0.523729n  0.6475/0.808649n  0.94949/0.372368n
R_load = 50
[Falling Waveform]
R_fixture = 50
V_fixture = 1.8
V_fixture_min = 1.66
V_fixture_max = 1.89
| Time   V(typ)   V(min)   V(max)
0s        1.8V       1.66V      1.89V
443.7ps   1.82V      1.662V     1.913V
713.9ps   1.747V     1.683V     1.524V
1.149ns   1.27V      1.568V     461.9mV
1.439ns   717.4mV    1.426V     334.4mV
1.772ns   480.1mV    1.162V     313.5mV
2.138ns   427mV      836.2mV    308.6mV
2.496ns   412.2mV    684.9mV    307.5mV
3.699ns   405.5mV    585.7mV    307.5mV
50ns      405.8mV    580.8mV    307.5mV
[Falling Waveform]
R_fixture = 50
V_fixture = 0
V_fixture_min = 0
V_fixture_max = 0
| Time   V(typ)   V(min)   V(max)
0s        1.324V     1.099V     1.479V
293.4ps   1.326V     1.099V     1.444V
387.1ps   1.263V     1.101V     847mV
434.8ps   1.084V     1.098V     387.4mV
488.2ps   705.8mV    1.075V     152.6mV
566.4ps   207.9mV    941mV      34mV
682.8ps   28.65mV    411.3mV    2.573mV
795.5ps   4.367mV    74.25mV    2.404mV
1.057ns   2.329mV    2.062mV    1.241mV
50ns      11.3nV     819.2nV    4.053nV
[Rising Waveform]
R_fixture = 50
V_fixture = 1.8
V_fixture_min = 1.66
V_fixture_max = 1.89
| Time   V(typ)   V(min)   V(max)
0s        405.8mV    580.8mV    307.5mV
282.9ps   403.3mV    580.8mV    346.6mV
314.9ps   402.6mV    580.9mV    541.4mV
358.3ps   440mV      579.6mV    1.174V
413.2ps   755.8mV    573.9mV    1.609V
499.2ps   1.524V     642.8mV    1.82V
653.8ps   1.774V     1.464V     1.882V
781.1ps   1.793V     1.632V     1.88V
1.143ns   1.795V     1.656V     1.889V
50ns      1.8V       1.66V      1.89V
[Rising Waveform]
R_fixture = 50
V_fixture = 0
V_fixture_min = 0
V_fixture_max = 0
| Time   V(typ)   V(min)   V(max)
0s        11.32nV    812.9nV    4.049nV
504.5ps   -10.64mV   -4.255mV   2.434mV
693.7ps   32.64mV    -6.925mV   430.5mV
878.7ps   314.7mV    2.703mV    1.142V
958.1ps   458.3mV    25.63mV    1.33V
1.231ns   1.118V     225.3mV    1.461V
1.528ns   1.289V     583.5mV    1.477V
1.982ns   1.321V     1.001V     1.48V
3.136ns   1.324V     1.098V     1.479V
50ns      1.324V     1.099V     1.479V
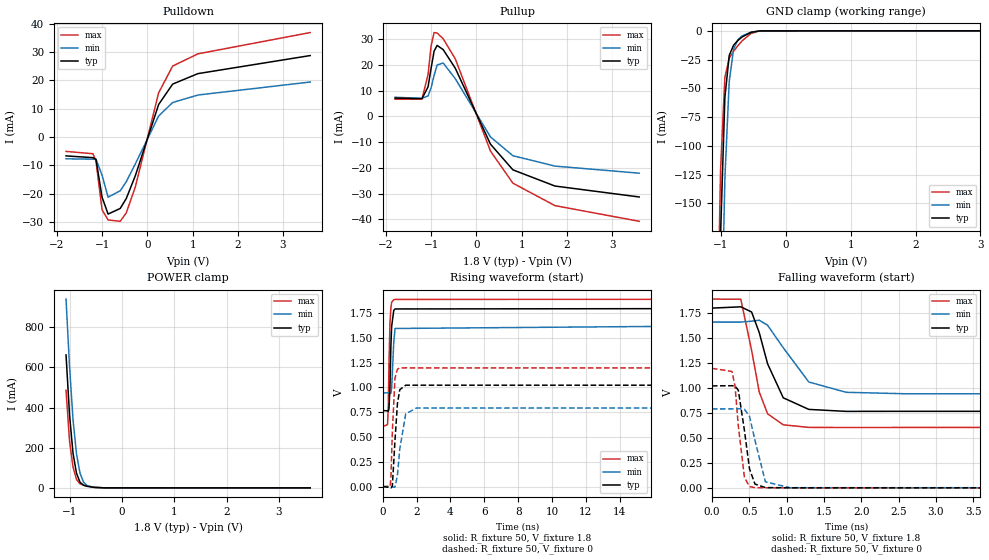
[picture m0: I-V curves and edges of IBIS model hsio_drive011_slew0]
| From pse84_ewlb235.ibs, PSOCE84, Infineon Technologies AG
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[Model] hsio_drive011_slew0
Model_type I/O
Enable   Active-High
Vinl  =  0.54
Vinh  =  1.26
Vmeas =  0.9
Cref  =  15pF
| Capacitance   typ   min   max
C_comp   1.183861e-12   1.145095e-12   1.230403e-12
| Variables   typ   min   max
[GND Clamp Reference]   0   0   0
[POWER Clamp Reference]   1.8   1.66   1.89
[Pulldown Reference]   0   0   0
[Pullup Reference]   1.8   1.66   1.89
[Temperature Range]   25   125   -40
[Voltage Range]   1.8   1.66   1.89
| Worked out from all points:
|   slope of the pulldown table from 0 to 0.27 V, typ, clamps not added: 22.2 ohm
|   slope of the pullup table from 0 to 0.27 V, typ, clamps not added: 28.2 ohm
|   GND clamp passes 1 mA (typ) near -0.51 V on its own axis
|   POWER clamp passes 1 mA (typ) near -0.47 V on its own axis
|   falling waveform, R_fixture 50, V_fixture 1.8: 20-80 % time 270ps typ, 388ps min, 199ps max; typ from 1.8 V to 0.767 V
|   falling waveform, R_fixture 50, V_fixture 0: 20-80 % time 99.4ps typ, 122ps min, 85.2ps max; typ from 1.02 V to 0 V
|   rising waveform, R_fixture 50, V_fixture 1.8: 20-80 % time 97.1ps typ, 112ps min, 89.2ps max; typ from 0.767 V to 1.8 V
|   rising waveform, R_fixture 50, V_fixture 0: 20-80 % time 206ps typ, 313ps min, 151ps max; typ from 0 V to 1.02 V
[GND Clamp]
| Voltage   I(typ)   I(min)   I(max)
-1.137V   -688mA     -831.1mA   -596.4mA
-1.07V    -398.5mA   -545.5mA   -312.5mA
-1.003V   -176.8mA   -300mA     -120.9mA
-936.6mV  -57.93mA   -128.6mA   -40.51mA
-869.7mV  -21.44mA   -44.12mA   -23.78mA
-802.8mV  -12.54mA   -16.03mA   -17.79mA
-735.9mV  -8.37mA    -7.69mA    -12.93mA
-669mV    -5.28mA    -4.356mA   -8.606mA
-535.2mV  -1.316mA   -1.208mA   -2.332mA
-401.4mV  -73.56uA   -132.2uA   -119.3uA
3.6V      0A         0A         0A
[POWER Clamp]
| Voltage   I(typ)   I(min)   I(max)
-1.07V    662.2mA    940mA      485.7mA
-1.003V   363.7mA    605.6mA    233mA
-936.6mV  172.7mA    341mA      103.9mA
-869.7mV  72.74mA    168.6mA    41.65mA
-802.8mV  28.31mA    73.56mA    19.99mA
-735.9mV  13.11mA    28.55mA    13.36mA
-669mV    7.76mA     11.5mA     8.963mA
-535.2mV  2.357mA    2.863mA    2.668mA
-334.5mV  34.33uA    127.4uA    15.59uA
3.6V      0A         0A         0A
[Pulldown]
| Voltage   I(typ)   I(min)   I(max)
-1.8V     -6.662mA   -7.687mA   -5.083mA
-1.204V   -7.288mA   -7.83mA    -5.897mA
-1.137V   -7.923mA   -7.829mA   -8.566mA
-1.003V   -21.23mA   -13.49mA   -25.67mA
-869.7mV  -27.18mA   -21.2mA    -29.27mA
-602.1mV  -25.2mA    -18.97mA   -29.73mA
-468.3mV  -21.72mA   -15.8mA    -26.77mA
-267.6mV  -13.68mA   -9.49mA    -17.62mA
248.3mV   11.47mA    7.41mA     15.58mA
558.6mV   18.66mA    12.17mA    25.03mA
1.117V    22.35mA    14.8mA     29.33mA
3.6V      28.72mA    19.39mA    36.83mA
[Pullup]
| Voltage   I(typ)   I(min)   I(max)
-1.8V     7.118mA    7.435mA    6.673mA
-1.204V   6.919mA    7.037mA    6.744mA
-1.07V    11.5mA     7.958mA    16.34mA
-1.003V   18.72mA    11.11mA    27.41mA
-936.6mV  25.37mA    15.94mA    32.61mA
-869.7mV  27.61mA    19.99mA    32.43mA
-735.9mV  25.99mA    20.78mA    30.21mA
-468.3mV  18.75mA    14.69mA    22.41mA
310.3mV   -10.8mA    -7.984mA   -13.48mA
806.9mV   -20.79mA   -15.3mA    -25.98mA
1.738V    -27.09mA   -19.33mA   -34.71mA
3.6V      -31.34mA   -22.09mA   -40.8mA
[Ramp]
dV/dt_r   0.612659/0.205999n  0.474506/0.313478n  0.718043/0.150802n
dV/dt_f   0.619988/0.27021n  0.429248/0.387892n  0.771191/0.198719n
R_load = 50
[Falling Waveform]
R_fixture = 50
V_fixture = 1.8
V_fixture_min = 1.66
V_fixture_max = 1.89
| Time   V(typ)   V(min)   V(max)
0s        1.8V       1.66V      1.89V
387.4ps   1.813V     1.66V      1.889V
532ps     1.761V     1.669V     1.378V
634.3ps   1.555V     1.679V     960.1mV
746.2ps   1.242V     1.628V     741.6mV
955.9ps   901.7mV    1.403V     631.4mV
1.298ns   785.8mV    1.06V      605.5mV
1.798ns   765.8mV    956.9mV    604.4mV
2.601ns   766.6mV    942.1mV    604.9mV
50ns      766.7mV    944.6mV    604.7mV
[Falling Waveform]
R_fixture = 50
V_fixture = 0
V_fixture_min = 0
V_fixture_max = 0
| Time   V(typ)   V(min)   V(max)
0s        1.021V     790.8mV    1.197V
269.1ps   1.023V     790.8mV    1.166V
309.7ps   1.02V      791.1mV    1.023V
354.3ps   977.4mV    792.8mV    618.7mV
435.8ps   576.4mV    786.5mV    106.1mV
503.7ps   190.6mV    717.8mV    12.65mV
577.5ps   37.48mV    475.1mV    2.249mV
717.1ps   2.841mV    60.42mV    792.3uV
1.046ns   410.8uV    1.701mV    200.3uV
50ns      17.31nV    1.269uV    6.355nV
[Rising Waveform]
R_fixture = 50
V_fixture = 1.8
V_fixture_min = 1.66
V_fixture_max = 1.89
| Time   V(typ)   V(min)   V(max)
0s        766.7mV    944.6mV    604.7mV
279ps     763.1mV    944.6mV    625.5mV
321.3ps   758.1mV    944.7mV    802.9mV
362ps     782.6mV    943mV      1.241V
421.5ps   1.005V     935.7mV    1.649V
475.5ps   1.419V     942.1mV    1.8V
520.5ps   1.615V     992.2mV    1.859V
646.2ps   1.777V     1.459V     1.884V
721.7ps   1.791V     1.594V     1.887V
50ns      1.8V       1.66V      1.89V
[Rising Waveform]
R_fixture = 50
V_fixture = 0
V_fixture_min = 0
V_fixture_max = 0
| Time   V(typ)   V(min)   V(max)
0s        17.35nV    1.194uV    6.354nV
439.3ps   -10.24mV   -84.94uV   1.016mV
483.3ps   -13.48mV   -1.216mV   117.3mV
562.2ps   3.446mV    -5.315mV   551mV
717.7ps   465.3mV    -6.148mV   1.093V
861.6ps   833.4mV    112.4mV    1.183V
1.001ns   976.5mV    378.7mV    1.196V
1.353ns   1.022V     732.6mV    1.197V
1.985ns   1.022V     791.7mV    1.196V
50ns      1.021V     790.8mV    1.197V
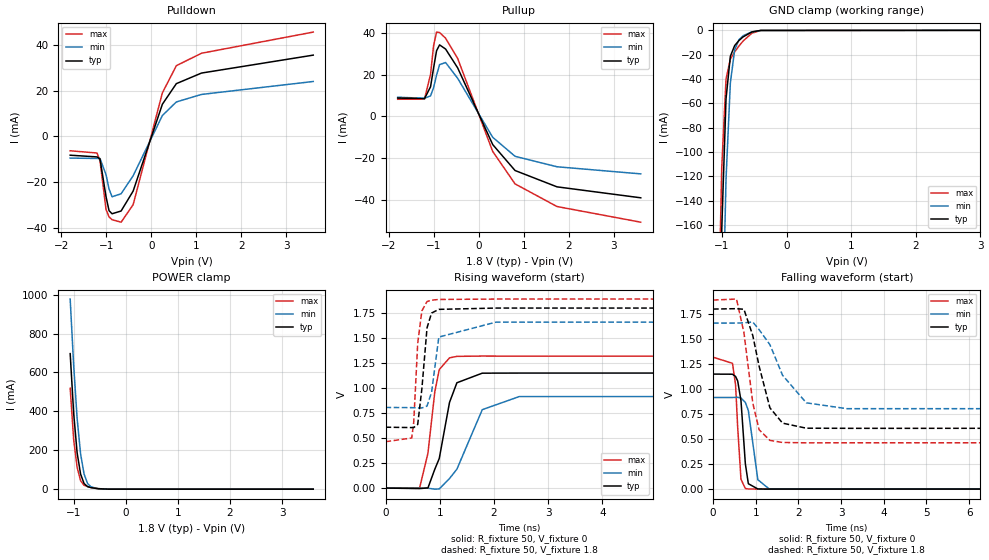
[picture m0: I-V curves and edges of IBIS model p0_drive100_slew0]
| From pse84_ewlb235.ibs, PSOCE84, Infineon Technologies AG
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[Model] p0_drive100_slew0
Model_type I/O
Polarity  Inverting
Enable   Active-High
Vinl  =  0.54
Vinh  =  1.26
Vmeas =  0.9
Cref  =  15pF
| Capacitance   typ   min   max
C_comp   1.253838e-12   1.215159e-12   1.300411e-12
| Variables   typ   min   max
[GND Clamp Reference]   0   0   0
[POWER Clamp Reference]   1.8   1.66   1.89
[Pulldown Reference]   0   0   0
[Pullup Reference]   1.8   1.66   1.89
[Temperature Range]   25   125   -40
[Voltage Range]   1.8   1.66   1.89
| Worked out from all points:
|   slope of the pulldown table from 0 to 0.27 V, typ, clamps not added: 18 ohm
|   slope of the pullup table from 0 to 0.27 V, typ, clamps not added: 22.7 ohm
|   GND clamp passes 1 mA (typ) near -0.51 V on its own axis
|   POWER clamp passes 1 mA (typ) near -0.47 V on its own axis
|   rising waveform, R_fixture 50, V_fixture 0: 20-80 % time 265ps typ, 416ps min, 188ps max; typ from 0 V to 1.15 V
|   rising waveform, R_fixture 50, V_fixture 1.8: 20-80 % time 100ps typ, 119ps min, 91.8ps max; typ from 0.609 V to 1.8 V
|   falling waveform, R_fixture 50, V_fixture 0: 20-80 % time 117ps typ, 158ps min, 91.5ps max; typ from 1.15 V to 0 V
|   falling waveform, R_fixture 50, V_fixture 1.8: 20-80 % time 392ps typ, 581ps min, 272ps max; typ from 1.8 V to 0.609 V
[GND Clamp]
| Voltage   I(typ)   I(min)   I(max)
-1.137V   -619.5mA   -754.2mA   -533mA
-1.07V    -361.2mA   -498.1mA   -281.3mA
-1.003V   -163.8mA   -277.7mA   -113mA
-936.6mV  -56.22mA   -122.3mA   -40.06mA
-869.7mV  -21.33mA   -43.3mA    -23.67mA
-802.8mV  -12.5mA    -15.96mA   -17.71mA
-735.9mV  -8.346mA   -7.675mA   -12.88mA
-669mV    -5.267mA   -4.349mA   -8.575mA
-535.2mV  -1.314mA   -1.207mA   -2.328mA
-401.4mV  -73.55uA   -132.2uA   -119.3uA
3.6V      0A         0A         0A
[POWER Clamp]
| Voltage   I(typ)   I(min)   I(max)
-1.07V    696.7mA    977.2mA    518.8mA
-1.003V   390.1mA    637.2mA    255.1mA
-936.6mV  187.1mA    363.9mA    112.4mA
-869.7mV  77.2mA     180.7mA    42.71mA
-802.8mV  28.89mA    77.43mA    19.98mA
-735.9mV  13.12mA    29.18mA    13.35mA
-669mV    7.754mA    11.55mA    8.954mA
-535.2mV  2.356mA    2.862mA    2.667mA
-334.5mV  34.33uA    127.4uA    15.58uA
3.6V      0A         0A         0A
[Pullup]
| Voltage   I(typ)   I(min)   I(max)
-1.8V     8.805mA    9.212mA    8.239mA
-1.204V   8.562mA    8.724mA    8.33mA
-1.07V    14.23mA    9.871mA    20.18mA
-1.003V   23.18mA    13.78mA    33.88mA
-936.6mV  31.45mA    19.77mA    40.37mA
-869.7mV  34.25mA    24.82mA    40.17mA
-735.9mV  32.25mA    25.82mA    37.44mA
-468.3mV  23.28mA    18.27mA    27.79mA
310.3mV   -13.41mA   -9.932mA   -16.7mA
806.9mV   -25.83mA   -19.04mA   -32.23mA
1.738V    -33.64mA   -24.04mA   -43.05mA
3.6V      -38.89mA   -27.45mA   -50.55mA
[Pulldown]
| Voltage   I(typ)   I(min)   I(max)
-1.8V     -8.173mA   -9.432mA   -6.24mA
-1.204V   -8.92mA    -9.594mA   -7.213mA
-1.137V   -9.832mA   -9.593mA   -10.66mA
-1.003V   -26.34mA   -16.71mA   -31.9mA
-936.6mV  -32.38mA   -22.93mA   -35.09mA
-869.7mV  -33.74mA   -26.31mA   -36.33mA
-669mV    -32.54mA   -25.03mA   -37.42mA
-401.4mV  -23.84mA   -17.15mA   -29.79mA
248.3mV   14.08mA    9.152mA    19.04mA
558.6mV   23.07mA    15.08mA    30.91mA
1.117V    27.69mA    18.36mA    36.34mA
3.6V      35.52mA    24.01mA    45.58mA
[Ramp]
dV/dt_r   0.689987/0.265483n  0.549653/0.416456n  0.791643/0.18847n
dV/dt_f   0.714867/0.392109n  0.512304/0.580535n  0.855962/0.271678n
R_load = 50
[Rising Waveform]
R_fixture = 50
V_fixture = 0
V_fixture_min = 0
V_fixture_max = 0
| Time   V(typ)   V(min)   V(max)
0s        14.92nV    1.041uV    5.435nV
628.8ps   -5.136mV   -11.99uV   2.639mV
782.1ps   1.785mV    -1.444mV   348.8mV
908.2ps   187.8mV    -10.98mV   960.3mV
990.9ps   296.1mV    -8.617mV   1.185V
1.18ns    856.6mV    95.54mV    1.302V
1.316ns   1.053V     189mV      1.317V
1.784ns   1.149V     784mV      1.32V
2.466ns   1.15V      915mV      1.319V
50ns      1.15V      916.1mV    1.319V
[Rising Waveform]
R_fixture = 50
V_fixture = 1.8
V_fixture_min = 1.66
V_fixture_max = 1.89
| Time   V(typ)   V(min)   V(max)
0s        608.6mV    806.2mV    463.4mV
483.1ps   604.9mV    804.3mV    500.8mV
519.4ps   604.9mV    803.1mV    653.8mV
593.1ps   636.1mV    801.6mV    1.447V
669.9ps   991.6mV    801.2mV    1.772V
765.4ps   1.603V     820.4mV    1.865V
848.9ps   1.75V      956.8mV    1.879V
982.8ps   1.787V     1.51V      1.886V
2.035ns   1.8V       1.659V     1.89V
50ns      1.8V       1.66V      1.89V
[Falling Waveform]
R_fixture = 50
V_fixture = 0
V_fixture_min = 0
V_fixture_max = 0
| Time   V(typ)   V(min)   V(max)
0s        1.15V      916.1mV    1.319V
454.8ps   1.149V     916.4mV    1.258V
527.5ps   1.126V     917.7mV    1.042V
576.6ps   1.082V     917.8mV    618.9mV
653.8ps   885.1mV    910.7mV    98.6mV
756.4ps   253.9mV    867.3mV    6.874mV
826.4ps   54.46mV    785.9mV    2.167mV
1.049ns   2.13mV     94.55mV    776.9uV
1.311ns   741.9uV    3.264mV    286.1uV
50ns      14.9nV     1.088uV    5.457nV
[Falling Waveform]
R_fixture = 50
V_fixture = 1.8
V_fixture_min = 1.66
V_fixture_max = 1.89
| Time   V(typ)   V(min)   V(max)
0s        1.8V       1.66V      1.89V
549.4ps   1.804V     1.66V      1.9V
722.8ps   1.798V     1.662V     1.565V
930.2ps   1.536V     1.671V     861.2mV
1.079ns   1.229V     1.594V     594mV
1.332ns   812.8mV    1.444V     487.6mV
1.629ns   659.7mV    1.138V     466.7mV
2.184ns   609.4mV    862.9mV    463.2mV
3.132ns   608.2mV    804.5mV    463.5mV
50ns      608.6mV    806.2mV    463.4mV
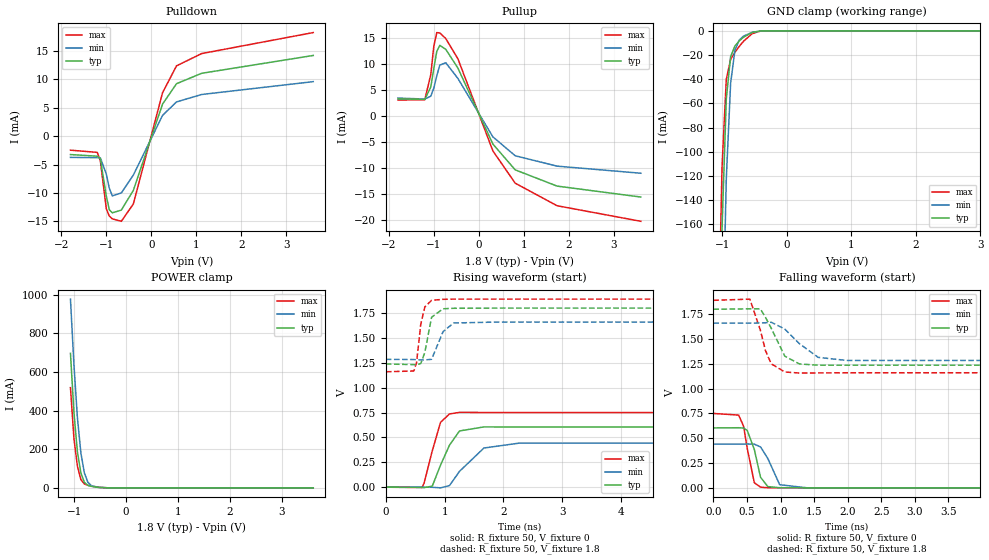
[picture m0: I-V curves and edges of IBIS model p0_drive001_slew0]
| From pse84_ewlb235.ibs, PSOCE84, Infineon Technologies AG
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[Model] p0_drive001_slew0
Model_type I/O
Polarity  Inverting
Enable   Active-High
Vinl  =  0.54
Vinh  =  1.26
Vmeas =  0.9
Cref  =  15pF
| Capacitance   typ   min   max
C_comp   1.253838e-12   1.215159e-12   1.300411e-12
| Variables   typ   min   max
[GND Clamp Reference]   0   0   0
[POWER Clamp Reference]   1.8   1.66   1.89
[Pulldown Reference]   0   0   0
[Pullup Reference]   1.8   1.66   1.89
[Temperature Range]   25   125   -40
[Voltage Range]   1.8   1.66   1.89
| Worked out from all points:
|   slope of the pulldown table from 0 to 0.27 V, typ, clamps not added: 45 ohm
|   slope of the pullup table from 0 to 0.27 V, typ, clamps not added: 57.2 ohm
|   GND clamp passes 1 mA (typ) near -0.51 V on its own axis
|   POWER clamp passes 1 mA (typ) near -0.47 V on its own axis
|   rising waveform, R_fixture 50, V_fixture 0: 20-80 % time 269ps typ, 405ps min, 201ps max; typ from 0 V to 0.604 V
|   rising waveform, R_fixture 50, V_fixture 1.8: 20-80 % time 103ps typ, 119ps min, 93.8ps max; typ from 1.24 V to 1.8 V
|   falling waveform, R_fixture 50, V_fixture 0: 20-80 % time 120ps typ, 148ps min, 107ps max; typ from 0.604 V to 0 V
|   falling waveform, R_fixture 50, V_fixture 1.8: 20-80 % time 240ps typ, 338ps min, 183ps max; typ from 1.8 V to 1.24 V
[GND Clamp]
| Voltage   I(typ)   I(min)   I(max)
-1.137V   -619.5mA   -754.2mA   -533mA
-1.07V    -361.2mA   -498.1mA   -281.3mA
-1.003V   -163.8mA   -277.7mA   -113mA
-936.6mV  -56.22mA   -122.3mA   -40.06mA
-869.7mV  -21.33mA   -43.3mA    -23.67mA
-802.8mV  -12.5mA    -15.96mA   -17.71mA
-735.9mV  -8.346mA   -7.675mA   -12.88mA
-669mV    -5.267mA   -4.349mA   -8.575mA
-535.2mV  -1.314mA   -1.207mA   -2.328mA
-401.4mV  -73.55uA   -132.2uA   -119.3uA
3.6V      0A         0A         0A
[POWER Clamp]
| Voltage   I(typ)   I(min)   I(max)
-1.07V    696.7mA    977.2mA    518.8mA
-1.003V   390.1mA    637.2mA    255.1mA
-936.6mV  187.1mA    363.9mA    112.4mA
-869.7mV  77.2mA     180.7mA    42.71mA
-802.8mV  28.89mA    77.43mA    19.98mA
-735.9mV  13.12mA    29.18mA    13.35mA
-669mV    7.754mA    11.55mA    8.954mA
-535.2mV  2.356mA    2.862mA    2.667mA
-334.5mV  34.33uA    127.4uA    15.58uA
3.6V      0A         0A         0A
[Pullup]
| Voltage   I(typ)   I(min)   I(max)
-1.8V     3.331mA    3.488mA    3.109mA
-1.204V   3.241mA    3.309mA    3.174mA
-1.07V    5.625mA    3.854mA    8.012mA
-1.003V   9.165mA    5.423mA    13.46mA
-936.6mV  12.48mA    7.792mA    16.07mA
-869.7mV  13.62mA    9.827mA    16mA
-735.9mV  12.84mA    10.27mA    14.91mA
-468.3mV  9.263mA    7.269mA    11.06mA
310.3mV   -5.335mA   -3.952mA   -6.645mA
806.9mV   -10.29mA   -7.585mA   -12.85mA
1.738V    -13.41mA   -9.579mA   -17.18mA
3.6V      -15.51mA   -10.94mA   -20.17mA
[Pulldown]
| Voltage   I(typ)   I(min)   I(max)
-1.8V     -3.24mA    -3.736mA   -2.476mA
-1.204V   -3.532mA   -3.799mA   -2.856mA
-1.137V   -3.931mA   -3.798mA   -4.269mA
-1.003V   -10.53mA   -6.665mA   -12.77mA
-936.6mV  -12.95mA   -9.152mA   -14.05mA
-869.7mV  -13.5mA    -10.51mA   -14.55mA
-669mV    -13.02mA   -10mA      -14.99mA
-401.4mV  -9.545mA   -6.856mA   -11.94mA
248.3mV   5.643mA    3.66mA     7.641mA
558.6mV   9.225mA    6.023mA    12.37mA
1.117V    11.06mA    7.329mA    14.53mA
3.6V      14.2mA     9.592mA    18.23mA
[Ramp]
dV/dt_r   0.362482/0.269399n  0.264541/0.404648n  0.449964/0.200907n
dV/dt_f   0.337393/0.240086n  0.225197/0.338488n  0.438127/0.183466n
R_load = 50
[Rising Waveform]
R_fixture = 50
V_fixture = 0
V_fixture_min = 0
V_fixture_max = 0
| Time   V(typ)   V(min)   V(max)
0s        27.47nV    1.757uV    10.55nV
617.1ps   -2.094mV   -2.789uV   -2.876mV
650.6ps   -4.239mV   -16.27uV   40.76mV
789.6ps   10.3mV     -803.7uV   364.7mV
930.9ps   222.4mV    -6.641mV   652.6mV
1.083ns   422.5mV    16.37mV    736mV
1.253ns   565.2mV    159.3mV    752.1mV
1.669ns   606mV      393.7mV    750.8mV
2.272ns   604.5mV    443.3mV    749.7mV
50ns      604.1mV    440.9mV    749.9mV
[Rising Waveform]
R_fixture = 50
V_fixture = 1.8
V_fixture_min = 1.66
V_fixture_max = 1.89
| Time   V(typ)   V(min)   V(max)
0s        1.238V     1.285V     1.16V
476.5ps   1.232V     1.283V     1.168V
522.4ps   1.231V     1.281V     1.251V
593.9ps   1.242V     1.279V     1.637V
663.7ps   1.355V     1.279V     1.812V
778ps     1.708V     1.285V     1.878V
974.3ps   1.793V     1.564V     1.888V
1.153ns   1.798V     1.65V      1.89V
1.924ns   1.8V       1.66V      1.89V
50ns      1.8V       1.66V      1.89V
[Falling Waveform]
R_fixture = 50
V_fixture = 0
V_fixture_min = 0
V_fixture_max = 0
| Time   V(typ)   V(min)   V(max)
0s        604.1mV    440.9mV    749.9mV
376.4ps   605.9mV    440.9mV    733.4mV
450.6ps   602.5mV    441.2mV    620.8mV
504.4ps   578.8mV    442.4mV    398.2mV
610.2ps   386.2mV    440.2mV    51.35mV
702.8ps   106.6mV    412.4mV    7.123mV
811.3ps   12.57mV    295.8mV    1.335mV
987.7ps   1.604mV    31.71mV    269.1uV
1.39ns    131uV      912.5uV    164.9uV
50ns      27.4nV     1.823uV    10.6nV
[Falling Waveform]
R_fixture = 50
V_fixture = 1.8
V_fixture_min = 1.66
V_fixture_max = 1.89
| Time   V(typ)   V(min)   V(max)
0s        1.8V       1.66V      1.89V
543.3ps   1.804V     1.66V      1.902V
700.1ps   1.804V     1.662V     1.59V
775.3ps   1.72V      1.664V     1.385V
861.7ps   1.609V     1.669V     1.25V
1.063ns   1.328V     1.601V     1.168V
1.28ns    1.249V     1.454V     1.157V
1.561ns   1.236V     1.315V     1.158V
1.989ns   1.236V     1.284V     1.16V
50ns      1.238V     1.285V     1.16V
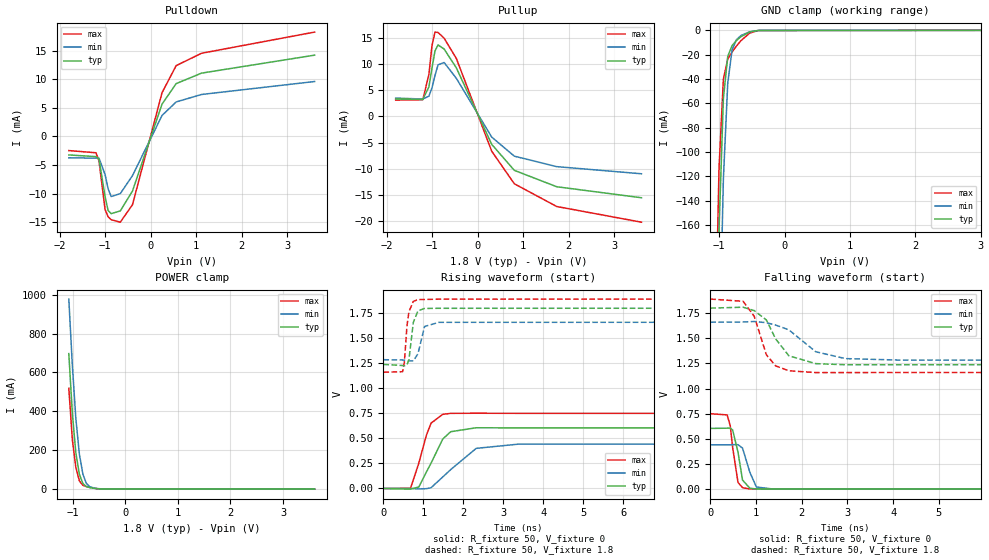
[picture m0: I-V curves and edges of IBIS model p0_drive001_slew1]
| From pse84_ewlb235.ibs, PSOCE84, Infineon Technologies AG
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[Model] p0_drive001_slew1
Model_type I/O
Polarity  Inverting
Enable   Active-High
Vinl  =  0.54
Vinh  =  1.26
Vmeas =  0.9
Cref  =  15pF
| Capacitance   typ   min   max
C_comp   1.253838e-12   1.215159e-12   1.300411e-12
| Variables   typ   min   max
[GND Clamp Reference]   0   0   0
[POWER Clamp Reference]   1.8   1.66   1.89
[Pulldown Reference]   0   0   0
[Pullup Reference]   1.8   1.66   1.89
[Temperature Range]   25   125   -40
[Voltage Range]   1.8   1.66   1.89
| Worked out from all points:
|   slope of the pulldown table from 0 to 0.27 V, typ, clamps not added: 45 ohm
|   slope of the pullup table from 0 to 0.27 V, typ, clamps not added: 57.2 ohm
|   GND clamp passes 1 mA (typ) near -0.51 V on its own axis
|   POWER clamp passes 1 mA (typ) near -0.47 V on its own axis
|   rising waveform, R_fixture 50, V_fixture 0: 20-80 % time 444ps typ, 686ps min, 325ps max; typ from 0 V to 0.604 V
|   rising waveform, R_fixture 50, V_fixture 1.8: 20-80 % time 101ps typ, 117ps min, 94.5ps max; typ from 1.24 V to 1.8 V
|   falling waveform, R_fixture 50, V_fixture 0: 20-80 % time 121ps typ, 148ps min, 109ps max; typ from 0.604 V to 0 V
|   falling waveform, R_fixture 50, V_fixture 1.8: 20-80 % time 441ps typ, 622ps min, 339ps max; typ from 1.8 V to 1.24 V
[GND Clamp]
| Voltage   I(typ)   I(min)   I(max)
-1.137V   -619.5mA   -754.2mA   -533mA
-1.07V    -361.2mA   -498.1mA   -281.3mA
-1.003V   -163.8mA   -277.7mA   -113mA
-936.6mV  -56.22mA   -122.3mA   -40.06mA
-869.7mV  -21.33mA   -43.3mA    -23.67mA
-802.8mV  -12.5mA    -15.96mA   -17.71mA
-735.9mV  -8.346mA   -7.675mA   -12.88mA
-669mV    -5.267mA   -4.349mA   -8.575mA
-535.2mV  -1.314mA   -1.207mA   -2.328mA
-401.4mV  -73.55uA   -132.2uA   -119.3uA
3.6V      0A         0A         0A
[POWER Clamp]
| Voltage   I(typ)   I(min)   I(max)
-1.07V    696.7mA    977.2mA    518.8mA
-1.003V   390.1mA    637.2mA    255.1mA
-936.6mV  187.1mA    363.9mA    112.4mA
-869.7mV  77.2mA     180.7mA    42.71mA
-802.8mV  28.89mA    77.43mA    19.98mA
-735.9mV  13.12mA    29.18mA    13.35mA
-669mV    7.754mA    11.55mA    8.954mA
-535.2mV  2.356mA    2.862mA    2.667mA
-334.5mV  34.33uA    127.4uA    15.58uA
3.6V      0A         0A         0A
[Pullup]
| Voltage   I(typ)   I(min)   I(max)
-1.8V     3.331mA    3.488mA    3.109mA
-1.204V   3.241mA    3.309mA    3.174mA
-1.07V    5.625mA    3.854mA    8.012mA
-1.003V   9.165mA    5.423mA    13.46mA
-936.6mV  12.48mA    7.792mA    16.07mA
-869.7mV  13.62mA    9.827mA    16mA
-735.9mV  12.84mA    10.27mA    14.91mA
-468.3mV  9.263mA    7.269mA    11.06mA
310.3mV   -5.335mA   -3.952mA   -6.645mA
806.9mV   -10.29mA   -7.585mA   -12.85mA
1.738V    -13.41mA   -9.579mA   -17.18mA
3.6V      -15.51mA   -10.94mA   -20.17mA
[Pulldown]
| Voltage   I(typ)   I(min)   I(max)
-1.8V     -3.24mA    -3.736mA   -2.476mA
-1.204V   -3.532mA   -3.799mA   -2.856mA
-1.137V   -3.931mA   -3.798mA   -4.269mA
-1.003V   -10.53mA   -6.665mA   -12.77mA
-936.6mV  -12.95mA   -9.152mA   -14.05mA
-869.7mV  -13.5mA    -10.51mA   -14.55mA
-669mV    -13.02mA   -10mA      -14.99mA
-401.4mV  -9.545mA   -6.856mA   -11.94mA
248.3mV   5.643mA    3.66mA     7.641mA
558.6mV   9.225mA    6.023mA    12.37mA
1.117V    11.06mA    7.329mA    14.53mA
3.6V      14.2mA     9.592mA    18.23mA
[Ramp]
dV/dt_r   0.362482/0.444451n  0.264538/0.685951n  0.449964/0.325319n
dV/dt_f   0.337393/0.441046n  0.225197/0.622302n  0.438127/0.338659n
R_load = 50
[Rising Waveform]
R_fixture = 50
V_fixture = 0
V_fixture_min = 0
V_fixture_max = 0
| Time   V(typ)   V(min)   V(max)
0s        27.47nV    1.757uV    10.55nV
678.3ps   -6.877mV   -14.8uV    1.985mV
887.2ps   15.19mV    -4.035mV   253.7mV
1.074ns   162.6mV    -2.158mV   529mV
1.192ns   251.8mV    7.261mV    651.3mV
1.485ns   492.7mV    114.3mV    739.4mV
1.685ns   566.5mV    188.5mV    749.7mV
2.324ns   605.9mV    400.4mV    750.9mV
3.384ns   604.6mV    442.5mV    749.8mV
50ns      604.1mV    440.9mV    749.9mV
[Rising Waveform]
R_fixture = 50
V_fixture = 1.8
V_fixture_min = 1.66
V_fixture_max = 1.89
| Time   V(typ)   V(min)   V(max)
0s        1.238V     1.285V     1.16V
480ps     1.227V     1.282V     1.165V
524.2ps   1.225V     1.28V      1.257V
588.9ps   1.232V     1.276V     1.618V
638.3ps   1.283V     1.274V     1.763V
749.2ps   1.658V     1.273V     1.867V
866.8ps   1.773V     1.346V     1.885V
1.03ns    1.796V     1.616V     1.886V
1.387ns   1.798V     1.658V     1.889V
50ns      1.8V       1.66V      1.89V
[Falling Waveform]
R_fixture = 50
V_fixture = 0
V_fixture_min = 0
V_fixture_max = 0
| Time   V(typ)   V(min)   V(max)
0s        604.1mV    440.9mV    749.9mV
368.6ps   606.3mV    440.9mV    738.3mV
436ps     606.8mV    441mV      633.8mV
490.2ps   587.7mV    442.6mV    413.2mV
606.3ps   368.9mV    442.5mV    67.19mV
705.6ps   90.78mV    408.6mV    14.97mV
866.6ps   9.067mV    166.7mV    1.744mV
1.01ns    2.031mV    21.12mV    2.461mV
1.383ns   1.386mV    925.1uV    411.7uV
50ns      27.45nV    1.762uV    10.61nV
[Falling Waveform]
R_fixture = 50
V_fixture = 1.8
V_fixture_min = 1.66
V_fixture_max = 1.89
| Time   V(typ)   V(min)   V(max)
0s        1.8V       1.66V      1.89V
718.4ps   1.809V     1.662V     1.868V
962.4ps   1.775V     1.667V     1.718V
1.228ns   1.682V     1.655V     1.336V
1.429ns   1.495V     1.632V     1.226V
1.72ns    1.326V     1.584V     1.177V
2.308ns   1.248V     1.366V     1.159V
2.958ns   1.237V     1.298V     1.159V
4.168ns   1.237V     1.283V     1.16V
50ns      1.238V     1.285V     1.16V
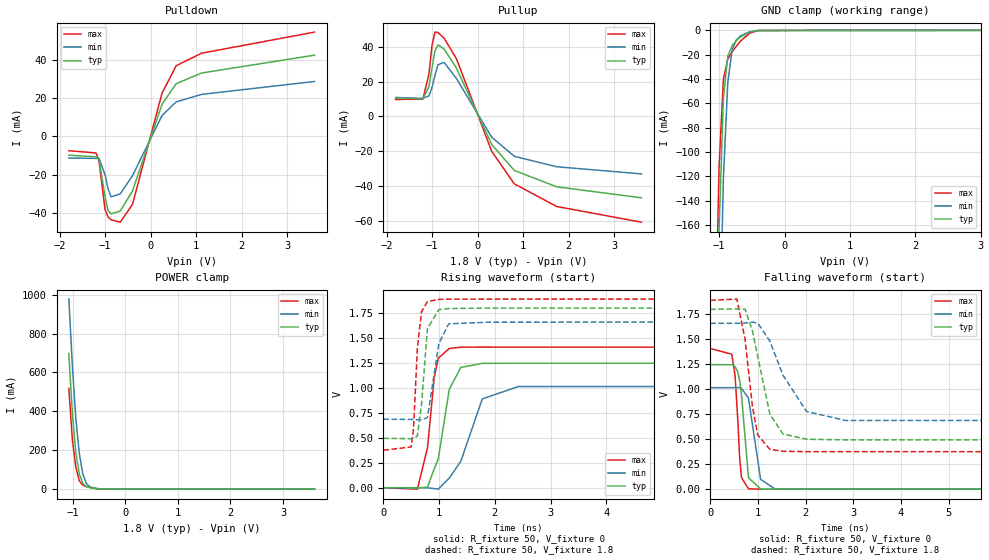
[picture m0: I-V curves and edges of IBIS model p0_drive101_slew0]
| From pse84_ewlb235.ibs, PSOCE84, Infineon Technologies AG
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[Model] p0_drive101_slew0
Model_type I/O
Polarity  Inverting
Enable   Active-High
Vinl  =  0.54
Vinh  =  1.26
Vmeas =  0.9
Cref  =  15pF
| Capacitance   typ   min   max
C_comp   1.253838e-12   1.215159e-12   1.300411e-12
| Variables   typ   min   max
[GND Clamp Reference]   0   0   0
[POWER Clamp Reference]   1.8   1.66   1.89
[Pulldown Reference]   0   0   0
[Pullup Reference]   1.8   1.66   1.89
[Temperature Range]   25   125   -40
[Voltage Range]   1.8   1.66   1.89
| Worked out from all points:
|   slope of the pulldown table from 0 to 0.27 V, typ, clamps not added: 15.1 ohm
|   slope of the pullup table from 0 to 0.27 V, typ, clamps not added: 19 ohm
|   GND clamp passes 1 mA (typ) near -0.51 V on its own axis
|   POWER clamp passes 1 mA (typ) near -0.47 V on its own axis
|   rising waveform, R_fixture 50, V_fixture 0: 20-80 % time 224ps typ, 355ps min, 160ps max; typ from 0 V to 1.25 V
|   rising waveform, R_fixture 50, V_fixture 1.8: 20-80 % time 100ps typ, 120ps min, 90.3ps max; typ from 0.495 V to 1.8 V
|   falling waveform, R_fixture 50, V_fixture 0: 20-80 % time 123ps typ, 165ps min, 98.7ps max; typ from 1.25 V to 0 V
|   falling waveform, R_fixture 50, V_fixture 1.8: 20-80 % time 338ps typ, 531ps min, 227ps max; typ from 1.8 V to 0.495 V
[GND Clamp]
| Voltage   I(typ)   I(min)   I(max)
-1.137V   -619.5mA   -754.2mA   -533mA
-1.07V    -361.2mA   -498.1mA   -281.3mA
-1.003V   -163.8mA   -277.7mA   -113mA
-936.6mV  -56.22mA   -122.3mA   -40.06mA
-869.7mV  -21.33mA   -43.3mA    -23.67mA
-802.8mV  -12.5mA    -15.96mA   -17.71mA
-735.9mV  -8.346mA   -7.675mA   -12.88mA
-669mV    -5.267mA   -4.349mA   -8.575mA
-535.2mV  -1.314mA   -1.207mA   -2.328mA
-401.4mV  -73.55uA   -132.2uA   -119.3uA
3.6V      0A         0A         0A
[POWER Clamp]
| Voltage   I(typ)   I(min)   I(max)
-1.07V    696.7mA    977.2mA    518.8mA
-1.003V   390.1mA    637.2mA    255.1mA
-936.6mV  187.1mA    363.9mA    112.4mA
-869.7mV  77.2mA     180.7mA    42.71mA
-802.8mV  28.89mA    77.43mA    19.98mA
-735.9mV  13.12mA    29.18mA    13.35mA
-669mV    7.754mA    11.55mA    8.954mA
-535.2mV  2.356mA    2.862mA    2.667mA
-334.5mV  34.33uA    127.4uA    15.58uA
3.6V      0A         0A         0A
[Pullup]
| Voltage   I(typ)   I(min)   I(max)
-1.8V     10.42mA    10.91mA    9.748mA
-1.204V   10.14mA    10.34mA    9.878mA
-1.07V    17.03mA    11.78mA    24.18mA
-1.003V   27.73mA    16.47mA    40.58mA
-936.6mV  37.65mA    23.64mA    48.34mA
-869.7mV  41.02mA    29.7mA     48.11mA
-735.9mV  38.62mA    30.93mA    44.83mA
-468.3mV  27.87mA    21.88mA    33.26mA
310.3mV   -16.05mA   -11.89mA   -19.99mA
806.9mV   -30.94mA   -22.81mA   -38.6mA
1.738V    -40.29mA   -28.8mA    -51.57mA
3.6V      -46.58mA   -32.89mA   -60.55mA
[Pulldown]
| Voltage   I(typ)   I(min)   I(max)
-1.8V     -9.752mA   -11.25mA   -7.449mA
-1.204V   -10.63mA   -11.44mA   -8.6mA
-1.137V   -11.77mA   -11.44mA   -12.78mA
-1.003V   -31.53mA   -19.99mA   -38.21mA
-936.6mV  -38.76mA   -27.43mA   -42.02mA
-869.7mV  -40.38mA   -31.49mA   -43.48mA
-669mV    -38.89mA   -29.94mA   -44.72mA
-401.4mV  -28.42mA   -20.48mA   -35.46mA
248.3mV   16.76mA    10.92mA    22.6mA
558.6mV   27.54mA    18.02mA    36.87mA
1.117V    33.09mA    21.95mA    43.43mA
3.6V      42.42mA    28.69mA    54.44mA
[Ramp]
dV/dt_r   0.747895/0.224264n  0.609468/0.355108n  0.845008/0.159523n
dV/dt_f   0.783267/0.338118n  0.583982/0.531195n  0.908802/0.227419n
R_load = 50
[Rising Waveform]
R_fixture = 50
V_fixture = 0
V_fixture_min = 0
V_fixture_max = 0
| Time   V(typ)   V(min)   V(max)
0s        13.05nV    920.4nV    4.73nV
610.3ps   -2.431mV   -2.1uV     -14.66mV
792.2ps   5.472mV    -1.27mV    401.5mV
910.5ps   187.9mV    -8.635mV   1.098V
984.3ps   287.9mV    -14.22mV   1.297V
1.182ns   985.2mV    95.59mV    1.395V
1.389ns   1.205V     265mV      1.408V
1.775ns   1.246V     889.9mV    1.409V
2.426ns   1.247V     1.014V     1.408V
50ns      1.246V     1.016V     1.408V
[Rising Waveform]
R_fixture = 50
V_fixture = 1.8
V_fixture_min = 1.66
V_fixture_max = 1.89
| Time   V(typ)   V(min)   V(max)
0s        494.6mV    686.7mV    375.3mV
499.3ps   490.9mV    683.8mV    408.3mV
540.9ps   491.4mV    682.3mV    593.3mV
610.2ps   520.5mV    681mV      1.404V
684.5ps   836.8mV    680.4mV    1.764V
790ps     1.594V     703.3mV    1.865V
995ps     1.784V     1.444V     1.887V
1.171ns   1.795V     1.642V     1.889V
1.928ns   1.8V       1.659V     1.89V
50ns      1.8V       1.66V      1.89V
[Falling Waveform]
R_fixture = 50
V_fixture = 0
V_fixture_min = 0
V_fixture_max = 0
| Time   V(typ)   V(min)   V(max)
0s        1.246V     1.016V     1.408V
450.7ps   1.246V     1.016V     1.351V
520.6ps   1.226V     1.017V     1.136V
576.1ps   1.175V     1.017V     706mV
618.6ps   1.084V     1.015V     299.2mV
655.8ps   938.7mV    1.009V     116mV
801.9ps   114.1mV    910.3mV    3.014mV
1.057ns   2.145mV    97.68mV    754.6uV
1.356ns   614.9uV    3.099mV    250.1uV
50ns      13.04nV    990.7nV    4.733nV
[Falling Waveform]
R_fixture = 50
V_fixture = 1.8
V_fixture_min = 1.66
V_fixture_max = 1.89
| Time   V(typ)   V(min)   V(max)
0s        1.8V       1.66V      1.89V
558.4ps   1.805V     1.66V      1.903V
729.2ps   1.802V     1.663V     1.501V
884.2ps   1.586V     1.672V     830.5mV
996.3ps   1.325V     1.663V     542.2mV
1.251ns   749.9mV    1.482V     397.8mV
1.525ns   552.5mV    1.142V     379.4mV
2.021ns   499.6mV    777.7mV    375.1mV
2.837ns   494mV      688mV      375.3mV
50ns      494.6mV    686.7mV    375.3mV
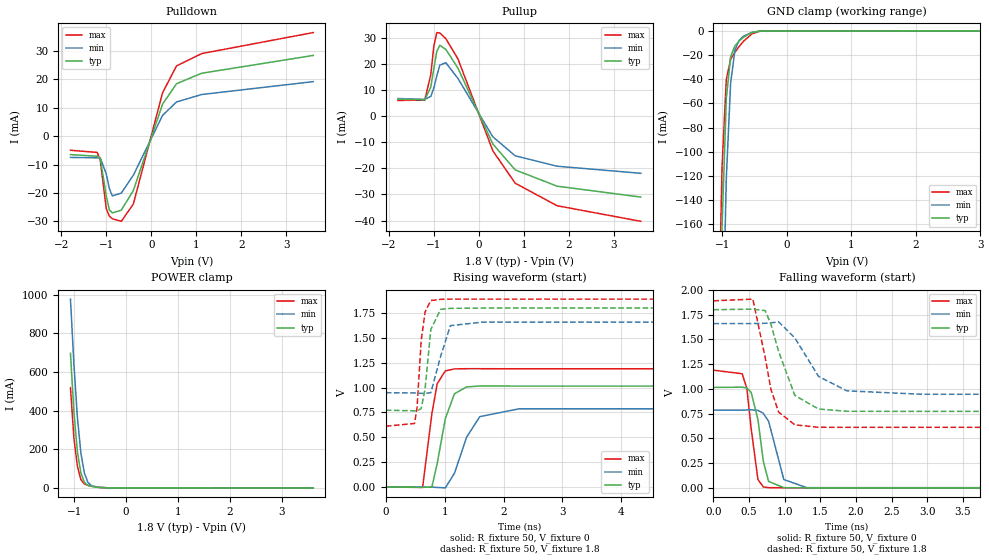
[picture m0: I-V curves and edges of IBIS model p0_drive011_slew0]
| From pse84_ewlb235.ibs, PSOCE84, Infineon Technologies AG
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[Model] p0_drive011_slew0
Model_type I/O
Polarity  Inverting
Enable   Active-High
Vinl  =  0.54
Vinh  =  1.26
Vmeas =  0.9
Cref  =  15pF
| Capacitance   typ   min   max
C_comp   1.253838e-12   1.215159e-12   1.300411e-12
| Variables   typ   min   max
[GND Clamp Reference]   0   0   0
[POWER Clamp Reference]   1.8   1.66   1.89
[Pulldown Reference]   0   0   0
[Pullup Reference]   1.8   1.66   1.89
[Temperature Range]   25   125   -40
[Voltage Range]   1.8   1.66   1.89
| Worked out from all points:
|   slope of the pulldown table from 0 to 0.27 V, typ, clamps not added: 22.5 ohm
|   slope of the pullup table from 0 to 0.27 V, typ, clamps not added: 28.6 ohm
|   GND clamp passes 1 mA (typ) near -0.51 V on its own axis
|   POWER clamp passes 1 mA (typ) near -0.47 V on its own axis
|   rising waveform, R_fixture 50, V_fixture 0: 20-80 % time 204ps typ, 312ps min, 149ps max; typ from 0 V to 1.01 V
|   rising waveform, R_fixture 50, V_fixture 1.8: 20-80 % time 102ps typ, 120ps min, 93.3ps max; typ from 0.773 V to 1.8 V
|   falling waveform, R_fixture 50, V_fixture 0: 20-80 % time 119ps typ, 149ps min, 102ps max; typ from 1.01 V to 0 V
|   falling waveform, R_fixture 50, V_fixture 1.8: 20-80 % time 270ps typ, 388ps min, 200ps max; typ from 1.8 V to 0.773 V
[GND Clamp]
| Voltage   I(typ)   I(min)   I(max)
-1.137V   -619.5mA   -754.2mA   -533mA
-1.07V    -361.2mA   -498.1mA   -281.3mA
-1.003V   -163.8mA   -277.7mA   -113mA
-936.6mV  -56.22mA   -122.3mA   -40.06mA
-869.7mV  -21.33mA   -43.3mA    -23.67mA
-802.8mV  -12.5mA    -15.96mA   -17.71mA
-735.9mV  -8.346mA   -7.675mA   -12.88mA
-669mV    -5.267mA   -4.349mA   -8.575mA
-535.2mV  -1.314mA   -1.207mA   -2.328mA
-401.4mV  -73.55uA   -132.2uA   -119.3uA
3.6V      0A         0A         0A
[POWER Clamp]
| Voltage   I(typ)   I(min)   I(max)
-1.07V    696.7mA    977.2mA    518.8mA
-1.003V   390.1mA    637.2mA    255.1mA
-936.6mV  187.1mA    363.9mA    112.4mA
-869.7mV  77.2mA     180.7mA    42.71mA
-802.8mV  28.89mA    77.43mA    19.98mA
-735.9mV  13.12mA    29.18mA    13.35mA
-669mV    7.754mA    11.55mA    8.954mA
-535.2mV  2.356mA    2.862mA    2.667mA
-334.5mV  34.33uA    127.4uA    15.58uA
3.6V      0A         0A         0A
[Pullup]
| Voltage   I(typ)   I(min)   I(max)
-1.8V     6.481mA    6.795mA    6.041mA
-1.204V   6.313mA    6.452mA    6.201mA
-1.07V    11.2mA     7.632mA    15.98mA
-1.003V   18.25mA    10.78mA    26.84mA
-936.6mV  24.89mA    15.49mA    32.08mA
-869.7mV  27.21mA    19.59mA    31.94mA
-735.9mV  25.65mA    20.53mA    29.76mA
-468.3mV  18.5mA     14.53mA    22.07mA
310.3mV   -10.66mA   -7.903mA   -13.27mA
806.9mV   -20.57mA   -15.17mA   -25.67mA
1.738V    -26.81mA   -19.16mA   -34.31mA
3.6V      -30.99mA   -21.88mA   -40.28mA
[Pulldown]
| Voltage   I(typ)   I(min)   I(max)
-1.8V     -6.48mA    -7.478mA   -4.95mA
-1.204V   -7.066mA   -7.605mA   -5.711mA
-1.137V   -7.866mA   -7.604mA   -8.539mA
-1.003V   -21.07mA   -13.35mA   -25.53mA
-936.6mV  -25.91mA   -18.32mA   -28.09mA
-869.7mV  -27.01mA   -21.05mA   -29.08mA
-669mV    -26.06mA   -20.03mA   -29.98mA
-401.4mV  -19.12mA   -13.74mA   -23.9mA
248.3mV   11.3mA     7.336mA    15.3mA
558.6mV   18.49mA    12.08mA    24.78mA
1.117V    22.19mA    14.7mA     29.12mA
3.6V      28.47mA    19.24mA    36.53mA
[Ramp]
dV/dt_r   0.608795/0.204361n  0.471543/0.311526n  0.713578/0.149477n
dV/dt_f   0.61646/0.269727n  0.426862/0.38794n  0.767105/0.200132n
R_load = 50
[Rising Waveform]
R_fixture = 50
V_fixture = 0
V_fixture_min = 0
V_fixture_max = 0
| Time   V(typ)   V(min)   V(max)
0s        17.55nV    1.202uV    6.456nV
624.3ps   -3.154mV   -6.19uV    -4.353mV
781.8ps   -116.6uV   -888.8uV   736.4mV
871.9ps   235.6mV    -4.554mV   1.038V
1.01ns    686.9mV    -8.686mV   1.168V
1.165ns   937.9mV    137.8mV    1.188V
1.371ns   1.007V     500.8mV    1.19V
1.596ns   1.016V     708.1mV    1.19V
2.268ns   1.015V     786.9mV    1.189V
50ns      1.015V     785.9mV    1.189V
[Rising Waveform]
R_fixture = 50
V_fixture = 1.8
V_fixture_min = 1.66
V_fixture_max = 1.89
| Time   V(typ)   V(min)   V(max)
0s        772.6mV    948.6mV    611.5mV
487.3ps   766.5mV    946mV      639mV
530.2ps   765.9mV    944mV      798.9mV
600.4ps   788.8mV    942.2mV    1.473V
667.1ps   990mV      941.2mV    1.762V
764.1ps   1.585V     949mV      1.876V
929.8ps   1.787V     1.313V     1.888V
1.095ns   1.797V     1.623V     1.89V
1.645ns   1.8V       1.659V     1.89V
50ns      1.8V       1.66V      1.89V
[Falling Waveform]
R_fixture = 50
V_fixture = 0
V_fixture_min = 0
V_fixture_max = 0
| Time   V(typ)   V(min)   V(max)
0s        1.015V     785.9mV    1.189V
404ps     1.017V     785.9mV    1.153V
469.8ps   1.008V     786.9mV    1.003V
529.3ps   966.1mV    788.4mV    602.4mV
624.9ps   690.7mV    783mV      83.92mV
701ps     264.8mV    753.1mV    8.69mV
774.5ps   64.68mV    672.7mV    2.282mV
987.6ps   1.887mV    84.06mV    493.3uV
1.309ns   346.1uV    2.085mV    185.6uV
50ns      17.51nV    1.271uV    6.459nV
[Falling Waveform]
R_fixture = 50
V_fixture = 1.8
V_fixture_min = 1.66
V_fixture_max = 1.89
| Time   V(typ)   V(min)   V(max)
0s        1.8V       1.66V      1.89V
553.6ps   1.806V     1.66V      1.907V
727.5ps   1.791V     1.663V     1.313V
806.4ps   1.652V     1.667V     996.9mV
914.1ps   1.38V      1.678V     766.3mV
1.142ns   934.2mV    1.515V     636.5mV
1.475ns   796.4mV    1.126V     612.2mV
1.872ns   773.9mV    980mV      611.2mV
2.926ns   772.4mV    945.8mV    611.7mV
50ns      772.6mV    948.6mV    611.5mV
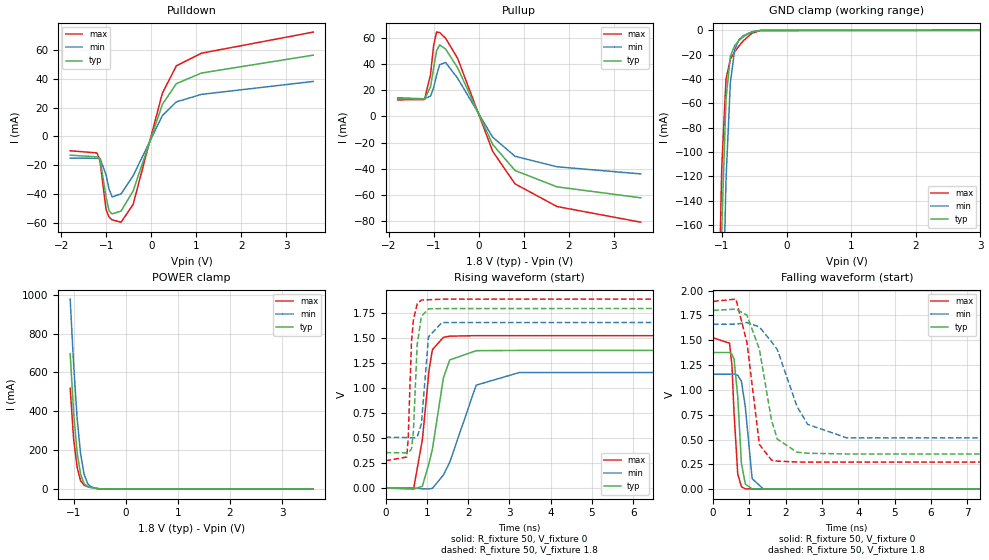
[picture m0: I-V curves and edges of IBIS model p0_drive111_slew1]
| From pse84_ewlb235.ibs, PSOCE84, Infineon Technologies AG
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[Model] p0_drive111_slew1
Model_type I/O
Polarity  Inverting
Enable   Active-High
Vinl  =  0.54
Vinh  =  1.26
Vmeas =  0.9
Cref  =  15pF
| Capacitance   typ   min   max
C_comp   1.253838e-12   1.215159e-12   1.300411e-12
| Variables   typ   min   max
[GND Clamp Reference]   0   0   0
[POWER Clamp Reference]   1.8   1.66   1.89
[Pulldown Reference]   0   0   0
[Pullup Reference]   1.8   1.66   1.89
[Temperature Range]   25   125   -40
[Voltage Range]   1.8   1.66   1.89
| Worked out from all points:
|   slope of the pulldown table from 0 to 0.27 V, typ, clamps not added: 11.4 ohm
|   slope of the pullup table from 0 to 0.27 V, typ, clamps not added: 14.3 ohm
|   GND clamp passes 1 mA (typ) near -0.51 V on its own axis
|   POWER clamp passes 1 mA (typ) near -0.47 V on its own axis
|   rising waveform, R_fixture 50, V_fixture 0: 20-80 % time 332ps typ, 528ps min, 238ps max; typ from 0 V to 1.38 V
|   rising waveform, R_fixture 50, V_fixture 1.8: 20-80 % time 97.5ps typ, 117ps min, 90.1ps max; typ from 0.355 V to 1.8 V
|   falling waveform, R_fixture 50, V_fixture 0: 20-80 % time 129ps typ, 163ps min, 111ps max; typ from 1.38 V to 0 V
|   falling waveform, R_fixture 50, V_fixture 1.8: 20-80 % time 462ps typ, 716ps min, 330ps max; typ from 1.8 V to 0.355 V
[GND Clamp]
| Voltage   I(typ)   I(min)   I(max)
-1.137V   -619.5mA   -754.2mA   -533mA
-1.07V    -361.2mA   -498.1mA   -281.3mA
-1.003V   -163.8mA   -277.7mA   -113mA
-936.6mV  -56.22mA   -122.3mA   -40.06mA
-869.7mV  -21.33mA   -43.3mA    -23.67mA
-802.8mV  -12.5mA    -15.96mA   -17.71mA
-735.9mV  -8.346mA   -7.675mA   -12.88mA
-669mV    -5.267mA   -4.349mA   -8.575mA
-535.2mV  -1.314mA   -1.207mA   -2.328mA
-401.4mV  -73.55uA   -132.2uA   -119.3uA
3.6V      0A         0A         0A
[POWER Clamp]
| Voltage   I(typ)   I(min)   I(max)
-1.07V    696.7mA    977.2mA    518.8mA
-1.003V   390.1mA    637.2mA    255.1mA
-936.6mV  187.1mA    363.9mA    112.4mA
-869.7mV  77.2mA     180.7mA    42.71mA
-802.8mV  28.89mA    77.43mA    19.98mA
-735.9mV  13.12mA    29.18mA    13.35mA
-669mV    7.754mA    11.55mA    8.954mA
-535.2mV  2.356mA    2.862mA    2.667mA
-334.5mV  34.33uA    127.4uA    15.58uA
3.6V      0A         0A         0A
[Pullup]
| Voltage   I(typ)   I(min)   I(max)
-1.8V     13.58mA    14.22mA    12.68mA
-1.204V   13.21mA    13.48mA    12.91mA
-1.07V    22.6mA     15.55mA    32.14mA
-1.003V   36.82mA    21.83mA    53.96mA
-936.6mV  50.06mA    31.34mA    64.36mA
-869.7mV  54.6mA     39.46mA    64.05mA
-735.9mV  51.43mA    41.18mA    59.68mA
-468.3mV  37.11mA    29.14mA    44.28mA
310.3mV   -21.38mA   -15.84mA   -26.61mA
806.9mV   -41.22mA   -30.4mA    -51.42mA
1.738V    -53.69mA   -38.38mA   -68.71mA
3.6V      -62.06mA   -43.83mA   -80.66mA
[Pulldown]
| Voltage   I(typ)   I(min)   I(max)
-1.8V     -12.98mA   -14.98mA   -9.917mA
-1.204V   -14.15mA   -15.23mA   -11.44mA
-1.137V   -15.69mA   -15.23mA   -17.03mA
-1.003V   -42.02mA   -26.63mA   -50.92mA
-936.6mV  -51.65mA   -36.56mA   -55.99mA
-869.7mV  -53.8mA    -41.97mA   -57.94mA
-669mV    -51.82mA   -39.89mA   -59.56mA
-401.4mV  -37.85mA   -27.29mA   -47.2mA
248.3mV   22.31mA    14.55mA    30.07mA
558.6mV   36.69mA    24.02mA    49.11mA
1.117V    44.09mA    29.25mA    57.86mA
3.6V      56.51mA    38.24mA    72.53mA
[Ramp]
dV/dt_r   0.825312/0.332092n  0.694077/0.528096n  0.914489/0.237847n
dV/dt_f   0.866985/0.462132n  0.69086/0.716304n  0.97033/0.329905n
R_load = 50
[Rising Waveform]
R_fixture = 50
V_fixture = 0
V_fixture_min = 0
V_fixture_max = 0
| Time   V(typ)   V(min)   V(max)
0s        10.34nV    743.5nV    3.708nV
681.3ps   -11.14mV   -41.6uV    -3.653mV
892.7ps   18.49mV    -7.186mV   487mV
1.054ns   250.1mV    -8.528mV   1.18V
1.135ns   388.2mV    -2.824mV   1.384V
1.401ns   1.102V     130.3mV    1.507V
1.554ns   1.281V     257.5mV    1.519V
2.195ns   1.374V     1.029V     1.524V
3.238ns   1.376V     1.155V     1.524V
50ns      1.376V     1.157V     1.524V
[Rising Waveform]
R_fixture = 50
V_fixture = 1.8
V_fixture_min = 1.66
V_fixture_max = 1.89
| Time   V(typ)   V(min)   V(max)
0s        355mV      508.6mV    272.8mV
513.1ps   351.7mV    505.1mV    310.3mV
546.7ps   352.1mV    504mV      481.8mV
628.1ps   391.1mV    502.2mV    1.462V
673.6ps   556.3mV    501.5mV    1.677V
766.1ps   1.434V     509.8mV    1.843V
867.7ps   1.717V     639.5mV    1.88V
1.041ns   1.792V     1.513V     1.883V
1.365ns   1.795V     1.655V     1.889V
50ns      1.8V       1.66V      1.89V
[Falling Waveform]
R_fixture = 50
V_fixture = 0
V_fixture_min = 0
V_fixture_max = 0
| Time   V(typ)   V(min)   V(max)
0s        1.376V     1.157V     1.524V
453.4ps   1.376V     1.157V     1.47V
520.7ps   1.359V     1.159V     1.245V
577.4ps   1.311V     1.159V     768.9mV
679.9ps   930.9mV    1.147V     152.3mV
781.6ps   259.4mV    1.085V     24.04mV
888.7ps   50.58mV    825.9mV    2.546mV
1.077ns   3.063mV    105.3mV    3.198mV
1.383ns   3.013mV    2.618mV    826.2uV
50ns      10.32nV    759.7nV    3.727nV
[Falling Waveform]
R_fixture = 50
V_fixture = 1.8
V_fixture_min = 1.66
V_fixture_max = 1.89
| Time   V(typ)   V(min)   V(max)
0s        1.8V       1.66V      1.89V
628.8ps   1.813V     1.661V     1.914V
932.8ps   1.753V     1.678V     1.48V
1.277ns   1.408V     1.633V     449.6mV
1.609ns   695.9mV    1.485V     293mV
1.769ns   504mV      1.406V     282.2mV
2.313ns   372mV      832.7mV    273.6mV
2.606ns   361.6mV    652.5mV    272.8mV
3.683ns   354.7mV    516.9mV    272.8mV
50ns      355mV      508.6mV    272.8mV
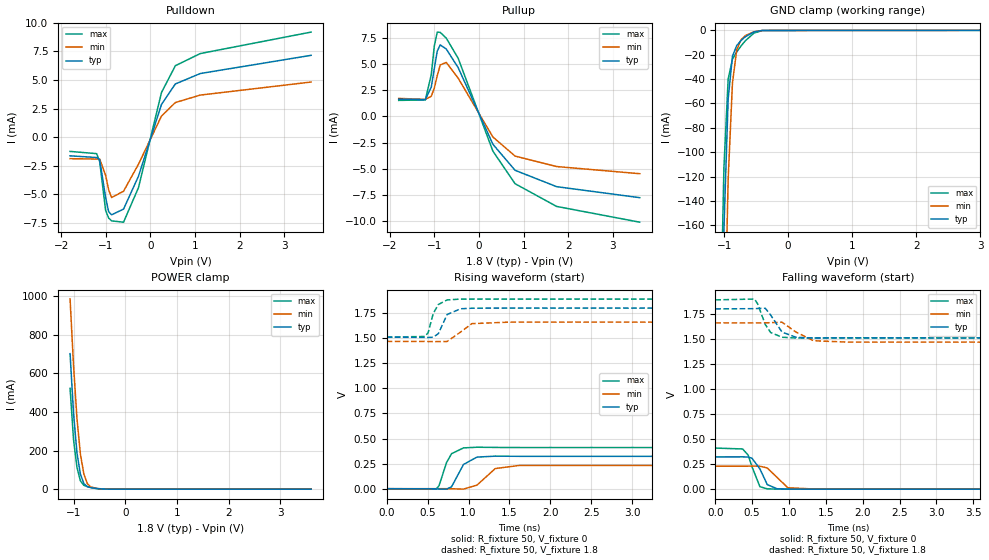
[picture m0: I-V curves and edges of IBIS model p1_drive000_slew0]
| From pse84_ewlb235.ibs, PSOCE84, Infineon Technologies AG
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| pad_1
[Model] p1_drive000_slew0
Model_type I/O
Polarity  Non-Inverting
Enable   Active-High
Vinl  =  0.54
Vinh  =  1.26
Vmeas =  0.9
Cref  =  15pF
| Capacitance   typ   min   max
C_comp   1.187163e-12   1.148471e-12   1.233738e-12
| Variables   typ   min   max
[GND Clamp Reference]   0   0   0
[POWER Clamp Reference]   1.8   1.66   1.89
[Pulldown Reference]   0   0   0
[Pullup Reference]   1.8   1.66   1.89
[Temperature Range]   25   125   -40
[Voltage Range]   1.8   1.66   1.89
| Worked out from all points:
|   slope of the pulldown table from 0 to 0.27 V, typ, clamps not added: 88.8 ohm
|   slope of the pullup table from 0 to 0.27 V, typ, clamps not added: 114 ohm
|   GND clamp passes 1 mA (typ) near -0.51 V on its own axis
|   POWER clamp passes 1 mA (typ) near -0.47 V on its own axis
|   rising waveform, R_fixture 50, V_fixture 0: 20-80 % time 130ps typ, 169ps min, 112ps max; typ from 0 V to 0.322 V
|   rising waveform, R_fixture 50, V_fixture 1.8: 20-80 % time 98.1ps typ, 113ps min, 91ps max; typ from 1.51 V to 1.8 V
|   falling waveform, R_fixture 50, V_fixture 0: 20-80 % time 117ps typ, 144ps min, 103ps max; typ from 0.322 V to 0 V
|   falling waveform, R_fixture 50, V_fixture 1.8: 20-80 % time 157ps typ, 201ps min, 132ps max; typ from 1.8 V to 1.51 V
[GND Clamp]
| Voltage   I(typ)   I(min)   I(max)
-1.137V   -618.8mA   -753.3mA   -532.4mA
-1.07V    -360.9mA   -497.6mA   -281.1mA
-1.003V   -163.7mA   -277.5mA   -113mA
-936.6mV  -56.21mA   -122.2mA   -40.06mA
-869.7mV  -21.33mA   -43.29mA   -23.66mA
-802.8mV  -12.5mA    -15.96mA   -17.71mA
-735.9mV  -8.345mA   -7.674mA   -12.88mA
-669mV    -5.267mA   -4.349mA   -8.574mA
-535.2mV  -1.314mA   -1.207mA   -2.328mA
-401.4mV  -73.55uA   -132.2uA   -119.3uA
3.6V      0A         0A         0A
[POWER Clamp]
| Voltage   I(typ)   I(min)   I(max)
-1.07V    700.8mA    983.4mA    521.5mA
-1.003V   391.6mA    640.4mA    255.8mA
-936.6mV  187.6mA    365.2mA    112.5mA
-869.7mV  77.29mA    181mA      42.73mA
-802.8mV  28.91mA    77.52mA    19.98mA
-735.9mV  13.13mA    29.19mA    13.35mA
-669mV    7.755mA    11.55mA    8.955mA
-535.2mV  2.356mA    2.862mA    2.667mA
-334.5mV  34.33uA    127.4uA    15.58uA
3.6V      0A         0A         0A
[Pullup]
| Voltage   I(typ)   I(min)   I(max)
-1.8V     1.623mA    1.701mA    1.514mA
-1.204V   1.586mA    1.615mA    1.558mA
-1.07V    2.792mA    1.908mA    3.978mA
-1.003V   4.547mA    2.688mA    6.691mA
-936.6mV  6.213mA    3.865mA    8.021mA
-869.7mV  6.802mA    4.891mA    7.992mA
-735.9mV  6.416mA    5.133mA    7.449mA
-468.3mV  4.632mA    3.634mA    5.529mA
310.3mV   -2.668mA   -1.976mA   -3.323mA
806.9mV   -5.146mA   -3.792mA   -6.424mA
1.738V    -6.706mA   -4.789mA   -8.588mA
3.6V      -7.754mA   -5.471mA   -10.09mA
[Pulldown]
| Voltage   I(typ)   I(min)   I(max)
-1.8V     -1.631mA   -1.879mA   -1.246mA
-1.204V   -1.779mA   -1.912mA   -1.44mA
-1.137V   -1.97mA    -1.911mA   -2.139mA
-1.003V   -5.282mA   -3.342mA   -6.408mA
-936.6mV  -6.5mA     -4.589mA   -7.055mA
-869.7mV  -6.777mA   -5.271mA   -7.309mA
-602.1mV  -6.281mA   -4.722mA   -7.424mA
-267.6mV  -3.414mA   -2.362mA   -4.41mA
248.3mV   2.86mA     1.843mA    3.897mA
558.6mV   4.642mA    3.02mA     6.236mA
1.117V    5.554mA    3.671mA    7.296mA
3.6V      7.142mA    4.812mA    9.171mA
[Ramp]
dV/dt_r   0.193123/0.130434n  0.137797/0.169378n  0.246037/0.111611n
dV/dt_f   0.174158/0.157211n  0.115109/0.201317n  0.227628/0.131631n
R_load = 50
[Rising Waveform]
R_fixture = 50
V_fixture = 0
V_fixture_min = 0
V_fixture_max = 0
| Time   V(typ)   V(min)   V(max)
0s        37.97nV    2.275uV    15.25nV
605.4ps   -1.439mV   -3.465uV   -3.819mV
639.9ps   -3.201mV   -13.87uV   30.35mV
732.3ps   -4.753mV   -154.3uV   261.3mV
793.2ps   19.39mV    -686.5uV   349.1mV
938.8ps   241.4mV    -4.175mV   406.5mV
1.103ns   314.8mV    35.32mV    413.3mV
1.327ns   324.3mV    200.7mV    411.3mV
1.62ns    322.7mV    231.5mV    410mV
50ns      321.9mV    229.7mV    410.1mV
[Rising Waveform]
R_fixture = 50
V_fixture = 1.8
V_fixture_min = 1.66
V_fixture_max = 1.89
| Time   V(typ)   V(min)   V(max)
0s        1.51V      1.468V     1.511V
468.3ps   1.508V     1.468V     1.517V
506.4ps   1.507V     1.467V     1.555V
569.1ps   1.51V      1.466V     1.746V
631.8ps   1.545V     1.466V     1.836V
738.2ps   1.736V     1.467V     1.881V
902.8ps   1.793V     1.561V     1.89V
1.041ns   1.799V     1.645V     1.89V
1.499ns   1.8V       1.66V      1.89V
50ns      1.8V       1.66V      1.89V
[Falling Waveform]
R_fixture = 50
V_fixture = 0
V_fixture_min = 0
V_fixture_max = 0
| Time   V(typ)   V(min)   V(max)
0s        321.9mV    229.7mV    410.1mV
370.2ps   322.8mV    229.7mV    401.6mV
446ps     320.9mV    229.8mV    339.7mV
496.9ps   308.9mV    230.5mV    224.6mV
604.8ps   202.6mV    229.1mV    24.72mV
704.5ps   45.64mV    211.8mV    3.179mV
838.2ps   3.941mV    116.7mV    568.8uV
983.9ps   754.3uV    14.36mV    129.3uV
1.366ns   54.59uV    338.9uV    100uV
50ns      37.91nV    2.319uV    15.27nV
[Falling Waveform]
R_fixture = 50
V_fixture = 1.8
V_fixture_min = 1.66
V_fixture_max = 1.89
| Time   V(typ)   V(min)   V(max)
0s        1.8V       1.66V      1.89V
532.2ps   1.802V     1.66V      1.898V
574.4ps   1.804V     1.66V      1.85V
677.5ps   1.806V     1.661V     1.644V
750.3ps   1.739V     1.662V     1.564V
904.9ps   1.568V     1.667V     1.517V
1.097ns   1.516V     1.567V     1.509V
1.332ns   1.509V     1.482V     1.51V
1.798ns   1.51V      1.468V     1.511V
50ns      1.51V      1.468V     1.511V
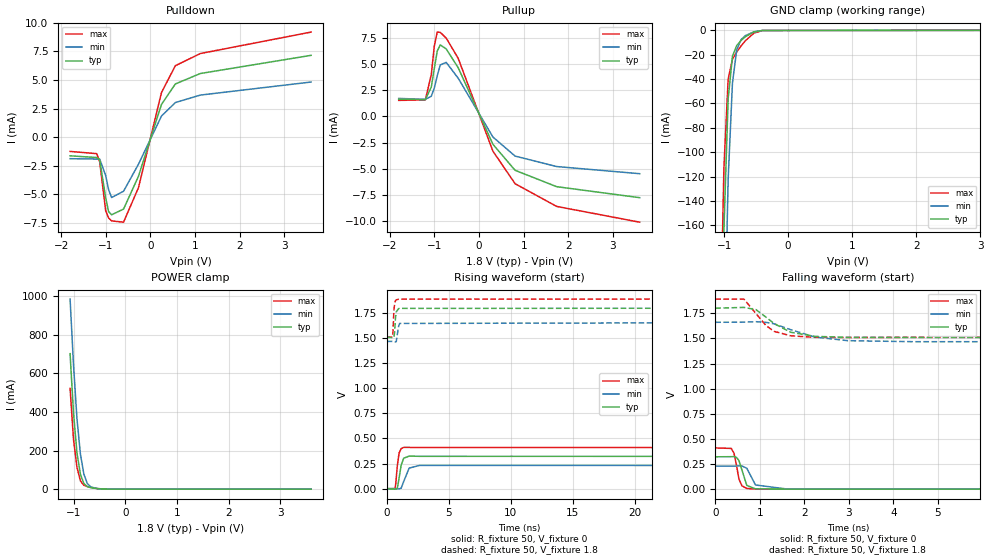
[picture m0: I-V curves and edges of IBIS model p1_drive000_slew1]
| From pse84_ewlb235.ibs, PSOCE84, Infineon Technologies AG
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[Model] p1_drive000_slew1
Model_type I/O
Polarity  Non-Inverting
Enable   Active-High
Vinl  =  0.54
Vinh  =  1.26
Vmeas =  0.9
Cref  =  15pF
| Capacitance   typ   min   max
C_comp   1.187163e-12   1.148471e-12   1.233738e-12
| Variables   typ   min   max
[GND Clamp Reference]   0   0   0
[POWER Clamp Reference]   1.8   1.66   1.89
[Pulldown Reference]   0   0   0
[Pullup Reference]   1.8   1.66   1.89
[Temperature Range]   25   125   -40
[Voltage Range]   1.8   1.66   1.89
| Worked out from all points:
|   slope of the pulldown table from 0 to 0.27 V, typ, clamps not added: 88.8 ohm
|   slope of the pullup table from 0 to 0.27 V, typ, clamps not added: 114 ohm
|   GND clamp passes 1 mA (typ) near -0.51 V on its own axis
|   POWER clamp passes 1 mA (typ) near -0.47 V on its own axis
|   rising waveform, R_fixture 50, V_fixture 0: 20-80 % time 259ps typ, 381ps min, 201ps max; typ from 0 V to 0.322 V
|   rising waveform, R_fixture 50, V_fixture 1.8: 20-80 % time 95.5ps typ, 110ps min, 89.1ps max; typ from 1.51 V to 1.8 V
|   falling waveform, R_fixture 50, V_fixture 0: 20-80 % time 117ps typ, 144ps min, 105ps max; typ from 0.322 V to 0 V
|   falling waveform, R_fixture 50, V_fixture 1.8: 20-80 % time 595ps typ, 842ps min, 448ps max; typ from 1.8 V to 1.51 V
[GND Clamp]
| Voltage   I(typ)   I(min)   I(max)
-1.137V   -618.8mA   -753.3mA   -532.4mA
-1.07V    -360.9mA   -497.6mA   -281.1mA
-1.003V   -163.7mA   -277.5mA   -113mA
-936.6mV  -56.21mA   -122.2mA   -40.06mA
-869.7mV  -21.33mA   -43.29mA   -23.66mA
-802.8mV  -12.5mA    -15.96mA   -17.71mA
-735.9mV  -8.345mA   -7.674mA   -12.88mA
-669mV    -5.267mA   -4.349mA   -8.574mA
-535.2mV  -1.314mA   -1.207mA   -2.328mA
-401.4mV  -73.55uA   -132.2uA   -119.3uA
3.6V      0A         0A         0A
[POWER Clamp]
| Voltage   I(typ)   I(min)   I(max)
-1.07V    700.8mA    983.4mA    521.5mA
-1.003V   391.6mA    640.4mA    255.8mA
-936.6mV  187.6mA    365.2mA    112.5mA
-869.7mV  77.29mA    181mA      42.73mA
-802.8mV  28.91mA    77.52mA    19.98mA
-735.9mV  13.13mA    29.19mA    13.35mA
-669mV    7.755mA    11.55mA    8.955mA
-535.2mV  2.356mA    2.862mA    2.667mA
-334.5mV  34.33uA    127.4uA    15.58uA
3.6V      0A         0A         0A
[Pullup]
| Voltage   I(typ)   I(min)   I(max)
-1.8V     1.623mA    1.701mA    1.514mA
-1.204V   1.586mA    1.615mA    1.558mA
-1.07V    2.792mA    1.908mA    3.978mA
-1.003V   4.547mA    2.688mA    6.691mA
-936.6mV  6.213mA    3.865mA    8.021mA
-869.7mV  6.802mA    4.891mA    7.992mA
-735.9mV  6.416mA    5.133mA    7.449mA
-468.3mV  4.632mA    3.634mA    5.529mA
310.3mV   -2.668mA   -1.976mA   -3.323mA
806.9mV   -5.146mA   -3.792mA   -6.424mA
1.738V    -6.706mA   -4.789mA   -8.588mA
3.6V      -7.754mA   -5.471mA   -10.09mA
[Pulldown]
| Voltage   I(typ)   I(min)   I(max)
-1.8V     -1.631mA   -1.879mA   -1.246mA
-1.204V   -1.779mA   -1.912mA   -1.44mA
-1.137V   -1.97mA    -1.911mA   -2.139mA
-1.003V   -5.282mA   -3.342mA   -6.408mA
-936.6mV  -6.5mA     -4.589mA   -7.055mA
-869.7mV  -6.777mA   -5.271mA   -7.309mA
-602.1mV  -6.281mA   -4.722mA   -7.424mA
-267.6mV  -3.414mA   -2.362mA   -4.41mA
248.3mV   2.86mA     1.843mA    3.897mA
558.6mV   4.642mA    3.02mA     6.236mA
1.117V    5.554mA    3.671mA    7.296mA
3.6V      7.142mA    4.812mA    9.171mA
[Ramp]
dV/dt_r   0.193123/0.259106n  0.137796/0.381487n  0.246037/0.201284n
dV/dt_f   0.174158/0.595016n  0.115109/0.841851n  0.227628/0.448428n
R_load = 50
[Rising Waveform]
R_fixture = 50
V_fixture = 0
V_fixture_min = 0
V_fixture_max = 0
| Time   V(typ)   V(min)   V(max)
0s        37.97nV    2.275uV    15.25nV
667.7ps   -5.15mV    -2.704uV   627.1uV
732.8ps   -3.772mV   -138.3uV   51.05mV
861.5ps   7.072mV    -2.378mV   232mV
1.001ns   104.7mV    -2.182mV   355.6mV
1.165ns   233mV      4.116mV    399.3mV
1.375ns   303.7mV    72.26mV    411.5mV
1.811ns   324.5mV    204.8mV    411.3mV
2.67ns    322.3mV    232.2mV    409.9mV
50ns      321.9mV    229.7mV    410.1mV
[Rising Waveform]
R_fixture = 50
V_fixture = 1.8
V_fixture_min = 1.66
V_fixture_max = 1.89
| Time   V(typ)   V(min)   V(max)
0s        1.51V      1.468V     1.511V
464.2ps   1.505V     1.468V     1.511V
507.7ps   1.504V     1.466V     1.559V
580.1ps   1.507V     1.465V     1.774V
643.3ps   1.561V     1.463V     1.846V
707.2ps   1.7V       1.462V     1.872V
769.5ps   1.761V     1.465V     1.882V
958.4ps   1.795V     1.616V     1.888V
1.048ns   1.797V     1.647V     1.889V
50ns      1.8V       1.66V      1.89V
[Falling Waveform]
R_fixture = 50
V_fixture = 0
V_fixture_min = 0
V_fixture_max = 0
| Time   V(typ)   V(min)   V(max)
0s        321.9mV    229.7mV    410.1mV
359ps     323.1mV    229.6mV    405.5mV
420.5ps   324.3mV    229.6mV    356.7mV
477.8ps   315.1mV    230.6mV    233.9mV
531ps     284.1mV    231.7mV    101.1mV
598.4ps   190.8mV    230.9mV    33.07mV
707.9ps   36.99mV    208mV      6.883mV
902.6ps   3.294mV    41.79mV    972.4uV
1.633ns   257.3uV    374.7uV    168uV
50ns      37.91nV    2.278uV    15.3nV
[Falling Waveform]
R_fixture = 50
V_fixture = 1.8
V_fixture_min = 1.66
V_fixture_max = 1.89
| Time   V(typ)   V(min)   V(max)
0s        1.8V       1.66V      1.89V
642.1ps   1.808V     1.661V     1.891V
912.8ps   1.786V     1.666V     1.747V
1.142ns   1.71V      1.659V     1.626V
1.319ns   1.648V     1.645V     1.57V
1.691ns   1.561V     1.587V     1.526V
2.24ns    1.52V      1.513V     1.51V
2.98ns    1.51V      1.477V     1.509V
4.45ns    1.509V     1.467V     1.51V
50ns      1.51V      1.468V     1.511V
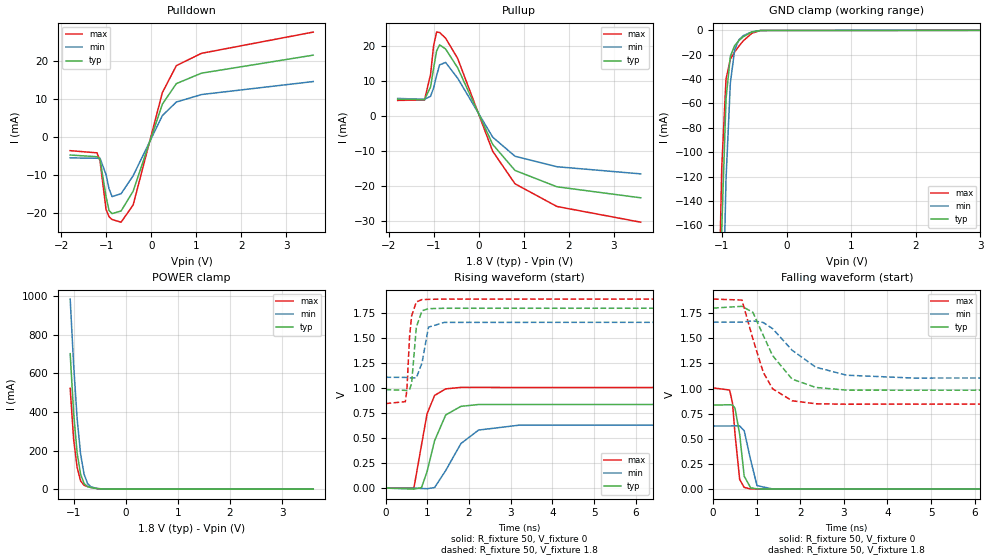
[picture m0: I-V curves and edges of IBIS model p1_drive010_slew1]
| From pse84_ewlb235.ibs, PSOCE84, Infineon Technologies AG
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[Model] p1_drive010_slew1
Model_type I/O
Polarity  Non-Inverting
Enable   Active-High
Vinl  =  0.54
Vinh  =  1.26
Vmeas =  0.9
Cref  =  15pF
| Capacitance   typ   min   max
C_comp   1.187163e-12   1.148471e-12   1.233738e-12
| Variables   typ   min   max
[GND Clamp Reference]   0   0   0
[POWER Clamp Reference]   1.8   1.66   1.89
[Pulldown Reference]   0   0   0
[Pullup Reference]   1.8   1.66   1.89
[Temperature Range]   25   125   -40
[Voltage Range]   1.8   1.66   1.89
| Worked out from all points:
|   slope of the pulldown table from 0 to 0.27 V, typ, clamps not added: 29.8 ohm
|   slope of the pullup table from 0 to 0.27 V, typ, clamps not added: 38.1 ohm
|   GND clamp passes 1 mA (typ) near -0.51 V on its own axis
|   POWER clamp passes 1 mA (typ) near -0.47 V on its own axis
|   rising waveform, R_fixture 50, V_fixture 0: 20-80 % time 350ps typ, 551ps min, 253ps max; typ from 0 V to 0.836 V
|   rising waveform, R_fixture 50, V_fixture 1.8: 20-80 % time 96.5ps typ, 113ps min, 88.7ps max; typ from 0.985 V to 1.8 V
|   falling waveform, R_fixture 50, V_fixture 0: 20-80 % time 121ps typ, 150ps min, 107ps max; typ from 0.836 V to 0 V
|   falling waveform, R_fixture 50, V_fixture 1.8: 20-80 % time 615ps typ, 857ps min, 469ps max; typ from 1.8 V to 0.985 V
[GND Clamp]
| Voltage   I(typ)   I(min)   I(max)
-1.137V   -618.8mA   -753.3mA   -532.4mA
-1.07V    -360.9mA   -497.6mA   -281.1mA
-1.003V   -163.7mA   -277.5mA   -113mA
-936.6mV  -56.21mA   -122.2mA   -40.06mA
-869.7mV  -21.33mA   -43.29mA   -23.66mA
-802.8mV  -12.5mA    -15.96mA   -17.71mA
-735.9mV  -8.345mA   -7.674mA   -12.88mA
-669mV    -5.267mA   -4.349mA   -8.574mA
-535.2mV  -1.314mA   -1.207mA   -2.328mA
-401.4mV  -73.55uA   -132.2uA   -119.3uA
3.6V      0A         0A         0A
[POWER Clamp]
| Voltage   I(typ)   I(min)   I(max)
-1.07V    700.8mA    983.4mA    521.5mA
-1.003V   391.6mA    640.4mA    255.8mA
-936.6mV  187.6mA    365.2mA    112.5mA
-869.7mV  77.29mA    181mA      42.73mA
-802.8mV  28.91mA    77.52mA    19.98mA
-735.9mV  13.13mA    29.19mA    13.35mA
-669mV    7.755mA    11.55mA    8.955mA
-535.2mV  2.356mA    2.862mA    2.667mA
-334.5mV  34.33uA    127.4uA    15.58uA
3.6V      0A         0A         0A
[Pullup]
| Voltage   I(typ)   I(min)   I(max)
-1.8V     4.891mA    5.128mA    4.561mA
-1.204V   4.768mA    4.867mA    4.68mA
-1.07V    8.4mA      5.737mA    11.97mA
-1.003V   13.68mA    8.09mA     20.12mA
-936.6mV  18.66mA    11.63mA    24.06mA
-869.7mV  20.41mA    14.7mA     23.96mA
-735.9mV  19.24mA    15.4mA     22.32mA
-468.3mV  13.88mA    10.9mA     16.56mA
310.3mV   -7.998mA   -5.929mA   -9.953mA
806.9mV   -15.43mA   -11.38mA   -19.25mA
1.738V    -20.1mA    -14.37mA   -25.72mA
3.6V      -23.24mA   -16.41mA   -30.2mA
[Pulldown]
| Voltage   I(typ)   I(min)   I(max)
-1.8V     -4.873mA   -5.622mA   -3.722mA
-1.204V   -5.316mA   -5.72mA    -4.296mA
-1.137V   -5.907mA   -5.72mA    -6.41mA
-1.003V   -15.83mA   -10.02mA   -19.18mA
-936.6mV  -19.47mA   -13.76mA   -21.1mA
-869.7mV  -20.29mA   -15.81mA   -21.85mA
-669mV    -19.6mA    -15.06mA   -22.55mA
-401.4mV  -14.4mA    -10.33mA   -18.03mA
248.3mV   8.526mA    5.522mA    11.56mA
558.6mV   13.92mA    9.081mA    18.66mA
1.117V    16.68mA    11.05mA    21.9mA
3.6V      21.42mA    14.47mA    27.49mA
[Ramp]
dV/dt_r   0.501484/0.349577n  0.376795/0.550877n  0.603978/0.253192n
dV/dt_f   0.489298/0.615008n  0.331002/0.857058n  0.626792/0.468615n
R_load = 50
[Rising Waveform]
R_fixture = 50
V_fixture = 0
V_fixture_min = 0
V_fixture_max = 0
| Time   V(typ)   V(min)   V(max)
0s        21.31nV    1.424uV    7.959nV
679.7ps   -10.6mV    -12.68uV   2.328mV
862ps     5.9mV      -4.051mV   432.8mV
994.3ps   163.9mV    -6.003mV   741.7mV
1.175ns   474.2mV    5.485mV    927mV
1.442ns   731.6mV    176.4mV    992.2mV
1.805ns   817.1mV    445.1mV    1.007V
2.229ns   836mV      580.3mV    1.007V
3.203ns   836.1mV    629.3mV    1.006V
50ns      835.8mV    628mV      1.007V
[Rising Waveform]
R_fixture = 50
V_fixture = 1.8
V_fixture_min = 1.66
V_fixture_max = 1.89
| Time   V(typ)   V(min)   V(max)
0s        984.5mV    1.108V     845.3mV
473.8ps   977.3mV    1.107V     864.2mV
511.5ps   976mV      1.105V     980.9mV
574.9ps   983.3mV    1.103V     1.512V
625.5ps   1.051V     1.101V     1.724V
737.9ps   1.611V     1.102V     1.861V
874.2ps   1.773V     1.252V     1.885V
1.028ns   1.794V     1.609V     1.887V
1.408ns   1.798V     1.657V     1.89V
50ns      1.8V       1.66V      1.89V
[Falling Waveform]
R_fixture = 50
V_fixture = 0
V_fixture_min = 0
V_fixture_max = 0
| Time   V(typ)   V(min)   V(max)
0s        835.8mV    628mV      1.007V
379.7ps   839.1mV    627.9mV    985.4mV
446.7ps   836.3mV    628.6mV    853.6mV
503.2ps   805.3mV    630.8mV    549.2mV
610.4ps   543.8mV    628.5mV    96.15mV
713.7ps   128.7mV    580.4mV    17.52mV
861.2ps   13.87mV    291.7mV    1.88mV
1.008ns   2.712mV    35.14mV    1.189mV
1.368ns   738.9uV    1.688mV    447.1uV
50ns      21.29nV    1.427uV    7.938nV
[Falling Waveform]
R_fixture = 50
V_fixture = 1.8
V_fixture_min = 1.66
V_fixture_max = 1.89
| Time   V(typ)   V(min)   V(max)
0s        1.8V       1.66V      1.89V
661.7ps   1.818V     1.661V     1.88V
915.2ps   1.757V     1.674V     1.492V
1.151ns   1.529V     1.657V     1.162V
1.365ns   1.328V     1.596V     998.2mV
1.813ns   1.094V     1.381V     878.7mV
2.358ns   1.011V     1.212V     848.8mV
3.066ns   984.5mV    1.133V     844.7mV
4.579ns   983.9mV    1.105V     845.4mV
50ns      984.5mV    1.108V     845.3mV
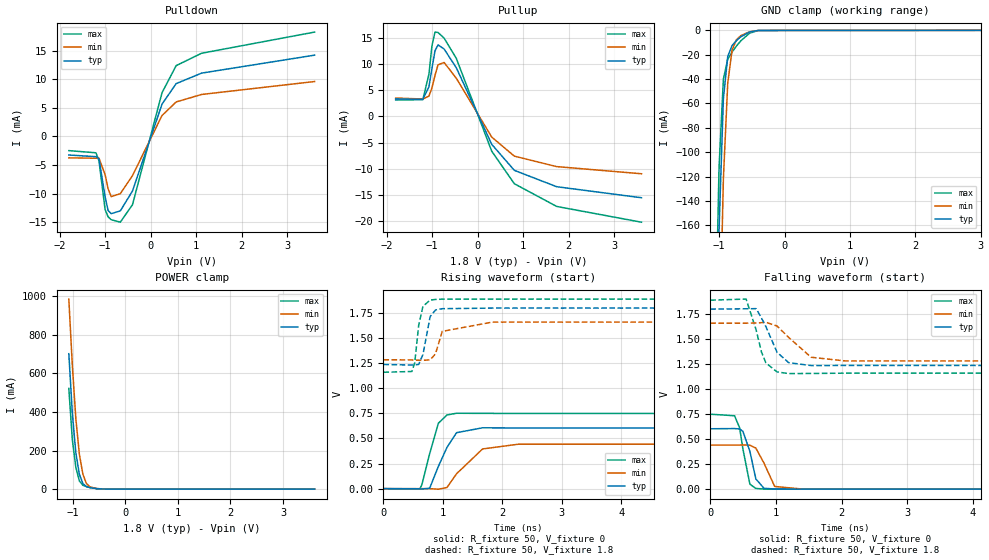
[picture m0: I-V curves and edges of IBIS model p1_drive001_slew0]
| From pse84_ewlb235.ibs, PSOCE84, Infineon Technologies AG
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[Model] p1_drive001_slew0
Model_type I/O
Polarity  Non-Inverting
Enable   Active-High
Vinl  =  0.54
Vinh  =  1.26
Vmeas =  0.9
Cref  =  15pF
| Capacitance   typ   min   max
C_comp   1.187163e-12   1.148471e-12   1.233738e-12
| Variables   typ   min   max
[GND Clamp Reference]   0   0   0
[POWER Clamp Reference]   1.8   1.66   1.89
[Pulldown Reference]   0   0   0
[Pullup Reference]   1.8   1.66   1.89
[Temperature Range]   25   125   -40
[Voltage Range]   1.8   1.66   1.89
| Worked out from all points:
|   slope of the pulldown table from 0 to 0.27 V, typ, clamps not added: 45 ohm
|   slope of the pullup table from 0 to 0.27 V, typ, clamps not added: 57.2 ohm
|   GND clamp passes 1 mA (typ) near -0.51 V on its own axis
|   POWER clamp passes 1 mA (typ) near -0.47 V on its own axis
|   rising waveform, R_fixture 50, V_fixture 0: 20-80 % time 268ps typ, 404ps min, 199ps max; typ from 0 V to 0.604 V
|   rising waveform, R_fixture 50, V_fixture 1.8: 20-80 % time 99.2ps typ, 117ps min, 90ps max; typ from 1.24 V to 1.8 V
|   falling waveform, R_fixture 50, V_fixture 0: 20-80 % time 118ps typ, 146ps min, 105ps max; typ from 0.604 V to 0 V
|   falling waveform, R_fixture 50, V_fixture 1.8: 20-80 % time 239ps typ, 338ps min, 182ps max; typ from 1.8 V to 1.24 V
[GND Clamp]
| Voltage   I(typ)   I(min)   I(max)
-1.137V   -618.8mA   -753.3mA   -532.4mA
-1.07V    -360.9mA   -497.6mA   -281.1mA
-1.003V   -163.7mA   -277.5mA   -113mA
-936.6mV  -56.21mA   -122.2mA   -40.06mA
-869.7mV  -21.33mA   -43.29mA   -23.66mA
-802.8mV  -12.5mA    -15.96mA   -17.71mA
-735.9mV  -8.345mA   -7.674mA   -12.88mA
-669mV    -5.267mA   -4.349mA   -8.574mA
-535.2mV  -1.314mA   -1.207mA   -2.328mA
-401.4mV  -73.55uA   -132.2uA   -119.3uA
3.6V      0A         0A         0A
[POWER Clamp]
| Voltage   I(typ)   I(min)   I(max)
-1.07V    700.8mA    983.4mA    521.5mA
-1.003V   391.6mA    640.4mA    255.8mA
-936.6mV  187.6mA    365.2mA    112.5mA
-869.7mV  77.29mA    181mA      42.73mA
-802.8mV  28.91mA    77.52mA    19.98mA
-735.9mV  13.13mA    29.19mA    13.35mA
-669mV    7.755mA    11.55mA    8.955mA
-535.2mV  2.356mA    2.862mA    2.667mA
-334.5mV  34.33uA    127.4uA    15.58uA
3.6V      0A         0A         0A
[Pullup]
| Voltage   I(typ)   I(min)   I(max)
-1.8V     3.33mA     3.487mA    3.109mA
-1.204V   3.246mA    3.307mA    3.179mA
-1.07V    5.626mA    3.856mA    8.016mA
-1.003V   9.164mA    5.422mA    13.46mA
-936.6mV  12.48mA    7.789mA    16.06mA
-869.7mV  13.62mA    9.822mA    15.99mA
-735.9mV  12.83mA    10.27mA    14.9mA
-468.3mV  9.261mA    7.267mA    11.05mA
310.3mV   -5.334mA   -3.951mA   -6.643mA
806.9mV   -10.29mA   -7.584mA   -12.84mA
1.738V    -13.41mA   -9.579mA   -17.17mA
3.6V      -15.51mA   -10.94mA   -20.17mA
[Pulldown]
| Voltage   I(typ)   I(min)   I(max)
-1.8V     -3.249mA   -3.746mA   -2.482mA
-1.204V   -3.542mA   -3.81mA    -2.865mA
-1.137V   -3.931mA   -3.809mA   -4.268mA
-1.003V   -10.53mA   -6.669mA   -12.77mA
-936.6mV  -12.95mA   -9.157mA   -14.05mA
-869.7mV  -13.5mA    -10.52mA   -14.55mA
-669mV    -13.02mA   -10.01mA   -14.99mA
-401.4mV  -9.547mA   -6.857mA   -11.94mA
248.3mV   5.644mA    3.66mA     7.643mA
558.6mV   9.226mA    6.023mA    12.37mA
1.117V    11.06mA    7.329mA    14.53mA
3.6V      14.2mA     9.592mA    18.23mA
[Ramp]
dV/dt_r   0.362419/0.267804n  0.264509/0.403741n  0.449864/0.19934n
dV/dt_f   0.337395/0.238796n  0.225199/0.338361n  0.438127/0.181918n
R_load = 50
[Rising Waveform]
R_fixture = 50
V_fixture = 0
V_fixture_min = 0
V_fixture_max = 0
| Time   V(typ)   V(min)   V(max)
0s        27.48nV    1.757uV    10.56nV
612.1ps   -1.577mV   2.57uV     -4.912mV
647.7ps   -3.451mV   -9.979uV   41.24mV
777.5ps   3.287mV    -455uV     348mV
923.8ps   221.5mV    -5.387mV   651.7mV
1.068ns   410.6mV    11.05mV    734.6mV
1.229ns   557.7mV    147.9mV    751.5mV
1.667ns   606.6mV    395.6mV    750.5mV
2.272ns   604.6mV    443.1mV    749.5mV
50ns      604mV      440.9mV    749.8mV
[Rising Waveform]
R_fixture = 50
V_fixture = 1.8
V_fixture_min = 1.66
V_fixture_max = 1.89
| Time   V(typ)   V(min)   V(max)
0s        1.238V     1.285V     1.16V
479ps     1.232V     1.283V     1.168V
526.3ps   1.231V     1.281V     1.254V
593ps     1.239V     1.28V      1.628V
664.8ps   1.337V     1.279V     1.818V
786.2ps   1.716V     1.284V     1.88V
875.6ps   1.781V     1.344V     1.886V
989.1ps   1.794V     1.568V     1.889V
1.828ns   1.8V       1.66V      1.89V
50ns      1.8V       1.66V      1.89V
[Falling Waveform]
R_fixture = 50
V_fixture = 0
V_fixture_min = 0
V_fixture_max = 0
| Time   V(typ)   V(min)   V(max)
0s        604mV      440.9mV    749.8mV
370.2ps   605.8mV    440.8mV    734mV
446.9ps   601.8mV    441.2mV    614.4mV
496.9ps   578.6mV    442.4mV    403.2mV
604ps     377.6mV    439.7mV    49.68mV
694.2ps   102.6mV    410.9mV    7.35mV
818.1ps   8.83mV     260.9mV    1.24mV
981.7ps   1.678mV    26.99mV    271.6uV
1.411ns   119.9uV    779.7uV    124uV
50ns      27.41nV    1.825uV    10.62nV
[Falling Waveform]
R_fixture = 50
V_fixture = 1.8
V_fixture_min = 1.66
V_fixture_max = 1.89
| Time   V(typ)   V(min)   V(max)
0s        1.8V       1.66V      1.89V
545.9ps   1.804V     1.66V      1.901V
698.3ps   1.805V     1.662V     1.594V
779.7ps   1.712V     1.665V     1.372V
847.2ps   1.626V     1.669V     1.263V
1.018ns   1.368V     1.631V     1.172V
1.195ns   1.265V     1.517V     1.156V
1.537ns   1.236V     1.319V     1.157V
2.06ns    1.237V     1.282V     1.16V
50ns      1.238V     1.285V     1.16V
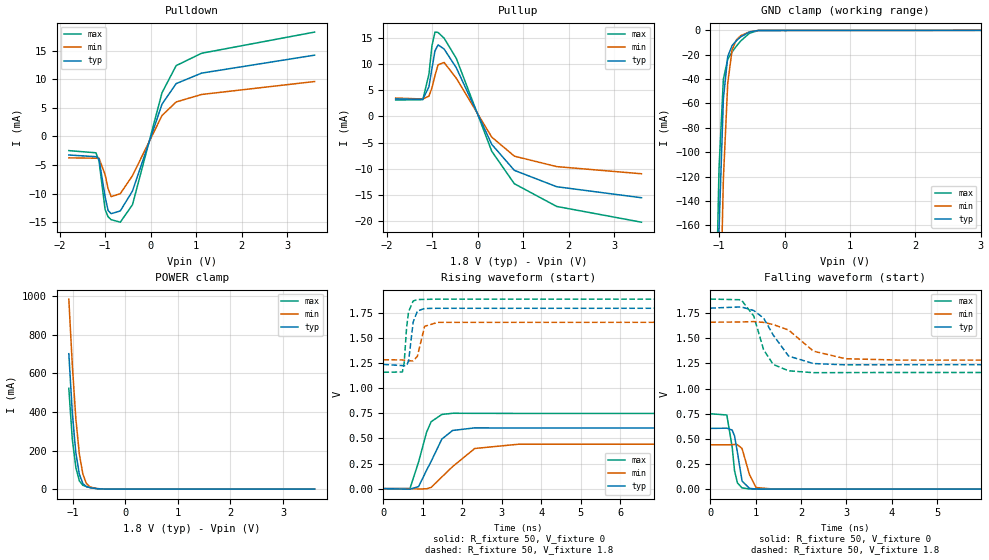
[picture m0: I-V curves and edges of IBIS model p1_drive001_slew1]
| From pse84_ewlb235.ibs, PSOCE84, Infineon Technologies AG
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[Model] p1_drive001_slew1
Model_type I/O
Polarity  Non-Inverting
Enable   Active-High
Vinl  =  0.54
Vinh  =  1.26
Vmeas =  0.9
Cref  =  15pF
| Capacitance   typ   min   max
C_comp   1.187163e-12   1.148471e-12   1.233738e-12
| Variables   typ   min   max
[GND Clamp Reference]   0   0   0
[POWER Clamp Reference]   1.8   1.66   1.89
[Pulldown Reference]   0   0   0
[Pullup Reference]   1.8   1.66   1.89
[Temperature Range]   25   125   -40
[Voltage Range]   1.8   1.66   1.89
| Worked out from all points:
|   slope of the pulldown table from 0 to 0.27 V, typ, clamps not added: 45 ohm
|   slope of the pullup table from 0 to 0.27 V, typ, clamps not added: 57.2 ohm
|   GND clamp passes 1 mA (typ) near -0.51 V on its own axis
|   POWER clamp passes 1 mA (typ) near -0.47 V on its own axis
|   rising waveform, R_fixture 50, V_fixture 0: 20-80 % time 444ps typ, 686ps min, 323ps max; typ from 0 V to 0.604 V
|   rising waveform, R_fixture 50, V_fixture 1.8: 20-80 % time 98.3ps typ, 115ps min, 90.8ps max; typ from 1.24 V to 1.8 V
|   falling waveform, R_fixture 50, V_fixture 0: 20-80 % time 117ps typ, 145ps min, 105ps max; typ from 0.604 V to 0 V
|   falling waveform, R_fixture 50, V_fixture 1.8: 20-80 % time 441ps typ, 622ps min, 339ps max; typ from 1.8 V to 1.24 V
[GND Clamp]
| Voltage   I(typ)   I(min)   I(max)
-1.137V   -618.8mA   -753.3mA   -532.4mA
-1.07V    -360.9mA   -497.6mA   -281.1mA
-1.003V   -163.7mA   -277.5mA   -113mA
-936.6mV  -56.21mA   -122.2mA   -40.06mA
-869.7mV  -21.33mA   -43.29mA   -23.66mA
-802.8mV  -12.5mA    -15.96mA   -17.71mA
-735.9mV  -8.345mA   -7.674mA   -12.88mA
-669mV    -5.267mA   -4.349mA   -8.574mA
-535.2mV  -1.314mA   -1.207mA   -2.328mA
-401.4mV  -73.55uA   -132.2uA   -119.3uA
3.6V      0A         0A         0A
[POWER Clamp]
| Voltage   I(typ)   I(min)   I(max)
-1.07V    700.8mA    983.4mA    521.5mA
-1.003V   391.6mA    640.4mA    255.8mA
-936.6mV  187.6mA    365.2mA    112.5mA
-869.7mV  77.29mA    181mA      42.73mA
-802.8mV  28.91mA    77.52mA    19.98mA
-735.9mV  13.13mA    29.19mA    13.35mA
-669mV    7.755mA    11.55mA    8.955mA
-535.2mV  2.356mA    2.862mA    2.667mA
-334.5mV  34.33uA    127.4uA    15.58uA
3.6V      0A         0A         0A
[Pullup]
| Voltage   I(typ)   I(min)   I(max)
-1.8V     3.33mA     3.487mA    3.109mA
-1.204V   3.246mA    3.307mA    3.179mA
-1.07V    5.626mA    3.856mA    8.016mA
-1.003V   9.164mA    5.422mA    13.46mA
-936.6mV  12.48mA    7.789mA    16.06mA
-869.7mV  13.62mA    9.822mA    15.99mA
-735.9mV  12.83mA    10.27mA    14.9mA
-468.3mV  9.261mA    7.267mA    11.05mA
310.3mV   -5.334mA   -3.951mA   -6.643mA
806.9mV   -10.29mA   -7.584mA   -12.84mA
1.738V    -13.41mA   -9.579mA   -17.17mA
3.6V      -15.51mA   -10.94mA   -20.17mA
[Pulldown]
| Voltage   I(typ)   I(min)   I(max)
-1.8V     -3.249mA   -3.746mA   -2.482mA
-1.204V   -3.542mA   -3.81mA    -2.865mA
-1.137V   -3.931mA   -3.809mA   -4.268mA
-1.003V   -10.53mA   -6.669mA   -12.77mA
-936.6mV  -12.95mA   -9.157mA   -14.05mA
-869.7mV  -13.5mA    -10.52mA   -14.55mA
-669mV    -13.02mA   -10.01mA   -14.99mA
-401.4mV  -9.547mA   -6.857mA   -11.94mA
248.3mV   5.644mA    3.66mA     7.643mA
558.6mV   9.226mA    6.023mA    12.37mA
1.117V    11.06mA    7.329mA    14.53mA
3.6V      14.2mA     9.592mA    18.23mA
[Ramp]
dV/dt_r   0.362419/0.444098n  0.264506/0.686237n  0.449864/0.323484n
dV/dt_f   0.337395/0.440893n  0.225198/0.622126n  0.438127/0.338532n
R_load = 50
[Rising Waveform]
R_fixture = 50
V_fixture = 0
V_fixture_min = 0
V_fixture_max = 0
| Time   V(typ)   V(min)   V(max)
0s        27.48nV    1.757uV    10.56nV
673ps     -5.499mV   9.355uV    908.4uV
891.9ps   19.82mV    -3.539mV   266.3mV
1.094ns   183.2mV    -1.87mV    562mV
1.21ns    272mV      12.39mV    667.3mV
1.481ns   494mV      115.9mV    739.5mV
1.754ns   579.8mV    219.9mV    751.3mV
2.314ns   605.6mV    400mV      750.8mV
3.425ns   604.4mV    442.7mV    749.6mV
50ns      604mV      440.8mV    749.8mV
[Rising Waveform]
R_fixture = 50
V_fixture = 1.8
V_fixture_min = 1.66
V_fixture_max = 1.89
| Time   V(typ)   V(min)   V(max)
0s        1.238V     1.285V     1.16V
480.8ps   1.227V     1.283V     1.163V
526.6ps   1.225V     1.28V      1.255V
586.8ps   1.228V     1.277V     1.602V
637.9ps   1.27V      1.275V     1.764V
754.3ps   1.66V      1.273V     1.871V
861.4ps   1.771V     1.32V      1.885V
1.044ns   1.796V     1.618V     1.887V
1.378ns   1.798V     1.658V     1.889V
50ns      1.8V       1.66V      1.89V
[Falling Waveform]
R_fixture = 50
V_fixture = 0
V_fixture_min = 0
V_fixture_max = 0
| Time   V(typ)   V(min)   V(max)
0s        604mV      440.8mV    749.8mV
364.7ps   606.4mV    440.8mV    737.4mV
482.8ps   587.7mV    442.6mV    418.2mV
534.5ps   529.7mV    444.3mV    183.5mV
598.6ps   365.7mV    442.2mV    62.58mV
700.4ps   80.75mV    404.5mV    12.74mV
865.1ps   7.122mV    143.4mV    1.64mV
1.008ns   1.876mV    16.28mV    2.469mV
1.398ns   1.201mV    857.6uV    466.3uV
50ns      27.42nV    1.761uV    10.55nV
[Falling Waveform]
R_fixture = 50
V_fixture = 1.8
V_fixture_min = 1.66
V_fixture_max = 1.89
| Time   V(typ)   V(min)   V(max)
0s        1.8V       1.66V      1.89V
681.7ps   1.812V     1.662V     1.883V
959.1ps   1.776V     1.666V     1.721V
1.176ns   1.7V       1.658V     1.386V
1.387ns   1.533V     1.637V     1.24V
1.726ns   1.323V     1.582V     1.177V
2.274ns   1.249V     1.372V     1.158V
2.98ns    1.236V     1.297V     1.159V
4.169ns   1.237V     1.283V     1.16V
50ns      1.238V     1.285V     1.16V
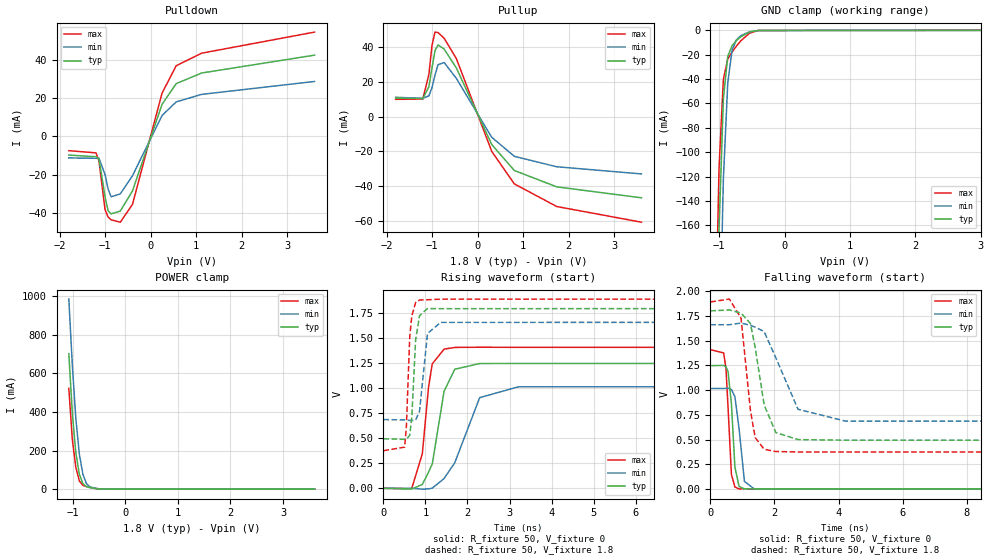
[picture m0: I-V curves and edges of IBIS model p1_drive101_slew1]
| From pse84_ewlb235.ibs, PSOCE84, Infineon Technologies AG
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[Model] p1_drive101_slew1
Model_type I/O
Polarity  Non-Inverting
Enable   Active-High
Vinl  =  0.54
Vinh  =  1.26
Vmeas =  0.9
Cref  =  15pF
| Capacitance   typ   min   max
C_comp   1.187163e-12   1.148471e-12   1.233738e-12
| Variables   typ   min   max
[GND Clamp Reference]   0   0   0
[POWER Clamp Reference]   1.8   1.66   1.89
[Pulldown Reference]   0   0   0
[Pullup Reference]   1.8   1.66   1.89
[Temperature Range]   25   125   -40
[Voltage Range]   1.8   1.66   1.89
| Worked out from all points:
|   slope of the pulldown table from 0 to 0.27 V, typ, clamps not added: 15.1 ohm
|   slope of the pullup table from 0 to 0.27 V, typ, clamps not added: 19 ohm
|   GND clamp passes 1 mA (typ) near -0.51 V on its own axis
|   POWER clamp passes 1 mA (typ) near -0.47 V on its own axis
|   rising waveform, R_fixture 50, V_fixture 0: 20-80 % time 295ps typ, 484ps min, 206ps max; typ from 0 V to 1.25 V
|   rising waveform, R_fixture 50, V_fixture 1.8: 20-80 % time 96.8ps typ, 117ps min, 87.7ps max; typ from 0.495 V to 1.8 V
|   falling waveform, R_fixture 50, V_fixture 0: 20-80 % time 132ps typ, 171ps min, 112ps max; typ from 1.25 V to 0 V
|   falling waveform, R_fixture 50, V_fixture 1.8: 20-80 % time 404ps typ, 637ps min, 272ps max; typ from 1.8 V to 0.495 V
[GND Clamp]
| Voltage   I(typ)   I(min)   I(max)
-1.137V   -618.8mA   -753.3mA   -532.4mA
-1.07V    -360.9mA   -497.6mA   -281.1mA
-1.003V   -163.7mA   -277.5mA   -113mA
-936.6mV  -56.21mA   -122.2mA   -40.06mA
-869.7mV  -21.33mA   -43.29mA   -23.66mA
-802.8mV  -12.5mA    -15.96mA   -17.71mA
-735.9mV  -8.345mA   -7.674mA   -12.88mA
-669mV    -5.267mA   -4.349mA   -8.574mA
-535.2mV  -1.314mA   -1.207mA   -2.328mA
-401.4mV  -73.55uA   -132.2uA   -119.3uA
3.6V      0A         0A         0A
[POWER Clamp]
| Voltage   I(typ)   I(min)   I(max)
-1.07V    700.8mA    983.4mA    521.5mA
-1.003V   391.6mA    640.4mA    255.8mA
-936.6mV  187.6mA    365.2mA    112.5mA
-869.7mV  77.29mA    181mA      42.73mA
-802.8mV  28.91mA    77.52mA    19.98mA
-735.9mV  13.13mA    29.19mA    13.35mA
-669mV    7.755mA    11.55mA    8.955mA
-535.2mV  2.356mA    2.862mA    2.667mA
-334.5mV  34.33uA    127.4uA    15.58uA
3.6V      0A         0A         0A
[Pullup]
| Voltage   I(typ)   I(min)   I(max)
-1.8V     10.52mA    11.01mA    9.844mA
-1.204V   10.25mA    10.42mA    9.975mA
-1.07V    17.07mA    11.83mA    24.22mA
-1.003V   27.79mA    16.51mA    40.63mA
-936.6mV  37.69mA    23.69mA    48.38mA
-869.7mV  41.04mA    29.73mA    48.13mA
-735.9mV  38.64mA    30.94mA    44.85mA
-468.3mV  27.88mA    21.89mA    33.28mA
310.3mV   -16.06mA   -11.9mA    -20mA
806.9mV   -30.95mA   -22.82mA   -38.62mA
1.738V    -40.31mA   -28.81mA   -51.59mA
3.6V      -46.6mA    -32.9mA    -60.57mA
[Pulldown]
| Voltage   I(typ)   I(min)   I(max)
-1.8V     -9.699mA   -11.19mA   -7.41mA
-1.204V   -10.57mA   -11.38mA   -8.544mA
-1.137V   -11.77mA   -11.37mA   -12.78mA
-1.003V   -31.52mA   -19.96mA   -38.21mA
-936.6mV  -38.75mA   -27.41mA   -42.02mA
-869.7mV  -40.37mA   -31.48mA   -43.48mA
-669mV    -38.89mA   -29.93mA   -44.71mA
-401.4mV  -28.41mA   -20.48mA   -35.45mA
248.3mV   16.76mA    10.92mA    22.59mA
558.6mV   27.54mA    18.02mA    36.87mA
1.117V    33.09mA    21.95mA    43.43mA
3.6V      42.42mA    28.69mA    54.44mA
[Ramp]
dV/dt_r   0.74802/0.294503n  0.609572/0.483608n  0.845146/0.206315n
dV/dt_f   0.783247/0.404157n  0.583983/0.637207n  0.90876/0.272278n
R_load = 50
[Rising Waveform]
R_fixture = 50
V_fixture = 0
V_fixture_min = 0
V_fixture_max = 0
| Time   V(typ)   V(min)   V(max)
0s        13.06nV    920.5nV    4.741nV
672.3ps   -7.418mV   -25.04uV   -3.141mV
925.5ps   38.42mV    -8.467mV   344.1mV
1.074ns   161.7mV    -5.669mV   1.012V
1.163ns   244.4mV    2.127mV    1.244V
1.443ns   969.4mV    97.97mV    1.39V
1.697ns   1.189V     255.3mV    1.407V
2.29ns    1.246V     905.8mV    1.409V
3.215ns   1.247V     1.014V     1.408V
50ns      1.247V     1.016V     1.409V
[Rising Waveform]
R_fixture = 50
V_fixture = 1.8
V_fixture_min = 1.66
V_fixture_max = 1.89
| Time   V(typ)   V(min)   V(max)
0s        494.6mV    686.7mV    375.4mV
504.5ps   489mV      683.2mV    411.3mV
545.4ps   488.7mV    681.1mV    605.6mV
626.5ps   530.7mV    678.4mV    1.513V
675.2ps   705mV      677.1mV    1.719V
765.8ps   1.479V     681.8mV    1.855V
859.3ps   1.724V     770mV      1.881V
1.049ns   1.795V     1.546V     1.883V
1.362ns   1.794V     1.657V     1.889V
50ns      1.8V       1.66V      1.89V
[Falling Waveform]
R_fixture = 50
V_fixture = 0
V_fixture_min = 0
V_fixture_max = 0
| Time   V(typ)   V(min)   V(max)
0s        1.247V     1.016V     1.409V
417.5ps   1.249V     1.016V     1.375V
488.9ps   1.236V     1.017V     1.22V
554.3ps   1.187V     1.019V     825.2mV
659.3ps   862.8mV    1.007V     148.7mV
768ps     222.2mV    933.5mV    22.03mV
898.5ps   27.41mV    610.2mV    2.402mV
1.065ns   2.475mV    78.72mV    4.438mV
1.374ns   3.89mV     1.637mV    918.8uV
50ns      13.06nV    940.2nV    4.815nV
[Falling Waveform]
R_fixture = 50
V_fixture = 1.8
V_fixture_min = 1.66
V_fixture_max = 1.89
| Time   V(typ)   V(min)   V(max)
0s        1.8V       1.66V      1.89V
595.7ps   1.809V     1.66V      1.919V
960.3ps   1.777V     1.677V     1.725V
1.253ns   1.672V     1.654V     793mV
1.4ns     1.43V      1.636V     521.2mV
1.68ns    851.3mV    1.591V     402.8mV
2.043ns   571.9mV    1.327V     380.1mV
2.736ns   500.6mV    806.8mV    375.2mV
4.216ns   494.3mV    686.8mV    375.5mV
50ns      494.6mV    686.7mV    375.4mV
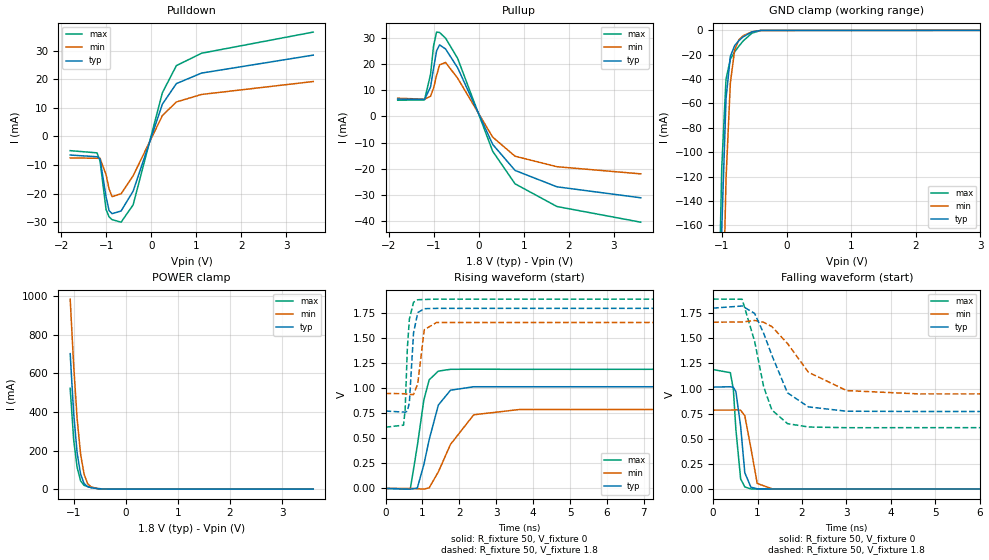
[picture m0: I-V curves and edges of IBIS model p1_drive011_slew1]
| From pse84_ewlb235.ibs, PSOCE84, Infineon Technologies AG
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[Model] p1_drive011_slew1
Model_type I/O
Polarity  Non-Inverting
Enable   Active-High
Vinl  =  0.54
Vinh  =  1.26
Vmeas =  0.9
Cref  =  15pF
| Capacitance   typ   min   max
C_comp   1.187163e-12   1.148471e-12   1.233738e-12
| Variables   typ   min   max
[GND Clamp Reference]   0   0   0
[POWER Clamp Reference]   1.8   1.66   1.89
[Pulldown Reference]   0   0   0
[Pullup Reference]   1.8   1.66   1.89
[Temperature Range]   25   125   -40
[Voltage Range]   1.8   1.66   1.89
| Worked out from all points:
|   slope of the pulldown table from 0 to 0.27 V, typ, clamps not added: 22.5 ohm
|   slope of the pullup table from 0 to 0.27 V, typ, clamps not added: 28.6 ohm
|   GND clamp passes 1 mA (typ) near -0.51 V on its own axis
|   POWER clamp passes 1 mA (typ) near -0.47 V on its own axis
|   rising waveform, R_fixture 50, V_fixture 0: 20-80 % time 393ps typ, 625ps min, 276ps max; typ from 0 V to 1.01 V
|   rising waveform, R_fixture 50, V_fixture 1.8: 20-80 % time 97.8ps typ, 116ps min, 89.5ps max; typ from 0.772 V to 1.8 V
|   falling waveform, R_fixture 50, V_fixture 0: 20-80 % time 119ps typ, 148ps min, 106ps max; typ from 1.01 V to 0 V
|   falling waveform, R_fixture 50, V_fixture 1.8: 20-80 % time 547ps typ, 792ps min, 400ps max; typ from 1.8 V to 0.772 V
[GND Clamp]
| Voltage   I(typ)   I(min)   I(max)
-1.137V   -618.8mA   -753.3mA   -532.4mA
-1.07V    -360.9mA   -497.6mA   -281.1mA
-1.003V   -163.7mA   -277.5mA   -113mA
-936.6mV  -56.21mA   -122.2mA   -40.06mA
-869.7mV  -21.33mA   -43.29mA   -23.66mA
-802.8mV  -12.5mA    -15.96mA   -17.71mA
-735.9mV  -8.345mA   -7.674mA   -12.88mA
-669mV    -5.267mA   -4.349mA   -8.574mA
-535.2mV  -1.314mA   -1.207mA   -2.328mA
-401.4mV  -73.55uA   -132.2uA   -119.3uA
3.6V      0A         0A         0A
[POWER Clamp]
| Voltage   I(typ)   I(min)   I(max)
-1.07V    700.8mA    983.4mA    521.5mA
-1.003V   391.6mA    640.4mA    255.8mA
-936.6mV  187.6mA    365.2mA    112.5mA
-869.7mV  77.29mA    181mA      42.73mA
-802.8mV  28.91mA    77.52mA    19.98mA
-735.9mV  13.13mA    29.19mA    13.35mA
-669mV    7.755mA    11.55mA    8.955mA
-535.2mV  2.356mA    2.862mA    2.667mA
-334.5mV  34.33uA    127.4uA    15.58uA
3.6V      0A         0A         0A
[Pullup]
| Voltage   I(typ)   I(min)   I(max)
-1.8V     6.598mA    6.914mA    6.156mA
-1.204V   6.428mA    6.559mA    6.301mA
-1.07V    11.23mA    7.685mA    16.01mA
-1.003V   18.3mA     10.82mA    26.88mA
-936.6mV  24.93mA    15.55mA    32.1mA
-869.7mV  27.23mA    19.63mA    31.95mA
-735.9mV  25.66mA    20.54mA    29.78mA
-468.3mV  18.51mA    14.54mA    22.08mA
310.3mV   -10.66mA   -7.904mA   -13.27mA
806.9mV   -20.57mA   -15.17mA   -25.67mA
1.738V    -26.81mA   -19.16mA   -34.31mA
3.6V      -30.99mA   -21.88mA   -40.28mA
[Pulldown]
| Voltage   I(typ)   I(min)   I(max)
-1.8V     -6.491mA   -7.49mA    -4.957mA
-1.204V   -7.079mA   -7.618mA   -5.722mA
-1.137V   -7.867mA   -7.617mA   -8.539mA
-1.003V   -21.08mA   -13.35mA   -25.54mA
-936.6mV  -25.92mA   -18.33mA   -28.1mA
-869.7mV  -27.01mA   -21.06mA   -29.09mA
-669mV    -26.07mA   -20.04mA   -29.99mA
-401.4mV  -19.12mA   -13.74mA   -23.92mA
248.3mV   11.31mA    7.339mA    15.31mA
558.6mV   18.5mA     12.08mA    24.79mA
1.117V    22.19mA    14.71mA    29.13mA
3.6V      28.48mA    19.24mA    36.54mA
[Ramp]
dV/dt_r   0.608838/0.393104n  0.47156/0.625285n  0.713647/0.276338n
dV/dt_f   0.616578/0.547073n  0.426942/0.792053n  0.767235/0.400348n
R_load = 50
[Rising Waveform]
R_fixture = 50
V_fixture = 0
V_fixture_min = 0
V_fixture_max = 0
| Time   V(typ)   V(min)   V(max)
0s        17.55nV    1.202uV    6.463nV
671.4ps   -7.033mV   -7.136uV   -3.741mV
860.3ps   3.96mV     -3.013mV   424.4mV
1.038ns   238.5mV    -6.745mV   883.3mV
1.182ns   487mV      6.685mV    1.084V
1.43ns    831.9mV    165mV      1.171V
1.76ns    980.6mV    440mV      1.189V
2.389ns   1.015V     735.2mV    1.19V
3.622ns   1.015V     787.7mV    1.189V
50ns      1.015V     785.9mV    1.189V
[Rising Waveform]
R_fixture = 50
V_fixture = 1.8
V_fixture_min = 1.66
V_fixture_max = 1.89
| Time   V(typ)   V(min)   V(max)
0s        772.4mV    948.4mV    611.3mV
487.3ps   762.4mV    945.7mV    631.7mV
530.9ps   760.6mV    942.7mV    785.7mV
591.5ps   770.7mV    939.6mV    1.404V
645.6ps   857mV      937.4mV    1.689V
758.5ps   1.553V     937.7mV    1.859V
872.7ps   1.755V     1.046V     1.883V
1.048ns   1.794V     1.584V     1.886V
1.381ns   1.797V     1.656V     1.889V
50ns      1.8V       1.66V      1.89V
[Falling Waveform]
R_fixture = 50
V_fixture = 0
V_fixture_min = 0
V_fixture_max = 0
| Time   V(typ)   V(min)   V(max)
0s        1.015V     785.9mV    1.189V
389.6ps   1.018V     785.9mV    1.158V
456.9ps   1.012V     787mV      988.4mV
513.6ps   970.1mV    789.4mV    592.7mV
620.2ps   625mV      783.9mV    102.6mV
713.7ps   164mV      729.8mV    22.36mV
851.7ps   19.41mV    407.2mV    2.291mV
993.4ps   3.591mV    56.76mV    2.188mV
1.338ns   1.703mV    2.041mV    577.1uV
50ns      17.5nV     1.208uV    6.47nV
[Falling Waveform]
R_fixture = 50
V_fixture = 1.8
V_fixture_min = 1.66
V_fixture_max = 1.89
| Time   V(typ)   V(min)   V(max)
0s        1.8V       1.66V      1.89V
655ps     1.821V     1.662V     1.888V
935.9ps   1.747V     1.677V     1.468V
1.139ns   1.548V     1.659V     1.017V
1.323ns   1.331V     1.616V     787.1mV
1.674ns   958.1mV    1.449V     651.7mV
2.145ns   817.9mV    1.162V     617.9mV
3.008ns   774.8mV    980mV      611.1mV
4.621ns   772.2mV    947.2mV    611.3mV
50ns      772.4mV    948.4mV    611.3mV
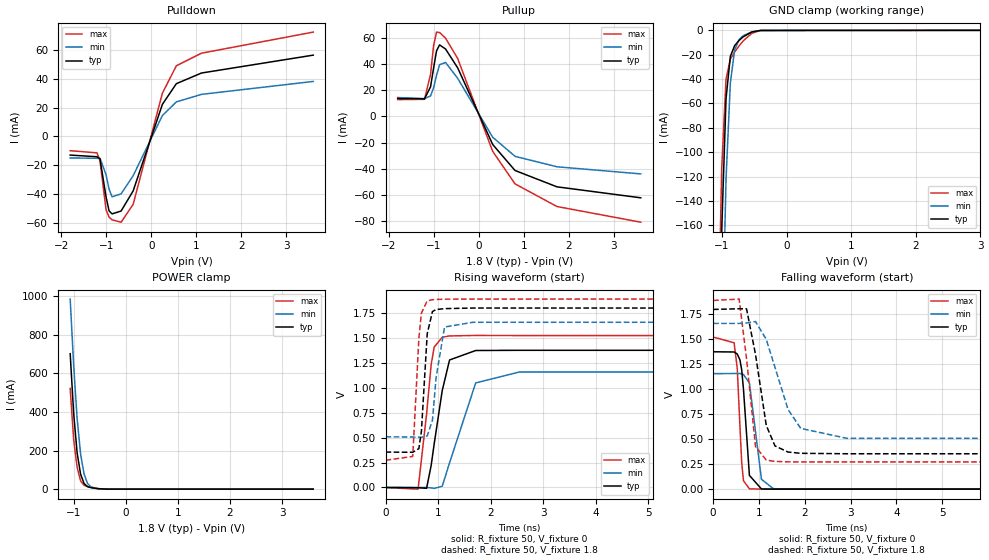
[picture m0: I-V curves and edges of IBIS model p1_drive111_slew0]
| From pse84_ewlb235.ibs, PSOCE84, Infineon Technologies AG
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[Model] p1_drive111_slew0
Model_type I/O
Polarity  Non-Inverting
Enable   Active-High
Vinl  =  0.54
Vinh  =  1.26
Vmeas =  0.9
Cref  =  15pF
| Capacitance   typ   min   max
C_comp   1.187163e-12   1.148471e-12   1.233738e-12
| Variables   typ   min   max
[GND Clamp Reference]   0   0   0
[POWER Clamp Reference]   1.8   1.66   1.89
[Pulldown Reference]   0   0   0
[Pullup Reference]   1.8   1.66   1.89
[Temperature Range]   25   125   -40
[Voltage Range]   1.8   1.66   1.89
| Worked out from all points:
|   slope of the pulldown table from 0 to 0.27 V, typ, clamps not added: 11.4 ohm
|   slope of the pullup table from 0 to 0.27 V, typ, clamps not added: 14.3 ohm
|   GND clamp passes 1 mA (typ) near -0.51 V on its own axis
|   POWER clamp passes 1 mA (typ) near -0.47 V on its own axis
|   rising waveform, R_fixture 50, V_fixture 0: 20-80 % time 236ps typ, 383ps min, 165ps max; typ from 0 V to 1.38 V
|   rising waveform, R_fixture 50, V_fixture 1.8: 20-80 % time 94.4ps typ, 115ps min, 85.1ps max; typ from 0.355 V to 1.8 V
|   falling waveform, R_fixture 50, V_fixture 0: 20-80 % time 116ps typ, 155ps min, 93.5ps max; typ from 1.38 V to 0 V
|   falling waveform, R_fixture 50, V_fixture 1.8: 20-80 % time 286ps typ, 481ps min, 189ps max; typ from 1.8 V to 0.355 V
[GND Clamp]
| Voltage   I(typ)   I(min)   I(max)
-1.137V   -618.8mA   -753.3mA   -532.4mA
-1.07V    -360.9mA   -497.6mA   -281.1mA
-1.003V   -163.7mA   -277.5mA   -113mA
-936.6mV  -56.21mA   -122.2mA   -40.06mA
-869.7mV  -21.33mA   -43.29mA   -23.66mA
-802.8mV  -12.5mA    -15.96mA   -17.71mA
-735.9mV  -8.345mA   -7.674mA   -12.88mA
-669mV    -5.267mA   -4.349mA   -8.574mA
-535.2mV  -1.314mA   -1.207mA   -2.328mA
-401.4mV  -73.55uA   -132.2uA   -119.3uA
3.6V      0A         0A         0A
[POWER Clamp]
| Voltage   I(typ)   I(min)   I(max)
-1.07V    700.8mA    983.4mA    521.5mA
-1.003V   391.6mA    640.4mA    255.8mA
-936.6mV  187.6mA    365.2mA    112.5mA
-869.7mV  77.29mA    181mA      42.73mA
-802.8mV  28.91mA    77.52mA    19.98mA
-735.9mV  13.13mA    29.19mA    13.35mA
-669mV    7.755mA    11.55mA    8.955mA
-535.2mV  2.356mA    2.862mA    2.667mA
-334.5mV  34.33uA    127.4uA    15.58uA
3.6V      0A         0A         0A
[Pullup]
| Voltage   I(typ)   I(min)   I(max)
-1.8V     13.79mA    14.43mA    12.89mA
-1.204V   13.43mA    13.67mA    13.1mA
-1.07V    22.67mA    15.66mA    32.22mA
-1.003V   36.92mA    21.92mA    54.06mA
-936.6mV  50.14mA    31.45mA    64.41mA
-869.7mV  54.65mA    39.53mA    64.09mA
-735.9mV  51.46mA    41.21mA    59.72mA
-468.3mV  37.13mA    29.15mA    44.3mA
310.3mV   -21.39mA   -15.85mA   -26.63mA
806.9mV   -41.23mA   -30.41mA   -51.44mA
1.738V    -53.7mA    -38.39mA   -68.73mA
3.6V      -62.08mA   -43.84mA   -80.69mA
[Pulldown]
| Voltage   I(typ)   I(min)   I(max)
-1.8V     -12.93mA   -14.92mA   -9.879mA
-1.204V   -14.09mA   -15.17mA   -11.39mA
-1.137V   -15.69mA   -15.16mA   -17.04mA
-1.003V   -42.01mA   -26.61mA   -50.92mA
-936.6mV  -51.65mA   -36.53mA   -56mA
-869.7mV  -53.8mA    -41.96mA   -57.94mA
-669mV    -51.82mA   -39.89mA   -59.57mA
-401.4mV  -37.85mA   -27.29mA   -47.2mA
248.3mV   22.31mA    14.55mA    30.07mA
558.6mV   36.69mA    24.02mA    49.12mA
1.117V    44.09mA    29.26mA    57.87mA
3.6V      56.52mA    38.24mA    72.54mA
[Ramp]
dV/dt_r   0.825458/0.236126n  0.694195/0.383209n  0.914656/0.164806n
dV/dt_f   0.867008/0.286478n  0.690896/0.481479n  0.970345/0.189228n
R_load = 50
[Rising Waveform]
R_fixture = 50
V_fixture = 0
V_fixture_min = 0
V_fixture_max = 0
| Time   V(typ)   V(min)   V(max)
0s        10.35nV    743.5nV    3.717nV
618.6ps   -2.618mV   2.499uV    -17mV
780.4ps   -8.186mV   -772.1uV   737.6mV
867.8ps   222mV      -3.963mV   1.235V
924.6ps   436.7mV    -9.511mV   1.408V
1.078ns   972.6mV    12.24mV    1.507V
1.217ns   1.279V     247.1mV    1.52V
1.714ns   1.374V     1.049V     1.525V
2.542ns   1.376V     1.158V     1.524V
50ns      1.376V     1.157V     1.524V
[Rising Waveform]
R_fixture = 50
V_fixture = 1.8
V_fixture_min = 1.66
V_fixture_max = 1.89
| Time   V(typ)   V(min)   V(max)
0s        355mV      508.5mV    272.8mV
517.3ps   352.9mV    505.9mV    311.4mV
633.7ps   389.8mV    504.3mV    1.496V
681.5ps   560.9mV    504mV      1.748V
792.6ps   1.542V     517.1mV    1.873V
892.1ps   1.765V     675.6mV    1.883V
961.2ps   1.785V     1.104V     1.886V
1.121ns   1.794V     1.609V     1.889V
1.664ns   1.8V       1.657V     1.89V
50ns      1.8V       1.66V      1.89V
[Falling Waveform]
R_fixture = 50
V_fixture = 0
V_fixture_min = 0
V_fixture_max = 0
| Time   V(typ)   V(min)   V(max)
0s        1.376V     1.157V     1.524V
459.2ps   1.374V     1.158V     1.466V
527.6ps   1.354V     1.158V     1.211V
587.1ps   1.294V     1.158V     624.6mV
625.4ps   1.192V     1.155V     264.1mV
663.7ps   1.001V     1.148V     84.8mV
793.4ps   137.9mV    1.063V     3.062mV
1.056ns   2.122mV    99.01mV    699.3uV
1.32ns    670.6uV    3.636mV    260.5uV
50ns      10.33nV    826.8nV    3.713nV
[Falling Waveform]
R_fixture = 50
V_fixture = 1.8
V_fixture_min = 1.66
V_fixture_max = 1.89
| Time   V(typ)   V(min)   V(max)
0s        1.8V       1.66V      1.89V
569ps     1.807V     1.66V      1.904V
730.7ps   1.806V     1.664V     1.306V
926.4ps   1.349V     1.679V     426.9mV
1.161ns   639.1mV    1.5V       291.3mV
1.351ns   433.5mV    1.221V     278.1mV
1.636ns   371.8mV    799.1mV    273.7mV
1.913ns   359.1mV    608.9mV    272.8mV
2.918ns   354.6mV    509.2mV    272.8mV
50ns      355mV      508.5mV    272.8mV
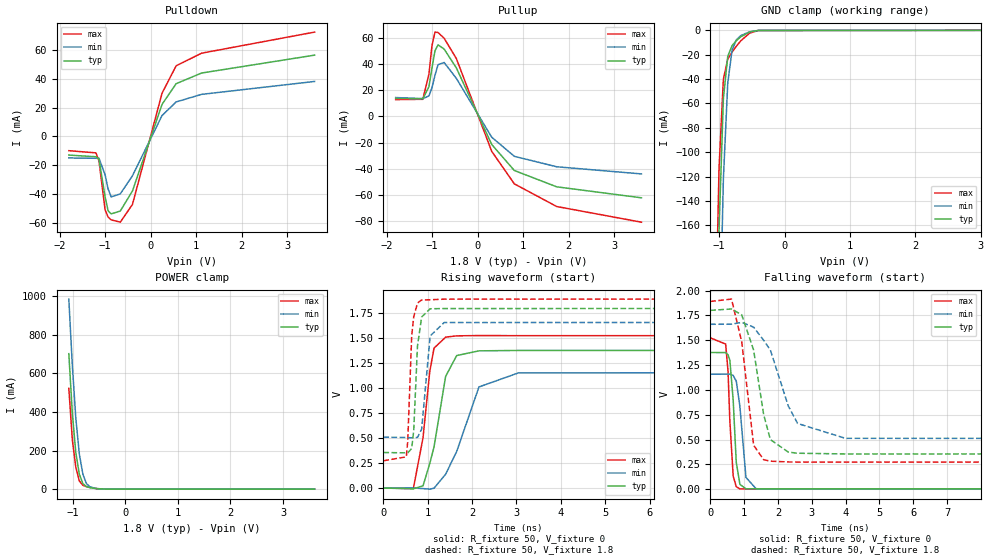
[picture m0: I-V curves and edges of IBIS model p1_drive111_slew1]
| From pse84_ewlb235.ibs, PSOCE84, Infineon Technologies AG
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[Model] p1_drive111_slew1
Model_type I/O
Polarity  Non-Inverting
Enable   Active-High
Vinl  =  0.54
Vinh  =  1.26
Vmeas =  0.9
Cref  =  15pF
| Capacitance   typ   min   max
C_comp   1.187163e-12   1.148471e-12   1.233738e-12
| Variables   typ   min   max
[GND Clamp Reference]   0   0   0
[POWER Clamp Reference]   1.8   1.66   1.89
[Pulldown Reference]   0   0   0
[Pullup Reference]   1.8   1.66   1.89
[Temperature Range]   25   125   -40
[Voltage Range]   1.8   1.66   1.89
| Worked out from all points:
|   slope of the pulldown table from 0 to 0.27 V, typ, clamps not added: 11.4 ohm
|   slope of the pullup table from 0 to 0.27 V, typ, clamps not added: 14.3 ohm
|   GND clamp passes 1 mA (typ) near -0.51 V on its own axis
|   POWER clamp passes 1 mA (typ) near -0.47 V on its own axis
|   rising waveform, R_fixture 50, V_fixture 0: 20-80 % time 333ps typ, 529ps min, 238ps max; typ from 0 V to 1.38 V
|   rising waveform, R_fixture 50, V_fixture 1.8: 20-80 % time 94.2ps typ, 114ps min, 86.1ps max; typ from 0.355 V to 1.8 V
|   falling waveform, R_fixture 50, V_fixture 0: 20-80 % time 126ps typ, 161ps min, 108ps max; typ from 1.38 V to 0 V
|   falling waveform, R_fixture 50, V_fixture 1.8: 20-80 % time 462ps typ, 717ps min, 330ps max; typ from 1.8 V to 0.355 V
[GND Clamp]
| Voltage   I(typ)   I(min)   I(max)
-1.137V   -618.8mA   -753.3mA   -532.4mA
-1.07V    -360.9mA   -497.6mA   -281.1mA
-1.003V   -163.7mA   -277.5mA   -113mA
-936.6mV  -56.21mA   -122.2mA   -40.06mA
-869.7mV  -21.33mA   -43.29mA   -23.66mA
-802.8mV  -12.5mA    -15.96mA   -17.71mA
-735.9mV  -8.345mA   -7.674mA   -12.88mA
-669mV    -5.267mA   -4.349mA   -8.574mA
-535.2mV  -1.314mA   -1.207mA   -2.328mA
-401.4mV  -73.55uA   -132.2uA   -119.3uA
3.6V      0A         0A         0A
[POWER Clamp]
| Voltage   I(typ)   I(min)   I(max)
-1.07V    700.8mA    983.4mA    521.5mA
-1.003V   391.6mA    640.4mA    255.8mA
-936.6mV  187.6mA    365.2mA    112.5mA
-869.7mV  77.29mA    181mA      42.73mA
-802.8mV  28.91mA    77.52mA    19.98mA
-735.9mV  13.13mA    29.19mA    13.35mA
-669mV    7.755mA    11.55mA    8.955mA
-535.2mV  2.356mA    2.862mA    2.667mA
-334.5mV  34.33uA    127.4uA    15.58uA
3.6V      0A         0A         0A
[Pullup]
| Voltage   I(typ)   I(min)   I(max)
-1.8V     13.79mA    14.43mA    12.89mA
-1.204V   13.43mA    13.67mA    13.1mA
-1.07V    22.67mA    15.66mA    32.22mA
-1.003V   36.92mA    21.92mA    54.06mA
-936.6mV  50.14mA    31.45mA    64.41mA
-869.7mV  54.65mA    39.53mA    64.09mA
-735.9mV  51.46mA    41.21mA    59.72mA
-468.3mV  37.13mA    29.15mA    44.3mA
310.3mV   -21.39mA   -15.85mA   -26.63mA
806.9mV   -41.23mA   -30.41mA   -51.44mA
1.738V    -53.7mA    -38.39mA   -68.73mA
3.6V      -62.08mA   -43.84mA   -80.69mA
[Pulldown]
| Voltage   I(typ)   I(min)   I(max)
-1.8V     -12.93mA   -14.92mA   -9.879mA
-1.204V   -14.09mA   -15.17mA   -11.39mA
-1.137V   -15.69mA   -15.16mA   -17.04mA
-1.003V   -42.01mA   -26.61mA   -50.92mA
-936.6mV  -51.65mA   -36.53mA   -56mA
-869.7mV  -53.8mA    -41.96mA   -57.94mA
-669mV    -51.82mA   -39.89mA   -59.57mA
-401.4mV  -37.85mA   -27.29mA   -47.2mA
248.3mV   22.31mA    14.55mA    30.07mA
558.6mV   36.69mA    24.02mA    49.12mA
1.117V    44.09mA    29.26mA    57.87mA
3.6V      56.52mA    38.24mA    72.54mA
[Ramp]
dV/dt_r   0.825458/0.333053n  0.694194/0.529205n  0.914656/0.237511n
dV/dt_f   0.867008/0.461943n  0.690895/0.717176n  0.970345/0.330173n
R_load = 50
[Rising Waveform]
R_fixture = 50
V_fixture = 0
V_fixture_min = 0
V_fixture_max = 0
| Time   V(typ)   V(min)   V(max)
0s        10.35nV    743.5nV    3.717nV
675.2ps   -8.333mV   -25.49uV   -5.749mV
892.9ps   21.75mV    -5.774mV   501.8mV
1.045ns   244.7mV    -11.5mV    1.164V
1.141ns   410.7mV    -2.105mV   1.399V
1.403ns   1.117V     138.1mV    1.509V
1.652ns   1.325V     365.8mV    1.522V
2.154ns   1.372V     1.011V     1.525V
3.047ns   1.376V     1.152V     1.524V
50ns      1.376V     1.157V     1.524V
[Rising Waveform]
R_fixture = 50
V_fixture = 1.8
V_fixture_min = 1.66
V_fixture_max = 1.89
| Time   V(typ)   V(min)   V(max)
0s        355mV      508.5mV    272.8mV
517.1ps   351.8mV    505.2mV    311.6mV
549.1ps   351.8mV    504.2mV    471mV
638.2ps   395.7mV    502.3mV    1.525V
683.4ps   575.1mV    501.5mV    1.713V
768.5ps   1.422V     506.2mV    1.85V
862.4ps   1.711V     589.5mV    1.881V
1.054ns   1.793V     1.521V     1.883V
1.369ns   1.795V     1.655V     1.889V
50ns      1.8V       1.66V      1.89V
[Falling Waveform]
R_fixture = 50
V_fixture = 0
V_fixture_min = 0
V_fixture_max = 0
| Time   V(typ)   V(min)   V(max)
0s        1.376V     1.157V     1.524V
454.1ps   1.375V     1.158V     1.461V
523.9ps   1.354V     1.159V     1.191V
579.1ps   1.297V     1.159V     680.9mV
676.8ps   897.6mV    1.145V     132.8mV
767.6ps   271.9mV    1.088V     25.24mV
875.4ps   48.21mV    831.5mV    2.726mV
1.054ns   3.463mV    118.1mV    3.655mV
1.359ns   3.291mV    2.718mV    947.5uV
50ns      10.32nV    760nV      3.706nV
[Falling Waveform]
R_fixture = 50
V_fixture = 1.8
V_fixture_min = 1.66
V_fixture_max = 1.89
| Time   V(typ)   V(min)   V(max)
0s        1.8V       1.66V      1.89V
627ps     1.814V     1.661V     1.914V
929.8ps   1.755V     1.679V     1.483V
1.281ns   1.4V       1.631V     442.1mV
1.577ns   750.9mV    1.499V     296.9mV
1.775ns   499.1mV    1.401V     282mV
2.305ns   373.3mV    837.8mV    273.7mV
2.582ns   361.8mV    661.2mV    272.9mV
3.994ns   354.7mV    511.8mV    272.8mV
50ns      355mV      508.5mV    272.8mV
